VERSION 5.8 ;
BUSBITCHARS "[]" ;
DIVIDERCHAR "/" ;
UNITS
    DATABASE MICRONS 1000 ;
END UNITS

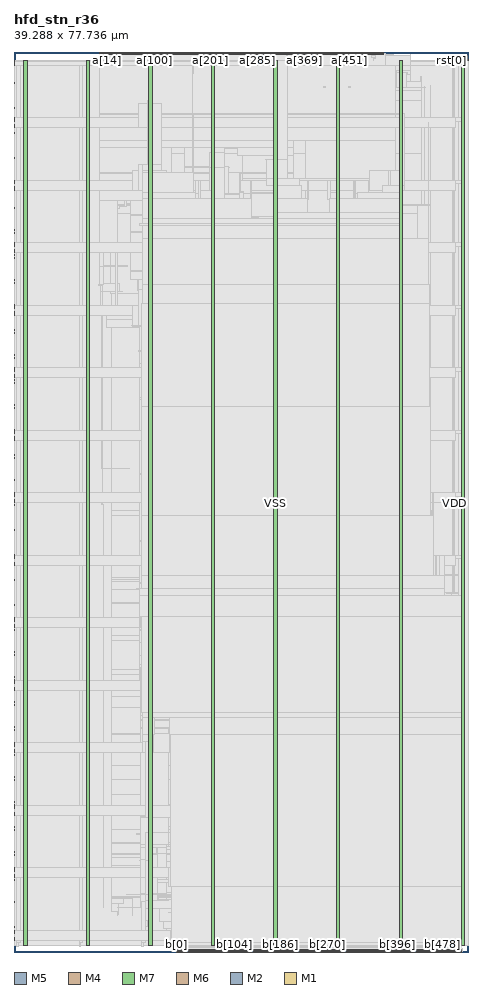
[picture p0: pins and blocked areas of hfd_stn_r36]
MACRO hfd_stn_r36
  FOREIGN hfd_stn_r36 0 0 ;
  CLASS BLOCK ;
  SIZE 39.288 BY 77.736 ;
  PIN a[0]
    DIRECTION INPUT ;
    USE SIGNAL ;
    PORT
      LAYER M5 ;
        RECT  7.344 77.544 7.368 77.736 ;
    END
  END a[0]
  PIN a[100]
    DIRECTION INPUT ;
    USE SIGNAL ;
    PORT
      LAYER M5 ;
        RECT  12.144 77.544 12.168 77.736 ;
    END
  END a[100]
  PIN a[101]
    DIRECTION INPUT ;
    USE SIGNAL ;
    PORT
      LAYER M5 ;
        RECT  12.192 77.544 12.216 77.736 ;
    END
  END a[101]
  PIN a[102]
    DIRECTION INPUT ;
    USE SIGNAL ;
    PORT
      LAYER M5 ;
        RECT  12.24 77.544 12.264 77.736 ;
    END
  END a[102]
  PIN a[103]
    DIRECTION INPUT ;
    USE SIGNAL ;
    PORT
      LAYER M5 ;
        RECT  12.288 77.544 12.312 77.736 ;
    END
  END a[103]
  PIN a[104]
    DIRECTION INPUT ;
    USE SIGNAL ;
    PORT
      LAYER M5 ;
        RECT  12.336 77.544 12.36 77.736 ;
    END
  END a[104]
  PIN a[105]
    DIRECTION INPUT ;
    USE SIGNAL ;
    PORT
      LAYER M5 ;
        RECT  12.384 77.544 12.408 77.736 ;
    END
  END a[105]
  PIN a[106]
    DIRECTION INPUT ;
    USE SIGNAL ;
    PORT
      LAYER M5 ;
        RECT  12.432 77.544 12.456 77.736 ;
    END
  END a[106]
  PIN a[107]
    DIRECTION INPUT ;
    USE SIGNAL ;
    PORT
      LAYER M5 ;
        RECT  12.48 77.544 12.504 77.736 ;
    END
  END a[107]
  PIN a[108]
    DIRECTION INPUT ;
    USE SIGNAL ;
    PORT
      LAYER M5 ;
        RECT  12.528 77.544 12.552 77.736 ;
    END
  END a[108]
  PIN a[109]
    DIRECTION INPUT ;
    USE SIGNAL ;
    PORT
      LAYER M5 ;
        RECT  12.576 77.544 12.6 77.736 ;
    END
  END a[109]
  PIN a[10]
    DIRECTION INPUT ;
    USE SIGNAL ;
    PORT
      LAYER M5 ;
        RECT  7.824 77.544 7.848 77.736 ;
    END
  END a[10]
  PIN a[110]
    DIRECTION INPUT ;
    USE SIGNAL ;
    PORT
      LAYER M5 ;
        RECT  12.624 77.544 12.648 77.736 ;
    END
  END a[110]
  PIN a[111]
    DIRECTION INPUT ;
    USE SIGNAL ;
    PORT
      LAYER M5 ;
        RECT  12.672 77.544 12.696 77.736 ;
    END
  END a[111]
  PIN a[112]
    DIRECTION INPUT ;
    USE SIGNAL ;
    PORT
      LAYER M5 ;
        RECT  12.72 77.544 12.744 77.736 ;
    END
  END a[112]
  PIN a[113]
    DIRECTION INPUT ;
    USE SIGNAL ;
    PORT
      LAYER M5 ;
        RECT  12.768 77.544 12.792 77.736 ;
    END
  END a[113]
  PIN a[114]
    DIRECTION INPUT ;
    USE SIGNAL ;
    PORT
      LAYER M5 ;
        RECT  12.816 77.544 12.84 77.736 ;
    END
  END a[114]
  PIN a[115]
    DIRECTION INPUT ;
    USE SIGNAL ;
    PORT
      LAYER M5 ;
        RECT  12.864 77.544 12.888 77.736 ;
    END
  END a[115]
  PIN a[116]
    DIRECTION INPUT ;
    USE SIGNAL ;
    PORT
      LAYER M5 ;
        RECT  12.912 77.544 12.936 77.736 ;
    END
  END a[116]
  PIN a[117]
    DIRECTION INPUT ;
    USE SIGNAL ;
    PORT
      LAYER M5 ;
        RECT  12.96 77.544 12.984 77.736 ;
    END
  END a[117]
  PIN a[118]
    DIRECTION INPUT ;
    USE SIGNAL ;
    PORT
      LAYER M5 ;
        RECT  13.008 77.544 13.032 77.736 ;
    END
  END a[118]
  PIN a[119]
    DIRECTION INPUT ;
    USE SIGNAL ;
    PORT
      LAYER M5 ;
        RECT  13.056 77.544 13.08 77.736 ;
    END
  END a[119]
  PIN a[11]
    DIRECTION INPUT ;
    USE SIGNAL ;
    PORT
      LAYER M5 ;
        RECT  7.872 77.544 7.896 77.736 ;
    END
  END a[11]
  PIN a[120]
    DIRECTION INPUT ;
    USE SIGNAL ;
    PORT
      LAYER M5 ;
        RECT  13.104 77.544 13.128 77.736 ;
    END
  END a[120]
  PIN a[121]
    DIRECTION INPUT ;
    USE SIGNAL ;
    PORT
      LAYER M5 ;
        RECT  13.152 77.544 13.176 77.736 ;
    END
  END a[121]
  PIN a[122]
    DIRECTION INPUT ;
    USE SIGNAL ;
    PORT
      LAYER M5 ;
        RECT  13.2 77.544 13.224 77.736 ;
    END
  END a[122]
  PIN a[123]
    DIRECTION INPUT ;
    USE SIGNAL ;
    PORT
      LAYER M5 ;
        RECT  13.248 77.544 13.272 77.736 ;
    END
  END a[123]
  PIN a[124]
    DIRECTION INPUT ;
    USE SIGNAL ;
    PORT
      LAYER M5 ;
        RECT  13.296 77.544 13.32 77.736 ;
    END
  END a[124]
  PIN a[125]
    DIRECTION INPUT ;
    USE SIGNAL ;
    PORT
      LAYER M5 ;
        RECT  13.344 77.544 13.368 77.736 ;
    END
  END a[125]
  PIN a[126]
    DIRECTION INPUT ;
    USE SIGNAL ;
    PORT
      LAYER M5 ;
        RECT  13.392 77.544 13.416 77.736 ;
    END
  END a[126]
  PIN a[127]
    DIRECTION INPUT ;
    USE SIGNAL ;
    PORT
      LAYER M5 ;
        RECT  13.44 77.544 13.464 77.736 ;
    END
  END a[127]
  PIN a[128]
    DIRECTION INPUT ;
    USE SIGNAL ;
    PORT
      LAYER M5 ;
        RECT  13.488 77.544 13.512 77.736 ;
    END
  END a[128]
  PIN a[129]
    DIRECTION INPUT ;
    USE SIGNAL ;
    PORT
      LAYER M5 ;
        RECT  13.536 77.544 13.56 77.736 ;
    END
  END a[129]
  PIN a[12]
    DIRECTION INPUT ;
    USE SIGNAL ;
    PORT
      LAYER M5 ;
        RECT  7.92 77.544 7.944 77.736 ;
    END
  END a[12]
  PIN a[130]
    DIRECTION INPUT ;
    USE SIGNAL ;
    PORT
      LAYER M5 ;
        RECT  13.584 77.544 13.608 77.736 ;
    END
  END a[130]
  PIN a[131]
    DIRECTION INPUT ;
    USE SIGNAL ;
    PORT
      LAYER M5 ;
        RECT  13.632 77.544 13.656 77.736 ;
    END
  END a[131]
  PIN a[132]
    DIRECTION INPUT ;
    USE SIGNAL ;
    PORT
      LAYER M5 ;
        RECT  13.68 77.544 13.704 77.736 ;
    END
  END a[132]
  PIN a[133]
    DIRECTION INPUT ;
    USE SIGNAL ;
    PORT
      LAYER M5 ;
        RECT  13.728 77.544 13.752 77.736 ;
    END
  END a[133]
  PIN a[134]
    DIRECTION INPUT ;
    USE SIGNAL ;
    PORT
      LAYER M5 ;
        RECT  13.776 77.544 13.8 77.736 ;
    END
  END a[134]
  PIN a[135]
    DIRECTION INPUT ;
    USE SIGNAL ;
    PORT
      LAYER M5 ;
        RECT  13.824 77.544 13.848 77.736 ;
    END
  END a[135]
  PIN a[136]
    DIRECTION INPUT ;
    USE SIGNAL ;
    PORT
      LAYER M5 ;
        RECT  13.872 77.544 13.896 77.736 ;
    END
  END a[136]
  PIN a[137]
    DIRECTION INPUT ;
    USE SIGNAL ;
    PORT
      LAYER M5 ;
        RECT  13.92 77.544 13.944 77.736 ;
    END
  END a[137]
  PIN a[138]
    DIRECTION INPUT ;
    USE SIGNAL ;
    PORT
      LAYER M5 ;
        RECT  13.968 77.544 13.992 77.736 ;
    END
  END a[138]
  PIN a[139]
    DIRECTION INPUT ;
    USE SIGNAL ;
    PORT
      LAYER M5 ;
        RECT  14.016 77.544 14.04 77.736 ;
    END
  END a[139]
  PIN a[13]
    DIRECTION INPUT ;
    USE SIGNAL ;
    PORT
      LAYER M5 ;
        RECT  7.968 77.544 7.992 77.736 ;
    END
  END a[13]
  PIN a[140]
    DIRECTION INPUT ;
    USE SIGNAL ;
    PORT
      LAYER M5 ;
        RECT  14.064 77.544 14.088 77.736 ;
    END
  END a[140]
  PIN a[141]
    DIRECTION INPUT ;
    USE SIGNAL ;
    PORT
      LAYER M5 ;
        RECT  14.112 77.544 14.136 77.736 ;
    END
  END a[141]
  PIN a[142]
    DIRECTION INPUT ;
    USE SIGNAL ;
    PORT
      LAYER M5 ;
        RECT  14.16 77.544 14.184 77.736 ;
    END
  END a[142]
  PIN a[143]
    DIRECTION INPUT ;
    USE SIGNAL ;
    PORT
      LAYER M5 ;
        RECT  14.208 77.544 14.232 77.736 ;
    END
  END a[143]
  PIN a[144]
    DIRECTION INPUT ;
    USE SIGNAL ;
    PORT
      LAYER M5 ;
        RECT  14.256 77.544 14.28 77.736 ;
    END
  END a[144]
  PIN a[145]
    DIRECTION INPUT ;
    USE SIGNAL ;
    PORT
      LAYER M5 ;
        RECT  14.304 77.544 14.328 77.736 ;
    END
  END a[145]
  PIN a[146]
    DIRECTION INPUT ;
    USE SIGNAL ;
    PORT
      LAYER M5 ;
        RECT  14.352 77.544 14.376 77.736 ;
    END
  END a[146]
  PIN a[147]
    DIRECTION INPUT ;
    USE SIGNAL ;
    PORT
      LAYER M5 ;
        RECT  14.4 77.544 14.424 77.736 ;
    END
  END a[147]
  PIN a[148]
    DIRECTION INPUT ;
    USE SIGNAL ;
    PORT
      LAYER M5 ;
        RECT  14.448 77.544 14.472 77.736 ;
    END
  END a[148]
  PIN a[149]
    DIRECTION INPUT ;
    USE SIGNAL ;
    PORT
      LAYER M5 ;
        RECT  14.496 77.544 14.52 77.736 ;
    END
  END a[149]
  PIN a[14]
    DIRECTION INPUT ;
    USE SIGNAL ;
    PORT
      LAYER M5 ;
        RECT  8.016 77.544 8.04 77.736 ;
    END
  END a[14]
  PIN a[150]
    DIRECTION INPUT ;
    USE SIGNAL ;
    PORT
      LAYER M5 ;
        RECT  14.544 77.544 14.568 77.736 ;
    END
  END a[150]
  PIN a[151]
    DIRECTION INPUT ;
    USE SIGNAL ;
    PORT
      LAYER M5 ;
        RECT  14.592 77.544 14.616 77.736 ;
    END
  END a[151]
  PIN a[152]
    DIRECTION INPUT ;
    USE SIGNAL ;
    PORT
      LAYER M5 ;
        RECT  14.64 77.544 14.664 77.736 ;
    END
  END a[152]
  PIN a[153]
    DIRECTION INPUT ;
    USE SIGNAL ;
    PORT
      LAYER M5 ;
        RECT  14.688 77.544 14.712 77.736 ;
    END
  END a[153]
  PIN a[154]
    DIRECTION INPUT ;
    USE SIGNAL ;
    PORT
      LAYER M5 ;
        RECT  14.736 77.544 14.76 77.736 ;
    END
  END a[154]
  PIN a[155]
    DIRECTION INPUT ;
    USE SIGNAL ;
    PORT
      LAYER M5 ;
        RECT  14.784 77.544 14.808 77.736 ;
    END
  END a[155]
  PIN a[156]
    DIRECTION INPUT ;
    USE SIGNAL ;
    PORT
      LAYER M5 ;
        RECT  14.832 77.544 14.856 77.736 ;
    END
  END a[156]
  PIN a[157]
    DIRECTION INPUT ;
    USE SIGNAL ;
    PORT
      LAYER M5 ;
        RECT  14.88 77.544 14.904 77.736 ;
    END
  END a[157]
  PIN a[158]
    DIRECTION INPUT ;
    USE SIGNAL ;
    PORT
      LAYER M5 ;
        RECT  14.928 77.544 14.952 77.736 ;
    END
  END a[158]
  PIN a[159]
    DIRECTION INPUT ;
    USE SIGNAL ;
    PORT
      LAYER M5 ;
        RECT  14.976 77.544 15 77.736 ;
    END
  END a[159]
  PIN a[15]
    DIRECTION INPUT ;
    USE SIGNAL ;
    PORT
      LAYER M5 ;
        RECT  8.064 77.544 8.088 77.736 ;
    END
  END a[15]
  PIN a[160]
    DIRECTION INPUT ;
    USE SIGNAL ;
    PORT
      LAYER M5 ;
        RECT  15.024 77.544 15.048 77.736 ;
    END
  END a[160]
  PIN a[161]
    DIRECTION INPUT ;
    USE SIGNAL ;
    PORT
      LAYER M5 ;
        RECT  15.072 77.544 15.096 77.736 ;
    END
  END a[161]
  PIN a[162]
    DIRECTION INPUT ;
    USE SIGNAL ;
    PORT
      LAYER M5 ;
        RECT  15.12 77.544 15.144 77.736 ;
    END
  END a[162]
  PIN a[163]
    DIRECTION INPUT ;
    USE SIGNAL ;
    PORT
      LAYER M5 ;
        RECT  15.168 77.544 15.192 77.736 ;
    END
  END a[163]
  PIN a[164]
    DIRECTION INPUT ;
    USE SIGNAL ;
    PORT
      LAYER M5 ;
        RECT  15.216 77.544 15.24 77.736 ;
    END
  END a[164]
  PIN a[165]
    DIRECTION INPUT ;
    USE SIGNAL ;
    PORT
      LAYER M5 ;
        RECT  15.264 77.544 15.288 77.736 ;
    END
  END a[165]
  PIN a[166]
    DIRECTION INPUT ;
    USE SIGNAL ;
    PORT
      LAYER M5 ;
        RECT  15.312 77.544 15.336 77.736 ;
    END
  END a[166]
  PIN a[167]
    DIRECTION INPUT ;
    USE SIGNAL ;
    PORT
      LAYER M5 ;
        RECT  15.36 77.544 15.384 77.736 ;
    END
  END a[167]
  PIN a[168]
    DIRECTION INPUT ;
    USE SIGNAL ;
    PORT
      LAYER M5 ;
        RECT  15.408 77.544 15.432 77.736 ;
    END
  END a[168]
  PIN a[169]
    DIRECTION INPUT ;
    USE SIGNAL ;
    PORT
      LAYER M5 ;
        RECT  15.456 77.544 15.48 77.736 ;
    END
  END a[169]
  PIN a[16]
    DIRECTION INPUT ;
    USE SIGNAL ;
    PORT
      LAYER M5 ;
        RECT  8.112 77.544 8.136 77.736 ;
    END
  END a[16]
  PIN a[170]
    DIRECTION INPUT ;
    USE SIGNAL ;
    PORT
      LAYER M5 ;
        RECT  15.504 77.544 15.528 77.736 ;
    END
  END a[170]
  PIN a[171]
    DIRECTION INPUT ;
    USE SIGNAL ;
    PORT
      LAYER M5 ;
        RECT  15.552 77.544 15.576 77.736 ;
    END
  END a[171]
  PIN a[172]
    DIRECTION INPUT ;
    USE SIGNAL ;
    PORT
      LAYER M5 ;
        RECT  15.6 77.544 15.624 77.736 ;
    END
  END a[172]
  PIN a[173]
    DIRECTION INPUT ;
    USE SIGNAL ;
    PORT
      LAYER M5 ;
        RECT  15.648 77.544 15.672 77.736 ;
    END
  END a[173]
  PIN a[174]
    DIRECTION INPUT ;
    USE SIGNAL ;
    PORT
      LAYER M5 ;
        RECT  15.696 77.544 15.72 77.736 ;
    END
  END a[174]
  PIN a[175]
    DIRECTION INPUT ;
    USE SIGNAL ;
    PORT
      LAYER M5 ;
        RECT  15.744 77.544 15.768 77.736 ;
    END
  END a[175]
  PIN a[176]
    DIRECTION INPUT ;
    USE SIGNAL ;
    PORT
      LAYER M5 ;
        RECT  15.792 77.544 15.816 77.736 ;
    END
  END a[176]
  PIN a[177]
    DIRECTION INPUT ;
    USE SIGNAL ;
    PORT
      LAYER M5 ;
        RECT  15.84 77.544 15.864 77.736 ;
    END
  END a[177]
  PIN a[178]
    DIRECTION INPUT ;
    USE SIGNAL ;
    PORT
      LAYER M5 ;
        RECT  15.888 77.544 15.912 77.736 ;
    END
  END a[178]
  PIN a[179]
    DIRECTION INPUT ;
    USE SIGNAL ;
    PORT
      LAYER M5 ;
        RECT  15.936 77.544 15.96 77.736 ;
    END
  END a[179]
  PIN a[17]
    DIRECTION INPUT ;
    USE SIGNAL ;
    PORT
      LAYER M5 ;
        RECT  8.16 77.544 8.184 77.736 ;
    END
  END a[17]
  PIN a[180]
    DIRECTION INPUT ;
    USE SIGNAL ;
    PORT
      LAYER M5 ;
        RECT  15.984 77.544 16.008 77.736 ;
    END
  END a[180]
  PIN a[181]
    DIRECTION INPUT ;
    USE SIGNAL ;
    PORT
      LAYER M5 ;
        RECT  16.032 77.544 16.056 77.736 ;
    END
  END a[181]
  PIN a[182]
    DIRECTION INPUT ;
    USE SIGNAL ;
    PORT
      LAYER M5 ;
        RECT  16.08 77.544 16.104 77.736 ;
    END
  END a[182]
  PIN a[183]
    DIRECTION INPUT ;
    USE SIGNAL ;
    PORT
      LAYER M5 ;
        RECT  16.128 77.544 16.152 77.736 ;
    END
  END a[183]
  PIN a[184]
    DIRECTION INPUT ;
    USE SIGNAL ;
    PORT
      LAYER M5 ;
        RECT  16.176 77.544 16.2 77.736 ;
    END
  END a[184]
  PIN a[185]
    DIRECTION INPUT ;
    USE SIGNAL ;
    PORT
      LAYER M5 ;
        RECT  16.224 77.544 16.248 77.736 ;
    END
  END a[185]
  PIN a[186]
    DIRECTION INPUT ;
    USE SIGNAL ;
    PORT
      LAYER M5 ;
        RECT  16.272 77.544 16.296 77.736 ;
    END
  END a[186]
  PIN a[187]
    DIRECTION INPUT ;
    USE SIGNAL ;
    PORT
      LAYER M5 ;
        RECT  16.32 77.544 16.344 77.736 ;
    END
  END a[187]
  PIN a[188]
    DIRECTION INPUT ;
    USE SIGNAL ;
    PORT
      LAYER M5 ;
        RECT  16.368 77.544 16.392 77.736 ;
    END
  END a[188]
  PIN a[189]
    DIRECTION INPUT ;
    USE SIGNAL ;
    PORT
      LAYER M5 ;
        RECT  16.416 77.544 16.44 77.736 ;
    END
  END a[189]
  PIN a[18]
    DIRECTION INPUT ;
    USE SIGNAL ;
    PORT
      LAYER M5 ;
        RECT  8.208 77.544 8.232 77.736 ;
    END
  END a[18]
  PIN a[190]
    DIRECTION INPUT ;
    USE SIGNAL ;
    PORT
      LAYER M5 ;
        RECT  16.464 77.544 16.488 77.736 ;
    END
  END a[190]
  PIN a[191]
    DIRECTION INPUT ;
    USE SIGNAL ;
    PORT
      LAYER M5 ;
        RECT  16.512 77.544 16.536 77.736 ;
    END
  END a[191]
  PIN a[192]
    DIRECTION INPUT ;
    USE SIGNAL ;
    PORT
      LAYER M5 ;
        RECT  16.56 77.544 16.584 77.736 ;
    END
  END a[192]
  PIN a[193]
    DIRECTION INPUT ;
    USE SIGNAL ;
    PORT
      LAYER M5 ;
        RECT  16.608 77.544 16.632 77.736 ;
    END
  END a[193]
  PIN a[194]
    DIRECTION INPUT ;
    USE SIGNAL ;
    PORT
      LAYER M5 ;
        RECT  16.656 77.544 16.68 77.736 ;
    END
  END a[194]
  PIN a[195]
    DIRECTION INPUT ;
    USE SIGNAL ;
    PORT
      LAYER M5 ;
        RECT  16.704 77.544 16.728 77.736 ;
    END
  END a[195]
  PIN a[196]
    DIRECTION INPUT ;
    USE SIGNAL ;
    PORT
      LAYER M5 ;
        RECT  16.752 77.544 16.776 77.736 ;
    END
  END a[196]
  PIN a[197]
    DIRECTION INPUT ;
    USE SIGNAL ;
    PORT
      LAYER M5 ;
        RECT  16.8 77.544 16.824 77.736 ;
    END
  END a[197]
  PIN a[198]
    DIRECTION INPUT ;
    USE SIGNAL ;
    PORT
      LAYER M5 ;
        RECT  16.848 77.544 16.872 77.736 ;
    END
  END a[198]
  PIN a[199]
    DIRECTION INPUT ;
    USE SIGNAL ;
    PORT
      LAYER M5 ;
        RECT  16.896 77.544 16.92 77.736 ;
    END
  END a[199]
  PIN a[19]
    DIRECTION INPUT ;
    USE SIGNAL ;
    PORT
      LAYER M5 ;
        RECT  8.256 77.544 8.28 77.736 ;
    END
  END a[19]
  PIN a[1]
    DIRECTION INPUT ;
    USE SIGNAL ;
    PORT
      LAYER M5 ;
        RECT  7.392 77.544 7.416 77.736 ;
    END
  END a[1]
  PIN a[200]
    DIRECTION INPUT ;
    USE SIGNAL ;
    PORT
      LAYER M5 ;
        RECT  16.944 77.544 16.968 77.736 ;
    END
  END a[200]
  PIN a[201]
    DIRECTION INPUT ;
    USE SIGNAL ;
    PORT
      LAYER M5 ;
        RECT  16.992 77.544 17.016 77.736 ;
    END
  END a[201]
  PIN a[202]
    DIRECTION INPUT ;
    USE SIGNAL ;
    PORT
      LAYER M5 ;
        RECT  17.04 77.544 17.064 77.736 ;
    END
  END a[202]
  PIN a[203]
    DIRECTION INPUT ;
    USE SIGNAL ;
    PORT
      LAYER M5 ;
        RECT  17.088 77.544 17.112 77.736 ;
    END
  END a[203]
  PIN a[204]
    DIRECTION INPUT ;
    USE SIGNAL ;
    PORT
      LAYER M5 ;
        RECT  17.136 77.544 17.16 77.736 ;
    END
  END a[204]
  PIN a[205]
    DIRECTION INPUT ;
    USE SIGNAL ;
    PORT
      LAYER M5 ;
        RECT  17.184 77.544 17.208 77.736 ;
    END
  END a[205]
  PIN a[206]
    DIRECTION INPUT ;
    USE SIGNAL ;
    PORT
      LAYER M5 ;
        RECT  17.232 77.544 17.256 77.736 ;
    END
  END a[206]
  PIN a[207]
    DIRECTION INPUT ;
    USE SIGNAL ;
    PORT
      LAYER M5 ;
        RECT  17.28 77.544 17.304 77.736 ;
    END
  END a[207]
  PIN a[208]
    DIRECTION INPUT ;
    USE SIGNAL ;
    PORT
      LAYER M5 ;
        RECT  17.328 77.544 17.352 77.736 ;
    END
  END a[208]
  PIN a[209]
    DIRECTION INPUT ;
    USE SIGNAL ;
    PORT
      LAYER M5 ;
        RECT  17.376 77.544 17.4 77.736 ;
    END
  END a[209]
  PIN a[20]
    DIRECTION INPUT ;
    USE SIGNAL ;
    PORT
      LAYER M5 ;
        RECT  8.304 77.544 8.328 77.736 ;
    END
  END a[20]
  PIN a[210]
    DIRECTION INPUT ;
    USE SIGNAL ;
    PORT
      LAYER M5 ;
        RECT  17.424 77.544 17.448 77.736 ;
    END
  END a[210]
  PIN a[211]
    DIRECTION INPUT ;
    USE SIGNAL ;
    PORT
      LAYER M5 ;
        RECT  17.472 77.544 17.496 77.736 ;
    END
  END a[211]
  PIN a[212]
    DIRECTION INPUT ;
    USE SIGNAL ;
    PORT
      LAYER M5 ;
        RECT  17.52 77.544 17.544 77.736 ;
    END
  END a[212]
  PIN a[213]
    DIRECTION INPUT ;
    USE SIGNAL ;
    PORT
      LAYER M5 ;
        RECT  17.568 77.544 17.592 77.736 ;
    END
  END a[213]
  PIN a[214]
    DIRECTION INPUT ;
    USE SIGNAL ;
    PORT
      LAYER M5 ;
        RECT  17.616 77.544 17.64 77.736 ;
    END
  END a[214]
  PIN a[215]
    DIRECTION INPUT ;
    USE SIGNAL ;
    PORT
      LAYER M5 ;
        RECT  17.664 77.544 17.688 77.736 ;
    END
  END a[215]
  PIN a[216]
    DIRECTION INPUT ;
    USE SIGNAL ;
    PORT
      LAYER M5 ;
        RECT  17.712 77.544 17.736 77.736 ;
    END
  END a[216]
  PIN a[217]
    DIRECTION INPUT ;
    USE SIGNAL ;
    PORT
      LAYER M5 ;
        RECT  17.76 77.544 17.784 77.736 ;
    END
  END a[217]
  PIN a[218]
    DIRECTION INPUT ;
    USE SIGNAL ;
    PORT
      LAYER M5 ;
        RECT  17.808 77.544 17.832 77.736 ;
    END
  END a[218]
  PIN a[219]
    DIRECTION INPUT ;
    USE SIGNAL ;
    PORT
      LAYER M5 ;
        RECT  17.856 77.544 17.88 77.736 ;
    END
  END a[219]
  PIN a[21]
    DIRECTION INPUT ;
    USE SIGNAL ;
    PORT
      LAYER M5 ;
        RECT  8.352 77.544 8.376 77.736 ;
    END
  END a[21]
  PIN a[220]
    DIRECTION INPUT ;
    USE SIGNAL ;
    PORT
      LAYER M5 ;
        RECT  17.904 77.544 17.928 77.736 ;
    END
  END a[220]
  PIN a[221]
    DIRECTION INPUT ;
    USE SIGNAL ;
    PORT
      LAYER M5 ;
        RECT  17.952 77.544 17.976 77.736 ;
    END
  END a[221]
  PIN a[222]
    DIRECTION INPUT ;
    USE SIGNAL ;
    PORT
      LAYER M5 ;
        RECT  18 77.544 18.024 77.736 ;
    END
  END a[222]
  PIN a[223]
    DIRECTION INPUT ;
    USE SIGNAL ;
    PORT
      LAYER M5 ;
        RECT  18.048 77.544 18.072 77.736 ;
    END
  END a[223]
  PIN a[224]
    DIRECTION INPUT ;
    USE SIGNAL ;
    PORT
      LAYER M5 ;
        RECT  18.096 77.544 18.12 77.736 ;
    END
  END a[224]
  PIN a[225]
    DIRECTION INPUT ;
    USE SIGNAL ;
    PORT
      LAYER M5 ;
        RECT  18.144 77.544 18.168 77.736 ;
    END
  END a[225]
  PIN a[226]
    DIRECTION INPUT ;
    USE SIGNAL ;
    PORT
      LAYER M5 ;
        RECT  18.192 77.544 18.216 77.736 ;
    END
  END a[226]
  PIN a[227]
    DIRECTION INPUT ;
    USE SIGNAL ;
    PORT
      LAYER M5 ;
        RECT  18.24 77.544 18.264 77.736 ;
    END
  END a[227]
  PIN a[228]
    DIRECTION INPUT ;
    USE SIGNAL ;
    PORT
      LAYER M5 ;
        RECT  18.288 77.544 18.312 77.736 ;
    END
  END a[228]
  PIN a[229]
    DIRECTION INPUT ;
    USE SIGNAL ;
    PORT
      LAYER M5 ;
        RECT  18.336 77.544 18.36 77.736 ;
    END
  END a[229]
  PIN a[22]
    DIRECTION INPUT ;
    USE SIGNAL ;
    PORT
      LAYER M5 ;
        RECT  8.4 77.544 8.424 77.736 ;
    END
  END a[22]
  PIN a[230]
    DIRECTION INPUT ;
    USE SIGNAL ;
    PORT
      LAYER M5 ;
        RECT  18.384 77.544 18.408 77.736 ;
    END
  END a[230]
  PIN a[231]
    DIRECTION INPUT ;
    USE SIGNAL ;
    PORT
      LAYER M5 ;
        RECT  18.432 77.544 18.456 77.736 ;
    END
  END a[231]
  PIN a[232]
    DIRECTION INPUT ;
    USE SIGNAL ;
    PORT
      LAYER M5 ;
        RECT  18.48 77.544 18.504 77.736 ;
    END
  END a[232]
  PIN a[233]
    DIRECTION INPUT ;
    USE SIGNAL ;
    PORT
      LAYER M5 ;
        RECT  18.528 77.544 18.552 77.736 ;
    END
  END a[233]
  PIN a[234]
    DIRECTION INPUT ;
    USE SIGNAL ;
    PORT
      LAYER M5 ;
        RECT  18.576 77.544 18.6 77.736 ;
    END
  END a[234]
  PIN a[235]
    DIRECTION INPUT ;
    USE SIGNAL ;
    PORT
      LAYER M5 ;
        RECT  18.624 77.544 18.648 77.736 ;
    END
  END a[235]
  PIN a[236]
    DIRECTION INPUT ;
    USE SIGNAL ;
    PORT
      LAYER M5 ;
        RECT  18.672 77.544 18.696 77.736 ;
    END
  END a[236]
  PIN a[237]
    DIRECTION INPUT ;
    USE SIGNAL ;
    PORT
      LAYER M5 ;
        RECT  18.72 77.544 18.744 77.736 ;
    END
  END a[237]
  PIN a[238]
    DIRECTION INPUT ;
    USE SIGNAL ;
    PORT
      LAYER M5 ;
        RECT  18.768 77.544 18.792 77.736 ;
    END
  END a[238]
  PIN a[239]
    DIRECTION INPUT ;
    USE SIGNAL ;
    PORT
      LAYER M5 ;
        RECT  18.816 77.544 18.84 77.736 ;
    END
  END a[239]
  PIN a[23]
    DIRECTION INPUT ;
    USE SIGNAL ;
    PORT
      LAYER M5 ;
        RECT  8.448 77.544 8.472 77.736 ;
    END
  END a[23]
  PIN a[240]
    DIRECTION INPUT ;
    USE SIGNAL ;
    PORT
      LAYER M5 ;
        RECT  18.864 77.544 18.888 77.736 ;
    END
  END a[240]
  PIN a[241]
    DIRECTION INPUT ;
    USE SIGNAL ;
    PORT
      LAYER M5 ;
        RECT  18.912 77.544 18.936 77.736 ;
    END
  END a[241]
  PIN a[242]
    DIRECTION INPUT ;
    USE SIGNAL ;
    PORT
      LAYER M5 ;
        RECT  18.96 77.544 18.984 77.736 ;
    END
  END a[242]
  PIN a[243]
    DIRECTION INPUT ;
    USE SIGNAL ;
    PORT
      LAYER M5 ;
        RECT  19.008 77.544 19.032 77.736 ;
    END
  END a[243]
  PIN a[244]
    DIRECTION INPUT ;
    USE SIGNAL ;
    PORT
      LAYER M5 ;
        RECT  19.056 77.544 19.08 77.736 ;
    END
  END a[244]
  PIN a[245]
    DIRECTION INPUT ;
    USE SIGNAL ;
    PORT
      LAYER M5 ;
        RECT  19.104 77.544 19.128 77.736 ;
    END
  END a[245]
  PIN a[246]
    DIRECTION INPUT ;
    USE SIGNAL ;
    PORT
      LAYER M5 ;
        RECT  19.152 77.544 19.176 77.736 ;
    END
  END a[246]
  PIN a[247]
    DIRECTION INPUT ;
    USE SIGNAL ;
    PORT
      LAYER M5 ;
        RECT  19.2 77.544 19.224 77.736 ;
    END
  END a[247]
  PIN a[248]
    DIRECTION INPUT ;
    USE SIGNAL ;
    PORT
      LAYER M5 ;
        RECT  19.248 77.544 19.272 77.736 ;
    END
  END a[248]
  PIN a[249]
    DIRECTION INPUT ;
    USE SIGNAL ;
    PORT
      LAYER M5 ;
        RECT  19.296 77.544 19.32 77.736 ;
    END
  END a[249]
  PIN a[24]
    DIRECTION INPUT ;
    USE SIGNAL ;
    PORT
      LAYER M5 ;
        RECT  8.496 77.544 8.52 77.736 ;
    END
  END a[24]
  PIN a[250]
    DIRECTION INPUT ;
    USE SIGNAL ;
    PORT
      LAYER M5 ;
        RECT  19.344 77.544 19.368 77.736 ;
    END
  END a[250]
  PIN a[251]
    DIRECTION INPUT ;
    USE SIGNAL ;
    PORT
      LAYER M5 ;
        RECT  19.392 77.544 19.416 77.736 ;
    END
  END a[251]
  PIN a[252]
    DIRECTION INPUT ;
    USE SIGNAL ;
    PORT
      LAYER M5 ;
        RECT  19.44 77.544 19.464 77.736 ;
    END
  END a[252]
  PIN a[253]
    DIRECTION INPUT ;
    USE SIGNAL ;
    PORT
      LAYER M5 ;
        RECT  19.488 77.544 19.512 77.736 ;
    END
  END a[253]
  PIN a[254]
    DIRECTION INPUT ;
    USE SIGNAL ;
    PORT
      LAYER M5 ;
        RECT  19.536 77.544 19.56 77.736 ;
    END
  END a[254]
  PIN a[255]
    DIRECTION INPUT ;
    USE SIGNAL ;
    PORT
      LAYER M5 ;
        RECT  19.584 77.544 19.608 77.736 ;
    END
  END a[255]
  PIN a[256]
    DIRECTION INPUT ;
    USE SIGNAL ;
    PORT
      LAYER M5 ;
        RECT  19.632 77.544 19.656 77.736 ;
    END
  END a[256]
  PIN a[257]
    DIRECTION INPUT ;
    USE SIGNAL ;
    PORT
      LAYER M5 ;
        RECT  19.68 77.544 19.704 77.736 ;
    END
  END a[257]
  PIN a[258]
    DIRECTION INPUT ;
    USE SIGNAL ;
    PORT
      LAYER M5 ;
        RECT  19.728 77.544 19.752 77.736 ;
    END
  END a[258]
  PIN a[259]
    DIRECTION INPUT ;
    USE SIGNAL ;
    PORT
      LAYER M5 ;
        RECT  19.776 77.544 19.8 77.736 ;
    END
  END a[259]
  PIN a[25]
    DIRECTION INPUT ;
    USE SIGNAL ;
    PORT
      LAYER M5 ;
        RECT  8.544 77.544 8.568 77.736 ;
    END
  END a[25]
  PIN a[260]
    DIRECTION INPUT ;
    USE SIGNAL ;
    PORT
      LAYER M5 ;
        RECT  19.824 77.544 19.848 77.736 ;
    END
  END a[260]
  PIN a[261]
    DIRECTION INPUT ;
    USE SIGNAL ;
    PORT
      LAYER M5 ;
        RECT  19.872 77.544 19.896 77.736 ;
    END
  END a[261]
  PIN a[262]
    DIRECTION INPUT ;
    USE SIGNAL ;
    PORT
      LAYER M5 ;
        RECT  19.92 77.544 19.944 77.736 ;
    END
  END a[262]
  PIN a[263]
    DIRECTION INPUT ;
    USE SIGNAL ;
    PORT
      LAYER M5 ;
        RECT  19.968 77.544 19.992 77.736 ;
    END
  END a[263]
  PIN a[264]
    DIRECTION INPUT ;
    USE SIGNAL ;
    PORT
      LAYER M5 ;
        RECT  20.016 77.544 20.04 77.736 ;
    END
  END a[264]
  PIN a[265]
    DIRECTION INPUT ;
    USE SIGNAL ;
    PORT
      LAYER M5 ;
        RECT  20.064 77.544 20.088 77.736 ;
    END
  END a[265]
  PIN a[266]
    DIRECTION INPUT ;
    USE SIGNAL ;
    PORT
      LAYER M5 ;
        RECT  20.112 77.544 20.136 77.736 ;
    END
  END a[266]
  PIN a[267]
    DIRECTION INPUT ;
    USE SIGNAL ;
    PORT
      LAYER M5 ;
        RECT  20.16 77.544 20.184 77.736 ;
    END
  END a[267]
  PIN a[268]
    DIRECTION INPUT ;
    USE SIGNAL ;
    PORT
      LAYER M5 ;
        RECT  20.208 77.544 20.232 77.736 ;
    END
  END a[268]
  PIN a[269]
    DIRECTION INPUT ;
    USE SIGNAL ;
    PORT
      LAYER M5 ;
        RECT  20.256 77.544 20.28 77.736 ;
    END
  END a[269]
  PIN a[26]
    DIRECTION INPUT ;
    USE SIGNAL ;
    PORT
      LAYER M5 ;
        RECT  8.592 77.544 8.616 77.736 ;
    END
  END a[26]
  PIN a[270]
    DIRECTION INPUT ;
    USE SIGNAL ;
    PORT
      LAYER M5 ;
        RECT  20.304 77.544 20.328 77.736 ;
    END
  END a[270]
  PIN a[271]
    DIRECTION INPUT ;
    USE SIGNAL ;
    PORT
      LAYER M5 ;
        RECT  20.352 77.544 20.376 77.736 ;
    END
  END a[271]
  PIN a[272]
    DIRECTION INPUT ;
    USE SIGNAL ;
    PORT
      LAYER M5 ;
        RECT  20.4 77.544 20.424 77.736 ;
    END
  END a[272]
  PIN a[273]
    DIRECTION INPUT ;
    USE SIGNAL ;
    PORT
      LAYER M5 ;
        RECT  20.448 77.544 20.472 77.736 ;
    END
  END a[273]
  PIN a[274]
    DIRECTION INPUT ;
    USE SIGNAL ;
    PORT
      LAYER M5 ;
        RECT  20.496 77.544 20.52 77.736 ;
    END
  END a[274]
  PIN a[275]
    DIRECTION INPUT ;
    USE SIGNAL ;
    PORT
      LAYER M5 ;
        RECT  20.544 77.544 20.568 77.736 ;
    END
  END a[275]
  PIN a[276]
    DIRECTION INPUT ;
    USE SIGNAL ;
    PORT
      LAYER M5 ;
        RECT  20.592 77.544 20.616 77.736 ;
    END
  END a[276]
  PIN a[277]
    DIRECTION INPUT ;
    USE SIGNAL ;
    PORT
      LAYER M5 ;
        RECT  20.64 77.544 20.664 77.736 ;
    END
  END a[277]
  PIN a[278]
    DIRECTION INPUT ;
    USE SIGNAL ;
    PORT
      LAYER M5 ;
        RECT  20.688 77.544 20.712 77.736 ;
    END
  END a[278]
  PIN a[279]
    DIRECTION INPUT ;
    USE SIGNAL ;
    PORT
      LAYER M5 ;
        RECT  20.736 77.544 20.76 77.736 ;
    END
  END a[279]
  PIN a[27]
    DIRECTION INPUT ;
    USE SIGNAL ;
    PORT
      LAYER M5 ;
        RECT  8.64 77.544 8.664 77.736 ;
    END
  END a[27]
  PIN a[280]
    DIRECTION INPUT ;
    USE SIGNAL ;
    PORT
      LAYER M5 ;
        RECT  20.784 77.544 20.808 77.736 ;
    END
  END a[280]
  PIN a[281]
    DIRECTION INPUT ;
    USE SIGNAL ;
    PORT
      LAYER M5 ;
        RECT  20.832 77.544 20.856 77.736 ;
    END
  END a[281]
  PIN a[282]
    DIRECTION INPUT ;
    USE SIGNAL ;
    PORT
      LAYER M5 ;
        RECT  20.88 77.544 20.904 77.736 ;
    END
  END a[282]
  PIN a[283]
    DIRECTION INPUT ;
    USE SIGNAL ;
    PORT
      LAYER M5 ;
        RECT  20.928 77.544 20.952 77.736 ;
    END
  END a[283]
  PIN a[284]
    DIRECTION INPUT ;
    USE SIGNAL ;
    PORT
      LAYER M5 ;
        RECT  20.976 77.544 21 77.736 ;
    END
  END a[284]
  PIN a[285]
    DIRECTION INPUT ;
    USE SIGNAL ;
    PORT
      LAYER M5 ;
        RECT  21.024 77.544 21.048 77.736 ;
    END
  END a[285]
  PIN a[286]
    DIRECTION INPUT ;
    USE SIGNAL ;
    PORT
      LAYER M5 ;
        RECT  21.072 77.544 21.096 77.736 ;
    END
  END a[286]
  PIN a[287]
    DIRECTION INPUT ;
    USE SIGNAL ;
    PORT
      LAYER M5 ;
        RECT  21.12 77.544 21.144 77.736 ;
    END
  END a[287]
  PIN a[288]
    DIRECTION INPUT ;
    USE SIGNAL ;
    PORT
      LAYER M5 ;
        RECT  21.168 77.544 21.192 77.736 ;
    END
  END a[288]
  PIN a[289]
    DIRECTION INPUT ;
    USE SIGNAL ;
    PORT
      LAYER M5 ;
        RECT  21.216 77.544 21.24 77.736 ;
    END
  END a[289]
  PIN a[28]
    DIRECTION INPUT ;
    USE SIGNAL ;
    PORT
      LAYER M5 ;
        RECT  8.688 77.544 8.712 77.736 ;
    END
  END a[28]
  PIN a[290]
    DIRECTION INPUT ;
    USE SIGNAL ;
    PORT
      LAYER M5 ;
        RECT  21.264 77.544 21.288 77.736 ;
    END
  END a[290]
  PIN a[291]
    DIRECTION INPUT ;
    USE SIGNAL ;
    PORT
      LAYER M5 ;
        RECT  21.312 77.544 21.336 77.736 ;
    END
  END a[291]
  PIN a[292]
    DIRECTION INPUT ;
    USE SIGNAL ;
    PORT
      LAYER M5 ;
        RECT  21.36 77.544 21.384 77.736 ;
    END
  END a[292]
  PIN a[293]
    DIRECTION INPUT ;
    USE SIGNAL ;
    PORT
      LAYER M5 ;
        RECT  21.408 77.544 21.432 77.736 ;
    END
  END a[293]
  PIN a[294]
    DIRECTION INPUT ;
    USE SIGNAL ;
    PORT
      LAYER M5 ;
        RECT  21.456 77.544 21.48 77.736 ;
    END
  END a[294]
  PIN a[295]
    DIRECTION INPUT ;
    USE SIGNAL ;
    PORT
      LAYER M5 ;
        RECT  21.504 77.544 21.528 77.736 ;
    END
  END a[295]
  PIN a[296]
    DIRECTION INPUT ;
    USE SIGNAL ;
    PORT
      LAYER M5 ;
        RECT  21.552 77.544 21.576 77.736 ;
    END
  END a[296]
  PIN a[297]
    DIRECTION INPUT ;
    USE SIGNAL ;
    PORT
      LAYER M5 ;
        RECT  21.6 77.544 21.624 77.736 ;
    END
  END a[297]
  PIN a[298]
    DIRECTION INPUT ;
    USE SIGNAL ;
    PORT
      LAYER M5 ;
        RECT  21.648 77.544 21.672 77.736 ;
    END
  END a[298]
  PIN a[299]
    DIRECTION INPUT ;
    USE SIGNAL ;
    PORT
      LAYER M5 ;
        RECT  21.696 77.544 21.72 77.736 ;
    END
  END a[299]
  PIN a[29]
    DIRECTION INPUT ;
    USE SIGNAL ;
    PORT
      LAYER M5 ;
        RECT  8.736 77.544 8.76 77.736 ;
    END
  END a[29]
  PIN a[2]
    DIRECTION INPUT ;
    USE SIGNAL ;
    PORT
      LAYER M5 ;
        RECT  7.44 77.544 7.464 77.736 ;
    END
  END a[2]
  PIN a[300]
    DIRECTION INPUT ;
    USE SIGNAL ;
    PORT
      LAYER M5 ;
        RECT  21.744 77.544 21.768 77.736 ;
    END
  END a[300]
  PIN a[301]
    DIRECTION INPUT ;
    USE SIGNAL ;
    PORT
      LAYER M5 ;
        RECT  21.792 77.544 21.816 77.736 ;
    END
  END a[301]
  PIN a[302]
    DIRECTION INPUT ;
    USE SIGNAL ;
    PORT
      LAYER M5 ;
        RECT  21.84 77.544 21.864 77.736 ;
    END
  END a[302]
  PIN a[303]
    DIRECTION INPUT ;
    USE SIGNAL ;
    PORT
      LAYER M5 ;
        RECT  21.888 77.544 21.912 77.736 ;
    END
  END a[303]
  PIN a[304]
    DIRECTION INPUT ;
    USE SIGNAL ;
    PORT
      LAYER M5 ;
        RECT  21.936 77.544 21.96 77.736 ;
    END
  END a[304]
  PIN a[305]
    DIRECTION INPUT ;
    USE SIGNAL ;
    PORT
      LAYER M5 ;
        RECT  21.984 77.544 22.008 77.736 ;
    END
  END a[305]
  PIN a[306]
    DIRECTION INPUT ;
    USE SIGNAL ;
    PORT
      LAYER M5 ;
        RECT  22.032 77.544 22.056 77.736 ;
    END
  END a[306]
  PIN a[307]
    DIRECTION INPUT ;
    USE SIGNAL ;
    PORT
      LAYER M5 ;
        RECT  22.08 77.544 22.104 77.736 ;
    END
  END a[307]
  PIN a[308]
    DIRECTION INPUT ;
    USE SIGNAL ;
    PORT
      LAYER M5 ;
        RECT  22.128 77.544 22.152 77.736 ;
    END
  END a[308]
  PIN a[309]
    DIRECTION INPUT ;
    USE SIGNAL ;
    PORT
      LAYER M5 ;
        RECT  22.176 77.544 22.2 77.736 ;
    END
  END a[309]
  PIN a[30]
    DIRECTION INPUT ;
    USE SIGNAL ;
    PORT
      LAYER M5 ;
        RECT  8.784 77.544 8.808 77.736 ;
    END
  END a[30]
  PIN a[310]
    DIRECTION INPUT ;
    USE SIGNAL ;
    PORT
      LAYER M5 ;
        RECT  22.224 77.544 22.248 77.736 ;
    END
  END a[310]
  PIN a[311]
    DIRECTION INPUT ;
    USE SIGNAL ;
    PORT
      LAYER M5 ;
        RECT  22.272 77.544 22.296 77.736 ;
    END
  END a[311]
  PIN a[312]
    DIRECTION INPUT ;
    USE SIGNAL ;
    PORT
      LAYER M5 ;
        RECT  22.32 77.544 22.344 77.736 ;
    END
  END a[312]
  PIN a[313]
    DIRECTION INPUT ;
    USE SIGNAL ;
    PORT
      LAYER M5 ;
        RECT  22.368 77.544 22.392 77.736 ;
    END
  END a[313]
  PIN a[314]
    DIRECTION INPUT ;
    USE SIGNAL ;
    PORT
      LAYER M5 ;
        RECT  22.416 77.544 22.44 77.736 ;
    END
  END a[314]
  PIN a[315]
    DIRECTION INPUT ;
    USE SIGNAL ;
    PORT
      LAYER M5 ;
        RECT  22.464 77.544 22.488 77.736 ;
    END
  END a[315]
  PIN a[316]
    DIRECTION INPUT ;
    USE SIGNAL ;
    PORT
      LAYER M5 ;
        RECT  22.512 77.544 22.536 77.736 ;
    END
  END a[316]
  PIN a[317]
    DIRECTION INPUT ;
    USE SIGNAL ;
    PORT
      LAYER M5 ;
        RECT  22.56 77.544 22.584 77.736 ;
    END
  END a[317]
  PIN a[318]
    DIRECTION INPUT ;
    USE SIGNAL ;
    PORT
      LAYER M5 ;
        RECT  22.608 77.544 22.632 77.736 ;
    END
  END a[318]
  PIN a[319]
    DIRECTION INPUT ;
    USE SIGNAL ;
    PORT
      LAYER M5 ;
        RECT  22.656 77.544 22.68 77.736 ;
    END
  END a[319]
  PIN a[31]
    DIRECTION INPUT ;
    USE SIGNAL ;
    PORT
      LAYER M5 ;
        RECT  8.832 77.544 8.856 77.736 ;
    END
  END a[31]
  PIN a[320]
    DIRECTION INPUT ;
    USE SIGNAL ;
    PORT
      LAYER M5 ;
        RECT  22.704 77.544 22.728 77.736 ;
    END
  END a[320]
  PIN a[321]
    DIRECTION INPUT ;
    USE SIGNAL ;
    PORT
      LAYER M5 ;
        RECT  22.752 77.544 22.776 77.736 ;
    END
  END a[321]
  PIN a[322]
    DIRECTION INPUT ;
    USE SIGNAL ;
    PORT
      LAYER M5 ;
        RECT  22.8 77.544 22.824 77.736 ;
    END
  END a[322]
  PIN a[323]
    DIRECTION INPUT ;
    USE SIGNAL ;
    PORT
      LAYER M5 ;
        RECT  22.848 77.544 22.872 77.736 ;
    END
  END a[323]
  PIN a[324]
    DIRECTION INPUT ;
    USE SIGNAL ;
    PORT
      LAYER M5 ;
        RECT  22.896 77.544 22.92 77.736 ;
    END
  END a[324]
  PIN a[325]
    DIRECTION INPUT ;
    USE SIGNAL ;
    PORT
      LAYER M5 ;
        RECT  22.944 77.544 22.968 77.736 ;
    END
  END a[325]
  PIN a[326]
    DIRECTION INPUT ;
    USE SIGNAL ;
    PORT
      LAYER M5 ;
        RECT  22.992 77.544 23.016 77.736 ;
    END
  END a[326]
  PIN a[327]
    DIRECTION INPUT ;
    USE SIGNAL ;
    PORT
      LAYER M5 ;
        RECT  23.04 77.544 23.064 77.736 ;
    END
  END a[327]
  PIN a[328]
    DIRECTION INPUT ;
    USE SIGNAL ;
    PORT
      LAYER M5 ;
        RECT  23.088 77.544 23.112 77.736 ;
    END
  END a[328]
  PIN a[329]
    DIRECTION INPUT ;
    USE SIGNAL ;
    PORT
      LAYER M5 ;
        RECT  23.136 77.544 23.16 77.736 ;
    END
  END a[329]
  PIN a[32]
    DIRECTION INPUT ;
    USE SIGNAL ;
    PORT
      LAYER M5 ;
        RECT  8.88 77.544 8.904 77.736 ;
    END
  END a[32]
  PIN a[330]
    DIRECTION INPUT ;
    USE SIGNAL ;
    PORT
      LAYER M5 ;
        RECT  23.184 77.544 23.208 77.736 ;
    END
  END a[330]
  PIN a[331]
    DIRECTION INPUT ;
    USE SIGNAL ;
    PORT
      LAYER M5 ;
        RECT  23.232 77.544 23.256 77.736 ;
    END
  END a[331]
  PIN a[332]
    DIRECTION INPUT ;
    USE SIGNAL ;
    PORT
      LAYER M5 ;
        RECT  23.28 77.544 23.304 77.736 ;
    END
  END a[332]
  PIN a[333]
    DIRECTION INPUT ;
    USE SIGNAL ;
    PORT
      LAYER M5 ;
        RECT  23.328 77.544 23.352 77.736 ;
    END
  END a[333]
  PIN a[334]
    DIRECTION INPUT ;
    USE SIGNAL ;
    PORT
      LAYER M5 ;
        RECT  23.376 77.544 23.4 77.736 ;
    END
  END a[334]
  PIN a[335]
    DIRECTION INPUT ;
    USE SIGNAL ;
    PORT
      LAYER M5 ;
        RECT  23.424 77.544 23.448 77.736 ;
    END
  END a[335]
  PIN a[336]
    DIRECTION INPUT ;
    USE SIGNAL ;
    PORT
      LAYER M5 ;
        RECT  23.472 77.544 23.496 77.736 ;
    END
  END a[336]
  PIN a[337]
    DIRECTION INPUT ;
    USE SIGNAL ;
    PORT
      LAYER M5 ;
        RECT  23.52 77.544 23.544 77.736 ;
    END
  END a[337]
  PIN a[338]
    DIRECTION INPUT ;
    USE SIGNAL ;
    PORT
      LAYER M5 ;
        RECT  23.568 77.544 23.592 77.736 ;
    END
  END a[338]
  PIN a[339]
    DIRECTION INPUT ;
    USE SIGNAL ;
    PORT
      LAYER M5 ;
        RECT  23.616 77.544 23.64 77.736 ;
    END
  END a[339]
  PIN a[33]
    DIRECTION INPUT ;
    USE SIGNAL ;
    PORT
      LAYER M5 ;
        RECT  8.928 77.544 8.952 77.736 ;
    END
  END a[33]
  PIN a[340]
    DIRECTION INPUT ;
    USE SIGNAL ;
    PORT
      LAYER M5 ;
        RECT  23.664 77.544 23.688 77.736 ;
    END
  END a[340]
  PIN a[341]
    DIRECTION INPUT ;
    USE SIGNAL ;
    PORT
      LAYER M5 ;
        RECT  23.712 77.544 23.736 77.736 ;
    END
  END a[341]
  PIN a[342]
    DIRECTION INPUT ;
    USE SIGNAL ;
    PORT
      LAYER M5 ;
        RECT  23.76 77.544 23.784 77.736 ;
    END
  END a[342]
  PIN a[343]
    DIRECTION INPUT ;
    USE SIGNAL ;
    PORT
      LAYER M5 ;
        RECT  23.808 77.544 23.832 77.736 ;
    END
  END a[343]
  PIN a[344]
    DIRECTION INPUT ;
    USE SIGNAL ;
    PORT
      LAYER M5 ;
        RECT  23.856 77.544 23.88 77.736 ;
    END
  END a[344]
  PIN a[345]
    DIRECTION INPUT ;
    USE SIGNAL ;
    PORT
      LAYER M5 ;
        RECT  23.904 77.544 23.928 77.736 ;
    END
  END a[345]
  PIN a[346]
    DIRECTION INPUT ;
    USE SIGNAL ;
    PORT
      LAYER M5 ;
        RECT  23.952 77.544 23.976 77.736 ;
    END
  END a[346]
  PIN a[347]
    DIRECTION INPUT ;
    USE SIGNAL ;
    PORT
      LAYER M5 ;
        RECT  24 77.544 24.024 77.736 ;
    END
  END a[347]
  PIN a[348]
    DIRECTION INPUT ;
    USE SIGNAL ;
    PORT
      LAYER M5 ;
        RECT  24.048 77.544 24.072 77.736 ;
    END
  END a[348]
  PIN a[349]
    DIRECTION INPUT ;
    USE SIGNAL ;
    PORT
      LAYER M5 ;
        RECT  24.096 77.544 24.12 77.736 ;
    END
  END a[349]
  PIN a[34]
    DIRECTION INPUT ;
    USE SIGNAL ;
    PORT
      LAYER M5 ;
        RECT  8.976 77.544 9 77.736 ;
    END
  END a[34]
  PIN a[350]
    DIRECTION INPUT ;
    USE SIGNAL ;
    PORT
      LAYER M5 ;
        RECT  24.144 77.544 24.168 77.736 ;
    END
  END a[350]
  PIN a[351]
    DIRECTION INPUT ;
    USE SIGNAL ;
    PORT
      LAYER M5 ;
        RECT  24.192 77.544 24.216 77.736 ;
    END
  END a[351]
  PIN a[352]
    DIRECTION INPUT ;
    USE SIGNAL ;
    PORT
      LAYER M5 ;
        RECT  24.24 77.544 24.264 77.736 ;
    END
  END a[352]
  PIN a[353]
    DIRECTION INPUT ;
    USE SIGNAL ;
    PORT
      LAYER M5 ;
        RECT  24.288 77.544 24.312 77.736 ;
    END
  END a[353]
  PIN a[354]
    DIRECTION INPUT ;
    USE SIGNAL ;
    PORT
      LAYER M5 ;
        RECT  24.336 77.544 24.36 77.736 ;
    END
  END a[354]
  PIN a[355]
    DIRECTION INPUT ;
    USE SIGNAL ;
    PORT
      LAYER M5 ;
        RECT  24.384 77.544 24.408 77.736 ;
    END
  END a[355]
  PIN a[356]
    DIRECTION INPUT ;
    USE SIGNAL ;
    PORT
      LAYER M5 ;
        RECT  24.432 77.544 24.456 77.736 ;
    END
  END a[356]
  PIN a[357]
    DIRECTION INPUT ;
    USE SIGNAL ;
    PORT
      LAYER M5 ;
        RECT  24.48 77.544 24.504 77.736 ;
    END
  END a[357]
  PIN a[358]
    DIRECTION INPUT ;
    USE SIGNAL ;
    PORT
      LAYER M5 ;
        RECT  24.528 77.544 24.552 77.736 ;
    END
  END a[358]
  PIN a[359]
    DIRECTION INPUT ;
    USE SIGNAL ;
    PORT
      LAYER M5 ;
        RECT  24.576 77.544 24.6 77.736 ;
    END
  END a[359]
  PIN a[35]
    DIRECTION INPUT ;
    USE SIGNAL ;
    PORT
      LAYER M5 ;
        RECT  9.024 77.544 9.048 77.736 ;
    END
  END a[35]
  PIN a[360]
    DIRECTION INPUT ;
    USE SIGNAL ;
    PORT
      LAYER M5 ;
        RECT  24.624 77.544 24.648 77.736 ;
    END
  END a[360]
  PIN a[361]
    DIRECTION INPUT ;
    USE SIGNAL ;
    PORT
      LAYER M5 ;
        RECT  24.672 77.544 24.696 77.736 ;
    END
  END a[361]
  PIN a[362]
    DIRECTION INPUT ;
    USE SIGNAL ;
    PORT
      LAYER M5 ;
        RECT  24.72 77.544 24.744 77.736 ;
    END
  END a[362]
  PIN a[363]
    DIRECTION INPUT ;
    USE SIGNAL ;
    PORT
      LAYER M5 ;
        RECT  24.768 77.544 24.792 77.736 ;
    END
  END a[363]
  PIN a[364]
    DIRECTION INPUT ;
    USE SIGNAL ;
    PORT
      LAYER M5 ;
        RECT  24.816 77.544 24.84 77.736 ;
    END
  END a[364]
  PIN a[365]
    DIRECTION INPUT ;
    USE SIGNAL ;
    PORT
      LAYER M5 ;
        RECT  24.864 77.544 24.888 77.736 ;
    END
  END a[365]
  PIN a[366]
    DIRECTION INPUT ;
    USE SIGNAL ;
    PORT
      LAYER M5 ;
        RECT  24.912 77.544 24.936 77.736 ;
    END
  END a[366]
  PIN a[367]
    DIRECTION INPUT ;
    USE SIGNAL ;
    PORT
      LAYER M5 ;
        RECT  24.96 77.544 24.984 77.736 ;
    END
  END a[367]
  PIN a[368]
    DIRECTION INPUT ;
    USE SIGNAL ;
    PORT
      LAYER M5 ;
        RECT  25.008 77.544 25.032 77.736 ;
    END
  END a[368]
  PIN a[369]
    DIRECTION INPUT ;
    USE SIGNAL ;
    PORT
      LAYER M5 ;
        RECT  25.056 77.544 25.08 77.736 ;
    END
  END a[369]
  PIN a[36]
    DIRECTION INPUT ;
    USE SIGNAL ;
    PORT
      LAYER M5 ;
        RECT  9.072 77.544 9.096 77.736 ;
    END
  END a[36]
  PIN a[370]
    DIRECTION INPUT ;
    USE SIGNAL ;
    PORT
      LAYER M5 ;
        RECT  25.104 77.544 25.128 77.736 ;
    END
  END a[370]
  PIN a[371]
    DIRECTION INPUT ;
    USE SIGNAL ;
    PORT
      LAYER M5 ;
        RECT  25.152 77.544 25.176 77.736 ;
    END
  END a[371]
  PIN a[372]
    DIRECTION INPUT ;
    USE SIGNAL ;
    PORT
      LAYER M5 ;
        RECT  25.2 77.544 25.224 77.736 ;
    END
  END a[372]
  PIN a[373]
    DIRECTION INPUT ;
    USE SIGNAL ;
    PORT
      LAYER M5 ;
        RECT  25.248 77.544 25.272 77.736 ;
    END
  END a[373]
  PIN a[374]
    DIRECTION INPUT ;
    USE SIGNAL ;
    PORT
      LAYER M5 ;
        RECT  25.296 77.544 25.32 77.736 ;
    END
  END a[374]
  PIN a[375]
    DIRECTION INPUT ;
    USE SIGNAL ;
    PORT
      LAYER M5 ;
        RECT  25.344 77.544 25.368 77.736 ;
    END
  END a[375]
  PIN a[376]
    DIRECTION INPUT ;
    USE SIGNAL ;
    PORT
      LAYER M5 ;
        RECT  25.392 77.544 25.416 77.736 ;
    END
  END a[376]
  PIN a[377]
    DIRECTION INPUT ;
    USE SIGNAL ;
    PORT
      LAYER M5 ;
        RECT  25.44 77.544 25.464 77.736 ;
    END
  END a[377]
  PIN a[378]
    DIRECTION INPUT ;
    USE SIGNAL ;
    PORT
      LAYER M5 ;
        RECT  25.488 77.544 25.512 77.736 ;
    END
  END a[378]
  PIN a[379]
    DIRECTION INPUT ;
    USE SIGNAL ;
    PORT
      LAYER M5 ;
        RECT  25.536 77.544 25.56 77.736 ;
    END
  END a[379]
  PIN a[37]
    DIRECTION INPUT ;
    USE SIGNAL ;
    PORT
      LAYER M5 ;
        RECT  9.12 77.544 9.144 77.736 ;
    END
  END a[37]
  PIN a[380]
    DIRECTION INPUT ;
    USE SIGNAL ;
    PORT
      LAYER M5 ;
        RECT  25.584 77.544 25.608 77.736 ;
    END
  END a[380]
  PIN a[381]
    DIRECTION INPUT ;
    USE SIGNAL ;
    PORT
      LAYER M5 ;
        RECT  25.632 77.544 25.656 77.736 ;
    END
  END a[381]
  PIN a[382]
    DIRECTION INPUT ;
    USE SIGNAL ;
    PORT
      LAYER M5 ;
        RECT  25.68 77.544 25.704 77.736 ;
    END
  END a[382]
  PIN a[383]
    DIRECTION INPUT ;
    USE SIGNAL ;
    PORT
      LAYER M5 ;
        RECT  25.728 77.544 25.752 77.736 ;
    END
  END a[383]
  PIN a[384]
    DIRECTION INPUT ;
    USE SIGNAL ;
    PORT
      LAYER M5 ;
        RECT  25.776 77.544 25.8 77.736 ;
    END
  END a[384]
  PIN a[385]
    DIRECTION INPUT ;
    USE SIGNAL ;
    PORT
      LAYER M5 ;
        RECT  25.824 77.544 25.848 77.736 ;
    END
  END a[385]
  PIN a[386]
    DIRECTION INPUT ;
    USE SIGNAL ;
    PORT
      LAYER M5 ;
        RECT  25.872 77.544 25.896 77.736 ;
    END
  END a[386]
  PIN a[387]
    DIRECTION INPUT ;
    USE SIGNAL ;
    PORT
      LAYER M5 ;
        RECT  25.92 77.544 25.944 77.736 ;
    END
  END a[387]
  PIN a[388]
    DIRECTION INPUT ;
    USE SIGNAL ;
    PORT
      LAYER M5 ;
        RECT  25.968 77.544 25.992 77.736 ;
    END
  END a[388]
  PIN a[389]
    DIRECTION INPUT ;
    USE SIGNAL ;
    PORT
      LAYER M5 ;
        RECT  26.016 77.544 26.04 77.736 ;
    END
  END a[389]
  PIN a[38]
    DIRECTION INPUT ;
    USE SIGNAL ;
    PORT
      LAYER M5 ;
        RECT  9.168 77.544 9.192 77.736 ;
    END
  END a[38]
  PIN a[390]
    DIRECTION INPUT ;
    USE SIGNAL ;
    PORT
      LAYER M5 ;
        RECT  26.064 77.544 26.088 77.736 ;
    END
  END a[390]
  PIN a[391]
    DIRECTION INPUT ;
    USE SIGNAL ;
    PORT
      LAYER M5 ;
        RECT  26.112 77.544 26.136 77.736 ;
    END
  END a[391]
  PIN a[392]
    DIRECTION INPUT ;
    USE SIGNAL ;
    PORT
      LAYER M5 ;
        RECT  26.16 77.544 26.184 77.736 ;
    END
  END a[392]
  PIN a[393]
    DIRECTION INPUT ;
    USE SIGNAL ;
    PORT
      LAYER M5 ;
        RECT  26.208 77.544 26.232 77.736 ;
    END
  END a[393]
  PIN a[394]
    DIRECTION INPUT ;
    USE SIGNAL ;
    PORT
      LAYER M5 ;
        RECT  26.256 77.544 26.28 77.736 ;
    END
  END a[394]
  PIN a[395]
    DIRECTION INPUT ;
    USE SIGNAL ;
    PORT
      LAYER M5 ;
        RECT  26.304 77.544 26.328 77.736 ;
    END
  END a[395]
  PIN a[396]
    DIRECTION INPUT ;
    USE SIGNAL ;
    PORT
      LAYER M5 ;
        RECT  26.352 77.544 26.376 77.736 ;
    END
  END a[396]
  PIN a[397]
    DIRECTION INPUT ;
    USE SIGNAL ;
    PORT
      LAYER M5 ;
        RECT  26.4 77.544 26.424 77.736 ;
    END
  END a[397]
  PIN a[398]
    DIRECTION INPUT ;
    USE SIGNAL ;
    PORT
      LAYER M5 ;
        RECT  26.448 77.544 26.472 77.736 ;
    END
  END a[398]
  PIN a[399]
    DIRECTION INPUT ;
    USE SIGNAL ;
    PORT
      LAYER M5 ;
        RECT  26.496 77.544 26.52 77.736 ;
    END
  END a[399]
  PIN a[39]
    DIRECTION INPUT ;
    USE SIGNAL ;
    PORT
      LAYER M5 ;
        RECT  9.216 77.544 9.24 77.736 ;
    END
  END a[39]
  PIN a[3]
    DIRECTION INPUT ;
    USE SIGNAL ;
    PORT
      LAYER M5 ;
        RECT  7.488 77.544 7.512 77.736 ;
    END
  END a[3]
  PIN a[400]
    DIRECTION INPUT ;
    USE SIGNAL ;
    PORT
      LAYER M5 ;
        RECT  26.544 77.544 26.568 77.736 ;
    END
  END a[400]
  PIN a[401]
    DIRECTION INPUT ;
    USE SIGNAL ;
    PORT
      LAYER M5 ;
        RECT  26.592 77.544 26.616 77.736 ;
    END
  END a[401]
  PIN a[402]
    DIRECTION INPUT ;
    USE SIGNAL ;
    PORT
      LAYER M5 ;
        RECT  26.64 77.544 26.664 77.736 ;
    END
  END a[402]
  PIN a[403]
    DIRECTION INPUT ;
    USE SIGNAL ;
    PORT
      LAYER M5 ;
        RECT  26.688 77.544 26.712 77.736 ;
    END
  END a[403]
  PIN a[404]
    DIRECTION INPUT ;
    USE SIGNAL ;
    PORT
      LAYER M5 ;
        RECT  26.736 77.544 26.76 77.736 ;
    END
  END a[404]
  PIN a[405]
    DIRECTION INPUT ;
    USE SIGNAL ;
    PORT
      LAYER M5 ;
        RECT  26.784 77.544 26.808 77.736 ;
    END
  END a[405]
  PIN a[406]
    DIRECTION INPUT ;
    USE SIGNAL ;
    PORT
      LAYER M5 ;
        RECT  26.832 77.544 26.856 77.736 ;
    END
  END a[406]
  PIN a[407]
    DIRECTION INPUT ;
    USE SIGNAL ;
    PORT
      LAYER M5 ;
        RECT  26.88 77.544 26.904 77.736 ;
    END
  END a[407]
  PIN a[408]
    DIRECTION INPUT ;
    USE SIGNAL ;
    PORT
      LAYER M5 ;
        RECT  26.928 77.544 26.952 77.736 ;
    END
  END a[408]
  PIN a[409]
    DIRECTION INPUT ;
    USE SIGNAL ;
    PORT
      LAYER M5 ;
        RECT  26.976 77.544 27 77.736 ;
    END
  END a[409]
  PIN a[40]
    DIRECTION INPUT ;
    USE SIGNAL ;
    PORT
      LAYER M5 ;
        RECT  9.264 77.544 9.288 77.736 ;
    END
  END a[40]
  PIN a[410]
    DIRECTION INPUT ;
    USE SIGNAL ;
    PORT
      LAYER M5 ;
        RECT  27.024 77.544 27.048 77.736 ;
    END
  END a[410]
  PIN a[411]
    DIRECTION INPUT ;
    USE SIGNAL ;
    PORT
      LAYER M5 ;
        RECT  27.072 77.544 27.096 77.736 ;
    END
  END a[411]
  PIN a[412]
    DIRECTION INPUT ;
    USE SIGNAL ;
    PORT
      LAYER M5 ;
        RECT  27.12 77.544 27.144 77.736 ;
    END
  END a[412]
  PIN a[413]
    DIRECTION INPUT ;
    USE SIGNAL ;
    PORT
      LAYER M5 ;
        RECT  27.168 77.544 27.192 77.736 ;
    END
  END a[413]
  PIN a[414]
    DIRECTION INPUT ;
    USE SIGNAL ;
    PORT
      LAYER M5 ;
        RECT  27.216 77.544 27.24 77.736 ;
    END
  END a[414]
  PIN a[415]
    DIRECTION INPUT ;
    USE SIGNAL ;
    PORT
      LAYER M5 ;
        RECT  27.264 77.544 27.288 77.736 ;
    END
  END a[415]
  PIN a[416]
    DIRECTION INPUT ;
    USE SIGNAL ;
    PORT
      LAYER M5 ;
        RECT  27.312 77.544 27.336 77.736 ;
    END
  END a[416]
  PIN a[417]
    DIRECTION INPUT ;
    USE SIGNAL ;
    PORT
      LAYER M5 ;
        RECT  27.36 77.544 27.384 77.736 ;
    END
  END a[417]
  PIN a[418]
    DIRECTION INPUT ;
    USE SIGNAL ;
    PORT
      LAYER M5 ;
        RECT  27.408 77.544 27.432 77.736 ;
    END
  END a[418]
  PIN a[419]
    DIRECTION INPUT ;
    USE SIGNAL ;
    PORT
      LAYER M5 ;
        RECT  27.456 77.544 27.48 77.736 ;
    END
  END a[419]
  PIN a[41]
    DIRECTION INPUT ;
    USE SIGNAL ;
    PORT
      LAYER M5 ;
        RECT  9.312 77.544 9.336 77.736 ;
    END
  END a[41]
  PIN a[420]
    DIRECTION INPUT ;
    USE SIGNAL ;
    PORT
      LAYER M5 ;
        RECT  27.504 77.544 27.528 77.736 ;
    END
  END a[420]
  PIN a[421]
    DIRECTION INPUT ;
    USE SIGNAL ;
    PORT
      LAYER M5 ;
        RECT  27.552 77.544 27.576 77.736 ;
    END
  END a[421]
  PIN a[422]
    DIRECTION INPUT ;
    USE SIGNAL ;
    PORT
      LAYER M5 ;
        RECT  27.6 77.544 27.624 77.736 ;
    END
  END a[422]
  PIN a[423]
    DIRECTION INPUT ;
    USE SIGNAL ;
    PORT
      LAYER M5 ;
        RECT  27.648 77.544 27.672 77.736 ;
    END
  END a[423]
  PIN a[424]
    DIRECTION INPUT ;
    USE SIGNAL ;
    PORT
      LAYER M5 ;
        RECT  27.696 77.544 27.72 77.736 ;
    END
  END a[424]
  PIN a[425]
    DIRECTION INPUT ;
    USE SIGNAL ;
    PORT
      LAYER M5 ;
        RECT  27.744 77.544 27.768 77.736 ;
    END
  END a[425]
  PIN a[426]
    DIRECTION INPUT ;
    USE SIGNAL ;
    PORT
      LAYER M5 ;
        RECT  27.792 77.544 27.816 77.736 ;
    END
  END a[426]
  PIN a[427]
    DIRECTION INPUT ;
    USE SIGNAL ;
    PORT
      LAYER M5 ;
        RECT  27.84 77.544 27.864 77.736 ;
    END
  END a[427]
  PIN a[428]
    DIRECTION INPUT ;
    USE SIGNAL ;
    PORT
      LAYER M5 ;
        RECT  27.888 77.544 27.912 77.736 ;
    END
  END a[428]
  PIN a[429]
    DIRECTION INPUT ;
    USE SIGNAL ;
    PORT
      LAYER M5 ;
        RECT  27.936 77.544 27.96 77.736 ;
    END
  END a[429]
  PIN a[42]
    DIRECTION INPUT ;
    USE SIGNAL ;
    PORT
      LAYER M5 ;
        RECT  9.36 77.544 9.384 77.736 ;
    END
  END a[42]
  PIN a[430]
    DIRECTION INPUT ;
    USE SIGNAL ;
    PORT
      LAYER M5 ;
        RECT  27.984 77.544 28.008 77.736 ;
    END
  END a[430]
  PIN a[431]
    DIRECTION INPUT ;
    USE SIGNAL ;
    PORT
      LAYER M5 ;
        RECT  28.032 77.544 28.056 77.736 ;
    END
  END a[431]
  PIN a[432]
    DIRECTION INPUT ;
    USE SIGNAL ;
    PORT
      LAYER M5 ;
        RECT  28.08 77.544 28.104 77.736 ;
    END
  END a[432]
  PIN a[433]
    DIRECTION INPUT ;
    USE SIGNAL ;
    PORT
      LAYER M5 ;
        RECT  28.128 77.544 28.152 77.736 ;
    END
  END a[433]
  PIN a[434]
    DIRECTION INPUT ;
    USE SIGNAL ;
    PORT
      LAYER M5 ;
        RECT  28.176 77.544 28.2 77.736 ;
    END
  END a[434]
  PIN a[435]
    DIRECTION INPUT ;
    USE SIGNAL ;
    PORT
      LAYER M5 ;
        RECT  28.224 77.544 28.248 77.736 ;
    END
  END a[435]
  PIN a[436]
    DIRECTION INPUT ;
    USE SIGNAL ;
    PORT
      LAYER M5 ;
        RECT  28.272 77.544 28.296 77.736 ;
    END
  END a[436]
  PIN a[437]
    DIRECTION INPUT ;
    USE SIGNAL ;
    PORT
      LAYER M5 ;
        RECT  28.32 77.544 28.344 77.736 ;
    END
  END a[437]
  PIN a[438]
    DIRECTION INPUT ;
    USE SIGNAL ;
    PORT
      LAYER M5 ;
        RECT  28.368 77.544 28.392 77.736 ;
    END
  END a[438]
  PIN a[439]
    DIRECTION INPUT ;
    USE SIGNAL ;
    PORT
      LAYER M5 ;
        RECT  28.416 77.544 28.44 77.736 ;
    END
  END a[439]
  PIN a[43]
    DIRECTION INPUT ;
    USE SIGNAL ;
    PORT
      LAYER M5 ;
        RECT  9.408 77.544 9.432 77.736 ;
    END
  END a[43]
  PIN a[440]
    DIRECTION INPUT ;
    USE SIGNAL ;
    PORT
      LAYER M5 ;
        RECT  28.464 77.544 28.488 77.736 ;
    END
  END a[440]
  PIN a[441]
    DIRECTION INPUT ;
    USE SIGNAL ;
    PORT
      LAYER M5 ;
        RECT  28.512 77.544 28.536 77.736 ;
    END
  END a[441]
  PIN a[442]
    DIRECTION INPUT ;
    USE SIGNAL ;
    PORT
      LAYER M5 ;
        RECT  28.56 77.544 28.584 77.736 ;
    END
  END a[442]
  PIN a[443]
    DIRECTION INPUT ;
    USE SIGNAL ;
    PORT
      LAYER M5 ;
        RECT  28.608 77.544 28.632 77.736 ;
    END
  END a[443]
  PIN a[444]
    DIRECTION INPUT ;
    USE SIGNAL ;
    PORT
      LAYER M5 ;
        RECT  28.656 77.544 28.68 77.736 ;
    END
  END a[444]
  PIN a[445]
    DIRECTION INPUT ;
    USE SIGNAL ;
    PORT
      LAYER M5 ;
        RECT  28.704 77.544 28.728 77.736 ;
    END
  END a[445]
  PIN a[446]
    DIRECTION INPUT ;
    USE SIGNAL ;
    PORT
      LAYER M5 ;
        RECT  28.752 77.544 28.776 77.736 ;
    END
  END a[446]
  PIN a[447]
    DIRECTION INPUT ;
    USE SIGNAL ;
    PORT
      LAYER M5 ;
        RECT  28.8 77.544 28.824 77.736 ;
    END
  END a[447]
  PIN a[448]
    DIRECTION INPUT ;
    USE SIGNAL ;
    PORT
      LAYER M5 ;
        RECT  28.848 77.544 28.872 77.736 ;
    END
  END a[448]
  PIN a[449]
    DIRECTION INPUT ;
    USE SIGNAL ;
    PORT
      LAYER M5 ;
        RECT  28.896 77.544 28.92 77.736 ;
    END
  END a[449]
  PIN a[44]
    DIRECTION INPUT ;
    USE SIGNAL ;
    PORT
      LAYER M5 ;
        RECT  9.456 77.544 9.48 77.736 ;
    END
  END a[44]
  PIN a[450]
    DIRECTION INPUT ;
    USE SIGNAL ;
    PORT
      LAYER M5 ;
        RECT  28.944 77.544 28.968 77.736 ;
    END
  END a[450]
  PIN a[451]
    DIRECTION INPUT ;
    USE SIGNAL ;
    PORT
      LAYER M5 ;
        RECT  28.992 77.544 29.016 77.736 ;
    END
  END a[451]
  PIN a[452]
    DIRECTION INPUT ;
    USE SIGNAL ;
    PORT
      LAYER M5 ;
        RECT  29.04 77.544 29.064 77.736 ;
    END
  END a[452]
  PIN a[453]
    DIRECTION INPUT ;
    USE SIGNAL ;
    PORT
      LAYER M5 ;
        RECT  29.088 77.544 29.112 77.736 ;
    END
  END a[453]
  PIN a[454]
    DIRECTION INPUT ;
    USE SIGNAL ;
    PORT
      LAYER M5 ;
        RECT  29.136 77.544 29.16 77.736 ;
    END
  END a[454]
  PIN a[455]
    DIRECTION INPUT ;
    USE SIGNAL ;
    PORT
      LAYER M5 ;
        RECT  29.184 77.544 29.208 77.736 ;
    END
  END a[455]
  PIN a[456]
    DIRECTION INPUT ;
    USE SIGNAL ;
    PORT
      LAYER M5 ;
        RECT  29.232 77.544 29.256 77.736 ;
    END
  END a[456]
  PIN a[457]
    DIRECTION INPUT ;
    USE SIGNAL ;
    PORT
      LAYER M5 ;
        RECT  29.28 77.544 29.304 77.736 ;
    END
  END a[457]
  PIN a[458]
    DIRECTION INPUT ;
    USE SIGNAL ;
    PORT
      LAYER M5 ;
        RECT  29.328 77.544 29.352 77.736 ;
    END
  END a[458]
  PIN a[459]
    DIRECTION INPUT ;
    USE SIGNAL ;
    PORT
      LAYER M5 ;
        RECT  29.376 77.544 29.4 77.736 ;
    END
  END a[459]
  PIN a[45]
    DIRECTION INPUT ;
    USE SIGNAL ;
    PORT
      LAYER M5 ;
        RECT  9.504 77.544 9.528 77.736 ;
    END
  END a[45]
  PIN a[460]
    DIRECTION INPUT ;
    USE SIGNAL ;
    PORT
      LAYER M5 ;
        RECT  29.424 77.544 29.448 77.736 ;
    END
  END a[460]
  PIN a[461]
    DIRECTION INPUT ;
    USE SIGNAL ;
    PORT
      LAYER M5 ;
        RECT  29.472 77.544 29.496 77.736 ;
    END
  END a[461]
  PIN a[462]
    DIRECTION INPUT ;
    USE SIGNAL ;
    PORT
      LAYER M5 ;
        RECT  29.52 77.544 29.544 77.736 ;
    END
  END a[462]
  PIN a[463]
    DIRECTION INPUT ;
    USE SIGNAL ;
    PORT
      LAYER M5 ;
        RECT  29.568 77.544 29.592 77.736 ;
    END
  END a[463]
  PIN a[464]
    DIRECTION INPUT ;
    USE SIGNAL ;
    PORT
      LAYER M5 ;
        RECT  29.616 77.544 29.64 77.736 ;
    END
  END a[464]
  PIN a[465]
    DIRECTION INPUT ;
    USE SIGNAL ;
    PORT
      LAYER M5 ;
        RECT  29.664 77.544 29.688 77.736 ;
    END
  END a[465]
  PIN a[466]
    DIRECTION INPUT ;
    USE SIGNAL ;
    PORT
      LAYER M5 ;
        RECT  29.712 77.544 29.736 77.736 ;
    END
  END a[466]
  PIN a[467]
    DIRECTION INPUT ;
    USE SIGNAL ;
    PORT
      LAYER M5 ;
        RECT  29.76 77.544 29.784 77.736 ;
    END
  END a[467]
  PIN a[468]
    DIRECTION INPUT ;
    USE SIGNAL ;
    PORT
      LAYER M5 ;
        RECT  29.808 77.544 29.832 77.736 ;
    END
  END a[468]
  PIN a[469]
    DIRECTION INPUT ;
    USE SIGNAL ;
    PORT
      LAYER M5 ;
        RECT  29.856 77.544 29.88 77.736 ;
    END
  END a[469]
  PIN a[46]
    DIRECTION INPUT ;
    USE SIGNAL ;
    PORT
      LAYER M5 ;
        RECT  9.552 77.544 9.576 77.736 ;
    END
  END a[46]
  PIN a[470]
    DIRECTION INPUT ;
    USE SIGNAL ;
    PORT
      LAYER M5 ;
        RECT  29.904 77.544 29.928 77.736 ;
    END
  END a[470]
  PIN a[471]
    DIRECTION INPUT ;
    USE SIGNAL ;
    PORT
      LAYER M5 ;
        RECT  29.952 77.544 29.976 77.736 ;
    END
  END a[471]
  PIN a[472]
    DIRECTION INPUT ;
    USE SIGNAL ;
    PORT
      LAYER M5 ;
        RECT  30 77.544 30.024 77.736 ;
    END
  END a[472]
  PIN a[473]
    DIRECTION INPUT ;
    USE SIGNAL ;
    PORT
      LAYER M5 ;
        RECT  30.048 77.544 30.072 77.736 ;
    END
  END a[473]
  PIN a[474]
    DIRECTION INPUT ;
    USE SIGNAL ;
    PORT
      LAYER M5 ;
        RECT  30.096 77.544 30.12 77.736 ;
    END
  END a[474]
  PIN a[475]
    DIRECTION INPUT ;
    USE SIGNAL ;
    PORT
      LAYER M5 ;
        RECT  30.144 77.544 30.168 77.736 ;
    END
  END a[475]
  PIN a[476]
    DIRECTION INPUT ;
    USE SIGNAL ;
    PORT
      LAYER M5 ;
        RECT  30.192 77.544 30.216 77.736 ;
    END
  END a[476]
  PIN a[477]
    DIRECTION INPUT ;
    USE SIGNAL ;
    PORT
      LAYER M5 ;
        RECT  30.24 77.544 30.264 77.736 ;
    END
  END a[477]
  PIN a[478]
    DIRECTION INPUT ;
    USE SIGNAL ;
    PORT
      LAYER M5 ;
        RECT  30.288 77.544 30.312 77.736 ;
    END
  END a[478]
  PIN a[479]
    DIRECTION INPUT ;
    USE SIGNAL ;
    PORT
      LAYER M5 ;
        RECT  30.336 77.544 30.36 77.736 ;
    END
  END a[479]
  PIN a[47]
    DIRECTION INPUT ;
    USE SIGNAL ;
    PORT
      LAYER M5 ;
        RECT  9.6 77.544 9.624 77.736 ;
    END
  END a[47]
  PIN a[480]
    DIRECTION INPUT ;
    USE SIGNAL ;
    PORT
      LAYER M5 ;
        RECT  30.384 77.544 30.408 77.736 ;
    END
  END a[480]
  PIN a[481]
    DIRECTION INPUT ;
    USE SIGNAL ;
    PORT
      LAYER M5 ;
        RECT  30.432 77.544 30.456 77.736 ;
    END
  END a[481]
  PIN a[482]
    DIRECTION INPUT ;
    USE SIGNAL ;
    PORT
      LAYER M5 ;
        RECT  30.48 77.544 30.504 77.736 ;
    END
  END a[482]
  PIN a[483]
    DIRECTION INPUT ;
    USE SIGNAL ;
    PORT
      LAYER M5 ;
        RECT  30.528 77.544 30.552 77.736 ;
    END
  END a[483]
  PIN a[484]
    DIRECTION INPUT ;
    USE SIGNAL ;
    PORT
      LAYER M5 ;
        RECT  30.576 77.544 30.6 77.736 ;
    END
  END a[484]
  PIN a[485]
    DIRECTION INPUT ;
    USE SIGNAL ;
    PORT
      LAYER M5 ;
        RECT  30.624 77.544 30.648 77.736 ;
    END
  END a[485]
  PIN a[486]
    DIRECTION INPUT ;
    USE SIGNAL ;
    PORT
      LAYER M5 ;
        RECT  30.672 77.544 30.696 77.736 ;
    END
  END a[486]
  PIN a[487]
    DIRECTION INPUT ;
    USE SIGNAL ;
    PORT
      LAYER M5 ;
        RECT  30.72 77.544 30.744 77.736 ;
    END
  END a[487]
  PIN a[488]
    DIRECTION INPUT ;
    USE SIGNAL ;
    PORT
      LAYER M5 ;
        RECT  30.768 77.544 30.792 77.736 ;
    END
  END a[488]
  PIN a[489]
    DIRECTION INPUT ;
    USE SIGNAL ;
    PORT
      LAYER M5 ;
        RECT  30.816 77.544 30.84 77.736 ;
    END
  END a[489]
  PIN a[48]
    DIRECTION INPUT ;
    USE SIGNAL ;
    PORT
      LAYER M5 ;
        RECT  9.648 77.544 9.672 77.736 ;
    END
  END a[48]
  PIN a[490]
    DIRECTION INPUT ;
    USE SIGNAL ;
    PORT
      LAYER M5 ;
        RECT  30.864 77.544 30.888 77.736 ;
    END
  END a[490]
  PIN a[491]
    DIRECTION INPUT ;
    USE SIGNAL ;
    PORT
      LAYER M5 ;
        RECT  30.912 77.544 30.936 77.736 ;
    END
  END a[491]
  PIN a[492]
    DIRECTION INPUT ;
    USE SIGNAL ;
    PORT
      LAYER M5 ;
        RECT  30.96 77.544 30.984 77.736 ;
    END
  END a[492]
  PIN a[493]
    DIRECTION INPUT ;
    USE SIGNAL ;
    PORT
      LAYER M5 ;
        RECT  31.008 77.544 31.032 77.736 ;
    END
  END a[493]
  PIN a[494]
    DIRECTION INPUT ;
    USE SIGNAL ;
    PORT
      LAYER M5 ;
        RECT  31.056 77.544 31.08 77.736 ;
    END
  END a[494]
  PIN a[495]
    DIRECTION INPUT ;
    USE SIGNAL ;
    PORT
      LAYER M5 ;
        RECT  31.104 77.544 31.128 77.736 ;
    END
  END a[495]
  PIN a[496]
    DIRECTION INPUT ;
    USE SIGNAL ;
    PORT
      LAYER M5 ;
        RECT  31.152 77.544 31.176 77.736 ;
    END
  END a[496]
  PIN a[497]
    DIRECTION INPUT ;
    USE SIGNAL ;
    PORT
      LAYER M5 ;
        RECT  31.2 77.544 31.224 77.736 ;
    END
  END a[497]
  PIN a[498]
    DIRECTION INPUT ;
    USE SIGNAL ;
    PORT
      LAYER M5 ;
        RECT  31.248 77.544 31.272 77.736 ;
    END
  END a[498]
  PIN a[499]
    DIRECTION INPUT ;
    USE SIGNAL ;
    PORT
      LAYER M5 ;
        RECT  31.296 77.544 31.32 77.736 ;
    END
  END a[499]
  PIN a[49]
    DIRECTION INPUT ;
    USE SIGNAL ;
    PORT
      LAYER M5 ;
        RECT  9.696 77.544 9.72 77.736 ;
    END
  END a[49]
  PIN a[4]
    DIRECTION INPUT ;
    USE SIGNAL ;
    PORT
      LAYER M5 ;
        RECT  7.536 77.544 7.56 77.736 ;
    END
  END a[4]
  PIN a[500]
    DIRECTION INPUT ;
    USE SIGNAL ;
    PORT
      LAYER M5 ;
        RECT  31.344 77.544 31.368 77.736 ;
    END
  END a[500]
  PIN a[501]
    DIRECTION INPUT ;
    USE SIGNAL ;
    PORT
      LAYER M5 ;
        RECT  31.392 77.544 31.416 77.736 ;
    END
  END a[501]
  PIN a[502]
    DIRECTION INPUT ;
    USE SIGNAL ;
    PORT
      LAYER M5 ;
        RECT  31.44 77.544 31.464 77.736 ;
    END
  END a[502]
  PIN a[503]
    DIRECTION INPUT ;
    USE SIGNAL ;
    PORT
      LAYER M5 ;
        RECT  31.488 77.544 31.512 77.736 ;
    END
  END a[503]
  PIN a[504]
    DIRECTION INPUT ;
    USE SIGNAL ;
    PORT
      LAYER M5 ;
        RECT  31.536 77.544 31.56 77.736 ;
    END
  END a[504]
  PIN a[505]
    DIRECTION INPUT ;
    USE SIGNAL ;
    PORT
      LAYER M5 ;
        RECT  31.584 77.544 31.608 77.736 ;
    END
  END a[505]
  PIN a[506]
    DIRECTION INPUT ;
    USE SIGNAL ;
    PORT
      LAYER M5 ;
        RECT  31.632 77.544 31.656 77.736 ;
    END
  END a[506]
  PIN a[507]
    DIRECTION INPUT ;
    USE SIGNAL ;
    PORT
      LAYER M5 ;
        RECT  31.68 77.544 31.704 77.736 ;
    END
  END a[507]
  PIN a[508]
    DIRECTION INPUT ;
    USE SIGNAL ;
    PORT
      LAYER M5 ;
        RECT  31.728 77.544 31.752 77.736 ;
    END
  END a[508]
  PIN a[509]
    DIRECTION INPUT ;
    USE SIGNAL ;
    PORT
      LAYER M5 ;
        RECT  31.776 77.544 31.8 77.736 ;
    END
  END a[509]
  PIN a[50]
    DIRECTION INPUT ;
    USE SIGNAL ;
    PORT
      LAYER M5 ;
        RECT  9.744 77.544 9.768 77.736 ;
    END
  END a[50]
  PIN a[510]
    DIRECTION INPUT ;
    USE SIGNAL ;
    PORT
      LAYER M5 ;
        RECT  31.824 77.544 31.848 77.736 ;
    END
  END a[510]
  PIN a[511]
    DIRECTION INPUT ;
    USE SIGNAL ;
    PORT
      LAYER M5 ;
        RECT  31.872 77.544 31.896 77.736 ;
    END
  END a[511]
  PIN a[512]
    DIRECTION INPUT ;
    USE SIGNAL ;
    PORT
      LAYER M5 ;
        RECT  31.92 77.544 31.944 77.736 ;
    END
  END a[512]
  PIN a[51]
    DIRECTION INPUT ;
    USE SIGNAL ;
    PORT
      LAYER M5 ;
        RECT  9.792 77.544 9.816 77.736 ;
    END
  END a[51]
  PIN a[52]
    DIRECTION INPUT ;
    USE SIGNAL ;
    PORT
      LAYER M5 ;
        RECT  9.84 77.544 9.864 77.736 ;
    END
  END a[52]
  PIN a[53]
    DIRECTION INPUT ;
    USE SIGNAL ;
    PORT
      LAYER M5 ;
        RECT  9.888 77.544 9.912 77.736 ;
    END
  END a[53]
  PIN a[54]
    DIRECTION INPUT ;
    USE SIGNAL ;
    PORT
      LAYER M5 ;
        RECT  9.936 77.544 9.96 77.736 ;
    END
  END a[54]
  PIN a[55]
    DIRECTION INPUT ;
    USE SIGNAL ;
    PORT
      LAYER M5 ;
        RECT  9.984 77.544 10.008 77.736 ;
    END
  END a[55]
  PIN a[56]
    DIRECTION INPUT ;
    USE SIGNAL ;
    PORT
      LAYER M5 ;
        RECT  10.032 77.544 10.056 77.736 ;
    END
  END a[56]
  PIN a[57]
    DIRECTION INPUT ;
    USE SIGNAL ;
    PORT
      LAYER M5 ;
        RECT  10.08 77.544 10.104 77.736 ;
    END
  END a[57]
  PIN a[58]
    DIRECTION INPUT ;
    USE SIGNAL ;
    PORT
      LAYER M5 ;
        RECT  10.128 77.544 10.152 77.736 ;
    END
  END a[58]
  PIN a[59]
    DIRECTION INPUT ;
    USE SIGNAL ;
    PORT
      LAYER M5 ;
        RECT  10.176 77.544 10.2 77.736 ;
    END
  END a[59]
  PIN a[5]
    DIRECTION INPUT ;
    USE SIGNAL ;
    PORT
      LAYER M5 ;
        RECT  7.584 77.544 7.608 77.736 ;
    END
  END a[5]
  PIN a[60]
    DIRECTION INPUT ;
    USE SIGNAL ;
    PORT
      LAYER M5 ;
        RECT  10.224 77.544 10.248 77.736 ;
    END
  END a[60]
  PIN a[61]
    DIRECTION INPUT ;
    USE SIGNAL ;
    PORT
      LAYER M5 ;
        RECT  10.272 77.544 10.296 77.736 ;
    END
  END a[61]
  PIN a[62]
    DIRECTION INPUT ;
    USE SIGNAL ;
    PORT
      LAYER M5 ;
        RECT  10.32 77.544 10.344 77.736 ;
    END
  END a[62]
  PIN a[63]
    DIRECTION INPUT ;
    USE SIGNAL ;
    PORT
      LAYER M5 ;
        RECT  10.368 77.544 10.392 77.736 ;
    END
  END a[63]
  PIN a[64]
    DIRECTION INPUT ;
    USE SIGNAL ;
    PORT
      LAYER M5 ;
        RECT  10.416 77.544 10.44 77.736 ;
    END
  END a[64]
  PIN a[65]
    DIRECTION INPUT ;
    USE SIGNAL ;
    PORT
      LAYER M5 ;
        RECT  10.464 77.544 10.488 77.736 ;
    END
  END a[65]
  PIN a[66]
    DIRECTION INPUT ;
    USE SIGNAL ;
    PORT
      LAYER M5 ;
        RECT  10.512 77.544 10.536 77.736 ;
    END
  END a[66]
  PIN a[67]
    DIRECTION INPUT ;
    USE SIGNAL ;
    PORT
      LAYER M5 ;
        RECT  10.56 77.544 10.584 77.736 ;
    END
  END a[67]
  PIN a[68]
    DIRECTION INPUT ;
    USE SIGNAL ;
    PORT
      LAYER M5 ;
        RECT  10.608 77.544 10.632 77.736 ;
    END
  END a[68]
  PIN a[69]
    DIRECTION INPUT ;
    USE SIGNAL ;
    PORT
      LAYER M5 ;
        RECT  10.656 77.544 10.68 77.736 ;
    END
  END a[69]
  PIN a[6]
    DIRECTION INPUT ;
    USE SIGNAL ;
    PORT
      LAYER M5 ;
        RECT  7.632 77.544 7.656 77.736 ;
    END
  END a[6]
  PIN a[70]
    DIRECTION INPUT ;
    USE SIGNAL ;
    PORT
      LAYER M5 ;
        RECT  10.704 77.544 10.728 77.736 ;
    END
  END a[70]
  PIN a[71]
    DIRECTION INPUT ;
    USE SIGNAL ;
    PORT
      LAYER M5 ;
        RECT  10.752 77.544 10.776 77.736 ;
    END
  END a[71]
  PIN a[72]
    DIRECTION INPUT ;
    USE SIGNAL ;
    PORT
      LAYER M5 ;
        RECT  10.8 77.544 10.824 77.736 ;
    END
  END a[72]
  PIN a[73]
    DIRECTION INPUT ;
    USE SIGNAL ;
    PORT
      LAYER M5 ;
        RECT  10.848 77.544 10.872 77.736 ;
    END
  END a[73]
  PIN a[74]
    DIRECTION INPUT ;
    USE SIGNAL ;
    PORT
      LAYER M5 ;
        RECT  10.896 77.544 10.92 77.736 ;
    END
  END a[74]
  PIN a[75]
    DIRECTION INPUT ;
    USE SIGNAL ;
    PORT
      LAYER M5 ;
        RECT  10.944 77.544 10.968 77.736 ;
    END
  END a[75]
  PIN a[76]
    DIRECTION INPUT ;
    USE SIGNAL ;
    PORT
      LAYER M5 ;
        RECT  10.992 77.544 11.016 77.736 ;
    END
  END a[76]
  PIN a[77]
    DIRECTION INPUT ;
    USE SIGNAL ;
    PORT
      LAYER M5 ;
        RECT  11.04 77.544 11.064 77.736 ;
    END
  END a[77]
  PIN a[78]
    DIRECTION INPUT ;
    USE SIGNAL ;
    PORT
      LAYER M5 ;
        RECT  11.088 77.544 11.112 77.736 ;
    END
  END a[78]
  PIN a[79]
    DIRECTION INPUT ;
    USE SIGNAL ;
    PORT
      LAYER M5 ;
        RECT  11.136 77.544 11.16 77.736 ;
    END
  END a[79]
  PIN a[7]
    DIRECTION INPUT ;
    USE SIGNAL ;
    PORT
      LAYER M5 ;
        RECT  7.68 77.544 7.704 77.736 ;
    END
  END a[7]
  PIN a[80]
    DIRECTION INPUT ;
    USE SIGNAL ;
    PORT
      LAYER M5 ;
        RECT  11.184 77.544 11.208 77.736 ;
    END
  END a[80]
  PIN a[81]
    DIRECTION INPUT ;
    USE SIGNAL ;
    PORT
      LAYER M5 ;
        RECT  11.232 77.544 11.256 77.736 ;
    END
  END a[81]
  PIN a[82]
    DIRECTION INPUT ;
    USE SIGNAL ;
    PORT
      LAYER M5 ;
        RECT  11.28 77.544 11.304 77.736 ;
    END
  END a[82]
  PIN a[83]
    DIRECTION INPUT ;
    USE SIGNAL ;
    PORT
      LAYER M5 ;
        RECT  11.328 77.544 11.352 77.736 ;
    END
  END a[83]
  PIN a[84]
    DIRECTION INPUT ;
    USE SIGNAL ;
    PORT
      LAYER M5 ;
        RECT  11.376 77.544 11.4 77.736 ;
    END
  END a[84]
  PIN a[85]
    DIRECTION INPUT ;
    USE SIGNAL ;
    PORT
      LAYER M5 ;
        RECT  11.424 77.544 11.448 77.736 ;
    END
  END a[85]
  PIN a[86]
    DIRECTION INPUT ;
    USE SIGNAL ;
    PORT
      LAYER M5 ;
        RECT  11.472 77.544 11.496 77.736 ;
    END
  END a[86]
  PIN a[87]
    DIRECTION INPUT ;
    USE SIGNAL ;
    PORT
      LAYER M5 ;
        RECT  11.52 77.544 11.544 77.736 ;
    END
  END a[87]
  PIN a[88]
    DIRECTION INPUT ;
    USE SIGNAL ;
    PORT
      LAYER M5 ;
        RECT  11.568 77.544 11.592 77.736 ;
    END
  END a[88]
  PIN a[89]
    DIRECTION INPUT ;
    USE SIGNAL ;
    PORT
      LAYER M5 ;
        RECT  11.616 77.544 11.64 77.736 ;
    END
  END a[89]
  PIN a[8]
    DIRECTION INPUT ;
    USE SIGNAL ;
    PORT
      LAYER M5 ;
        RECT  7.728 77.544 7.752 77.736 ;
    END
  END a[8]
  PIN a[90]
    DIRECTION INPUT ;
    USE SIGNAL ;
    PORT
      LAYER M5 ;
        RECT  11.664 77.544 11.688 77.736 ;
    END
  END a[90]
  PIN a[91]
    DIRECTION INPUT ;
    USE SIGNAL ;
    PORT
      LAYER M5 ;
        RECT  11.712 77.544 11.736 77.736 ;
    END
  END a[91]
  PIN a[92]
    DIRECTION INPUT ;
    USE SIGNAL ;
    PORT
      LAYER M5 ;
        RECT  11.76 77.544 11.784 77.736 ;
    END
  END a[92]
  PIN a[93]
    DIRECTION INPUT ;
    USE SIGNAL ;
    PORT
      LAYER M5 ;
        RECT  11.808 77.544 11.832 77.736 ;
    END
  END a[93]
  PIN a[94]
    DIRECTION INPUT ;
    USE SIGNAL ;
    PORT
      LAYER M5 ;
        RECT  11.856 77.544 11.88 77.736 ;
    END
  END a[94]
  PIN a[95]
    DIRECTION INPUT ;
    USE SIGNAL ;
    PORT
      LAYER M5 ;
        RECT  11.904 77.544 11.928 77.736 ;
    END
  END a[95]
  PIN a[96]
    DIRECTION INPUT ;
    USE SIGNAL ;
    PORT
      LAYER M5 ;
        RECT  11.952 77.544 11.976 77.736 ;
    END
  END a[96]
  PIN a[97]
    DIRECTION INPUT ;
    USE SIGNAL ;
    PORT
      LAYER M5 ;
        RECT  12 77.544 12.024 77.736 ;
    END
  END a[97]
  PIN a[98]
    DIRECTION INPUT ;
    USE SIGNAL ;
    PORT
      LAYER M5 ;
        RECT  12.048 77.544 12.072 77.736 ;
    END
  END a[98]
  PIN a[99]
    DIRECTION INPUT ;
    USE SIGNAL ;
    PORT
      LAYER M5 ;
        RECT  12.096 77.544 12.12 77.736 ;
    END
  END a[99]
  PIN a[9]
    DIRECTION INPUT ;
    USE SIGNAL ;
    PORT
      LAYER M5 ;
        RECT  7.776 77.544 7.8 77.736 ;
    END
  END a[9]
  PIN b[0]
    DIRECTION OUTPUT ;
    USE SIGNAL ;
    PORT
      LAYER M5 ;
        RECT  14.064 0 14.088 0.192 ;
    END
  END b[0]
  PIN b[100]
    DIRECTION OUTPUT ;
    USE SIGNAL ;
    PORT
      LAYER M5 ;
        RECT  18.864 0 18.888 0.192 ;
    END
  END b[100]
  PIN b[101]
    DIRECTION OUTPUT ;
    USE SIGNAL ;
    PORT
      LAYER M5 ;
        RECT  18.912 0 18.936 0.192 ;
    END
  END b[101]
  PIN b[102]
    DIRECTION OUTPUT ;
    USE SIGNAL ;
    PORT
      LAYER M5 ;
        RECT  18.96 0 18.984 0.192 ;
    END
  END b[102]
  PIN b[103]
    DIRECTION OUTPUT ;
    USE SIGNAL ;
    PORT
      LAYER M5 ;
        RECT  19.008 0 19.032 0.192 ;
    END
  END b[103]
  PIN b[104]
    DIRECTION OUTPUT ;
    USE SIGNAL ;
    PORT
      LAYER M5 ;
        RECT  19.056 0 19.08 0.192 ;
    END
  END b[104]
  PIN b[105]
    DIRECTION OUTPUT ;
    USE SIGNAL ;
    PORT
      LAYER M5 ;
        RECT  19.104 0 19.128 0.192 ;
    END
  END b[105]
  PIN b[106]
    DIRECTION OUTPUT ;
    USE SIGNAL ;
    PORT
      LAYER M5 ;
        RECT  19.152 0 19.176 0.192 ;
    END
  END b[106]
  PIN b[107]
    DIRECTION OUTPUT ;
    USE SIGNAL ;
    PORT
      LAYER M5 ;
        RECT  19.2 0 19.224 0.192 ;
    END
  END b[107]
  PIN b[108]
    DIRECTION OUTPUT ;
    USE SIGNAL ;
    PORT
      LAYER M5 ;
        RECT  19.248 0 19.272 0.192 ;
    END
  END b[108]
  PIN b[109]
    DIRECTION OUTPUT ;
    USE SIGNAL ;
    PORT
      LAYER M5 ;
        RECT  19.296 0 19.32 0.192 ;
    END
  END b[109]
  PIN b[10]
    DIRECTION OUTPUT ;
    USE SIGNAL ;
    PORT
      LAYER M5 ;
        RECT  14.544 0 14.568 0.192 ;
    END
  END b[10]
  PIN b[110]
    DIRECTION OUTPUT ;
    USE SIGNAL ;
    PORT
      LAYER M5 ;
        RECT  19.344 0 19.368 0.192 ;
    END
  END b[110]
  PIN b[111]
    DIRECTION OUTPUT ;
    USE SIGNAL ;
    PORT
      LAYER M5 ;
        RECT  19.392 0 19.416 0.192 ;
    END
  END b[111]
  PIN b[112]
    DIRECTION OUTPUT ;
    USE SIGNAL ;
    PORT
      LAYER M5 ;
        RECT  19.44 0 19.464 0.192 ;
    END
  END b[112]
  PIN b[113]
    DIRECTION OUTPUT ;
    USE SIGNAL ;
    PORT
      LAYER M5 ;
        RECT  19.488 0 19.512 0.192 ;
    END
  END b[113]
  PIN b[114]
    DIRECTION OUTPUT ;
    USE SIGNAL ;
    PORT
      LAYER M5 ;
        RECT  19.536 0 19.56 0.192 ;
    END
  END b[114]
  PIN b[115]
    DIRECTION OUTPUT ;
    USE SIGNAL ;
    PORT
      LAYER M5 ;
        RECT  19.584 0 19.608 0.192 ;
    END
  END b[115]
  PIN b[116]
    DIRECTION OUTPUT ;
    USE SIGNAL ;
    PORT
      LAYER M5 ;
        RECT  19.632 0 19.656 0.192 ;
    END
  END b[116]
  PIN b[117]
    DIRECTION OUTPUT ;
    USE SIGNAL ;
    PORT
      LAYER M5 ;
        RECT  19.68 0 19.704 0.192 ;
    END
  END b[117]
  PIN b[118]
    DIRECTION OUTPUT ;
    USE SIGNAL ;
    PORT
      LAYER M5 ;
        RECT  19.728 0 19.752 0.192 ;
    END
  END b[118]
  PIN b[119]
    DIRECTION OUTPUT ;
    USE SIGNAL ;
    PORT
      LAYER M5 ;
        RECT  19.776 0 19.8 0.192 ;
    END
  END b[119]
  PIN b[11]
    DIRECTION OUTPUT ;
    USE SIGNAL ;
    PORT
      LAYER M5 ;
        RECT  14.592 0 14.616 0.192 ;
    END
  END b[11]
  PIN b[120]
    DIRECTION OUTPUT ;
    USE SIGNAL ;
    PORT
      LAYER M5 ;
        RECT  19.824 0 19.848 0.192 ;
    END
  END b[120]
  PIN b[121]
    DIRECTION OUTPUT ;
    USE SIGNAL ;
    PORT
      LAYER M5 ;
        RECT  19.872 0 19.896 0.192 ;
    END
  END b[121]
  PIN b[122]
    DIRECTION OUTPUT ;
    USE SIGNAL ;
    PORT
      LAYER M5 ;
        RECT  19.92 0 19.944 0.192 ;
    END
  END b[122]
  PIN b[123]
    DIRECTION OUTPUT ;
    USE SIGNAL ;
    PORT
      LAYER M5 ;
        RECT  19.968 0 19.992 0.192 ;
    END
  END b[123]
  PIN b[124]
    DIRECTION OUTPUT ;
    USE SIGNAL ;
    PORT
      LAYER M5 ;
        RECT  20.016 0 20.04 0.192 ;
    END
  END b[124]
  PIN b[125]
    DIRECTION OUTPUT ;
    USE SIGNAL ;
    PORT
      LAYER M5 ;
        RECT  20.064 0 20.088 0.192 ;
    END
  END b[125]
  PIN b[126]
    DIRECTION OUTPUT ;
    USE SIGNAL ;
    PORT
      LAYER M5 ;
        RECT  20.112 0 20.136 0.192 ;
    END
  END b[126]
  PIN b[127]
    DIRECTION OUTPUT ;
    USE SIGNAL ;
    PORT
      LAYER M5 ;
        RECT  20.16 0 20.184 0.192 ;
    END
  END b[127]
  PIN b[128]
    DIRECTION OUTPUT ;
    USE SIGNAL ;
    PORT
      LAYER M5 ;
        RECT  20.208 0 20.232 0.192 ;
    END
  END b[128]
  PIN b[129]
    DIRECTION OUTPUT ;
    USE SIGNAL ;
    PORT
      LAYER M5 ;
        RECT  20.256 0 20.28 0.192 ;
    END
  END b[129]
  PIN b[12]
    DIRECTION OUTPUT ;
    USE SIGNAL ;
    PORT
      LAYER M5 ;
        RECT  14.64 0 14.664 0.192 ;
    END
  END b[12]
  PIN b[130]
    DIRECTION OUTPUT ;
    USE SIGNAL ;
    PORT
      LAYER M5 ;
        RECT  20.304 0 20.328 0.192 ;
    END
  END b[130]
  PIN b[131]
    DIRECTION OUTPUT ;
    USE SIGNAL ;
    PORT
      LAYER M5 ;
        RECT  20.352 0 20.376 0.192 ;
    END
  END b[131]
  PIN b[132]
    DIRECTION OUTPUT ;
    USE SIGNAL ;
    PORT
      LAYER M5 ;
        RECT  20.4 0 20.424 0.192 ;
    END
  END b[132]
  PIN b[133]
    DIRECTION OUTPUT ;
    USE SIGNAL ;
    PORT
      LAYER M5 ;
        RECT  20.448 0 20.472 0.192 ;
    END
  END b[133]
  PIN b[134]
    DIRECTION OUTPUT ;
    USE SIGNAL ;
    PORT
      LAYER M5 ;
        RECT  20.496 0 20.52 0.192 ;
    END
  END b[134]
  PIN b[135]
    DIRECTION OUTPUT ;
    USE SIGNAL ;
    PORT
      LAYER M5 ;
        RECT  20.544 0 20.568 0.192 ;
    END
  END b[135]
  PIN b[136]
    DIRECTION OUTPUT ;
    USE SIGNAL ;
    PORT
      LAYER M5 ;
        RECT  20.592 0 20.616 0.192 ;
    END
  END b[136]
  PIN b[137]
    DIRECTION OUTPUT ;
    USE SIGNAL ;
    PORT
      LAYER M5 ;
        RECT  20.64 0 20.664 0.192 ;
    END
  END b[137]
  PIN b[138]
    DIRECTION OUTPUT ;
    USE SIGNAL ;
    PORT
      LAYER M5 ;
        RECT  20.688 0 20.712 0.192 ;
    END
  END b[138]
  PIN b[139]
    DIRECTION OUTPUT ;
    USE SIGNAL ;
    PORT
      LAYER M5 ;
        RECT  20.736 0 20.76 0.192 ;
    END
  END b[139]
  PIN b[13]
    DIRECTION OUTPUT ;
    USE SIGNAL ;
    PORT
      LAYER M5 ;
        RECT  14.688 0 14.712 0.192 ;
    END
  END b[13]
  PIN b[140]
    DIRECTION OUTPUT ;
    USE SIGNAL ;
    PORT
      LAYER M5 ;
        RECT  20.784 0 20.808 0.192 ;
    END
  END b[140]
  PIN b[141]
    DIRECTION OUTPUT ;
    USE SIGNAL ;
    PORT
      LAYER M5 ;
        RECT  20.832 0 20.856 0.192 ;
    END
  END b[141]
  PIN b[142]
    DIRECTION OUTPUT ;
    USE SIGNAL ;
    PORT
      LAYER M5 ;
        RECT  20.88 0 20.904 0.192 ;
    END
  END b[142]
  PIN b[143]
    DIRECTION OUTPUT ;
    USE SIGNAL ;
    PORT
      LAYER M5 ;
        RECT  20.928 0 20.952 0.192 ;
    END
  END b[143]
  PIN b[144]
    DIRECTION OUTPUT ;
    USE SIGNAL ;
    PORT
      LAYER M5 ;
        RECT  20.976 0 21 0.192 ;
    END
  END b[144]
  PIN b[145]
    DIRECTION OUTPUT ;
    USE SIGNAL ;
    PORT
      LAYER M5 ;
        RECT  21.024 0 21.048 0.192 ;
    END
  END b[145]
  PIN b[146]
    DIRECTION OUTPUT ;
    USE SIGNAL ;
    PORT
      LAYER M5 ;
        RECT  21.072 0 21.096 0.192 ;
    END
  END b[146]
  PIN b[147]
    DIRECTION OUTPUT ;
    USE SIGNAL ;
    PORT
      LAYER M5 ;
        RECT  21.12 0 21.144 0.192 ;
    END
  END b[147]
  PIN b[148]
    DIRECTION OUTPUT ;
    USE SIGNAL ;
    PORT
      LAYER M5 ;
        RECT  21.168 0 21.192 0.192 ;
    END
  END b[148]
  PIN b[149]
    DIRECTION OUTPUT ;
    USE SIGNAL ;
    PORT
      LAYER M5 ;
        RECT  21.216 0 21.24 0.192 ;
    END
  END b[149]
  PIN b[14]
    DIRECTION OUTPUT ;
    USE SIGNAL ;
    PORT
      LAYER M5 ;
        RECT  14.736 0 14.76 0.192 ;
    END
  END b[14]
  PIN b[150]
    DIRECTION OUTPUT ;
    USE SIGNAL ;
    PORT
      LAYER M5 ;
        RECT  21.264 0 21.288 0.192 ;
    END
  END b[150]
  PIN b[151]
    DIRECTION OUTPUT ;
    USE SIGNAL ;
    PORT
      LAYER M5 ;
        RECT  21.312 0 21.336 0.192 ;
    END
  END b[151]
  PIN b[152]
    DIRECTION OUTPUT ;
    USE SIGNAL ;
    PORT
      LAYER M5 ;
        RECT  21.36 0 21.384 0.192 ;
    END
  END b[152]
  PIN b[153]
    DIRECTION OUTPUT ;
    USE SIGNAL ;
    PORT
      LAYER M5 ;
        RECT  21.408 0 21.432 0.192 ;
    END
  END b[153]
  PIN b[154]
    DIRECTION OUTPUT ;
    USE SIGNAL ;
    PORT
      LAYER M5 ;
        RECT  21.456 0 21.48 0.192 ;
    END
  END b[154]
  PIN b[155]
    DIRECTION OUTPUT ;
    USE SIGNAL ;
    PORT
      LAYER M5 ;
        RECT  21.504 0 21.528 0.192 ;
    END
  END b[155]
  PIN b[156]
    DIRECTION OUTPUT ;
    USE SIGNAL ;
    PORT
      LAYER M5 ;
        RECT  21.552 0 21.576 0.192 ;
    END
  END b[156]
  PIN b[157]
    DIRECTION OUTPUT ;
    USE SIGNAL ;
    PORT
      LAYER M5 ;
        RECT  21.6 0 21.624 0.192 ;
    END
  END b[157]
  PIN b[158]
    DIRECTION OUTPUT ;
    USE SIGNAL ;
    PORT
      LAYER M5 ;
        RECT  21.648 0 21.672 0.192 ;
    END
  END b[158]
  PIN b[159]
    DIRECTION OUTPUT ;
    USE SIGNAL ;
    PORT
      LAYER M5 ;
        RECT  21.696 0 21.72 0.192 ;
    END
  END b[159]
  PIN b[15]
    DIRECTION OUTPUT ;
    USE SIGNAL ;
    PORT
      LAYER M5 ;
        RECT  14.784 0 14.808 0.192 ;
    END
  END b[15]
  PIN b[160]
    DIRECTION OUTPUT ;
    USE SIGNAL ;
    PORT
      LAYER M5 ;
        RECT  21.744 0 21.768 0.192 ;
    END
  END b[160]
  PIN b[161]
    DIRECTION OUTPUT ;
    USE SIGNAL ;
    PORT
      LAYER M5 ;
        RECT  21.792 0 21.816 0.192 ;
    END
  END b[161]
  PIN b[162]
    DIRECTION OUTPUT ;
    USE SIGNAL ;
    PORT
      LAYER M5 ;
        RECT  21.84 0 21.864 0.192 ;
    END
  END b[162]
  PIN b[163]
    DIRECTION OUTPUT ;
    USE SIGNAL ;
    PORT
      LAYER M5 ;
        RECT  21.888 0 21.912 0.192 ;
    END
  END b[163]
  PIN b[164]
    DIRECTION OUTPUT ;
    USE SIGNAL ;
    PORT
      LAYER M5 ;
        RECT  21.936 0 21.96 0.192 ;
    END
  END b[164]
  PIN b[165]
    DIRECTION OUTPUT ;
    USE SIGNAL ;
    PORT
      LAYER M5 ;
        RECT  21.984 0 22.008 0.192 ;
    END
  END b[165]
  PIN b[166]
    DIRECTION OUTPUT ;
    USE SIGNAL ;
    PORT
      LAYER M5 ;
        RECT  22.032 0 22.056 0.192 ;
    END
  END b[166]
  PIN b[167]
    DIRECTION OUTPUT ;
    USE SIGNAL ;
    PORT
      LAYER M5 ;
        RECT  22.08 0 22.104 0.192 ;
    END
  END b[167]
  PIN b[168]
    DIRECTION OUTPUT ;
    USE SIGNAL ;
    PORT
      LAYER M5 ;
        RECT  22.128 0 22.152 0.192 ;
    END
  END b[168]
  PIN b[169]
    DIRECTION OUTPUT ;
    USE SIGNAL ;
    PORT
      LAYER M5 ;
        RECT  22.176 0 22.2 0.192 ;
    END
  END b[169]
  PIN b[16]
    DIRECTION OUTPUT ;
    USE SIGNAL ;
    PORT
      LAYER M5 ;
        RECT  14.832 0 14.856 0.192 ;
    END
  END b[16]
  PIN b[170]
    DIRECTION OUTPUT ;
    USE SIGNAL ;
    PORT
      LAYER M5 ;
        RECT  22.224 0 22.248 0.192 ;
    END
  END b[170]
  PIN b[171]
    DIRECTION OUTPUT ;
    USE SIGNAL ;
    PORT
      LAYER M5 ;
        RECT  22.272 0 22.296 0.192 ;
    END
  END b[171]
  PIN b[172]
    DIRECTION OUTPUT ;
    USE SIGNAL ;
    PORT
      LAYER M5 ;
        RECT  22.32 0 22.344 0.192 ;
    END
  END b[172]
  PIN b[173]
    DIRECTION OUTPUT ;
    USE SIGNAL ;
    PORT
      LAYER M5 ;
        RECT  22.368 0 22.392 0.192 ;
    END
  END b[173]
  PIN b[174]
    DIRECTION OUTPUT ;
    USE SIGNAL ;
    PORT
      LAYER M5 ;
        RECT  22.416 0 22.44 0.192 ;
    END
  END b[174]
  PIN b[175]
    DIRECTION OUTPUT ;
    USE SIGNAL ;
    PORT
      LAYER M5 ;
        RECT  22.464 0 22.488 0.192 ;
    END
  END b[175]
  PIN b[176]
    DIRECTION OUTPUT ;
    USE SIGNAL ;
    PORT
      LAYER M5 ;
        RECT  22.512 0 22.536 0.192 ;
    END
  END b[176]
  PIN b[177]
    DIRECTION OUTPUT ;
    USE SIGNAL ;
    PORT
      LAYER M5 ;
        RECT  22.56 0 22.584 0.192 ;
    END
  END b[177]
  PIN b[178]
    DIRECTION OUTPUT ;
    USE SIGNAL ;
    PORT
      LAYER M5 ;
        RECT  22.608 0 22.632 0.192 ;
    END
  END b[178]
  PIN b[179]
    DIRECTION OUTPUT ;
    USE SIGNAL ;
    PORT
      LAYER M5 ;
        RECT  22.656 0 22.68 0.192 ;
    END
  END b[179]
  PIN b[17]
    DIRECTION OUTPUT ;
    USE SIGNAL ;
    PORT
      LAYER M5 ;
        RECT  14.88 0 14.904 0.192 ;
    END
  END b[17]
  PIN b[180]
    DIRECTION OUTPUT ;
    USE SIGNAL ;
    PORT
      LAYER M5 ;
        RECT  22.704 0 22.728 0.192 ;
    END
  END b[180]
  PIN b[181]
    DIRECTION OUTPUT ;
    USE SIGNAL ;
    PORT
      LAYER M5 ;
        RECT  22.752 0 22.776 0.192 ;
    END
  END b[181]
  PIN b[182]
    DIRECTION OUTPUT ;
    USE SIGNAL ;
    PORT
      LAYER M5 ;
        RECT  22.8 0 22.824 0.192 ;
    END
  END b[182]
  PIN b[183]
    DIRECTION OUTPUT ;
    USE SIGNAL ;
    PORT
      LAYER M5 ;
        RECT  22.848 0 22.872 0.192 ;
    END
  END b[183]
  PIN b[184]
    DIRECTION OUTPUT ;
    USE SIGNAL ;
    PORT
      LAYER M5 ;
        RECT  22.896 0 22.92 0.192 ;
    END
  END b[184]
  PIN b[185]
    DIRECTION OUTPUT ;
    USE SIGNAL ;
    PORT
      LAYER M5 ;
        RECT  22.944 0 22.968 0.192 ;
    END
  END b[185]
  PIN b[186]
    DIRECTION OUTPUT ;
    USE SIGNAL ;
    PORT
      LAYER M5 ;
        RECT  22.992 0 23.016 0.192 ;
    END
  END b[186]
  PIN b[187]
    DIRECTION OUTPUT ;
    USE SIGNAL ;
    PORT
      LAYER M5 ;
        RECT  23.04 0 23.064 0.192 ;
    END
  END b[187]
  PIN b[188]
    DIRECTION OUTPUT ;
    USE SIGNAL ;
    PORT
      LAYER M5 ;
        RECT  23.088 0 23.112 0.192 ;
    END
  END b[188]
  PIN b[189]
    DIRECTION OUTPUT ;
    USE SIGNAL ;
    PORT
      LAYER M5 ;
        RECT  23.136 0 23.16 0.192 ;
    END
  END b[189]
  PIN b[18]
    DIRECTION OUTPUT ;
    USE SIGNAL ;
    PORT
      LAYER M5 ;
        RECT  14.928 0 14.952 0.192 ;
    END
  END b[18]
  PIN b[190]
    DIRECTION OUTPUT ;
    USE SIGNAL ;
    PORT
      LAYER M5 ;
        RECT  23.184 0 23.208 0.192 ;
    END
  END b[190]
  PIN b[191]
    DIRECTION OUTPUT ;
    USE SIGNAL ;
    PORT
      LAYER M5 ;
        RECT  23.232 0 23.256 0.192 ;
    END
  END b[191]
  PIN b[192]
    DIRECTION OUTPUT ;
    USE SIGNAL ;
    PORT
      LAYER M5 ;
        RECT  23.28 0 23.304 0.192 ;
    END
  END b[192]
  PIN b[193]
    DIRECTION OUTPUT ;
    USE SIGNAL ;
    PORT
      LAYER M5 ;
        RECT  23.328 0 23.352 0.192 ;
    END
  END b[193]
  PIN b[194]
    DIRECTION OUTPUT ;
    USE SIGNAL ;
    PORT
      LAYER M5 ;
        RECT  23.376 0 23.4 0.192 ;
    END
  END b[194]
  PIN b[195]
    DIRECTION OUTPUT ;
    USE SIGNAL ;
    PORT
      LAYER M5 ;
        RECT  23.424 0 23.448 0.192 ;
    END
  END b[195]
  PIN b[196]
    DIRECTION OUTPUT ;
    USE SIGNAL ;
    PORT
      LAYER M5 ;
        RECT  23.472 0 23.496 0.192 ;
    END
  END b[196]
  PIN b[197]
    DIRECTION OUTPUT ;
    USE SIGNAL ;
    PORT
      LAYER M5 ;
        RECT  23.52 0 23.544 0.192 ;
    END
  END b[197]
  PIN b[198]
    DIRECTION OUTPUT ;
    USE SIGNAL ;
    PORT
      LAYER M5 ;
        RECT  23.568 0 23.592 0.192 ;
    END
  END b[198]
  PIN b[199]
    DIRECTION OUTPUT ;
    USE SIGNAL ;
    PORT
      LAYER M5 ;
        RECT  23.616 0 23.64 0.192 ;
    END
  END b[199]
  PIN b[19]
    DIRECTION OUTPUT ;
    USE SIGNAL ;
    PORT
      LAYER M5 ;
        RECT  14.976 0 15 0.192 ;
    END
  END b[19]
  PIN b[1]
    DIRECTION OUTPUT ;
    USE SIGNAL ;
    PORT
      LAYER M5 ;
        RECT  14.112 0 14.136 0.192 ;
    END
  END b[1]
  PIN b[200]
    DIRECTION OUTPUT ;
    USE SIGNAL ;
    PORT
      LAYER M5 ;
        RECT  23.664 0 23.688 0.192 ;
    END
  END b[200]
  PIN b[201]
    DIRECTION OUTPUT ;
    USE SIGNAL ;
    PORT
      LAYER M5 ;
        RECT  23.712 0 23.736 0.192 ;
    END
  END b[201]
  PIN b[202]
    DIRECTION OUTPUT ;
    USE SIGNAL ;
    PORT
      LAYER M5 ;
        RECT  23.76 0 23.784 0.192 ;
    END
  END b[202]
  PIN b[203]
    DIRECTION OUTPUT ;
    USE SIGNAL ;
    PORT
      LAYER M5 ;
        RECT  23.808 0 23.832 0.192 ;
    END
  END b[203]
  PIN b[204]
    DIRECTION OUTPUT ;
    USE SIGNAL ;
    PORT
      LAYER M5 ;
        RECT  23.856 0 23.88 0.192 ;
    END
  END b[204]
  PIN b[205]
    DIRECTION OUTPUT ;
    USE SIGNAL ;
    PORT
      LAYER M5 ;
        RECT  23.904 0 23.928 0.192 ;
    END
  END b[205]
  PIN b[206]
    DIRECTION OUTPUT ;
    USE SIGNAL ;
    PORT
      LAYER M5 ;
        RECT  23.952 0 23.976 0.192 ;
    END
  END b[206]
  PIN b[207]
    DIRECTION OUTPUT ;
    USE SIGNAL ;
    PORT
      LAYER M5 ;
        RECT  24 0 24.024 0.192 ;
    END
  END b[207]
  PIN b[208]
    DIRECTION OUTPUT ;
    USE SIGNAL ;
    PORT
      LAYER M5 ;
        RECT  24.048 0 24.072 0.192 ;
    END
  END b[208]
  PIN b[209]
    DIRECTION OUTPUT ;
    USE SIGNAL ;
    PORT
      LAYER M5 ;
        RECT  24.096 0 24.12 0.192 ;
    END
  END b[209]
  PIN b[20]
    DIRECTION OUTPUT ;
    USE SIGNAL ;
    PORT
      LAYER M5 ;
        RECT  15.024 0 15.048 0.192 ;
    END
  END b[20]
  PIN b[210]
    DIRECTION OUTPUT ;
    USE SIGNAL ;
    PORT
      LAYER M5 ;
        RECT  24.144 0 24.168 0.192 ;
    END
  END b[210]
  PIN b[211]
    DIRECTION OUTPUT ;
    USE SIGNAL ;
    PORT
      LAYER M5 ;
        RECT  24.192 0 24.216 0.192 ;
    END
  END b[211]
  PIN b[212]
    DIRECTION OUTPUT ;
    USE SIGNAL ;
    PORT
      LAYER M5 ;
        RECT  24.24 0 24.264 0.192 ;
    END
  END b[212]
  PIN b[213]
    DIRECTION OUTPUT ;
    USE SIGNAL ;
    PORT
      LAYER M5 ;
        RECT  24.288 0 24.312 0.192 ;
    END
  END b[213]
  PIN b[214]
    DIRECTION OUTPUT ;
    USE SIGNAL ;
    PORT
      LAYER M5 ;
        RECT  24.336 0 24.36 0.192 ;
    END
  END b[214]
  PIN b[215]
    DIRECTION OUTPUT ;
    USE SIGNAL ;
    PORT
      LAYER M5 ;
        RECT  24.384 0 24.408 0.192 ;
    END
  END b[215]
  PIN b[216]
    DIRECTION OUTPUT ;
    USE SIGNAL ;
    PORT
      LAYER M5 ;
        RECT  24.432 0 24.456 0.192 ;
    END
  END b[216]
  PIN b[217]
    DIRECTION OUTPUT ;
    USE SIGNAL ;
    PORT
      LAYER M5 ;
        RECT  24.48 0 24.504 0.192 ;
    END
  END b[217]
  PIN b[218]
    DIRECTION OUTPUT ;
    USE SIGNAL ;
    PORT
      LAYER M5 ;
        RECT  24.528 0 24.552 0.192 ;
    END
  END b[218]
  PIN b[219]
    DIRECTION OUTPUT ;
    USE SIGNAL ;
    PORT
      LAYER M5 ;
        RECT  24.576 0 24.6 0.192 ;
    END
  END b[219]
  PIN b[21]
    DIRECTION OUTPUT ;
    USE SIGNAL ;
    PORT
      LAYER M5 ;
        RECT  15.072 0 15.096 0.192 ;
    END
  END b[21]
  PIN b[220]
    DIRECTION OUTPUT ;
    USE SIGNAL ;
    PORT
      LAYER M5 ;
        RECT  24.624 0 24.648 0.192 ;
    END
  END b[220]
  PIN b[221]
    DIRECTION OUTPUT ;
    USE SIGNAL ;
    PORT
      LAYER M5 ;
        RECT  24.672 0 24.696 0.192 ;
    END
  END b[221]
  PIN b[222]
    DIRECTION OUTPUT ;
    USE SIGNAL ;
    PORT
      LAYER M5 ;
        RECT  24.72 0 24.744 0.192 ;
    END
  END b[222]
  PIN b[223]
    DIRECTION OUTPUT ;
    USE SIGNAL ;
    PORT
      LAYER M5 ;
        RECT  24.768 0 24.792 0.192 ;
    END
  END b[223]
  PIN b[224]
    DIRECTION OUTPUT ;
    USE SIGNAL ;
    PORT
      LAYER M5 ;
        RECT  24.816 0 24.84 0.192 ;
    END
  END b[224]
  PIN b[225]
    DIRECTION OUTPUT ;
    USE SIGNAL ;
    PORT
      LAYER M5 ;
        RECT  24.864 0 24.888 0.192 ;
    END
  END b[225]
  PIN b[226]
    DIRECTION OUTPUT ;
    USE SIGNAL ;
    PORT
      LAYER M5 ;
        RECT  24.912 0 24.936 0.192 ;
    END
  END b[226]
  PIN b[227]
    DIRECTION OUTPUT ;
    USE SIGNAL ;
    PORT
      LAYER M5 ;
        RECT  24.96 0 24.984 0.192 ;
    END
  END b[227]
  PIN b[228]
    DIRECTION OUTPUT ;
    USE SIGNAL ;
    PORT
      LAYER M5 ;
        RECT  25.008 0 25.032 0.192 ;
    END
  END b[228]
  PIN b[229]
    DIRECTION OUTPUT ;
    USE SIGNAL ;
    PORT
      LAYER M5 ;
        RECT  25.056 0 25.08 0.192 ;
    END
  END b[229]
  PIN b[22]
    DIRECTION OUTPUT ;
    USE SIGNAL ;
    PORT
      LAYER M5 ;
        RECT  15.12 0 15.144 0.192 ;
    END
  END b[22]
  PIN b[230]
    DIRECTION OUTPUT ;
    USE SIGNAL ;
    PORT
      LAYER M5 ;
        RECT  25.104 0 25.128 0.192 ;
    END
  END b[230]
  PIN b[231]
    DIRECTION OUTPUT ;
    USE SIGNAL ;
    PORT
      LAYER M5 ;
        RECT  25.152 0 25.176 0.192 ;
    END
  END b[231]
  PIN b[232]
    DIRECTION OUTPUT ;
    USE SIGNAL ;
    PORT
      LAYER M5 ;
        RECT  25.2 0 25.224 0.192 ;
    END
  END b[232]
  PIN b[233]
    DIRECTION OUTPUT ;
    USE SIGNAL ;
    PORT
      LAYER M5 ;
        RECT  25.248 0 25.272 0.192 ;
    END
  END b[233]
  PIN b[234]
    DIRECTION OUTPUT ;
    USE SIGNAL ;
    PORT
      LAYER M5 ;
        RECT  25.296 0 25.32 0.192 ;
    END
  END b[234]
  PIN b[235]
    DIRECTION OUTPUT ;
    USE SIGNAL ;
    PORT
      LAYER M5 ;
        RECT  25.344 0 25.368 0.192 ;
    END
  END b[235]
  PIN b[236]
    DIRECTION OUTPUT ;
    USE SIGNAL ;
    PORT
      LAYER M5 ;
        RECT  25.392 0 25.416 0.192 ;
    END
  END b[236]
  PIN b[237]
    DIRECTION OUTPUT ;
    USE SIGNAL ;
    PORT
      LAYER M5 ;
        RECT  25.44 0 25.464 0.192 ;
    END
  END b[237]
  PIN b[238]
    DIRECTION OUTPUT ;
    USE SIGNAL ;
    PORT
      LAYER M5 ;
        RECT  25.488 0 25.512 0.192 ;
    END
  END b[238]
  PIN b[239]
    DIRECTION OUTPUT ;
    USE SIGNAL ;
    PORT
      LAYER M5 ;
        RECT  25.536 0 25.56 0.192 ;
    END
  END b[239]
  PIN b[23]
    DIRECTION OUTPUT ;
    USE SIGNAL ;
    PORT
      LAYER M5 ;
        RECT  15.168 0 15.192 0.192 ;
    END
  END b[23]
  PIN b[240]
    DIRECTION OUTPUT ;
    USE SIGNAL ;
    PORT
      LAYER M5 ;
        RECT  25.584 0 25.608 0.192 ;
    END
  END b[240]
  PIN b[241]
    DIRECTION OUTPUT ;
    USE SIGNAL ;
    PORT
      LAYER M5 ;
        RECT  25.632 0 25.656 0.192 ;
    END
  END b[241]
  PIN b[242]
    DIRECTION OUTPUT ;
    USE SIGNAL ;
    PORT
      LAYER M5 ;
        RECT  25.68 0 25.704 0.192 ;
    END
  END b[242]
  PIN b[243]
    DIRECTION OUTPUT ;
    USE SIGNAL ;
    PORT
      LAYER M5 ;
        RECT  25.728 0 25.752 0.192 ;
    END
  END b[243]
  PIN b[244]
    DIRECTION OUTPUT ;
    USE SIGNAL ;
    PORT
      LAYER M5 ;
        RECT  25.776 0 25.8 0.192 ;
    END
  END b[244]
  PIN b[245]
    DIRECTION OUTPUT ;
    USE SIGNAL ;
    PORT
      LAYER M5 ;
        RECT  25.824 0 25.848 0.192 ;
    END
  END b[245]
  PIN b[246]
    DIRECTION OUTPUT ;
    USE SIGNAL ;
    PORT
      LAYER M5 ;
        RECT  25.872 0 25.896 0.192 ;
    END
  END b[246]
  PIN b[247]
    DIRECTION OUTPUT ;
    USE SIGNAL ;
    PORT
      LAYER M5 ;
        RECT  25.92 0 25.944 0.192 ;
    END
  END b[247]
  PIN b[248]
    DIRECTION OUTPUT ;
    USE SIGNAL ;
    PORT
      LAYER M5 ;
        RECT  25.968 0 25.992 0.192 ;
    END
  END b[248]
  PIN b[249]
    DIRECTION OUTPUT ;
    USE SIGNAL ;
    PORT
      LAYER M5 ;
        RECT  26.016 0 26.04 0.192 ;
    END
  END b[249]
  PIN b[24]
    DIRECTION OUTPUT ;
    USE SIGNAL ;
    PORT
      LAYER M5 ;
        RECT  15.216 0 15.24 0.192 ;
    END
  END b[24]
  PIN b[250]
    DIRECTION OUTPUT ;
    USE SIGNAL ;
    PORT
      LAYER M5 ;
        RECT  26.064 0 26.088 0.192 ;
    END
  END b[250]
  PIN b[251]
    DIRECTION OUTPUT ;
    USE SIGNAL ;
    PORT
      LAYER M5 ;
        RECT  26.112 0 26.136 0.192 ;
    END
  END b[251]
  PIN b[252]
    DIRECTION OUTPUT ;
    USE SIGNAL ;
    PORT
      LAYER M5 ;
        RECT  26.16 0 26.184 0.192 ;
    END
  END b[252]
  PIN b[253]
    DIRECTION OUTPUT ;
    USE SIGNAL ;
    PORT
      LAYER M5 ;
        RECT  26.208 0 26.232 0.192 ;
    END
  END b[253]
  PIN b[254]
    DIRECTION OUTPUT ;
    USE SIGNAL ;
    PORT
      LAYER M5 ;
        RECT  26.256 0 26.28 0.192 ;
    END
  END b[254]
  PIN b[255]
    DIRECTION OUTPUT ;
    USE SIGNAL ;
    PORT
      LAYER M5 ;
        RECT  26.304 0 26.328 0.192 ;
    END
  END b[255]
  PIN b[256]
    DIRECTION OUTPUT ;
    USE SIGNAL ;
    PORT
      LAYER M5 ;
        RECT  26.352 0 26.376 0.192 ;
    END
  END b[256]
  PIN b[257]
    DIRECTION OUTPUT ;
    USE SIGNAL ;
    PORT
      LAYER M5 ;
        RECT  26.4 0 26.424 0.192 ;
    END
  END b[257]
  PIN b[258]
    DIRECTION OUTPUT ;
    USE SIGNAL ;
    PORT
      LAYER M5 ;
        RECT  26.448 0 26.472 0.192 ;
    END
  END b[258]
  PIN b[259]
    DIRECTION OUTPUT ;
    USE SIGNAL ;
    PORT
      LAYER M5 ;
        RECT  26.496 0 26.52 0.192 ;
    END
  END b[259]
  PIN b[25]
    DIRECTION OUTPUT ;
    USE SIGNAL ;
    PORT
      LAYER M5 ;
        RECT  15.264 0 15.288 0.192 ;
    END
  END b[25]
  PIN b[260]
    DIRECTION OUTPUT ;
    USE SIGNAL ;
    PORT
      LAYER M5 ;
        RECT  26.544 0 26.568 0.192 ;
    END
  END b[260]
  PIN b[261]
    DIRECTION OUTPUT ;
    USE SIGNAL ;
    PORT
      LAYER M5 ;
        RECT  26.592 0 26.616 0.192 ;
    END
  END b[261]
  PIN b[262]
    DIRECTION OUTPUT ;
    USE SIGNAL ;
    PORT
      LAYER M5 ;
        RECT  26.64 0 26.664 0.192 ;
    END
  END b[262]
  PIN b[263]
    DIRECTION OUTPUT ;
    USE SIGNAL ;
    PORT
      LAYER M5 ;
        RECT  26.688 0 26.712 0.192 ;
    END
  END b[263]
  PIN b[264]
    DIRECTION OUTPUT ;
    USE SIGNAL ;
    PORT
      LAYER M5 ;
        RECT  26.736 0 26.76 0.192 ;
    END
  END b[264]
  PIN b[265]
    DIRECTION OUTPUT ;
    USE SIGNAL ;
    PORT
      LAYER M5 ;
        RECT  26.784 0 26.808 0.192 ;
    END
  END b[265]
  PIN b[266]
    DIRECTION OUTPUT ;
    USE SIGNAL ;
    PORT
      LAYER M5 ;
        RECT  26.832 0 26.856 0.192 ;
    END
  END b[266]
  PIN b[267]
    DIRECTION OUTPUT ;
    USE SIGNAL ;
    PORT
      LAYER M5 ;
        RECT  26.88 0 26.904 0.192 ;
    END
  END b[267]
  PIN b[268]
    DIRECTION OUTPUT ;
    USE SIGNAL ;
    PORT
      LAYER M5 ;
        RECT  26.928 0 26.952 0.192 ;
    END
  END b[268]
  PIN b[269]
    DIRECTION OUTPUT ;
    USE SIGNAL ;
    PORT
      LAYER M5 ;
        RECT  26.976 0 27 0.192 ;
    END
  END b[269]
  PIN b[26]
    DIRECTION OUTPUT ;
    USE SIGNAL ;
    PORT
      LAYER M5 ;
        RECT  15.312 0 15.336 0.192 ;
    END
  END b[26]
  PIN b[270]
    DIRECTION OUTPUT ;
    USE SIGNAL ;
    PORT
      LAYER M5 ;
        RECT  27.024 0 27.048 0.192 ;
    END
  END b[270]
  PIN b[271]
    DIRECTION OUTPUT ;
    USE SIGNAL ;
    PORT
      LAYER M5 ;
        RECT  27.072 0 27.096 0.192 ;
    END
  END b[271]
  PIN b[272]
    DIRECTION OUTPUT ;
    USE SIGNAL ;
    PORT
      LAYER M5 ;
        RECT  27.12 0 27.144 0.192 ;
    END
  END b[272]
  PIN b[273]
    DIRECTION OUTPUT ;
    USE SIGNAL ;
    PORT
      LAYER M5 ;
        RECT  27.168 0 27.192 0.192 ;
    END
  END b[273]
  PIN b[274]
    DIRECTION OUTPUT ;
    USE SIGNAL ;
    PORT
      LAYER M5 ;
        RECT  27.216 0 27.24 0.192 ;
    END
  END b[274]
  PIN b[275]
    DIRECTION OUTPUT ;
    USE SIGNAL ;
    PORT
      LAYER M5 ;
        RECT  27.264 0 27.288 0.192 ;
    END
  END b[275]
  PIN b[276]
    DIRECTION OUTPUT ;
    USE SIGNAL ;
    PORT
      LAYER M5 ;
        RECT  27.312 0 27.336 0.192 ;
    END
  END b[276]
  PIN b[277]
    DIRECTION OUTPUT ;
    USE SIGNAL ;
    PORT
      LAYER M5 ;
        RECT  27.36 0 27.384 0.192 ;
    END
  END b[277]
  PIN b[278]
    DIRECTION OUTPUT ;
    USE SIGNAL ;
    PORT
      LAYER M5 ;
        RECT  27.408 0 27.432 0.192 ;
    END
  END b[278]
  PIN b[279]
    DIRECTION OUTPUT ;
    USE SIGNAL ;
    PORT
      LAYER M5 ;
        RECT  27.456 0 27.48 0.192 ;
    END
  END b[279]
  PIN b[27]
    DIRECTION OUTPUT ;
    USE SIGNAL ;
    PORT
      LAYER M5 ;
        RECT  15.36 0 15.384 0.192 ;
    END
  END b[27]
  PIN b[280]
    DIRECTION OUTPUT ;
    USE SIGNAL ;
    PORT
      LAYER M5 ;
        RECT  27.504 0 27.528 0.192 ;
    END
  END b[280]
  PIN b[281]
    DIRECTION OUTPUT ;
    USE SIGNAL ;
    PORT
      LAYER M5 ;
        RECT  27.552 0 27.576 0.192 ;
    END
  END b[281]
  PIN b[282]
    DIRECTION OUTPUT ;
    USE SIGNAL ;
    PORT
      LAYER M5 ;
        RECT  27.6 0 27.624 0.192 ;
    END
  END b[282]
  PIN b[283]
    DIRECTION OUTPUT ;
    USE SIGNAL ;
    PORT
      LAYER M5 ;
        RECT  27.648 0 27.672 0.192 ;
    END
  END b[283]
  PIN b[284]
    DIRECTION OUTPUT ;
    USE SIGNAL ;
    PORT
      LAYER M5 ;
        RECT  27.696 0 27.72 0.192 ;
    END
  END b[284]
  PIN b[285]
    DIRECTION OUTPUT ;
    USE SIGNAL ;
    PORT
      LAYER M5 ;
        RECT  27.744 0 27.768 0.192 ;
    END
  END b[285]
  PIN b[286]
    DIRECTION OUTPUT ;
    USE SIGNAL ;
    PORT
      LAYER M5 ;
        RECT  27.792 0 27.816 0.192 ;
    END
  END b[286]
  PIN b[287]
    DIRECTION OUTPUT ;
    USE SIGNAL ;
    PORT
      LAYER M5 ;
        RECT  27.84 0 27.864 0.192 ;
    END
  END b[287]
  PIN b[288]
    DIRECTION OUTPUT ;
    USE SIGNAL ;
    PORT
      LAYER M5 ;
        RECT  27.888 0 27.912 0.192 ;
    END
  END b[288]
  PIN b[289]
    DIRECTION OUTPUT ;
    USE SIGNAL ;
    PORT
      LAYER M5 ;
        RECT  27.936 0 27.96 0.192 ;
    END
  END b[289]
  PIN b[28]
    DIRECTION OUTPUT ;
    USE SIGNAL ;
    PORT
      LAYER M5 ;
        RECT  15.408 0 15.432 0.192 ;
    END
  END b[28]
  PIN b[290]
    DIRECTION OUTPUT ;
    USE SIGNAL ;
    PORT
      LAYER M5 ;
        RECT  27.984 0 28.008 0.192 ;
    END
  END b[290]
  PIN b[291]
    DIRECTION OUTPUT ;
    USE SIGNAL ;
    PORT
      LAYER M5 ;
        RECT  28.032 0 28.056 0.192 ;
    END
  END b[291]
  PIN b[292]
    DIRECTION OUTPUT ;
    USE SIGNAL ;
    PORT
      LAYER M5 ;
        RECT  28.08 0 28.104 0.192 ;
    END
  END b[292]
  PIN b[293]
    DIRECTION OUTPUT ;
    USE SIGNAL ;
    PORT
      LAYER M5 ;
        RECT  28.128 0 28.152 0.192 ;
    END
  END b[293]
  PIN b[294]
    DIRECTION OUTPUT ;
    USE SIGNAL ;
    PORT
      LAYER M5 ;
        RECT  28.176 0 28.2 0.192 ;
    END
  END b[294]
  PIN b[295]
    DIRECTION OUTPUT ;
    USE SIGNAL ;
    PORT
      LAYER M5 ;
        RECT  28.224 0 28.248 0.192 ;
    END
  END b[295]
  PIN b[296]
    DIRECTION OUTPUT ;
    USE SIGNAL ;
    PORT
      LAYER M5 ;
        RECT  28.272 0 28.296 0.192 ;
    END
  END b[296]
  PIN b[297]
    DIRECTION OUTPUT ;
    USE SIGNAL ;
    PORT
      LAYER M5 ;
        RECT  28.32 0 28.344 0.192 ;
    END
  END b[297]
  PIN b[298]
    DIRECTION OUTPUT ;
    USE SIGNAL ;
    PORT
      LAYER M5 ;
        RECT  28.368 0 28.392 0.192 ;
    END
  END b[298]
  PIN b[299]
    DIRECTION OUTPUT ;
    USE SIGNAL ;
    PORT
      LAYER M5 ;
        RECT  28.416 0 28.44 0.192 ;
    END
  END b[299]
  PIN b[29]
    DIRECTION OUTPUT ;
    USE SIGNAL ;
    PORT
      LAYER M5 ;
        RECT  15.456 0 15.48 0.192 ;
    END
  END b[29]
  PIN b[2]
    DIRECTION OUTPUT ;
    USE SIGNAL ;
    PORT
      LAYER M5 ;
        RECT  14.16 0 14.184 0.192 ;
    END
  END b[2]
  PIN b[300]
    DIRECTION OUTPUT ;
    USE SIGNAL ;
    PORT
      LAYER M5 ;
        RECT  28.464 0 28.488 0.192 ;
    END
  END b[300]
  PIN b[301]
    DIRECTION OUTPUT ;
    USE SIGNAL ;
    PORT
      LAYER M5 ;
        RECT  28.512 0 28.536 0.192 ;
    END
  END b[301]
  PIN b[302]
    DIRECTION OUTPUT ;
    USE SIGNAL ;
    PORT
      LAYER M5 ;
        RECT  28.56 0 28.584 0.192 ;
    END
  END b[302]
  PIN b[303]
    DIRECTION OUTPUT ;
    USE SIGNAL ;
    PORT
      LAYER M5 ;
        RECT  28.608 0 28.632 0.192 ;
    END
  END b[303]
  PIN b[304]
    DIRECTION OUTPUT ;
    USE SIGNAL ;
    PORT
      LAYER M5 ;
        RECT  28.656 0 28.68 0.192 ;
    END
  END b[304]
  PIN b[305]
    DIRECTION OUTPUT ;
    USE SIGNAL ;
    PORT
      LAYER M5 ;
        RECT  28.704 0 28.728 0.192 ;
    END
  END b[305]
  PIN b[306]
    DIRECTION OUTPUT ;
    USE SIGNAL ;
    PORT
      LAYER M5 ;
        RECT  28.752 0 28.776 0.192 ;
    END
  END b[306]
  PIN b[307]
    DIRECTION OUTPUT ;
    USE SIGNAL ;
    PORT
      LAYER M5 ;
        RECT  28.8 0 28.824 0.192 ;
    END
  END b[307]
  PIN b[308]
    DIRECTION OUTPUT ;
    USE SIGNAL ;
    PORT
      LAYER M5 ;
        RECT  28.848 0 28.872 0.192 ;
    END
  END b[308]
  PIN b[309]
    DIRECTION OUTPUT ;
    USE SIGNAL ;
    PORT
      LAYER M5 ;
        RECT  28.896 0 28.92 0.192 ;
    END
  END b[309]
  PIN b[30]
    DIRECTION OUTPUT ;
    USE SIGNAL ;
    PORT
      LAYER M5 ;
        RECT  15.504 0 15.528 0.192 ;
    END
  END b[30]
  PIN b[310]
    DIRECTION OUTPUT ;
    USE SIGNAL ;
    PORT
      LAYER M5 ;
        RECT  28.944 0 28.968 0.192 ;
    END
  END b[310]
  PIN b[311]
    DIRECTION OUTPUT ;
    USE SIGNAL ;
    PORT
      LAYER M5 ;
        RECT  28.992 0 29.016 0.192 ;
    END
  END b[311]
  PIN b[312]
    DIRECTION OUTPUT ;
    USE SIGNAL ;
    PORT
      LAYER M5 ;
        RECT  29.04 0 29.064 0.192 ;
    END
  END b[312]
  PIN b[313]
    DIRECTION OUTPUT ;
    USE SIGNAL ;
    PORT
      LAYER M5 ;
        RECT  29.088 0 29.112 0.192 ;
    END
  END b[313]
  PIN b[314]
    DIRECTION OUTPUT ;
    USE SIGNAL ;
    PORT
      LAYER M5 ;
        RECT  29.136 0 29.16 0.192 ;
    END
  END b[314]
  PIN b[315]
    DIRECTION OUTPUT ;
    USE SIGNAL ;
    PORT
      LAYER M5 ;
        RECT  29.184 0 29.208 0.192 ;
    END
  END b[315]
  PIN b[316]
    DIRECTION OUTPUT ;
    USE SIGNAL ;
    PORT
      LAYER M5 ;
        RECT  29.232 0 29.256 0.192 ;
    END
  END b[316]
  PIN b[317]
    DIRECTION OUTPUT ;
    USE SIGNAL ;
    PORT
      LAYER M5 ;
        RECT  29.28 0 29.304 0.192 ;
    END
  END b[317]
  PIN b[318]
    DIRECTION OUTPUT ;
    USE SIGNAL ;
    PORT
      LAYER M5 ;
        RECT  29.328 0 29.352 0.192 ;
    END
  END b[318]
  PIN b[319]
    DIRECTION OUTPUT ;
    USE SIGNAL ;
    PORT
      LAYER M5 ;
        RECT  29.376 0 29.4 0.192 ;
    END
  END b[319]
  PIN b[31]
    DIRECTION OUTPUT ;
    USE SIGNAL ;
    PORT
      LAYER M5 ;
        RECT  15.552 0 15.576 0.192 ;
    END
  END b[31]
  PIN b[320]
    DIRECTION OUTPUT ;
    USE SIGNAL ;
    PORT
      LAYER M5 ;
        RECT  29.424 0 29.448 0.192 ;
    END
  END b[320]
  PIN b[321]
    DIRECTION OUTPUT ;
    USE SIGNAL ;
    PORT
      LAYER M5 ;
        RECT  29.472 0 29.496 0.192 ;
    END
  END b[321]
  PIN b[322]
    DIRECTION OUTPUT ;
    USE SIGNAL ;
    PORT
      LAYER M5 ;
        RECT  29.52 0 29.544 0.192 ;
    END
  END b[322]
  PIN b[323]
    DIRECTION OUTPUT ;
    USE SIGNAL ;
    PORT
      LAYER M5 ;
        RECT  29.568 0 29.592 0.192 ;
    END
  END b[323]
  PIN b[324]
    DIRECTION OUTPUT ;
    USE SIGNAL ;
    PORT
      LAYER M5 ;
        RECT  29.616 0 29.64 0.192 ;
    END
  END b[324]
  PIN b[325]
    DIRECTION OUTPUT ;
    USE SIGNAL ;
    PORT
      LAYER M5 ;
        RECT  29.664 0 29.688 0.192 ;
    END
  END b[325]
  PIN b[326]
    DIRECTION OUTPUT ;
    USE SIGNAL ;
    PORT
      LAYER M5 ;
        RECT  29.712 0 29.736 0.192 ;
    END
  END b[326]
  PIN b[327]
    DIRECTION OUTPUT ;
    USE SIGNAL ;
    PORT
      LAYER M5 ;
        RECT  29.76 0 29.784 0.192 ;
    END
  END b[327]
  PIN b[328]
    DIRECTION OUTPUT ;
    USE SIGNAL ;
    PORT
      LAYER M5 ;
        RECT  29.808 0 29.832 0.192 ;
    END
  END b[328]
  PIN b[329]
    DIRECTION OUTPUT ;
    USE SIGNAL ;
    PORT
      LAYER M5 ;
        RECT  29.856 0 29.88 0.192 ;
    END
  END b[329]
  PIN b[32]
    DIRECTION OUTPUT ;
    USE SIGNAL ;
    PORT
      LAYER M5 ;
        RECT  15.6 0 15.624 0.192 ;
    END
  END b[32]
  PIN b[330]
    DIRECTION OUTPUT ;
    USE SIGNAL ;
    PORT
      LAYER M5 ;
        RECT  29.904 0 29.928 0.192 ;
    END
  END b[330]
  PIN b[331]
    DIRECTION OUTPUT ;
    USE SIGNAL ;
    PORT
      LAYER M5 ;
        RECT  29.952 0 29.976 0.192 ;
    END
  END b[331]
  PIN b[332]
    DIRECTION OUTPUT ;
    USE SIGNAL ;
    PORT
      LAYER M5 ;
        RECT  30 0 30.024 0.192 ;
    END
  END b[332]
  PIN b[333]
    DIRECTION OUTPUT ;
    USE SIGNAL ;
    PORT
      LAYER M5 ;
        RECT  30.048 0 30.072 0.192 ;
    END
  END b[333]
  PIN b[334]
    DIRECTION OUTPUT ;
    USE SIGNAL ;
    PORT
      LAYER M5 ;
        RECT  30.096 0 30.12 0.192 ;
    END
  END b[334]
  PIN b[335]
    DIRECTION OUTPUT ;
    USE SIGNAL ;
    PORT
      LAYER M5 ;
        RECT  30.144 0 30.168 0.192 ;
    END
  END b[335]
  PIN b[336]
    DIRECTION OUTPUT ;
    USE SIGNAL ;
    PORT
      LAYER M5 ;
        RECT  30.192 0 30.216 0.192 ;
    END
  END b[336]
  PIN b[337]
    DIRECTION OUTPUT ;
    USE SIGNAL ;
    PORT
      LAYER M5 ;
        RECT  30.24 0 30.264 0.192 ;
    END
  END b[337]
  PIN b[338]
    DIRECTION OUTPUT ;
    USE SIGNAL ;
    PORT
      LAYER M5 ;
        RECT  30.288 0 30.312 0.192 ;
    END
  END b[338]
  PIN b[339]
    DIRECTION OUTPUT ;
    USE SIGNAL ;
    PORT
      LAYER M5 ;
        RECT  30.336 0 30.36 0.192 ;
    END
  END b[339]
  PIN b[33]
    DIRECTION OUTPUT ;
    USE SIGNAL ;
    PORT
      LAYER M5 ;
        RECT  15.648 0 15.672 0.192 ;
    END
  END b[33]
  PIN b[340]
    DIRECTION OUTPUT ;
    USE SIGNAL ;
    PORT
      LAYER M5 ;
        RECT  30.384 0 30.408 0.192 ;
    END
  END b[340]
  PIN b[341]
    DIRECTION OUTPUT ;
    USE SIGNAL ;
    PORT
      LAYER M5 ;
        RECT  30.432 0 30.456 0.192 ;
    END
  END b[341]
  PIN b[342]
    DIRECTION OUTPUT ;
    USE SIGNAL ;
    PORT
      LAYER M5 ;
        RECT  30.48 0 30.504 0.192 ;
    END
  END b[342]
  PIN b[343]
    DIRECTION OUTPUT ;
    USE SIGNAL ;
    PORT
      LAYER M5 ;
        RECT  30.528 0 30.552 0.192 ;
    END
  END b[343]
  PIN b[344]
    DIRECTION OUTPUT ;
    USE SIGNAL ;
    PORT
      LAYER M5 ;
        RECT  30.576 0 30.6 0.192 ;
    END
  END b[344]
  PIN b[345]
    DIRECTION OUTPUT ;
    USE SIGNAL ;
    PORT
      LAYER M5 ;
        RECT  30.624 0 30.648 0.192 ;
    END
  END b[345]
  PIN b[346]
    DIRECTION OUTPUT ;
    USE SIGNAL ;
    PORT
      LAYER M5 ;
        RECT  30.672 0 30.696 0.192 ;
    END
  END b[346]
  PIN b[347]
    DIRECTION OUTPUT ;
    USE SIGNAL ;
    PORT
      LAYER M5 ;
        RECT  30.72 0 30.744 0.192 ;
    END
  END b[347]
  PIN b[348]
    DIRECTION OUTPUT ;
    USE SIGNAL ;
    PORT
      LAYER M5 ;
        RECT  30.768 0 30.792 0.192 ;
    END
  END b[348]
  PIN b[349]
    DIRECTION OUTPUT ;
    USE SIGNAL ;
    PORT
      LAYER M5 ;
        RECT  30.816 0 30.84 0.192 ;
    END
  END b[349]
  PIN b[34]
    DIRECTION OUTPUT ;
    USE SIGNAL ;
    PORT
      LAYER M5 ;
        RECT  15.696 0 15.72 0.192 ;
    END
  END b[34]
  PIN b[350]
    DIRECTION OUTPUT ;
    USE SIGNAL ;
    PORT
      LAYER M5 ;
        RECT  30.864 0 30.888 0.192 ;
    END
  END b[350]
  PIN b[351]
    DIRECTION OUTPUT ;
    USE SIGNAL ;
    PORT
      LAYER M5 ;
        RECT  30.912 0 30.936 0.192 ;
    END
  END b[351]
  PIN b[352]
    DIRECTION OUTPUT ;
    USE SIGNAL ;
    PORT
      LAYER M5 ;
        RECT  30.96 0 30.984 0.192 ;
    END
  END b[352]
  PIN b[353]
    DIRECTION OUTPUT ;
    USE SIGNAL ;
    PORT
      LAYER M5 ;
        RECT  31.008 0 31.032 0.192 ;
    END
  END b[353]
  PIN b[354]
    DIRECTION OUTPUT ;
    USE SIGNAL ;
    PORT
      LAYER M5 ;
        RECT  31.056 0 31.08 0.192 ;
    END
  END b[354]
  PIN b[355]
    DIRECTION OUTPUT ;
    USE SIGNAL ;
    PORT
      LAYER M5 ;
        RECT  31.104 0 31.128 0.192 ;
    END
  END b[355]
  PIN b[356]
    DIRECTION OUTPUT ;
    USE SIGNAL ;
    PORT
      LAYER M5 ;
        RECT  31.152 0 31.176 0.192 ;
    END
  END b[356]
  PIN b[357]
    DIRECTION OUTPUT ;
    USE SIGNAL ;
    PORT
      LAYER M5 ;
        RECT  31.2 0 31.224 0.192 ;
    END
  END b[357]
  PIN b[358]
    DIRECTION OUTPUT ;
    USE SIGNAL ;
    PORT
      LAYER M5 ;
        RECT  31.248 0 31.272 0.192 ;
    END
  END b[358]
  PIN b[359]
    DIRECTION OUTPUT ;
    USE SIGNAL ;
    PORT
      LAYER M5 ;
        RECT  31.296 0 31.32 0.192 ;
    END
  END b[359]
  PIN b[35]
    DIRECTION OUTPUT ;
    USE SIGNAL ;
    PORT
      LAYER M5 ;
        RECT  15.744 0 15.768 0.192 ;
    END
  END b[35]
  PIN b[360]
    DIRECTION OUTPUT ;
    USE SIGNAL ;
    PORT
      LAYER M5 ;
        RECT  31.344 0 31.368 0.192 ;
    END
  END b[360]
  PIN b[361]
    DIRECTION OUTPUT ;
    USE SIGNAL ;
    PORT
      LAYER M5 ;
        RECT  31.392 0 31.416 0.192 ;
    END
  END b[361]
  PIN b[362]
    DIRECTION OUTPUT ;
    USE SIGNAL ;
    PORT
      LAYER M5 ;
        RECT  31.44 0 31.464 0.192 ;
    END
  END b[362]
  PIN b[363]
    DIRECTION OUTPUT ;
    USE SIGNAL ;
    PORT
      LAYER M5 ;
        RECT  31.488 0 31.512 0.192 ;
    END
  END b[363]
  PIN b[364]
    DIRECTION OUTPUT ;
    USE SIGNAL ;
    PORT
      LAYER M5 ;
        RECT  31.536 0 31.56 0.192 ;
    END
  END b[364]
  PIN b[365]
    DIRECTION OUTPUT ;
    USE SIGNAL ;
    PORT
      LAYER M5 ;
        RECT  31.584 0 31.608 0.192 ;
    END
  END b[365]
  PIN b[366]
    DIRECTION OUTPUT ;
    USE SIGNAL ;
    PORT
      LAYER M5 ;
        RECT  31.632 0 31.656 0.192 ;
    END
  END b[366]
  PIN b[367]
    DIRECTION OUTPUT ;
    USE SIGNAL ;
    PORT
      LAYER M5 ;
        RECT  31.68 0 31.704 0.192 ;
    END
  END b[367]
  PIN b[368]
    DIRECTION OUTPUT ;
    USE SIGNAL ;
    PORT
      LAYER M5 ;
        RECT  31.728 0 31.752 0.192 ;
    END
  END b[368]
  PIN b[369]
    DIRECTION OUTPUT ;
    USE SIGNAL ;
    PORT
      LAYER M5 ;
        RECT  31.776 0 31.8 0.192 ;
    END
  END b[369]
  PIN b[36]
    DIRECTION OUTPUT ;
    USE SIGNAL ;
    PORT
      LAYER M5 ;
        RECT  15.792 0 15.816 0.192 ;
    END
  END b[36]
  PIN b[370]
    DIRECTION OUTPUT ;
    USE SIGNAL ;
    PORT
      LAYER M5 ;
        RECT  31.824 0 31.848 0.192 ;
    END
  END b[370]
  PIN b[371]
    DIRECTION OUTPUT ;
    USE SIGNAL ;
    PORT
      LAYER M5 ;
        RECT  31.872 0 31.896 0.192 ;
    END
  END b[371]
  PIN b[372]
    DIRECTION OUTPUT ;
    USE SIGNAL ;
    PORT
      LAYER M5 ;
        RECT  31.92 0 31.944 0.192 ;
    END
  END b[372]
  PIN b[373]
    DIRECTION OUTPUT ;
    USE SIGNAL ;
    PORT
      LAYER M5 ;
        RECT  31.968 0 31.992 0.192 ;
    END
  END b[373]
  PIN b[374]
    DIRECTION OUTPUT ;
    USE SIGNAL ;
    PORT
      LAYER M5 ;
        RECT  32.016 0 32.04 0.192 ;
    END
  END b[374]
  PIN b[375]
    DIRECTION OUTPUT ;
    USE SIGNAL ;
    PORT
      LAYER M5 ;
        RECT  32.064 0 32.088 0.192 ;
    END
  END b[375]
  PIN b[376]
    DIRECTION OUTPUT ;
    USE SIGNAL ;
    PORT
      LAYER M5 ;
        RECT  32.112 0 32.136 0.192 ;
    END
  END b[376]
  PIN b[377]
    DIRECTION OUTPUT ;
    USE SIGNAL ;
    PORT
      LAYER M5 ;
        RECT  32.16 0 32.184 0.192 ;
    END
  END b[377]
  PIN b[378]
    DIRECTION OUTPUT ;
    USE SIGNAL ;
    PORT
      LAYER M5 ;
        RECT  32.208 0 32.232 0.192 ;
    END
  END b[378]
  PIN b[379]
    DIRECTION OUTPUT ;
    USE SIGNAL ;
    PORT
      LAYER M5 ;
        RECT  32.256 0 32.28 0.192 ;
    END
  END b[379]
  PIN b[37]
    DIRECTION OUTPUT ;
    USE SIGNAL ;
    PORT
      LAYER M5 ;
        RECT  15.84 0 15.864 0.192 ;
    END
  END b[37]
  PIN b[380]
    DIRECTION OUTPUT ;
    USE SIGNAL ;
    PORT
      LAYER M5 ;
        RECT  32.304 0 32.328 0.192 ;
    END
  END b[380]
  PIN b[381]
    DIRECTION OUTPUT ;
    USE SIGNAL ;
    PORT
      LAYER M5 ;
        RECT  32.352 0 32.376 0.192 ;
    END
  END b[381]
  PIN b[382]
    DIRECTION OUTPUT ;
    USE SIGNAL ;
    PORT
      LAYER M5 ;
        RECT  32.4 0 32.424 0.192 ;
    END
  END b[382]
  PIN b[383]
    DIRECTION OUTPUT ;
    USE SIGNAL ;
    PORT
      LAYER M5 ;
        RECT  32.448 0 32.472 0.192 ;
    END
  END b[383]
  PIN b[384]
    DIRECTION OUTPUT ;
    USE SIGNAL ;
    PORT
      LAYER M5 ;
        RECT  32.496 0 32.52 0.192 ;
    END
  END b[384]
  PIN b[385]
    DIRECTION OUTPUT ;
    USE SIGNAL ;
    PORT
      LAYER M5 ;
        RECT  32.544 0 32.568 0.192 ;
    END
  END b[385]
  PIN b[386]
    DIRECTION OUTPUT ;
    USE SIGNAL ;
    PORT
      LAYER M5 ;
        RECT  32.592 0 32.616 0.192 ;
    END
  END b[386]
  PIN b[387]
    DIRECTION OUTPUT ;
    USE SIGNAL ;
    PORT
      LAYER M5 ;
        RECT  32.64 0 32.664 0.192 ;
    END
  END b[387]
  PIN b[388]
    DIRECTION OUTPUT ;
    USE SIGNAL ;
    PORT
      LAYER M5 ;
        RECT  32.688 0 32.712 0.192 ;
    END
  END b[388]
  PIN b[389]
    DIRECTION OUTPUT ;
    USE SIGNAL ;
    PORT
      LAYER M5 ;
        RECT  32.736 0 32.76 0.192 ;
    END
  END b[389]
  PIN b[38]
    DIRECTION OUTPUT ;
    USE SIGNAL ;
    PORT
      LAYER M5 ;
        RECT  15.888 0 15.912 0.192 ;
    END
  END b[38]
  PIN b[390]
    DIRECTION OUTPUT ;
    USE SIGNAL ;
    PORT
      LAYER M5 ;
        RECT  32.784 0 32.808 0.192 ;
    END
  END b[390]
  PIN b[391]
    DIRECTION OUTPUT ;
    USE SIGNAL ;
    PORT
      LAYER M5 ;
        RECT  32.832 0 32.856 0.192 ;
    END
  END b[391]
  PIN b[392]
    DIRECTION OUTPUT ;
    USE SIGNAL ;
    PORT
      LAYER M5 ;
        RECT  32.88 0 32.904 0.192 ;
    END
  END b[392]
  PIN b[393]
    DIRECTION OUTPUT ;
    USE SIGNAL ;
    PORT
      LAYER M5 ;
        RECT  32.928 0 32.952 0.192 ;
    END
  END b[393]
  PIN b[394]
    DIRECTION OUTPUT ;
    USE SIGNAL ;
    PORT
      LAYER M5 ;
        RECT  32.976 0 33 0.192 ;
    END
  END b[394]
  PIN b[395]
    DIRECTION OUTPUT ;
    USE SIGNAL ;
    PORT
      LAYER M5 ;
        RECT  33.024 0 33.048 0.192 ;
    END
  END b[395]
  PIN b[396]
    DIRECTION OUTPUT ;
    USE SIGNAL ;
    PORT
      LAYER M5 ;
        RECT  33.072 0 33.096 0.192 ;
    END
  END b[396]
  PIN b[397]
    DIRECTION OUTPUT ;
    USE SIGNAL ;
    PORT
      LAYER M5 ;
        RECT  33.12 0 33.144 0.192 ;
    END
  END b[397]
  PIN b[398]
    DIRECTION OUTPUT ;
    USE SIGNAL ;
    PORT
      LAYER M5 ;
        RECT  33.168 0 33.192 0.192 ;
    END
  END b[398]
  PIN b[399]
    DIRECTION OUTPUT ;
    USE SIGNAL ;
    PORT
      LAYER M5 ;
        RECT  33.216 0 33.24 0.192 ;
    END
  END b[399]
  PIN b[39]
    DIRECTION OUTPUT ;
    USE SIGNAL ;
    PORT
      LAYER M5 ;
        RECT  15.936 0 15.96 0.192 ;
    END
  END b[39]
  PIN b[3]
    DIRECTION OUTPUT ;
    USE SIGNAL ;
    PORT
      LAYER M5 ;
        RECT  14.208 0 14.232 0.192 ;
    END
  END b[3]
  PIN b[400]
    DIRECTION OUTPUT ;
    USE SIGNAL ;
    PORT
      LAYER M5 ;
        RECT  33.264 0 33.288 0.192 ;
    END
  END b[400]
  PIN b[401]
    DIRECTION OUTPUT ;
    USE SIGNAL ;
    PORT
      LAYER M5 ;
        RECT  33.312 0 33.336 0.192 ;
    END
  END b[401]
  PIN b[402]
    DIRECTION OUTPUT ;
    USE SIGNAL ;
    PORT
      LAYER M5 ;
        RECT  33.36 0 33.384 0.192 ;
    END
  END b[402]
  PIN b[403]
    DIRECTION OUTPUT ;
    USE SIGNAL ;
    PORT
      LAYER M5 ;
        RECT  33.408 0 33.432 0.192 ;
    END
  END b[403]
  PIN b[404]
    DIRECTION OUTPUT ;
    USE SIGNAL ;
    PORT
      LAYER M5 ;
        RECT  33.456 0 33.48 0.192 ;
    END
  END b[404]
  PIN b[405]
    DIRECTION OUTPUT ;
    USE SIGNAL ;
    PORT
      LAYER M5 ;
        RECT  33.504 0 33.528 0.192 ;
    END
  END b[405]
  PIN b[406]
    DIRECTION OUTPUT ;
    USE SIGNAL ;
    PORT
      LAYER M5 ;
        RECT  33.552 0 33.576 0.192 ;
    END
  END b[406]
  PIN b[407]
    DIRECTION OUTPUT ;
    USE SIGNAL ;
    PORT
      LAYER M5 ;
        RECT  33.6 0 33.624 0.192 ;
    END
  END b[407]
  PIN b[408]
    DIRECTION OUTPUT ;
    USE SIGNAL ;
    PORT
      LAYER M5 ;
        RECT  33.648 0 33.672 0.192 ;
    END
  END b[408]
  PIN b[409]
    DIRECTION OUTPUT ;
    USE SIGNAL ;
    PORT
      LAYER M5 ;
        RECT  33.696 0 33.72 0.192 ;
    END
  END b[409]
  PIN b[40]
    DIRECTION OUTPUT ;
    USE SIGNAL ;
    PORT
      LAYER M5 ;
        RECT  15.984 0 16.008 0.192 ;
    END
  END b[40]
  PIN b[410]
    DIRECTION OUTPUT ;
    USE SIGNAL ;
    PORT
      LAYER M5 ;
        RECT  33.744 0 33.768 0.192 ;
    END
  END b[410]
  PIN b[411]
    DIRECTION OUTPUT ;
    USE SIGNAL ;
    PORT
      LAYER M5 ;
        RECT  33.792 0 33.816 0.192 ;
    END
  END b[411]
  PIN b[412]
    DIRECTION OUTPUT ;
    USE SIGNAL ;
    PORT
      LAYER M5 ;
        RECT  33.84 0 33.864 0.192 ;
    END
  END b[412]
  PIN b[413]
    DIRECTION OUTPUT ;
    USE SIGNAL ;
    PORT
      LAYER M5 ;
        RECT  33.888 0 33.912 0.192 ;
    END
  END b[413]
  PIN b[414]
    DIRECTION OUTPUT ;
    USE SIGNAL ;
    PORT
      LAYER M5 ;
        RECT  33.936 0 33.96 0.192 ;
    END
  END b[414]
  PIN b[415]
    DIRECTION OUTPUT ;
    USE SIGNAL ;
    PORT
      LAYER M5 ;
        RECT  33.984 0 34.008 0.192 ;
    END
  END b[415]
  PIN b[416]
    DIRECTION OUTPUT ;
    USE SIGNAL ;
    PORT
      LAYER M5 ;
        RECT  34.032 0 34.056 0.192 ;
    END
  END b[416]
  PIN b[417]
    DIRECTION OUTPUT ;
    USE SIGNAL ;
    PORT
      LAYER M5 ;
        RECT  34.08 0 34.104 0.192 ;
    END
  END b[417]
  PIN b[418]
    DIRECTION OUTPUT ;
    USE SIGNAL ;
    PORT
      LAYER M5 ;
        RECT  34.128 0 34.152 0.192 ;
    END
  END b[418]
  PIN b[419]
    DIRECTION OUTPUT ;
    USE SIGNAL ;
    PORT
      LAYER M5 ;
        RECT  34.176 0 34.2 0.192 ;
    END
  END b[419]
  PIN b[41]
    DIRECTION OUTPUT ;
    USE SIGNAL ;
    PORT
      LAYER M5 ;
        RECT  16.032 0 16.056 0.192 ;
    END
  END b[41]
  PIN b[420]
    DIRECTION OUTPUT ;
    USE SIGNAL ;
    PORT
      LAYER M5 ;
        RECT  34.224 0 34.248 0.192 ;
    END
  END b[420]
  PIN b[421]
    DIRECTION OUTPUT ;
    USE SIGNAL ;
    PORT
      LAYER M5 ;
        RECT  34.272 0 34.296 0.192 ;
    END
  END b[421]
  PIN b[422]
    DIRECTION OUTPUT ;
    USE SIGNAL ;
    PORT
      LAYER M5 ;
        RECT  34.32 0 34.344 0.192 ;
    END
  END b[422]
  PIN b[423]
    DIRECTION OUTPUT ;
    USE SIGNAL ;
    PORT
      LAYER M5 ;
        RECT  34.368 0 34.392 0.192 ;
    END
  END b[423]
  PIN b[424]
    DIRECTION OUTPUT ;
    USE SIGNAL ;
    PORT
      LAYER M5 ;
        RECT  34.416 0 34.44 0.192 ;
    END
  END b[424]
  PIN b[425]
    DIRECTION OUTPUT ;
    USE SIGNAL ;
    PORT
      LAYER M5 ;
        RECT  34.464 0 34.488 0.192 ;
    END
  END b[425]
  PIN b[426]
    DIRECTION OUTPUT ;
    USE SIGNAL ;
    PORT
      LAYER M5 ;
        RECT  34.512 0 34.536 0.192 ;
    END
  END b[426]
  PIN b[427]
    DIRECTION OUTPUT ;
    USE SIGNAL ;
    PORT
      LAYER M5 ;
        RECT  34.56 0 34.584 0.192 ;
    END
  END b[427]
  PIN b[428]
    DIRECTION OUTPUT ;
    USE SIGNAL ;
    PORT
      LAYER M5 ;
        RECT  34.608 0 34.632 0.192 ;
    END
  END b[428]
  PIN b[429]
    DIRECTION OUTPUT ;
    USE SIGNAL ;
    PORT
      LAYER M5 ;
        RECT  34.656 0 34.68 0.192 ;
    END
  END b[429]
  PIN b[42]
    DIRECTION OUTPUT ;
    USE SIGNAL ;
    PORT
      LAYER M5 ;
        RECT  16.08 0 16.104 0.192 ;
    END
  END b[42]
  PIN b[430]
    DIRECTION OUTPUT ;
    USE SIGNAL ;
    PORT
      LAYER M5 ;
        RECT  34.704 0 34.728 0.192 ;
    END
  END b[430]
  PIN b[431]
    DIRECTION OUTPUT ;
    USE SIGNAL ;
    PORT
      LAYER M5 ;
        RECT  34.752 0 34.776 0.192 ;
    END
  END b[431]
  PIN b[432]
    DIRECTION OUTPUT ;
    USE SIGNAL ;
    PORT
      LAYER M5 ;
        RECT  34.8 0 34.824 0.192 ;
    END
  END b[432]
  PIN b[433]
    DIRECTION OUTPUT ;
    USE SIGNAL ;
    PORT
      LAYER M5 ;
        RECT  34.848 0 34.872 0.192 ;
    END
  END b[433]
  PIN b[434]
    DIRECTION OUTPUT ;
    USE SIGNAL ;
    PORT
      LAYER M5 ;
        RECT  34.896 0 34.92 0.192 ;
    END
  END b[434]
  PIN b[435]
    DIRECTION OUTPUT ;
    USE SIGNAL ;
    PORT
      LAYER M5 ;
        RECT  34.944 0 34.968 0.192 ;
    END
  END b[435]
  PIN b[436]
    DIRECTION OUTPUT ;
    USE SIGNAL ;
    PORT
      LAYER M5 ;
        RECT  34.992 0 35.016 0.192 ;
    END
  END b[436]
  PIN b[437]
    DIRECTION OUTPUT ;
    USE SIGNAL ;
    PORT
      LAYER M5 ;
        RECT  35.04 0 35.064 0.192 ;
    END
  END b[437]
  PIN b[438]
    DIRECTION OUTPUT ;
    USE SIGNAL ;
    PORT
      LAYER M5 ;
        RECT  35.088 0 35.112 0.192 ;
    END
  END b[438]
  PIN b[439]
    DIRECTION OUTPUT ;
    USE SIGNAL ;
    PORT
      LAYER M5 ;
        RECT  35.136 0 35.16 0.192 ;
    END
  END b[439]
  PIN b[43]
    DIRECTION OUTPUT ;
    USE SIGNAL ;
    PORT
      LAYER M5 ;
        RECT  16.128 0 16.152 0.192 ;
    END
  END b[43]
  PIN b[440]
    DIRECTION OUTPUT ;
    USE SIGNAL ;
    PORT
      LAYER M5 ;
        RECT  35.184 0 35.208 0.192 ;
    END
  END b[440]
  PIN b[441]
    DIRECTION OUTPUT ;
    USE SIGNAL ;
    PORT
      LAYER M5 ;
        RECT  35.232 0 35.256 0.192 ;
    END
  END b[441]
  PIN b[442]
    DIRECTION OUTPUT ;
    USE SIGNAL ;
    PORT
      LAYER M5 ;
        RECT  35.28 0 35.304 0.192 ;
    END
  END b[442]
  PIN b[443]
    DIRECTION OUTPUT ;
    USE SIGNAL ;
    PORT
      LAYER M5 ;
        RECT  35.328 0 35.352 0.192 ;
    END
  END b[443]
  PIN b[444]
    DIRECTION OUTPUT ;
    USE SIGNAL ;
    PORT
      LAYER M5 ;
        RECT  35.376 0 35.4 0.192 ;
    END
  END b[444]
  PIN b[445]
    DIRECTION OUTPUT ;
    USE SIGNAL ;
    PORT
      LAYER M5 ;
        RECT  35.424 0 35.448 0.192 ;
    END
  END b[445]
  PIN b[446]
    DIRECTION OUTPUT ;
    USE SIGNAL ;
    PORT
      LAYER M5 ;
        RECT  35.472 0 35.496 0.192 ;
    END
  END b[446]
  PIN b[447]
    DIRECTION OUTPUT ;
    USE SIGNAL ;
    PORT
      LAYER M5 ;
        RECT  35.52 0 35.544 0.192 ;
    END
  END b[447]
  PIN b[448]
    DIRECTION OUTPUT ;
    USE SIGNAL ;
    PORT
      LAYER M5 ;
        RECT  35.568 0 35.592 0.192 ;
    END
  END b[448]
  PIN b[449]
    DIRECTION OUTPUT ;
    USE SIGNAL ;
    PORT
      LAYER M5 ;
        RECT  35.616 0 35.64 0.192 ;
    END
  END b[449]
  PIN b[44]
    DIRECTION OUTPUT ;
    USE SIGNAL ;
    PORT
      LAYER M5 ;
        RECT  16.176 0 16.2 0.192 ;
    END
  END b[44]
  PIN b[450]
    DIRECTION OUTPUT ;
    USE SIGNAL ;
    PORT
      LAYER M5 ;
        RECT  35.664 0 35.688 0.192 ;
    END
  END b[450]
  PIN b[451]
    DIRECTION OUTPUT ;
    USE SIGNAL ;
    PORT
      LAYER M5 ;
        RECT  35.712 0 35.736 0.192 ;
    END
  END b[451]
  PIN b[452]
    DIRECTION OUTPUT ;
    USE SIGNAL ;
    PORT
      LAYER M5 ;
        RECT  35.76 0 35.784 0.192 ;
    END
  END b[452]
  PIN b[453]
    DIRECTION OUTPUT ;
    USE SIGNAL ;
    PORT
      LAYER M5 ;
        RECT  35.808 0 35.832 0.192 ;
    END
  END b[453]
  PIN b[454]
    DIRECTION OUTPUT ;
    USE SIGNAL ;
    PORT
      LAYER M5 ;
        RECT  35.856 0 35.88 0.192 ;
    END
  END b[454]
  PIN b[455]
    DIRECTION OUTPUT ;
    USE SIGNAL ;
    PORT
      LAYER M5 ;
        RECT  35.904 0 35.928 0.192 ;
    END
  END b[455]
  PIN b[456]
    DIRECTION OUTPUT ;
    USE SIGNAL ;
    PORT
      LAYER M5 ;
        RECT  35.952 0 35.976 0.192 ;
    END
  END b[456]
  PIN b[457]
    DIRECTION OUTPUT ;
    USE SIGNAL ;
    PORT
      LAYER M5 ;
        RECT  36 0 36.024 0.192 ;
    END
  END b[457]
  PIN b[458]
    DIRECTION OUTPUT ;
    USE SIGNAL ;
    PORT
      LAYER M5 ;
        RECT  36.048 0 36.072 0.192 ;
    END
  END b[458]
  PIN b[459]
    DIRECTION OUTPUT ;
    USE SIGNAL ;
    PORT
      LAYER M5 ;
        RECT  36.096 0 36.12 0.192 ;
    END
  END b[459]
  PIN b[45]
    DIRECTION OUTPUT ;
    USE SIGNAL ;
    PORT
      LAYER M5 ;
        RECT  16.224 0 16.248 0.192 ;
    END
  END b[45]
  PIN b[460]
    DIRECTION OUTPUT ;
    USE SIGNAL ;
    PORT
      LAYER M5 ;
        RECT  36.144 0 36.168 0.192 ;
    END
  END b[460]
  PIN b[461]
    DIRECTION OUTPUT ;
    USE SIGNAL ;
    PORT
      LAYER M5 ;
        RECT  36.192 0 36.216 0.192 ;
    END
  END b[461]
  PIN b[462]
    DIRECTION OUTPUT ;
    USE SIGNAL ;
    PORT
      LAYER M5 ;
        RECT  36.24 0 36.264 0.192 ;
    END
  END b[462]
  PIN b[463]
    DIRECTION OUTPUT ;
    USE SIGNAL ;
    PORT
      LAYER M5 ;
        RECT  36.288 0 36.312 0.192 ;
    END
  END b[463]
  PIN b[464]
    DIRECTION OUTPUT ;
    USE SIGNAL ;
    PORT
      LAYER M5 ;
        RECT  36.336 0 36.36 0.192 ;
    END
  END b[464]
  PIN b[465]
    DIRECTION OUTPUT ;
    USE SIGNAL ;
    PORT
      LAYER M5 ;
        RECT  36.384 0 36.408 0.192 ;
    END
  END b[465]
  PIN b[466]
    DIRECTION OUTPUT ;
    USE SIGNAL ;
    PORT
      LAYER M5 ;
        RECT  36.432 0 36.456 0.192 ;
    END
  END b[466]
  PIN b[467]
    DIRECTION OUTPUT ;
    USE SIGNAL ;
    PORT
      LAYER M5 ;
        RECT  36.48 0 36.504 0.192 ;
    END
  END b[467]
  PIN b[468]
    DIRECTION OUTPUT ;
    USE SIGNAL ;
    PORT
      LAYER M5 ;
        RECT  36.528 0 36.552 0.192 ;
    END
  END b[468]
  PIN b[469]
    DIRECTION OUTPUT ;
    USE SIGNAL ;
    PORT
      LAYER M5 ;
        RECT  36.576 0 36.6 0.192 ;
    END
  END b[469]
  PIN b[46]
    DIRECTION OUTPUT ;
    USE SIGNAL ;
    PORT
      LAYER M5 ;
        RECT  16.272 0 16.296 0.192 ;
    END
  END b[46]
  PIN b[470]
    DIRECTION OUTPUT ;
    USE SIGNAL ;
    PORT
      LAYER M5 ;
        RECT  36.624 0 36.648 0.192 ;
    END
  END b[470]
  PIN b[471]
    DIRECTION OUTPUT ;
    USE SIGNAL ;
    PORT
      LAYER M5 ;
        RECT  36.672 0 36.696 0.192 ;
    END
  END b[471]
  PIN b[472]
    DIRECTION OUTPUT ;
    USE SIGNAL ;
    PORT
      LAYER M5 ;
        RECT  36.72 0 36.744 0.192 ;
    END
  END b[472]
  PIN b[473]
    DIRECTION OUTPUT ;
    USE SIGNAL ;
    PORT
      LAYER M5 ;
        RECT  36.768 0 36.792 0.192 ;
    END
  END b[473]
  PIN b[474]
    DIRECTION OUTPUT ;
    USE SIGNAL ;
    PORT
      LAYER M5 ;
        RECT  36.816 0 36.84 0.192 ;
    END
  END b[474]
  PIN b[475]
    DIRECTION OUTPUT ;
    USE SIGNAL ;
    PORT
      LAYER M5 ;
        RECT  36.864 0 36.888 0.192 ;
    END
  END b[475]
  PIN b[476]
    DIRECTION OUTPUT ;
    USE SIGNAL ;
    PORT
      LAYER M5 ;
        RECT  36.912 0 36.936 0.192 ;
    END
  END b[476]
  PIN b[477]
    DIRECTION OUTPUT ;
    USE SIGNAL ;
    PORT
      LAYER M5 ;
        RECT  36.96 0 36.984 0.192 ;
    END
  END b[477]
  PIN b[478]
    DIRECTION OUTPUT ;
    USE SIGNAL ;
    PORT
      LAYER M5 ;
        RECT  37.008 0 37.032 0.192 ;
    END
  END b[478]
  PIN b[479]
    DIRECTION OUTPUT ;
    USE SIGNAL ;
    PORT
      LAYER M5 ;
        RECT  37.056 0 37.08 0.192 ;
    END
  END b[479]
  PIN b[47]
    DIRECTION OUTPUT ;
    USE SIGNAL ;
    PORT
      LAYER M5 ;
        RECT  16.32 0 16.344 0.192 ;
    END
  END b[47]
  PIN b[480]
    DIRECTION OUTPUT ;
    USE SIGNAL ;
    PORT
      LAYER M5 ;
        RECT  37.104 0 37.128 0.192 ;
    END
  END b[480]
  PIN b[481]
    DIRECTION OUTPUT ;
    USE SIGNAL ;
    PORT
      LAYER M5 ;
        RECT  37.152 0 37.176 0.192 ;
    END
  END b[481]
  PIN b[482]
    DIRECTION OUTPUT ;
    USE SIGNAL ;
    PORT
      LAYER M5 ;
        RECT  37.2 0 37.224 0.192 ;
    END
  END b[482]
  PIN b[483]
    DIRECTION OUTPUT ;
    USE SIGNAL ;
    PORT
      LAYER M5 ;
        RECT  37.248 0 37.272 0.192 ;
    END
  END b[483]
  PIN b[484]
    DIRECTION OUTPUT ;
    USE SIGNAL ;
    PORT
      LAYER M5 ;
        RECT  37.296 0 37.32 0.192 ;
    END
  END b[484]
  PIN b[485]
    DIRECTION OUTPUT ;
    USE SIGNAL ;
    PORT
      LAYER M5 ;
        RECT  37.344 0 37.368 0.192 ;
    END
  END b[485]
  PIN b[486]
    DIRECTION OUTPUT ;
    USE SIGNAL ;
    PORT
      LAYER M5 ;
        RECT  37.392 0 37.416 0.192 ;
    END
  END b[486]
  PIN b[487]
    DIRECTION OUTPUT ;
    USE SIGNAL ;
    PORT
      LAYER M5 ;
        RECT  37.44 0 37.464 0.192 ;
    END
  END b[487]
  PIN b[488]
    DIRECTION OUTPUT ;
    USE SIGNAL ;
    PORT
      LAYER M5 ;
        RECT  37.488 0 37.512 0.192 ;
    END
  END b[488]
  PIN b[489]
    DIRECTION OUTPUT ;
    USE SIGNAL ;
    PORT
      LAYER M5 ;
        RECT  37.536 0 37.56 0.192 ;
    END
  END b[489]
  PIN b[48]
    DIRECTION OUTPUT ;
    USE SIGNAL ;
    PORT
      LAYER M5 ;
        RECT  16.368 0 16.392 0.192 ;
    END
  END b[48]
  PIN b[490]
    DIRECTION OUTPUT ;
    USE SIGNAL ;
    PORT
      LAYER M5 ;
        RECT  37.584 0 37.608 0.192 ;
    END
  END b[490]
  PIN b[491]
    DIRECTION OUTPUT ;
    USE SIGNAL ;
    PORT
      LAYER M5 ;
        RECT  37.632 0 37.656 0.192 ;
    END
  END b[491]
  PIN b[492]
    DIRECTION OUTPUT ;
    USE SIGNAL ;
    PORT
      LAYER M5 ;
        RECT  37.68 0 37.704 0.192 ;
    END
  END b[492]
  PIN b[493]
    DIRECTION OUTPUT ;
    USE SIGNAL ;
    PORT
      LAYER M5 ;
        RECT  37.728 0 37.752 0.192 ;
    END
  END b[493]
  PIN b[494]
    DIRECTION OUTPUT ;
    USE SIGNAL ;
    PORT
      LAYER M5 ;
        RECT  37.776 0 37.8 0.192 ;
    END
  END b[494]
  PIN b[495]
    DIRECTION OUTPUT ;
    USE SIGNAL ;
    PORT
      LAYER M5 ;
        RECT  37.824 0 37.848 0.192 ;
    END
  END b[495]
  PIN b[496]
    DIRECTION OUTPUT ;
    USE SIGNAL ;
    PORT
      LAYER M5 ;
        RECT  37.872 0 37.896 0.192 ;
    END
  END b[496]
  PIN b[497]
    DIRECTION OUTPUT ;
    USE SIGNAL ;
    PORT
      LAYER M5 ;
        RECT  37.92 0 37.944 0.192 ;
    END
  END b[497]
  PIN b[498]
    DIRECTION OUTPUT ;
    USE SIGNAL ;
    PORT
      LAYER M5 ;
        RECT  37.968 0 37.992 0.192 ;
    END
  END b[498]
  PIN b[499]
    DIRECTION OUTPUT ;
    USE SIGNAL ;
    PORT
      LAYER M5 ;
        RECT  38.016 0 38.04 0.192 ;
    END
  END b[499]
  PIN b[49]
    DIRECTION OUTPUT ;
    USE SIGNAL ;
    PORT
      LAYER M5 ;
        RECT  16.416 0 16.44 0.192 ;
    END
  END b[49]
  PIN b[4]
    DIRECTION OUTPUT ;
    USE SIGNAL ;
    PORT
      LAYER M5 ;
        RECT  14.256 0 14.28 0.192 ;
    END
  END b[4]
  PIN b[500]
    DIRECTION OUTPUT ;
    USE SIGNAL ;
    PORT
      LAYER M5 ;
        RECT  38.064 0 38.088 0.192 ;
    END
  END b[500]
  PIN b[501]
    DIRECTION OUTPUT ;
    USE SIGNAL ;
    PORT
      LAYER M5 ;
        RECT  38.112 0 38.136 0.192 ;
    END
  END b[501]
  PIN b[502]
    DIRECTION OUTPUT ;
    USE SIGNAL ;
    PORT
      LAYER M5 ;
        RECT  38.16 0 38.184 0.192 ;
    END
  END b[502]
  PIN b[503]
    DIRECTION OUTPUT ;
    USE SIGNAL ;
    PORT
      LAYER M5 ;
        RECT  38.208 0 38.232 0.192 ;
    END
  END b[503]
  PIN b[504]
    DIRECTION OUTPUT ;
    USE SIGNAL ;
    PORT
      LAYER M5 ;
        RECT  38.256 0 38.28 0.192 ;
    END
  END b[504]
  PIN b[505]
    DIRECTION OUTPUT ;
    USE SIGNAL ;
    PORT
      LAYER M5 ;
        RECT  38.304 0 38.328 0.192 ;
    END
  END b[505]
  PIN b[506]
    DIRECTION OUTPUT ;
    USE SIGNAL ;
    PORT
      LAYER M5 ;
        RECT  38.352 0 38.376 0.192 ;
    END
  END b[506]
  PIN b[507]
    DIRECTION OUTPUT ;
    USE SIGNAL ;
    PORT
      LAYER M5 ;
        RECT  38.4 0 38.424 0.192 ;
    END
  END b[507]
  PIN b[508]
    DIRECTION OUTPUT ;
    USE SIGNAL ;
    PORT
      LAYER M5 ;
        RECT  38.448 0 38.472 0.192 ;
    END
  END b[508]
  PIN b[509]
    DIRECTION OUTPUT ;
    USE SIGNAL ;
    PORT
      LAYER M5 ;
        RECT  38.496 0 38.52 0.192 ;
    END
  END b[509]
  PIN b[50]
    DIRECTION OUTPUT ;
    USE SIGNAL ;
    PORT
      LAYER M5 ;
        RECT  16.464 0 16.488 0.192 ;
    END
  END b[50]
  PIN b[510]
    DIRECTION OUTPUT ;
    USE SIGNAL ;
    PORT
      LAYER M5 ;
        RECT  38.544 0 38.568 0.192 ;
    END
  END b[510]
  PIN b[511]
    DIRECTION OUTPUT ;
    USE SIGNAL ;
    PORT
      LAYER M5 ;
        RECT  38.592 0 38.616 0.192 ;
    END
  END b[511]
  PIN b[512]
    DIRECTION OUTPUT ;
    USE SIGNAL ;
    PORT
      LAYER M5 ;
        RECT  38.64 0 38.664 0.192 ;
    END
  END b[512]
  PIN b[51]
    DIRECTION OUTPUT ;
    USE SIGNAL ;
    PORT
      LAYER M5 ;
        RECT  16.512 0 16.536 0.192 ;
    END
  END b[51]
  PIN b[52]
    DIRECTION OUTPUT ;
    USE SIGNAL ;
    PORT
      LAYER M5 ;
        RECT  16.56 0 16.584 0.192 ;
    END
  END b[52]
  PIN b[53]
    DIRECTION OUTPUT ;
    USE SIGNAL ;
    PORT
      LAYER M5 ;
        RECT  16.608 0 16.632 0.192 ;
    END
  END b[53]
  PIN b[54]
    DIRECTION OUTPUT ;
    USE SIGNAL ;
    PORT
      LAYER M5 ;
        RECT  16.656 0 16.68 0.192 ;
    END
  END b[54]
  PIN b[55]
    DIRECTION OUTPUT ;
    USE SIGNAL ;
    PORT
      LAYER M5 ;
        RECT  16.704 0 16.728 0.192 ;
    END
  END b[55]
  PIN b[56]
    DIRECTION OUTPUT ;
    USE SIGNAL ;
    PORT
      LAYER M5 ;
        RECT  16.752 0 16.776 0.192 ;
    END
  END b[56]
  PIN b[57]
    DIRECTION OUTPUT ;
    USE SIGNAL ;
    PORT
      LAYER M5 ;
        RECT  16.8 0 16.824 0.192 ;
    END
  END b[57]
  PIN b[58]
    DIRECTION OUTPUT ;
    USE SIGNAL ;
    PORT
      LAYER M5 ;
        RECT  16.848 0 16.872 0.192 ;
    END
  END b[58]
  PIN b[59]
    DIRECTION OUTPUT ;
    USE SIGNAL ;
    PORT
      LAYER M5 ;
        RECT  16.896 0 16.92 0.192 ;
    END
  END b[59]
  PIN b[5]
    DIRECTION OUTPUT ;
    USE SIGNAL ;
    PORT
      LAYER M5 ;
        RECT  14.304 0 14.328 0.192 ;
    END
  END b[5]
  PIN b[60]
    DIRECTION OUTPUT ;
    USE SIGNAL ;
    PORT
      LAYER M5 ;
        RECT  16.944 0 16.968 0.192 ;
    END
  END b[60]
  PIN b[61]
    DIRECTION OUTPUT ;
    USE SIGNAL ;
    PORT
      LAYER M5 ;
        RECT  16.992 0 17.016 0.192 ;
    END
  END b[61]
  PIN b[62]
    DIRECTION OUTPUT ;
    USE SIGNAL ;
    PORT
      LAYER M5 ;
        RECT  17.04 0 17.064 0.192 ;
    END
  END b[62]
  PIN b[63]
    DIRECTION OUTPUT ;
    USE SIGNAL ;
    PORT
      LAYER M5 ;
        RECT  17.088 0 17.112 0.192 ;
    END
  END b[63]
  PIN b[64]
    DIRECTION OUTPUT ;
    USE SIGNAL ;
    PORT
      LAYER M5 ;
        RECT  17.136 0 17.16 0.192 ;
    END
  END b[64]
  PIN b[65]
    DIRECTION OUTPUT ;
    USE SIGNAL ;
    PORT
      LAYER M5 ;
        RECT  17.184 0 17.208 0.192 ;
    END
  END b[65]
  PIN b[66]
    DIRECTION OUTPUT ;
    USE SIGNAL ;
    PORT
      LAYER M5 ;
        RECT  17.232 0 17.256 0.192 ;
    END
  END b[66]
  PIN b[67]
    DIRECTION OUTPUT ;
    USE SIGNAL ;
    PORT
      LAYER M5 ;
        RECT  17.28 0 17.304 0.192 ;
    END
  END b[67]
  PIN b[68]
    DIRECTION OUTPUT ;
    USE SIGNAL ;
    PORT
      LAYER M5 ;
        RECT  17.328 0 17.352 0.192 ;
    END
  END b[68]
  PIN b[69]
    DIRECTION OUTPUT ;
    USE SIGNAL ;
    PORT
      LAYER M5 ;
        RECT  17.376 0 17.4 0.192 ;
    END
  END b[69]
  PIN b[6]
    DIRECTION OUTPUT ;
    USE SIGNAL ;
    PORT
      LAYER M5 ;
        RECT  14.352 0 14.376 0.192 ;
    END
  END b[6]
  PIN b[70]
    DIRECTION OUTPUT ;
    USE SIGNAL ;
    PORT
      LAYER M5 ;
        RECT  17.424 0 17.448 0.192 ;
    END
  END b[70]
  PIN b[71]
    DIRECTION OUTPUT ;
    USE SIGNAL ;
    PORT
      LAYER M5 ;
        RECT  17.472 0 17.496 0.192 ;
    END
  END b[71]
  PIN b[72]
    DIRECTION OUTPUT ;
    USE SIGNAL ;
    PORT
      LAYER M5 ;
        RECT  17.52 0 17.544 0.192 ;
    END
  END b[72]
  PIN b[73]
    DIRECTION OUTPUT ;
    USE SIGNAL ;
    PORT
      LAYER M5 ;
        RECT  17.568 0 17.592 0.192 ;
    END
  END b[73]
  PIN b[74]
    DIRECTION OUTPUT ;
    USE SIGNAL ;
    PORT
      LAYER M5 ;
        RECT  17.616 0 17.64 0.192 ;
    END
  END b[74]
  PIN b[75]
    DIRECTION OUTPUT ;
    USE SIGNAL ;
    PORT
      LAYER M5 ;
        RECT  17.664 0 17.688 0.192 ;
    END
  END b[75]
  PIN b[76]
    DIRECTION OUTPUT ;
    USE SIGNAL ;
    PORT
      LAYER M5 ;
        RECT  17.712 0 17.736 0.192 ;
    END
  END b[76]
  PIN b[77]
    DIRECTION OUTPUT ;
    USE SIGNAL ;
    PORT
      LAYER M5 ;
        RECT  17.76 0 17.784 0.192 ;
    END
  END b[77]
  PIN b[78]
    DIRECTION OUTPUT ;
    USE SIGNAL ;
    PORT
      LAYER M5 ;
        RECT  17.808 0 17.832 0.192 ;
    END
  END b[78]
  PIN b[79]
    DIRECTION OUTPUT ;
    USE SIGNAL ;
    PORT
      LAYER M5 ;
        RECT  17.856 0 17.88 0.192 ;
    END
  END b[79]
  PIN b[7]
    DIRECTION OUTPUT ;
    USE SIGNAL ;
    PORT
      LAYER M5 ;
        RECT  14.4 0 14.424 0.192 ;
    END
  END b[7]
  PIN b[80]
    DIRECTION OUTPUT ;
    USE SIGNAL ;
    PORT
      LAYER M5 ;
        RECT  17.904 0 17.928 0.192 ;
    END
  END b[80]
  PIN b[81]
    DIRECTION OUTPUT ;
    USE SIGNAL ;
    PORT
      LAYER M5 ;
        RECT  17.952 0 17.976 0.192 ;
    END
  END b[81]
  PIN b[82]
    DIRECTION OUTPUT ;
    USE SIGNAL ;
    PORT
      LAYER M5 ;
        RECT  18 0 18.024 0.192 ;
    END
  END b[82]
  PIN b[83]
    DIRECTION OUTPUT ;
    USE SIGNAL ;
    PORT
      LAYER M5 ;
        RECT  18.048 0 18.072 0.192 ;
    END
  END b[83]
  PIN b[84]
    DIRECTION OUTPUT ;
    USE SIGNAL ;
    PORT
      LAYER M5 ;
        RECT  18.096 0 18.12 0.192 ;
    END
  END b[84]
  PIN b[85]
    DIRECTION OUTPUT ;
    USE SIGNAL ;
    PORT
      LAYER M5 ;
        RECT  18.144 0 18.168 0.192 ;
    END
  END b[85]
  PIN b[86]
    DIRECTION OUTPUT ;
    USE SIGNAL ;
    PORT
      LAYER M5 ;
        RECT  18.192 0 18.216 0.192 ;
    END
  END b[86]
  PIN b[87]
    DIRECTION OUTPUT ;
    USE SIGNAL ;
    PORT
      LAYER M5 ;
        RECT  18.24 0 18.264 0.192 ;
    END
  END b[87]
  PIN b[88]
    DIRECTION OUTPUT ;
    USE SIGNAL ;
    PORT
      LAYER M5 ;
        RECT  18.288 0 18.312 0.192 ;
    END
  END b[88]
  PIN b[89]
    DIRECTION OUTPUT ;
    USE SIGNAL ;
    PORT
      LAYER M5 ;
        RECT  18.336 0 18.36 0.192 ;
    END
  END b[89]
  PIN b[8]
    DIRECTION OUTPUT ;
    USE SIGNAL ;
    PORT
      LAYER M5 ;
        RECT  14.448 0 14.472 0.192 ;
    END
  END b[8]
  PIN b[90]
    DIRECTION OUTPUT ;
    USE SIGNAL ;
    PORT
      LAYER M5 ;
        RECT  18.384 0 18.408 0.192 ;
    END
  END b[90]
  PIN b[91]
    DIRECTION OUTPUT ;
    USE SIGNAL ;
    PORT
      LAYER M5 ;
        RECT  18.432 0 18.456 0.192 ;
    END
  END b[91]
  PIN b[92]
    DIRECTION OUTPUT ;
    USE SIGNAL ;
    PORT
      LAYER M5 ;
        RECT  18.48 0 18.504 0.192 ;
    END
  END b[92]
  PIN b[93]
    DIRECTION OUTPUT ;
    USE SIGNAL ;
    PORT
      LAYER M5 ;
        RECT  18.528 0 18.552 0.192 ;
    END
  END b[93]
  PIN b[94]
    DIRECTION OUTPUT ;
    USE SIGNAL ;
    PORT
      LAYER M5 ;
        RECT  18.576 0 18.6 0.192 ;
    END
  END b[94]
  PIN b[95]
    DIRECTION OUTPUT ;
    USE SIGNAL ;
    PORT
      LAYER M5 ;
        RECT  18.624 0 18.648 0.192 ;
    END
  END b[95]
  PIN b[96]
    DIRECTION OUTPUT ;
    USE SIGNAL ;
    PORT
      LAYER M5 ;
        RECT  18.672 0 18.696 0.192 ;
    END
  END b[96]
  PIN b[97]
    DIRECTION OUTPUT ;
    USE SIGNAL ;
    PORT
      LAYER M5 ;
        RECT  18.72 0 18.744 0.192 ;
    END
  END b[97]
  PIN b[98]
    DIRECTION OUTPUT ;
    USE SIGNAL ;
    PORT
      LAYER M5 ;
        RECT  18.768 0 18.792 0.192 ;
    END
  END b[98]
  PIN b[99]
    DIRECTION OUTPUT ;
    USE SIGNAL ;
    PORT
      LAYER M5 ;
        RECT  18.816 0 18.84 0.192 ;
    END
  END b[99]
  PIN b[9]
    DIRECTION OUTPUT ;
    USE SIGNAL ;
    PORT
      LAYER M5 ;
        RECT  14.496 0 14.52 0.192 ;
    END
  END b[9]
  PIN rst[0]
    DIRECTION INPUT ;
    USE SIGNAL ;
    PORT
      LAYER M4 ;
        RECT  39.096 77.04 39.288 77.064 ;
    END
  END rst[0]
  PIN VDD
    DIRECTION INOUT ;
    USE POWER ;
    PORT
      LAYER M7 ;
        RECT  38.656 0.531 38.944 76.959 ;
        RECT  27.856 0.531 28.144 76.959 ;
        RECT  17.056 0.531 17.344 76.959 ;
        RECT  6.256 0.531 6.544 76.959 ;
      LAYER M6 ;
        RECT  0 71.772 0.032 72.06 ;
        RECT  0 66.372 0.032 66.66 ;
        RECT  0 60.972 0.032 61.26 ;
        RECT  0 55.572 0.032 55.86 ;
        RECT  0 50.172 0.032 50.46 ;
        RECT  0 44.772 0.032 45.06 ;
        RECT  0 39.372 0.032 39.66 ;
        RECT  0 33.972 0.032 34.26 ;
        RECT  0 28.572 0.032 28.86 ;
        RECT  0 23.172 0.032 23.46 ;
        RECT  0 17.772 0.032 18.06 ;
        RECT  0 12.372 0.032 12.66 ;
        RECT  0 6.972 0.032 7.26 ;
        RECT  0 1.572 0.032 1.86 ;
      LAYER M2 ;
        RECT  0 76.941 0.018 76.959 ;
        RECT  0 76.401 0.018 76.419 ;
        RECT  0 75.861 0.018 75.879 ;
        RECT  0 75.321 0.018 75.339 ;
        RECT  0 74.781 0.018 74.799 ;
        RECT  0 74.241 0.018 74.259 ;
        RECT  0 73.701 0.018 73.719 ;
        RECT  0 73.161 0.018 73.179 ;
        RECT  0 72.621 0.018 72.639 ;
        RECT  0 72.081 0.018 72.099 ;
        RECT  0 71.541 0.018 71.559 ;
        RECT  0 71.001 0.018 71.019 ;
        RECT  0 70.461 0.018 70.479 ;
        RECT  0 69.921 0.018 69.939 ;
        RECT  0 69.381 0.018 69.399 ;
        RECT  0 68.841 0.018 68.859 ;
        RECT  0 68.301 0.018 68.319 ;
        RECT  0 67.761 0.018 67.779 ;
        RECT  0 67.221 0.018 67.239 ;
        RECT  0 66.681 0.018 66.699 ;
        RECT  0 66.141 0.018 66.159 ;
        RECT  0 65.601 0.018 65.619 ;
        RECT  0 65.061 0.018 65.079 ;
        RECT  0 64.521 0.018 64.539 ;
        RECT  0 63.981 0.018 63.999 ;
        RECT  0 63.441 0.018 63.459 ;
        RECT  0 62.901 0.018 62.919 ;
        RECT  0 62.361 0.018 62.379 ;
        RECT  0 61.821 0.018 61.839 ;
        RECT  0 61.281 0.018 61.299 ;
        RECT  0 60.741 0.018 60.759 ;
        RECT  0 60.201 0.018 60.219 ;
        RECT  0 59.661 0.018 59.679 ;
        RECT  0 59.121 0.018 59.139 ;
        RECT  0 58.581 0.018 58.599 ;
        RECT  0 58.041 0.018 58.059 ;
        RECT  0 57.501 0.018 57.519 ;
        RECT  0 56.961 0.018 56.979 ;
        RECT  0 56.421 0.018 56.439 ;
        RECT  0 55.881 0.018 55.899 ;
        RECT  0 55.341 0.018 55.359 ;
        RECT  0 54.801 0.018 54.819 ;
        RECT  0 54.261 0.018 54.279 ;
        RECT  0 53.721 0.018 53.739 ;
        RECT  0 53.181 0.018 53.199 ;
        RECT  0 52.641 0.018 52.659 ;
        RECT  0 52.101 0.018 52.119 ;
        RECT  0 51.561 0.018 51.579 ;
        RECT  0 51.021 0.018 51.039 ;
        RECT  0 50.481 0.018 50.499 ;
        RECT  0 49.941 0.018 49.959 ;
        RECT  0 49.401 0.018 49.419 ;
        RECT  0 48.861 0.018 48.879 ;
        RECT  0 48.321 0.018 48.339 ;
        RECT  0 47.781 0.018 47.799 ;
        RECT  0 47.241 0.018 47.259 ;
        RECT  0 46.701 0.018 46.719 ;
        RECT  0 46.161 0.018 46.179 ;
        RECT  0 45.621 0.018 45.639 ;
        RECT  0 45.081 0.018 45.099 ;
        RECT  0 44.541 0.018 44.559 ;
        RECT  0 44.001 0.018 44.019 ;
        RECT  0 43.461 0.018 43.479 ;
        RECT  0 42.921 0.018 42.939 ;
        RECT  0 42.381 0.018 42.399 ;
        RECT  0 41.841 0.018 41.859 ;
        RECT  0 41.301 0.018 41.319 ;
        RECT  0 40.761 0.018 40.779 ;
        RECT  0 40.221 0.018 40.239 ;
        RECT  0 39.681 0.018 39.699 ;
        RECT  0 39.141 0.018 39.159 ;
        RECT  0 38.601 0.018 38.619 ;
        RECT  0 38.061 0.018 38.079 ;
        RECT  0 37.521 0.018 37.539 ;
        RECT  0 36.981 0.018 36.999 ;
        RECT  0 36.441 0.018 36.459 ;
        RECT  0 35.901 0.018 35.919 ;
        RECT  0 35.361 0.018 35.379 ;
        RECT  0 34.821 0.018 34.839 ;
        RECT  0 34.281 0.018 34.299 ;
        RECT  0 33.741 0.018 33.759 ;
        RECT  0 33.201 0.018 33.219 ;
        RECT  0 32.661 0.018 32.679 ;
        RECT  0 32.121 0.018 32.139 ;
        RECT  0 31.581 0.018 31.599 ;
        RECT  0 31.041 0.018 31.059 ;
        RECT  0 30.501 0.018 30.519 ;
        RECT  0 29.961 0.018 29.979 ;
        RECT  0 29.421 0.018 29.439 ;
        RECT  0 28.881 0.018 28.899 ;
        RECT  0 28.341 0.018 28.359 ;
        RECT  0 27.801 0.018 27.819 ;
        RECT  0 27.261 0.018 27.279 ;
        RECT  0 26.721 0.018 26.739 ;
        RECT  0 26.181 0.018 26.199 ;
        RECT  0 25.641 0.018 25.659 ;
        RECT  0 25.101 0.018 25.119 ;
        RECT  0 24.561 0.018 24.579 ;
        RECT  0 24.021 0.018 24.039 ;
        RECT  0 23.481 0.018 23.499 ;
        RECT  0 22.941 0.018 22.959 ;
        RECT  0 22.401 0.018 22.419 ;
        RECT  0 21.861 0.018 21.879 ;
        RECT  0 21.321 0.018 21.339 ;
        RECT  0 20.781 0.018 20.799 ;
        RECT  0 20.241 0.018 20.259 ;
        RECT  0 19.701 0.018 19.719 ;
        RECT  0 19.161 0.018 19.179 ;
        RECT  0 18.621 0.018 18.639 ;
        RECT  0 18.081 0.018 18.099 ;
        RECT  0 17.541 0.018 17.559 ;
        RECT  0 17.001 0.018 17.019 ;
        RECT  0 16.461 0.018 16.479 ;
        RECT  0 15.921 0.018 15.939 ;
        RECT  0 15.381 0.018 15.399 ;
        RECT  0 14.841 0.018 14.859 ;
        RECT  0 14.301 0.018 14.319 ;
        RECT  0 13.761 0.018 13.779 ;
        RECT  0 13.221 0.018 13.239 ;
        RECT  0 12.681 0.018 12.699 ;
        RECT  0 12.141 0.018 12.159 ;
        RECT  0 11.601 0.018 11.619 ;
        RECT  0 11.061 0.018 11.079 ;
        RECT  0 10.521 0.018 10.539 ;
        RECT  0 9.981 0.018 9.999 ;
        RECT  0 9.441 0.018 9.459 ;
        RECT  0 8.901 0.018 8.919 ;
        RECT  0 8.361 0.018 8.379 ;
        RECT  0 7.821 0.018 7.839 ;
        RECT  0 7.281 0.018 7.299 ;
        RECT  0 6.741 0.018 6.759 ;
        RECT  0 6.201 0.018 6.219 ;
        RECT  0 5.661 0.018 5.679 ;
        RECT  0 5.121 0.018 5.139 ;
        RECT  0 4.581 0.018 4.599 ;
        RECT  0 4.041 0.018 4.059 ;
        RECT  0 3.501 0.018 3.519 ;
        RECT  0 2.961 0.018 2.979 ;
        RECT  0 2.421 0.018 2.439 ;
        RECT  0 1.881 0.018 1.899 ;
        RECT  0 1.341 0.018 1.359 ;
        RECT  0 0.801 0.018 0.819 ;
      LAYER M1 ;
        RECT  0 76.941 0.018 76.959 ;
        RECT  0 76.401 0.018 76.419 ;
        RECT  0 75.861 0.018 75.879 ;
        RECT  0 75.321 0.018 75.339 ;
        RECT  0 74.781 0.018 74.799 ;
        RECT  0 74.241 0.018 74.259 ;
        RECT  0 73.701 0.018 73.719 ;
        RECT  0 73.161 0.018 73.179 ;
        RECT  0 72.621 0.018 72.639 ;
        RECT  0 72.081 0.018 72.099 ;
        RECT  0 71.541 0.018 71.559 ;
        RECT  0 71.001 0.018 71.019 ;
        RECT  0 70.461 0.018 70.479 ;
        RECT  0 69.921 0.018 69.939 ;
        RECT  0 69.381 0.018 69.399 ;
        RECT  0 68.841 0.018 68.859 ;
        RECT  0 68.301 0.018 68.319 ;
        RECT  0 67.761 0.018 67.779 ;
        RECT  0 67.221 0.018 67.239 ;
        RECT  0 66.681 0.018 66.699 ;
        RECT  0 66.141 0.018 66.159 ;
        RECT  0 65.601 0.018 65.619 ;
        RECT  0 65.061 0.018 65.079 ;
        RECT  0 64.521 0.018 64.539 ;
        RECT  0 63.981 0.018 63.999 ;
        RECT  0 63.441 0.018 63.459 ;
        RECT  0 62.901 0.018 62.919 ;
        RECT  0 62.361 0.018 62.379 ;
        RECT  0 61.821 0.018 61.839 ;
        RECT  0 61.281 0.018 61.299 ;
        RECT  0 60.741 0.018 60.759 ;
        RECT  0 60.201 0.018 60.219 ;
        RECT  0 59.661 0.018 59.679 ;
        RECT  0 59.121 0.018 59.139 ;
        RECT  0 58.581 0.018 58.599 ;
        RECT  0 58.041 0.018 58.059 ;
        RECT  0 57.501 0.018 57.519 ;
        RECT  0 56.961 0.018 56.979 ;
        RECT  0 56.421 0.018 56.439 ;
        RECT  0 55.881 0.018 55.899 ;
        RECT  0 55.341 0.018 55.359 ;
        RECT  0 54.801 0.018 54.819 ;
        RECT  0 54.261 0.018 54.279 ;
        RECT  0 53.721 0.018 53.739 ;
        RECT  0 53.181 0.018 53.199 ;
        RECT  0 52.641 0.018 52.659 ;
        RECT  0 52.101 0.018 52.119 ;
        RECT  0 51.561 0.018 51.579 ;
        RECT  0 51.021 0.018 51.039 ;
        RECT  0 50.481 0.018 50.499 ;
        RECT  0 49.941 0.018 49.959 ;
        RECT  0 49.401 0.018 49.419 ;
        RECT  0 48.861 0.018 48.879 ;
        RECT  0 48.321 0.018 48.339 ;
        RECT  0 47.781 0.018 47.799 ;
        RECT  0 47.241 0.018 47.259 ;
        RECT  0 46.701 0.018 46.719 ;
        RECT  0 46.161 0.018 46.179 ;
        RECT  0 45.621 0.018 45.639 ;
        RECT  0 45.081 0.018 45.099 ;
        RECT  0 44.541 0.018 44.559 ;
        RECT  0 44.001 0.018 44.019 ;
        RECT  0 43.461 0.018 43.479 ;
        RECT  0 42.921 0.018 42.939 ;
        RECT  0 42.381 0.018 42.399 ;
        RECT  0 41.841 0.018 41.859 ;
        RECT  0 41.301 0.018 41.319 ;
        RECT  0 40.761 0.018 40.779 ;
        RECT  0 40.221 0.018 40.239 ;
        RECT  0 39.681 0.018 39.699 ;
        RECT  0 39.141 0.018 39.159 ;
        RECT  0 38.601 0.018 38.619 ;
        RECT  0 38.061 0.018 38.079 ;
        RECT  0 37.521 0.018 37.539 ;
        RECT  0 36.981 0.018 36.999 ;
        RECT  0 36.441 0.018 36.459 ;
        RECT  0 35.901 0.018 35.919 ;
        RECT  0 35.361 0.018 35.379 ;
        RECT  0 34.821 0.018 34.839 ;
        RECT  0 34.281 0.018 34.299 ;
        RECT  0 33.741 0.018 33.759 ;
        RECT  0 33.201 0.018 33.219 ;
        RECT  0 32.661 0.018 32.679 ;
        RECT  0 32.121 0.018 32.139 ;
        RECT  0 31.581 0.018 31.599 ;
        RECT  0 31.041 0.018 31.059 ;
        RECT  0 30.501 0.018 30.519 ;
        RECT  0 29.961 0.018 29.979 ;
        RECT  0 29.421 0.018 29.439 ;
        RECT  0 28.881 0.018 28.899 ;
        RECT  0 28.341 0.018 28.359 ;
        RECT  0 27.801 0.018 27.819 ;
        RECT  0 27.261 0.018 27.279 ;
        RECT  0 26.721 0.018 26.739 ;
        RECT  0 26.181 0.018 26.199 ;
        RECT  0 25.641 0.018 25.659 ;
        RECT  0 25.101 0.018 25.119 ;
        RECT  0 24.561 0.018 24.579 ;
        RECT  0 24.021 0.018 24.039 ;
        RECT  0 23.481 0.018 23.499 ;
        RECT  0 22.941 0.018 22.959 ;
        RECT  0 22.401 0.018 22.419 ;
        RECT  0 21.861 0.018 21.879 ;
        RECT  0 21.321 0.018 21.339 ;
        RECT  0 20.781 0.018 20.799 ;
        RECT  0 20.241 0.018 20.259 ;
        RECT  0 19.701 0.018 19.719 ;
        RECT  0 19.161 0.018 19.179 ;
        RECT  0 18.621 0.018 18.639 ;
        RECT  0 18.081 0.018 18.099 ;
        RECT  0 17.541 0.018 17.559 ;
        RECT  0 17.001 0.018 17.019 ;
        RECT  0 16.461 0.018 16.479 ;
        RECT  0 15.921 0.018 15.939 ;
        RECT  0 15.381 0.018 15.399 ;
        RECT  0 14.841 0.018 14.859 ;
        RECT  0 14.301 0.018 14.319 ;
        RECT  0 13.761 0.018 13.779 ;
        RECT  0 13.221 0.018 13.239 ;
        RECT  0 12.681 0.018 12.699 ;
        RECT  0 12.141 0.018 12.159 ;
        RECT  0 11.601 0.018 11.619 ;
        RECT  0 11.061 0.018 11.079 ;
        RECT  0 10.521 0.018 10.539 ;
        RECT  0 9.981 0.018 9.999 ;
        RECT  0 9.441 0.018 9.459 ;
        RECT  0 8.901 0.018 8.919 ;
        RECT  0 8.361 0.018 8.379 ;
        RECT  0 7.821 0.018 7.839 ;
        RECT  0 7.281 0.018 7.299 ;
        RECT  0 6.741 0.018 6.759 ;
        RECT  0 6.201 0.018 6.219 ;
        RECT  0 5.661 0.018 5.679 ;
        RECT  0 5.121 0.018 5.139 ;
        RECT  0 4.581 0.018 4.599 ;
        RECT  0 4.041 0.018 4.059 ;
        RECT  0 3.501 0.018 3.519 ;
        RECT  0 2.961 0.018 2.979 ;
        RECT  0 2.421 0.018 2.439 ;
        RECT  0 1.881 0.018 1.899 ;
        RECT  0 1.341 0.018 1.359 ;
        RECT  0 0.801 0.018 0.819 ;
    END
  END VDD
  PIN VSS
    DIRECTION INOUT ;
    USE GROUND ;
    PORT
      LAYER M7 ;
        RECT  33.256 0.531 33.544 76.959 ;
        RECT  22.456 0.531 22.744 76.959 ;
        RECT  11.656 0.531 11.944 76.959 ;
        RECT  0.856 0.531 1.144 76.959 ;
      LAYER M6 ;
        RECT  0 76.596 0.032 76.884 ;
        RECT  0 71.196 0.032 71.484 ;
        RECT  0 65.796 0.032 66.084 ;
        RECT  0 60.396 0.032 60.684 ;
        RECT  0 54.996 0.032 55.284 ;
        RECT  0 49.596 0.032 49.884 ;
        RECT  0 44.196 0.032 44.484 ;
        RECT  0 38.796 0.032 39.084 ;
        RECT  0 33.396 0.032 33.684 ;
        RECT  0 27.996 0.032 28.284 ;
        RECT  0 22.596 0.032 22.884 ;
        RECT  0 17.196 0.032 17.484 ;
        RECT  0 11.796 0.032 12.084 ;
        RECT  0 6.396 0.032 6.684 ;
        RECT  0 0.996 0.032 1.284 ;
      LAYER M2 ;
        RECT  0 76.671 0.018 76.689 ;
        RECT  0 76.131 0.018 76.149 ;
        RECT  0 75.591 0.018 75.609 ;
        RECT  0 75.051 0.018 75.069 ;
        RECT  0 74.511 0.018 74.529 ;
        RECT  0 73.971 0.018 73.989 ;
        RECT  0 73.431 0.018 73.449 ;
        RECT  0 72.891 0.018 72.909 ;
        RECT  0 72.351 0.018 72.369 ;
        RECT  0 71.811 0.018 71.829 ;
        RECT  0 71.271 0.018 71.289 ;
        RECT  0 70.731 0.018 70.749 ;
        RECT  0 70.191 0.018 70.209 ;
        RECT  0 69.651 0.018 69.669 ;
        RECT  0 69.111 0.018 69.129 ;
        RECT  0 68.571 0.018 68.589 ;
        RECT  0 68.031 0.018 68.049 ;
        RECT  0 67.491 0.018 67.509 ;
        RECT  0 66.951 0.018 66.969 ;
        RECT  0 66.411 0.018 66.429 ;
        RECT  0 65.871 0.018 65.889 ;
        RECT  0 65.331 0.018 65.349 ;
        RECT  0 64.791 0.018 64.809 ;
        RECT  0 64.251 0.018 64.269 ;
        RECT  0 63.711 0.018 63.729 ;
        RECT  0 63.171 0.018 63.189 ;
        RECT  0 62.631 0.018 62.649 ;
        RECT  0 62.091 0.018 62.109 ;
        RECT  0 61.551 0.018 61.569 ;
        RECT  0 61.011 0.018 61.029 ;
        RECT  0 60.471 0.018 60.489 ;
        RECT  0 59.931 0.018 59.949 ;
        RECT  0 59.391 0.018 59.409 ;
        RECT  0 58.851 0.018 58.869 ;
        RECT  0 58.311 0.018 58.329 ;
        RECT  0 57.771 0.018 57.789 ;
        RECT  0 57.231 0.018 57.249 ;
        RECT  0 56.691 0.018 56.709 ;
        RECT  0 56.151 0.018 56.169 ;
        RECT  0 55.611 0.018 55.629 ;
        RECT  0 55.071 0.018 55.089 ;
        RECT  0 54.531 0.018 54.549 ;
        RECT  0 53.991 0.018 54.009 ;
        RECT  0 53.451 0.018 53.469 ;
        RECT  0 52.911 0.018 52.929 ;
        RECT  0 52.371 0.018 52.389 ;
        RECT  0 51.831 0.018 51.849 ;
        RECT  0 51.291 0.018 51.309 ;
        RECT  0 50.751 0.018 50.769 ;
        RECT  0 50.211 0.018 50.229 ;
        RECT  0 49.671 0.018 49.689 ;
        RECT  0 49.131 0.018 49.149 ;
        RECT  0 48.591 0.018 48.609 ;
        RECT  0 48.051 0.018 48.069 ;
        RECT  0 47.511 0.018 47.529 ;
        RECT  0 46.971 0.018 46.989 ;
        RECT  0 46.431 0.018 46.449 ;
        RECT  0 45.891 0.018 45.909 ;
        RECT  0 45.351 0.018 45.369 ;
        RECT  0 44.811 0.018 44.829 ;
        RECT  0 44.271 0.018 44.289 ;
        RECT  0 43.731 0.018 43.749 ;
        RECT  0 43.191 0.018 43.209 ;
        RECT  0 42.651 0.018 42.669 ;
        RECT  0 42.111 0.018 42.129 ;
        RECT  0 41.571 0.018 41.589 ;
        RECT  0 41.031 0.018 41.049 ;
        RECT  0 40.491 0.018 40.509 ;
        RECT  0 39.951 0.018 39.969 ;
        RECT  0 39.411 0.018 39.429 ;
        RECT  0 38.871 0.018 38.889 ;
        RECT  0 38.331 0.018 38.349 ;
        RECT  0 37.791 0.018 37.809 ;
        RECT  0 37.251 0.018 37.269 ;
        RECT  0 36.711 0.018 36.729 ;
        RECT  0 36.171 0.018 36.189 ;
        RECT  0 35.631 0.018 35.649 ;
        RECT  0 35.091 0.018 35.109 ;
        RECT  0 34.551 0.018 34.569 ;
        RECT  0 34.011 0.018 34.029 ;
        RECT  0 33.471 0.018 33.489 ;
        RECT  0 32.931 0.018 32.949 ;
        RECT  0 32.391 0.018 32.409 ;
        RECT  0 31.851 0.018 31.869 ;
        RECT  0 31.311 0.018 31.329 ;
        RECT  0 30.771 0.018 30.789 ;
        RECT  0 30.231 0.018 30.249 ;
        RECT  0 29.691 0.018 29.709 ;
        RECT  0 29.151 0.018 29.169 ;
        RECT  0 28.611 0.018 28.629 ;
        RECT  0 28.071 0.018 28.089 ;
        RECT  0 27.531 0.018 27.549 ;
        RECT  0 26.991 0.018 27.009 ;
        RECT  0 26.451 0.018 26.469 ;
        RECT  0 25.911 0.018 25.929 ;
        RECT  0 25.371 0.018 25.389 ;
        RECT  0 24.831 0.018 24.849 ;
        RECT  0 24.291 0.018 24.309 ;
        RECT  0 23.751 0.018 23.769 ;
        RECT  0 23.211 0.018 23.229 ;
        RECT  0 22.671 0.018 22.689 ;
        RECT  0 22.131 0.018 22.149 ;
        RECT  0 21.591 0.018 21.609 ;
        RECT  0 21.051 0.018 21.069 ;
        RECT  0 20.511 0.018 20.529 ;
        RECT  0 19.971 0.018 19.989 ;
        RECT  0 19.431 0.018 19.449 ;
        RECT  0 18.891 0.018 18.909 ;
        RECT  0 18.351 0.018 18.369 ;
        RECT  0 17.811 0.018 17.829 ;
        RECT  0 17.271 0.018 17.289 ;
        RECT  0 16.731 0.018 16.749 ;
        RECT  0 16.191 0.018 16.209 ;
        RECT  0 15.651 0.018 15.669 ;
        RECT  0 15.111 0.018 15.129 ;
        RECT  0 14.571 0.018 14.589 ;
        RECT  0 14.031 0.018 14.049 ;
        RECT  0 13.491 0.018 13.509 ;
        RECT  0 12.951 0.018 12.969 ;
        RECT  0 12.411 0.018 12.429 ;
        RECT  0 11.871 0.018 11.889 ;
        RECT  0 11.331 0.018 11.349 ;
        RECT  0 10.791 0.018 10.809 ;
        RECT  0 10.251 0.018 10.269 ;
        RECT  0 9.711 0.018 9.729 ;
        RECT  0 9.171 0.018 9.189 ;
        RECT  0 8.631 0.018 8.649 ;
        RECT  0 8.091 0.018 8.109 ;
        RECT  0 7.551 0.018 7.569 ;
        RECT  0 7.011 0.018 7.029 ;
        RECT  0 6.471 0.018 6.489 ;
        RECT  0 5.931 0.018 5.949 ;
        RECT  0 5.391 0.018 5.409 ;
        RECT  0 4.851 0.018 4.869 ;
        RECT  0 4.311 0.018 4.329 ;
        RECT  0 3.771 0.018 3.789 ;
        RECT  0 3.231 0.018 3.249 ;
        RECT  0 2.691 0.018 2.709 ;
        RECT  0 2.151 0.018 2.169 ;
        RECT  0 1.611 0.018 1.629 ;
        RECT  0 1.071 0.018 1.089 ;
        RECT  0 0.531 0.018 0.549 ;
      LAYER M1 ;
        RECT  0 76.671 0.018 76.689 ;
        RECT  0 76.131 0.018 76.149 ;
        RECT  0 75.591 0.018 75.609 ;
        RECT  0 75.051 0.018 75.069 ;
        RECT  0 74.511 0.018 74.529 ;
        RECT  0 73.971 0.018 73.989 ;
        RECT  0 73.431 0.018 73.449 ;
        RECT  0 72.891 0.018 72.909 ;
        RECT  0 72.351 0.018 72.369 ;
        RECT  0 71.811 0.018 71.829 ;
        RECT  0 71.271 0.018 71.289 ;
        RECT  0 70.731 0.018 70.749 ;
        RECT  0 70.191 0.018 70.209 ;
        RECT  0 69.651 0.018 69.669 ;
        RECT  0 69.111 0.018 69.129 ;
        RECT  0 68.571 0.018 68.589 ;
        RECT  0 68.031 0.018 68.049 ;
        RECT  0 67.491 0.018 67.509 ;
        RECT  0 66.951 0.018 66.969 ;
        RECT  0 66.411 0.018 66.429 ;
        RECT  0 65.871 0.018 65.889 ;
        RECT  0 65.331 0.018 65.349 ;
        RECT  0 64.791 0.018 64.809 ;
        RECT  0 64.251 0.018 64.269 ;
        RECT  0 63.711 0.018 63.729 ;
        RECT  0 63.171 0.018 63.189 ;
        RECT  0 62.631 0.018 62.649 ;
        RECT  0 62.091 0.018 62.109 ;
        RECT  0 61.551 0.018 61.569 ;
        RECT  0 61.011 0.018 61.029 ;
        RECT  0 60.471 0.018 60.489 ;
        RECT  0 59.931 0.018 59.949 ;
        RECT  0 59.391 0.018 59.409 ;
        RECT  0 58.851 0.018 58.869 ;
        RECT  0 58.311 0.018 58.329 ;
        RECT  0 57.771 0.018 57.789 ;
        RECT  0 57.231 0.018 57.249 ;
        RECT  0 56.691 0.018 56.709 ;
        RECT  0 56.151 0.018 56.169 ;
        RECT  0 55.611 0.018 55.629 ;
        RECT  0 55.071 0.018 55.089 ;
        RECT  0 54.531 0.018 54.549 ;
        RECT  0 53.991 0.018 54.009 ;
        RECT  0 53.451 0.018 53.469 ;
        RECT  0 52.911 0.018 52.929 ;
        RECT  0 52.371 0.018 52.389 ;
        RECT  0 51.831 0.018 51.849 ;
        RECT  0 51.291 0.018 51.309 ;
        RECT  0 50.751 0.018 50.769 ;
        RECT  0 50.211 0.018 50.229 ;
        RECT  0 49.671 0.018 49.689 ;
        RECT  0 49.131 0.018 49.149 ;
        RECT  0 48.591 0.018 48.609 ;
        RECT  0 48.051 0.018 48.069 ;
        RECT  0 47.511 0.018 47.529 ;
        RECT  0 46.971 0.018 46.989 ;
        RECT  0 46.431 0.018 46.449 ;
        RECT  0 45.891 0.018 45.909 ;
        RECT  0 45.351 0.018 45.369 ;
        RECT  0 44.811 0.018 44.829 ;
        RECT  0 44.271 0.018 44.289 ;
        RECT  0 43.731 0.018 43.749 ;
        RECT  0 43.191 0.018 43.209 ;
        RECT  0 42.651 0.018 42.669 ;
        RECT  0 42.111 0.018 42.129 ;
        RECT  0 41.571 0.018 41.589 ;
        RECT  0 41.031 0.018 41.049 ;
        RECT  0 40.491 0.018 40.509 ;
        RECT  0 39.951 0.018 39.969 ;
        RECT  0 39.411 0.018 39.429 ;
        RECT  0 38.871 0.018 38.889 ;
        RECT  0 38.331 0.018 38.349 ;
        RECT  0 37.791 0.018 37.809 ;
        RECT  0 37.251 0.018 37.269 ;
        RECT  0 36.711 0.018 36.729 ;
        RECT  0 36.171 0.018 36.189 ;
        RECT  0 35.631 0.018 35.649 ;
        RECT  0 35.091 0.018 35.109 ;
        RECT  0 34.551 0.018 34.569 ;
        RECT  0 34.011 0.018 34.029 ;
        RECT  0 33.471 0.018 33.489 ;
        RECT  0 32.931 0.018 32.949 ;
        RECT  0 32.391 0.018 32.409 ;
        RECT  0 31.851 0.018 31.869 ;
        RECT  0 31.311 0.018 31.329 ;
        RECT  0 30.771 0.018 30.789 ;
        RECT  0 30.231 0.018 30.249 ;
        RECT  0 29.691 0.018 29.709 ;
        RECT  0 29.151 0.018 29.169 ;
        RECT  0 28.611 0.018 28.629 ;
        RECT  0 28.071 0.018 28.089 ;
        RECT  0 27.531 0.018 27.549 ;
        RECT  0 26.991 0.018 27.009 ;
        RECT  0 26.451 0.018 26.469 ;
        RECT  0 25.911 0.018 25.929 ;
        RECT  0 25.371 0.018 25.389 ;
        RECT  0 24.831 0.018 24.849 ;
        RECT  0 24.291 0.018 24.309 ;
        RECT  0 23.751 0.018 23.769 ;
        RECT  0 23.211 0.018 23.229 ;
        RECT  0 22.671 0.018 22.689 ;
        RECT  0 22.131 0.018 22.149 ;
        RECT  0 21.591 0.018 21.609 ;
        RECT  0 21.051 0.018 21.069 ;
        RECT  0 20.511 0.018 20.529 ;
        RECT  0 19.971 0.018 19.989 ;
        RECT  0 19.431 0.018 19.449 ;
        RECT  0 18.891 0.018 18.909 ;
        RECT  0 18.351 0.018 18.369 ;
        RECT  0 17.811 0.018 17.829 ;
        RECT  0 17.271 0.018 17.289 ;
        RECT  0 16.731 0.018 16.749 ;
        RECT  0 16.191 0.018 16.209 ;
        RECT  0 15.651 0.018 15.669 ;
        RECT  0 15.111 0.018 15.129 ;
        RECT  0 14.571 0.018 14.589 ;
        RECT  0 14.031 0.018 14.049 ;
        RECT  0 13.491 0.018 13.509 ;
        RECT  0 12.951 0.018 12.969 ;
        RECT  0 12.411 0.018 12.429 ;
        RECT  0 11.871 0.018 11.889 ;
        RECT  0 11.331 0.018 11.349 ;
        RECT  0 10.791 0.018 10.809 ;
        RECT  0 10.251 0.018 10.269 ;
        RECT  0 9.711 0.018 9.729 ;
        RECT  0 9.171 0.018 9.189 ;
        RECT  0 8.631 0.018 8.649 ;
        RECT  0 8.091 0.018 8.109 ;
        RECT  0 7.551 0.018 7.569 ;
        RECT  0 7.011 0.018 7.029 ;
        RECT  0 6.471 0.018 6.489 ;
        RECT  0 5.931 0.018 5.949 ;
        RECT  0 5.391 0.018 5.409 ;
        RECT  0 4.851 0.018 4.869 ;
        RECT  0 4.311 0.018 4.329 ;
        RECT  0 3.771 0.018 3.789 ;
        RECT  0 3.231 0.018 3.249 ;
        RECT  0 2.691 0.018 2.709 ;
        RECT  0 2.151 0.018 2.169 ;
        RECT  0 1.611 0.018 1.629 ;
        RECT  0 1.071 0.018 1.089 ;
        RECT  0 0.531 0.018 0.549 ;
    END
  END VSS
  OBS
    LAYER RVTN ;
     RECT  0 0.54 39.258 0.675 ;
     RECT  0 0.945 39.258 1.215 ;
     RECT  0 1.485 39.258 1.755 ;
     RECT  0 2.025 39.258 2.295 ;
     RECT  0 2.565 39.258 2.835 ;
     RECT  0 3.105 39.258 3.375 ;
     RECT  0 3.645 39.258 3.915 ;
     RECT  0 4.185 39.258 4.455 ;
     RECT  0 4.725 39.258 4.995 ;
     RECT  0 5.265 39.258 5.535 ;
     RECT  0 5.805 39.258 6.075 ;
     RECT  0 6.345 39.258 6.615 ;
     RECT  0 6.885 39.258 7.155 ;
     RECT  0 7.425 39.258 7.695 ;
     RECT  0 7.965 39.258 8.235 ;
     RECT  0 8.505 39.258 8.775 ;
     RECT  0 9.045 39.258 9.315 ;
     RECT  0 9.585 39.258 9.855 ;
     RECT  0 10.125 39.258 10.395 ;
     RECT  0 10.665 39.258 10.935 ;
     RECT  0 11.205 39.258 11.475 ;
     RECT  0 11.745 39.258 12.015 ;
     RECT  0 12.285 39.258 12.555 ;
     RECT  0 12.825 39.258 13.095 ;
     RECT  0 13.365 39.258 13.635 ;
     RECT  0 13.905 39.258 14.175 ;
     RECT  0 14.445 39.258 14.715 ;
     RECT  0 14.985 39.258 15.255 ;
     RECT  0 15.525 39.258 15.795 ;
     RECT  0 16.065 39.258 16.335 ;
     RECT  0 16.605 39.258 16.875 ;
     RECT  0 17.145 39.258 17.415 ;
     RECT  0 17.685 39.258 17.955 ;
     RECT  0 18.225 39.258 18.495 ;
     RECT  0 18.765 39.258 19.035 ;
     RECT  0 19.305 39.258 19.575 ;
     RECT  0 19.845 39.258 20.115 ;
     RECT  0 20.385 39.258 20.655 ;
     RECT  0 20.925 39.258 21.195 ;
     RECT  0 21.465 39.258 21.735 ;
     RECT  0 22.005 39.258 22.275 ;
     RECT  0 22.545 39.258 22.815 ;
     RECT  0 23.085 39.258 23.355 ;
     RECT  0 23.625 39.258 23.895 ;
     RECT  0 24.165 39.258 24.435 ;
     RECT  0 24.705 39.258 24.975 ;
     RECT  0 25.245 39.258 25.515 ;
     RECT  0 25.785 39.258 26.055 ;
     RECT  0 26.325 39.258 26.595 ;
     RECT  0 26.865 39.258 27.135 ;
     RECT  0 27.405 39.258 27.675 ;
     RECT  0 27.945 39.258 28.215 ;
     RECT  0 28.485 39.258 28.755 ;
     RECT  0 29.025 39.258 29.295 ;
     RECT  0 29.565 39.258 29.835 ;
     RECT  0 30.105 39.258 30.375 ;
     RECT  0 30.645 39.258 30.915 ;
     RECT  0 31.185 39.258 31.455 ;
     RECT  0 31.725 39.258 31.995 ;
     RECT  0 32.265 39.258 32.535 ;
     RECT  0 32.805 39.258 33.075 ;
     RECT  0 33.345 39.258 33.615 ;
     RECT  0 33.885 39.258 34.155 ;
     RECT  0 34.425 39.258 34.695 ;
     RECT  0 34.965 39.258 35.235 ;
     RECT  0 35.505 39.258 35.775 ;
     RECT  0 36.045 39.258 36.315 ;
     RECT  0 36.585 39.258 36.855 ;
     RECT  0 37.125 39.258 37.395 ;
     RECT  0 37.665 39.258 37.935 ;
     RECT  0 38.205 39.258 38.475 ;
     RECT  0 38.745 39.258 39.015 ;
     RECT  0 39.285 39.258 39.555 ;
     RECT  0 39.825 39.258 40.095 ;
     RECT  0 40.365 39.258 40.635 ;
     RECT  0 40.905 39.258 41.175 ;
     RECT  0 41.445 39.258 41.715 ;
     RECT  0 41.985 39.258 42.255 ;
     RECT  0 42.525 39.258 42.795 ;
     RECT  0 43.065 39.258 43.335 ;
     RECT  0 43.605 39.258 43.875 ;
     RECT  0 44.145 39.258 44.415 ;
     RECT  0 44.685 39.258 44.955 ;
     RECT  0 45.225 39.258 45.495 ;
     RECT  0 45.765 39.258 46.035 ;
     RECT  0 46.305 39.258 46.575 ;
     RECT  0 46.845 39.258 47.115 ;
     RECT  0 47.385 39.258 47.655 ;
     RECT  0 47.925 39.258 48.195 ;
     RECT  0 48.465 39.258 48.735 ;
     RECT  0 49.005 39.258 49.275 ;
     RECT  0 49.545 39.258 49.815 ;
     RECT  0 50.085 39.258 50.355 ;
     RECT  0 50.625 39.258 50.895 ;
     RECT  0 51.165 39.258 51.435 ;
     RECT  0 51.705 39.258 51.975 ;
     RECT  0 52.245 39.258 52.515 ;
     RECT  0 52.785 39.258 53.055 ;
     RECT  0 53.325 39.258 53.595 ;
     RECT  0 53.865 39.258 54.135 ;
     RECT  0 54.405 39.258 54.675 ;
     RECT  0 54.945 39.258 55.215 ;
     RECT  0 55.485 39.258 55.755 ;
     RECT  0 56.025 39.258 56.295 ;
     RECT  0 56.565 39.258 56.835 ;
     RECT  0 57.105 39.258 57.375 ;
     RECT  0 57.645 39.258 57.915 ;
     RECT  0 58.185 39.258 58.455 ;
     RECT  0 58.725 39.258 58.995 ;
     RECT  0 59.265 39.258 59.535 ;
     RECT  0 59.805 39.258 60.075 ;
     RECT  0 60.345 39.258 60.615 ;
     RECT  0 60.885 39.258 61.155 ;
     RECT  0 61.425 39.258 61.695 ;
     RECT  0 61.965 39.258 62.235 ;
     RECT  0 62.505 39.258 62.775 ;
     RECT  0 63.045 39.258 63.315 ;
     RECT  0 63.585 39.258 63.855 ;
     RECT  0 64.125 39.258 64.395 ;
     RECT  0 64.665 39.258 64.935 ;
     RECT  0 65.205 39.258 65.475 ;
     RECT  0 65.745 39.258 66.015 ;
     RECT  0 66.285 39.258 66.555 ;
     RECT  0 66.825 39.258 67.095 ;
     RECT  0 67.365 39.258 67.635 ;
     RECT  0 67.905 39.258 68.175 ;
     RECT  0 68.445 39.258 68.715 ;
     RECT  0 68.985 39.258 69.255 ;
     RECT  0 69.525 39.258 69.795 ;
     RECT  0 70.065 39.258 70.335 ;
     RECT  0 70.605 39.258 70.875 ;
     RECT  0 71.145 39.258 71.415 ;
     RECT  0 71.685 39.258 71.955 ;
     RECT  0 72.225 39.258 72.495 ;
     RECT  0 72.765 39.258 73.035 ;
     RECT  0 73.305 39.258 73.575 ;
     RECT  0 73.845 39.258 74.115 ;
     RECT  0 74.385 39.258 74.655 ;
     RECT  0 74.925 39.258 75.195 ;
     RECT  0 75.465 39.258 75.735 ;
     RECT  0 76.005 39.258 76.275 ;
     RECT  0 76.545 39.258 76.815 ;
    LAYER RVTP ;
     RECT  0 0.675 39.258 0.945 ;
     RECT  0 1.215 39.258 1.485 ;
     RECT  0 1.755 39.258 2.025 ;
     RECT  0 2.295 39.258 2.565 ;
     RECT  0 2.835 39.258 3.105 ;
     RECT  0 3.375 39.258 3.645 ;
     RECT  0 3.915 39.258 4.185 ;
     RECT  0 4.455 39.258 4.725 ;
     RECT  0 4.995 39.258 5.265 ;
     RECT  0 5.535 39.258 5.805 ;
     RECT  0 6.075 39.258 6.345 ;
     RECT  0 6.615 39.258 6.885 ;
     RECT  0 7.155 39.258 7.425 ;
     RECT  0 7.695 39.258 7.965 ;
     RECT  0 8.235 39.258 8.505 ;
     RECT  0 8.775 39.258 9.045 ;
     RECT  0 9.315 39.258 9.585 ;
     RECT  0 9.855 39.258 10.125 ;
     RECT  0 10.395 39.258 10.665 ;
     RECT  0 10.935 39.258 11.205 ;
     RECT  0 11.475 39.258 11.745 ;
     RECT  0 12.015 39.258 12.285 ;
     RECT  0 12.555 39.258 12.825 ;
     RECT  0 13.095 39.258 13.365 ;
     RECT  0 13.635 39.258 13.905 ;
     RECT  0 14.175 39.258 14.445 ;
     RECT  0 14.715 39.258 14.985 ;
     RECT  0 15.255 39.258 15.525 ;
     RECT  0 15.795 39.258 16.065 ;
     RECT  0 16.335 39.258 16.605 ;
     RECT  0 16.875 39.258 17.145 ;
     RECT  0 17.415 39.258 17.685 ;
     RECT  0 17.955 39.258 18.225 ;
     RECT  0 18.495 39.258 18.765 ;
     RECT  0 19.035 39.258 19.305 ;
     RECT  0 19.575 39.258 19.845 ;
     RECT  0 20.115 39.258 20.385 ;
     RECT  0 20.655 39.258 20.925 ;
     RECT  0 21.195 39.258 21.465 ;
     RECT  0 21.735 39.258 22.005 ;
     RECT  0 22.275 39.258 22.545 ;
     RECT  0 22.815 39.258 23.085 ;
     RECT  0 23.355 39.258 23.625 ;
     RECT  0 23.895 39.258 24.165 ;
     RECT  0 24.435 39.258 24.705 ;
     RECT  0 24.975 39.258 25.245 ;
     RECT  0 25.515 39.258 25.785 ;
     RECT  0 26.055 39.258 26.325 ;
     RECT  0 26.595 39.258 26.865 ;
     RECT  0 27.135 39.258 27.405 ;
     RECT  0 27.675 39.258 27.945 ;
     RECT  0 28.215 39.258 28.485 ;
     RECT  0 28.755 39.258 29.025 ;
     RECT  0 29.295 39.258 29.565 ;
     RECT  0 29.835 39.258 30.105 ;
     RECT  0 30.375 39.258 30.645 ;
     RECT  0 30.915 39.258 31.185 ;
     RECT  0 31.455 39.258 31.725 ;
     RECT  0 31.995 39.258 32.265 ;
     RECT  0 32.535 39.258 32.805 ;
     RECT  0 33.075 39.258 33.345 ;
     RECT  0 33.615 39.258 33.885 ;
     RECT  0 34.155 39.258 34.425 ;
     RECT  0 34.695 39.258 34.965 ;
     RECT  0 35.235 39.258 35.505 ;
     RECT  0 35.775 39.258 36.045 ;
     RECT  0 36.315 39.258 36.585 ;
     RECT  0 36.855 39.258 37.125 ;
     RECT  0 37.395 39.258 37.665 ;
     RECT  0 37.935 39.258 38.205 ;
     RECT  0 38.475 39.258 38.745 ;
     RECT  0 39.015 39.258 39.285 ;
     RECT  0 39.555 39.258 39.825 ;
     RECT  0 40.095 39.258 40.365 ;
     RECT  0 40.635 39.258 40.905 ;
     RECT  0 41.175 39.258 41.445 ;
     RECT  0 41.715 39.258 41.985 ;
     RECT  0 42.255 39.258 42.525 ;
     RECT  0 42.795 39.258 43.065 ;
     RECT  0 43.335 39.258 43.605 ;
     RECT  0 43.875 39.258 44.145 ;
     RECT  0 44.415 39.258 44.685 ;
     RECT  0 44.955 39.258 45.225 ;
     RECT  0 45.495 39.258 45.765 ;
     RECT  0 46.035 39.258 46.305 ;
     RECT  0 46.575 39.258 46.845 ;
     RECT  0 47.115 39.258 47.385 ;
     RECT  0 47.655 39.258 47.925 ;
     RECT  0 48.195 39.258 48.465 ;
     RECT  0 48.735 39.258 49.005 ;
     RECT  0 49.275 39.258 49.545 ;
     RECT  0 49.815 39.258 50.085 ;
     RECT  0 50.355 39.258 50.625 ;
     RECT  0 50.895 39.258 51.165 ;
     RECT  0 51.435 39.258 51.705 ;
     RECT  0 51.975 39.258 52.245 ;
     RECT  0 52.515 39.258 52.785 ;
     RECT  0 53.055 39.258 53.325 ;
     RECT  0 53.595 39.258 53.865 ;
     RECT  0 54.135 39.258 54.405 ;
     RECT  0 54.675 39.258 54.945 ;
     RECT  0 55.215 39.258 55.485 ;
     RECT  0 55.755 39.258 56.025 ;
     RECT  0 56.295 39.258 56.565 ;
     RECT  0 56.835 39.258 57.105 ;
     RECT  0 57.375 39.258 57.645 ;
     RECT  0 57.915 39.258 58.185 ;
     RECT  0 58.455 39.258 58.725 ;
     RECT  0 58.995 39.258 59.265 ;
     RECT  0 59.535 39.258 59.805 ;
     RECT  0 60.075 39.258 60.345 ;
     RECT  0 60.615 39.258 60.885 ;
     RECT  0 61.155 39.258 61.425 ;
     RECT  0 61.695 39.258 61.965 ;
     RECT  0 62.235 39.258 62.505 ;
     RECT  0 62.775 39.258 63.045 ;
     RECT  0 63.315 39.258 63.585 ;
     RECT  0 63.855 39.258 64.125 ;
     RECT  0 64.395 39.258 64.665 ;
     RECT  0 64.935 39.258 65.205 ;
     RECT  0 65.475 39.258 65.745 ;
     RECT  0 66.015 39.258 66.285 ;
     RECT  0 66.555 39.258 66.825 ;
     RECT  0 67.095 39.258 67.365 ;
     RECT  0 67.635 39.258 67.905 ;
     RECT  0 68.175 39.258 68.445 ;
     RECT  0 68.715 39.258 68.985 ;
     RECT  0 69.255 39.258 69.525 ;
     RECT  0 69.795 39.258 70.065 ;
     RECT  0 70.335 39.258 70.605 ;
     RECT  0 70.875 39.258 71.145 ;
     RECT  0 71.415 39.258 71.685 ;
     RECT  0 71.955 39.258 72.225 ;
     RECT  0 72.495 39.258 72.765 ;
     RECT  0 73.035 39.258 73.305 ;
     RECT  0 73.575 39.258 73.845 ;
     RECT  0 74.115 39.258 74.385 ;
     RECT  0 74.655 39.258 74.925 ;
     RECT  0 75.195 39.258 75.465 ;
     RECT  0 75.735 39.258 76.005 ;
     RECT  0 76.275 39.258 76.545 ;
     RECT  0 76.815 39.258 76.95 ;
    LAYER M1 ;
     RECT  0 0.531 39.258 76.959 ;
    LAYER M2 ;
     RECT  0 0.531 31.423 76.959 ;
     RECT  31.423 0.531 31.955 77.418 ;
     RECT  31.955 0.531 33.539 77.076 ;
     RECT  33.539 0.531 37.903 76.959 ;
     RECT  37.903 0.486 37.975 76.959 ;
     RECT  37.975 0.414 38.111 76.959 ;
     RECT  38.111 0.486 38.255 76.959 ;
     RECT  38.255 0.531 39.258 76.959 ;
    LAYER M3 ;
     RECT  37.692 0.091 37.71 0.139 ;
     RECT  34.704 0.043 34.722 0.187 ;
     RECT  37.692 0.139 38.466 0.187 ;
     RECT  16.992 0.187 17.01 0.235 ;
     RECT  32.832 0.187 33.21 0.235 ;
     RECT  16.2 0.235 17.01 0.283 ;
     RECT  21.636 0.187 21.654 0.283 ;
     RECT  26.568 0.187 26.586 0.283 ;
     RECT  31.176 0.187 31.194 0.283 ;
     RECT  32.256 0.235 33.282 0.283 ;
     RECT  34.704 0.187 34.758 0.283 ;
     RECT  36.036 0.043 36.054 0.283 ;
     RECT  37.404 0.187 38.466 0.283 ;
     RECT  34.308 0.283 38.466 0.317 ;
     RECT  15.084 0.283 17.01 0.331 ;
     RECT  19.368 0.283 19.386 0.331 ;
     RECT  20.556 0.283 21.726 0.331 ;
     RECT  25.128 0.283 25.146 0.331 ;
     RECT  34.308 0.317 38.358 0.365 ;
     RECT  24.084 0.283 24.318 0.379 ;
     RECT  29.484 0.283 29.502 0.379 ;
     RECT  30.528 0.283 33.282 0.379 ;
     RECT  34.308 0.365 38.337 0.379 ;
     RECT  30.528 0.379 38.337 0.413 ;
     RECT  15.084 0.331 17.478 0.427 ;
     RECT  18.216 0.331 18.234 0.427 ;
     RECT  14.796 0.427 17.478 0.475 ;
     RECT  18.216 0.427 18.27 0.475 ;
     RECT  19.368 0.331 19.494 0.475 ;
     RECT  22.968 0.283 22.986 0.475 ;
     RECT  23.832 0.379 24.318 0.475 ;
     RECT  25.128 0.331 25.254 0.475 ;
     RECT  20.556 0.331 21.798 0.523 ;
     RECT  26.064 0.283 28.53 0.523 ;
     RECT  29.484 0.379 29.718 0.523 ;
     RECT  19.008 0.475 19.494 0.571 ;
     RECT  20.556 0.523 21.945 0.571 ;
     RECT  25.992 0.523 29.718 0.571 ;
     RECT  14.112 0.475 18.27 0.619 ;
     RECT  19.008 0.571 22.194 0.619 ;
     RECT  22.968 0.475 25.254 0.619 ;
     RECT  0.255 0.523 0.345 0.793 ;
     RECT  5.655 0.523 5.745 0.793 ;
     RECT  11.055 0.523 11.145 0.793 ;
     RECT  13.14 0.523 13.158 1.051 ;
     RECT  14.112 0.619 22.194 1.051 ;
     RECT  13.14 1.051 22.194 1.099 ;
     RECT  22.932 0.619 25.254 1.099 ;
     RECT  25.992 0.571 29.754 1.099 ;
     RECT  30.744 0.413 38.337 1.387 ;
     RECT  13.14 1.099 29.754 1.687 ;
     RECT  30.564 1.387 38.337 1.687 ;
     RECT  13.14 1.687 38.337 2.065 ;
     RECT  11.055 0.793 11.337 2.191 ;
     RECT  12.888 2.065 38.337 2.605 ;
     RECT  11.055 2.191 11.538 2.731 ;
     RECT  8.928 3.181 8.946 3.271 ;
     RECT  8.928 3.271 9.054 3.541 ;
     RECT  11.055 2.731 11.718 3.721 ;
     RECT  12.528 2.605 38.337 3.721 ;
     RECT  8.46 3.541 9.054 4.189 ;
     RECT  8.46 4.189 9.45 4.621 ;
     RECT  10.26 3.145 10.278 4.621 ;
     RECT  8.46 4.621 10.278 4.729 ;
     RECT  11.055 3.721 38.337 4.729 ;
     RECT  8.46 4.729 38.337 4.829 ;
     RECT  12.096 4.829 38.337 4.919 ;
     RECT  12.24 4.919 38.337 4.973 ;
     RECT  12.456 4.973 38.337 5.117 ;
     RECT  8.46 4.829 11.337 7.483 ;
     RECT  12.888 5.117 38.337 7.799 ;
     RECT  8.46 7.483 11.394 8.167 ;
     RECT  8.46 8.167 11.862 8.401 ;
     RECT  12.888 7.799 36.522 8.401 ;
     RECT  8.46 8.401 36.522 8.525 ;
     RECT  37.404 7.799 38.337 8.581 ;
     RECT  12.888 8.525 36.522 8.851 ;
     RECT  37.296 8.581 38.337 8.851 ;
     RECT  8.46 8.525 11.862 9.391 ;
     RECT  8.46 9.391 12.114 9.481 ;
     RECT  12.888 8.851 38.337 9.481 ;
     RECT  8.46 9.481 38.337 10.589 ;
     RECT  12.096 10.589 38.337 11.947 ;
     RECT  12.06 11.947 38.337 12.209 ;
     RECT  12.888 12.209 38.337 12.479 ;
     RECT  12.888 12.479 36.522 12.749 ;
     RECT  8.46 10.589 11.337 13.639 ;
     RECT  12.06 12.209 12.114 13.639 ;
     RECT  8.46 13.639 12.114 14.881 ;
     RECT  12.888 12.749 35.91 14.881 ;
     RECT  37.404 12.479 38.337 15.251 ;
     RECT  36.756 15.331 36.99 15.989 ;
     RECT  36.756 15.989 36.774 16.133 ;
     RECT  8.46 14.881 35.91 16.141 ;
     RECT  8.46 16.141 35.982 17.951 ;
     RECT  8.46 17.951 15.03 18.769 ;
     RECT  8.46 18.769 15.066 18.859 ;
     RECT  15.804 17.951 35.982 18.859 ;
     RECT  8.46 18.859 35.982 21.119 ;
     RECT  18.252 21.119 35.982 21.163 ;
     RECT  18.252 21.163 36.45 21.659 ;
     RECT  18.252 21.659 36.018 21.677 ;
     RECT  8.46 21.119 17.478 22.081 ;
     RECT  18.252 21.677 35.982 22.081 ;
     RECT  36.756 21.739 37.026 22.199 ;
     RECT  8.46 22.081 35.982 23.035 ;
     RECT  36.756 22.199 36.774 23.035 ;
     RECT  8.46 23.035 36.774 23.081 ;
     RECT  36.756 23.081 36.774 23.279 ;
     RECT  8.46 23.081 35.982 23.947 ;
     RECT  8.46 23.947 36.27 24.359 ;
     RECT  37.224 25.099 37.242 25.169 ;
     RECT  36.72 25.321 37.026 25.709 ;
     RECT  36.72 25.709 36.738 25.979 ;
     RECT  8.46 24.359 35.982 26.923 ;
     RECT  8.46 26.923 36.378 27.329 ;
     RECT  36.9 29.659 36.918 30.029 ;
     RECT  8.46 27.329 35.982 30.139 ;
     RECT  8.46 30.139 36.522 30.179 ;
     RECT  38.055 15.251 38.337 30.811 ;
     RECT  37.836 30.811 38.337 30.991 ;
     RECT  37.44 30.991 38.337 31.037 ;
     RECT  8.46 30.179 35.982 31.339 ;
     RECT  8.46 31.339 36.27 31.963 ;
     RECT  8.46 31.963 36.702 32.189 ;
     RECT  8.46 32.189 36.198 32.381 ;
     RECT  37.116 32.539 37.134 32.999 ;
     RECT  8.46 32.381 35.982 37.675 ;
     RECT  8.46 37.675 36.054 38.129 ;
     RECT  7.704 3.811 7.722 38.669 ;
     RECT  7.596 38.677 7.614 38.765 ;
     RECT  8.46 38.129 35.982 53.905 ;
     RECT  7.956 53.905 35.982 54.599 ;
     RECT  7.956 54.599 35.154 55.277 ;
     RECT  8.46 55.277 35.154 56.875 ;
     RECT  8.352 56.875 35.154 60.989 ;
     RECT  8.496 60.989 35.154 63.821 ;
     RECT  8.532 63.821 35.154 64.459 ;
     RECT  35.964 54.599 35.982 64.459 ;
     RECT  8.532 64.459 35.982 64.589 ;
     RECT  8.532 64.589 35.19 65.785 ;
     RECT  8.496 65.785 35.19 66.209 ;
     RECT  8.496 66.209 35.154 68.957 ;
     RECT  8.82 68.957 35.154 71.608 ;
     RECT  8.82 71.608 35.19 71.645 ;
     RECT  8.82 71.645 35.154 73.565 ;
     RECT  8.82 73.565 26.442 74.425 ;
     RECT  27.255 73.565 35.154 74.425 ;
     RECT  35.964 64.589 35.982 74.849 ;
     RECT  8.244 74.425 35.154 75.227 ;
     RECT  35.136 75.227 35.154 75.659 ;
     RECT  8.244 75.227 34.254 76.157 ;
     RECT  8.244 76.157 30.114 76.397 ;
     RECT  0.255 0.793 0.537 76.697 ;
     RECT  5.655 0.793 5.937 76.697 ;
     RECT  38.055 31.037 38.337 76.697 ;
     RECT  0.447 76.697 0.537 76.967 ;
     RECT  5.847 76.697 5.937 76.967 ;
     RECT  38.247 76.697 38.337 76.967 ;
     RECT  8.244 76.397 30.078 76.973 ;
     RECT  31.104 76.157 34.254 76.973 ;
     RECT  8.244 76.973 24.75 77.021 ;
     RECT  25.56 76.973 30.078 77.021 ;
     RECT  8.244 77.021 12.51 77.069 ;
     RECT  13.644 77.021 23.742 77.069 ;
     RECT  24.732 77.021 24.75 77.069 ;
     RECT  25.56 77.021 26.334 77.069 ;
     RECT  27.072 77.021 30.078 77.069 ;
     RECT  33.012 76.973 33.534 77.081 ;
     RECT  13.644 77.069 19.638 77.117 ;
     RECT  20.844 77.069 20.862 77.117 ;
     RECT  21.6 77.069 23.706 77.117 ;
     RECT  26.316 77.069 26.334 77.117 ;
     RECT  8.244 77.069 11.502 77.165 ;
     RECT  13.644 77.117 13.77 77.165 ;
     RECT  14.796 77.117 14.994 77.165 ;
     RECT  16.056 77.117 19.638 77.165 ;
     RECT  25.56 77.069 25.578 77.165 ;
     RECT  27.072 77.069 28.314 77.165 ;
     RECT  29.16 77.069 30.078 77.165 ;
     RECT  10.044 77.165 10.062 77.213 ;
     RECT  10.836 77.165 11.214 77.213 ;
     RECT  14.796 77.165 14.814 77.213 ;
     RECT  16.056 77.165 19.134 77.213 ;
     RECT  21.6 77.117 22.446 77.213 ;
     RECT  23.22 77.117 23.706 77.213 ;
     RECT  27.18 77.165 28.314 77.213 ;
     RECT  30.06 77.165 30.078 77.213 ;
     RECT  31.104 76.973 32.238 77.227 ;
     RECT  12.456 77.069 12.474 77.261 ;
     RECT  16.056 77.213 18.378 77.261 ;
     RECT  13.644 77.165 13.662 77.309 ;
     RECT  31.032 77.227 32.238 77.309 ;
     RECT  33.012 77.081 33.03 77.357 ;
     RECT  10.836 77.213 11.034 77.405 ;
     RECT  16.272 77.261 17.946 77.405 ;
     RECT  21.672 77.213 22.446 77.405 ;
     RECT  27.792 77.213 28.314 77.405 ;
     RECT  31.032 77.309 31.95 77.405 ;
     RECT  31.428 77.405 31.95 77.423 ;
     RECT  10.908 77.405 10.926 77.453 ;
     RECT  16.272 77.405 16.29 77.453 ;
     RECT  17.028 77.405 17.766 77.453 ;
     RECT  19.116 77.213 19.134 77.453 ;
     RECT  21.852 77.405 21.87 77.453 ;
     RECT  23.22 77.213 23.238 77.453 ;
     RECT  27.792 77.405 27.99 77.453 ;
     RECT  31.428 77.423 31.77 77.453 ;
     RECT  17.028 77.453 17.046 77.501 ;
     RECT  31.428 77.453 31.446 77.501 ;
     RECT  27.792 77.453 27.81 77.549 ;
    LAYER M4 ;
     RECT  0.248 0.528 0.352 76.692 ;
     RECT  0.352 0.798 0.44 76.692 ;
     RECT  0.44 0.798 0.544 76.962 ;
     RECT  5.648 0.528 5.752 76.692 ;
     RECT  5.752 0.798 5.84 76.692 ;
     RECT  5.84 0.798 5.944 76.962 ;
     RECT  7.333 57.6 7.429 57.624 ;
     RECT  7.525 74.688 7.621 74.712 ;
     RECT  7.585 38.736 7.669 38.76 ;
     RECT  7.429 57.024 7.669 57.624 ;
     RECT  7.621 74.688 7.717 74.808 ;
     RECT  7.717 74.688 7.765 74.904 ;
     RECT  7.813 76.944 7.861 76.968 ;
     RECT  7.765 74.688 7.907 75 ;
     RECT  7.861 76.944 7.909 77.064 ;
     RECT  7.907 74.784 7.955 75 ;
     RECT  7.477 55.248 7.985 55.272 ;
     RECT  7.381 61.536 8.053 61.56 ;
     RECT  8.101 63.792 8.197 63.816 ;
     RECT  7.813 68.784 8.293 68.808 ;
     RECT  8.149 66.672 8.341 66.696 ;
     RECT  8.053 60.96 8.381 61.56 ;
     RECT  8.197 63.792 8.525 64.2 ;
     RECT  8.293 68.784 8.525 68.952 ;
     RECT  7.765 65.52 8.533 65.544 ;
     RECT  8.341 66.672 8.533 67.272 ;
     RECT  8.245 71.232 8.581 71.256 ;
     RECT  8.525 64.176 8.629 64.2 ;
     RECT  8.381 61.536 8.705 61.56 ;
     RECT  8.725 55.296 8.915 55.896 ;
     RECT  8.915 55.872 8.921 55.896 ;
     RECT  8.581 70.656 9.013 71.256 ;
     RECT  7.669 57.024 9.137 57.72 ;
     RECT  8.629 64.176 9.137 64.44 ;
     RECT  8.525 68.784 9.281 68.808 ;
     RECT  7.909 76.944 9.301 77.16 ;
     RECT  9.013 70.128 9.353 71.256 ;
     RECT  9.137 57.024 9.389 57.048 ;
     RECT  9.061 74.976 9.397 75 ;
     RECT  9.397 74.976 9.493 75.96 ;
     RECT  8.533 65.52 9.497 67.272 ;
     RECT  9.137 64.416 9.541 64.44 ;
     RECT  9.541 64.416 9.677 65.016 ;
     RECT  9.493 74.592 9.781 75.96 ;
     RECT  9.301 76.944 9.781 77.208 ;
     RECT  7.717 59.232 9.785 59.256 ;
     RECT  9.497 66.048 9.853 67.272 ;
     RECT  7.573 41.76 10.001 41.784 ;
     RECT  9.677 64.656 10.549 65.016 ;
     RECT  9.853 66.048 10.549 68.664 ;
     RECT  10.021 58.128 10.7 58.152 ;
     RECT  10.141 54.096 10.717 54.12 ;
     RECT  10.405 60.288 10.741 60.312 ;
     RECT  10.549 64.656 10.741 68.664 ;
     RECT  9.157 72.384 10.741 72.408 ;
     RECT  10.069 73.488 10.741 73.512 ;
     RECT  10.357 62.16 10.748 62.184 ;
     RECT  10.741 63.792 10.748 68.664 ;
     RECT  10.717 55.824 10.789 55.848 ;
     RECT  10.741 72.384 10.825 73.512 ;
     RECT  9.781 74.592 10.825 77.208 ;
     RECT  10.825 25.824 10.837 25.848 ;
     RECT  8.953 3.84 10.885 3.864 ;
     RECT  9.745 4.944 10.885 4.968 ;
     RECT  10.853 28.464 10.885 28.488 ;
     RECT  10.609 31.392 10.897 31.416 ;
     RECT  10.825 72.384 10.897 77.4 ;
     RECT  10.885 3.84 11.048 4.968 ;
     RECT  10.825 7.92 11.048 7.944 ;
     RECT  10.573 10.176 11.048 10.2 ;
     RECT  10.933 12.144 11.048 12.168 ;
     RECT  10.933 13.248 11.048 13.272 ;
     RECT  10.933 19.344 11.048 19.368 ;
     RECT  10.837 22.8 11.048 22.824 ;
     RECT  10.933 24.384 11.048 24.408 ;
     RECT  10.837 25.824 11.048 26.04 ;
     RECT  10.885 28.464 11.048 29.16 ;
     RECT  10.897 31.392 11.048 31.8 ;
     RECT  10.789 51.888 11.048 51.912 ;
     RECT  10.717 54.096 11.048 54.744 ;
     RECT  10.789 55.824 11.048 55.944 ;
     RECT  10.7 57.168 11.048 58.152 ;
     RECT  10.741 59.856 11.048 60.312 ;
     RECT  10.748 62.16 11.048 68.664 ;
     RECT  9.353 70.128 11.048 71.208 ;
     RECT  10.897 72.384 11.048 77.448 ;
     RECT  11.048 0.528 11.152 77.448 ;
     RECT  11.152 0.798 11.344 77.448 ;
     RECT  11.344 73.584 11.363 77.448 ;
     RECT  11.344 62.736 11.369 64.968 ;
     RECT  11.344 66.048 11.405 66.072 ;
     RECT  11.363 73.584 11.411 77.304 ;
     RECT  11.344 10.176 11.441 10.2 ;
     RECT  11.344 7.488 11.459 7.512 ;
     RECT  11.369 62.736 11.477 64.92 ;
     RECT  11.344 26.016 11.513 26.04 ;
     RECT  11.477 62.736 11.521 64.68 ;
     RECT  11.344 67.248 11.651 67.416 ;
     RECT  11.344 51.792 11.699 51.816 ;
     RECT  11.344 48.816 11.765 50.76 ;
     RECT  11.344 58.704 11.765 58.728 ;
     RECT  11.411 73.584 11.801 77.256 ;
     RECT  11.344 39.888 11.843 39.912 ;
     RECT  11.651 67.248 11.909 67.32 ;
     RECT  11.344 31.008 11.939 31.944 ;
     RECT  11.344 44.448 11.939 45.432 ;
     RECT  11.344 56.4 11.939 57.048 ;
     RECT  11.344 70.272 11.945 70.296 ;
     RECT  11.344 54.768 11.953 55.416 ;
     RECT  11.344 18.432 11.981 19.368 ;
     RECT  11.801 74.4 11.981 77.256 ;
     RECT  11.344 28.416 11.987 28.44 ;
     RECT  11.765 48.816 11.987 50.712 ;
     RECT  11.939 31.776 12.053 31.8 ;
     RECT  11.953 54.768 12.097 54.792 ;
     RECT  11.344 42.768 12.131 42.792 ;
     RECT  11.909 67.248 12.169 67.272 ;
     RECT  11.344 20.736 12.172 22.008 ;
     RECT  11.981 18.432 12.179 18.84 ;
     RECT  11.344 46.8 12.197 46.92 ;
     RECT  11.344 9.072 12.337 9.096 ;
     RECT  11.344 35.664 12.371 35.688 ;
     RECT  11.987 48.816 12.371 49.08 ;
     RECT  11.344 61.584 12.377 61.608 ;
     RECT  11.344 68.64 12.377 68.664 ;
     RECT  11.344 71.808 12.419 71.832 ;
     RECT  11.344 4.416 12.421 4.968 ;
     RECT  12.337 8.496 12.421 9.096 ;
     RECT  11.939 44.448 12.476 44.472 ;
     RECT  11.981 74.592 12.485 77.256 ;
     RECT  12.421 4.416 12.508 5.112 ;
     RECT  11.521 63.12 12.557 64.68 ;
     RECT  12.476 44.016 12.563 44.472 ;
     RECT  12.197 46.8 12.563 46.824 ;
     RECT  11.344 59.712 12.661 60.312 ;
     RECT  12.62 68.496 12.707 68.52 ;
     RECT  12.661 18.048 12.748 18.072 ;
     RECT  12.563 44.448 12.773 44.472 ;
     RECT  11.987 50.544 12.781 50.712 ;
     RECT  12.709 51.936 12.796 51.96 ;
     RECT  12.661 59.088 12.809 60.312 ;
     RECT  12.733 39.744 12.817 39.768 ;
     RECT  12.869 50.784 12.953 50.856 ;
     RECT  11.344 52.992 13.025 53.592 ;
     RECT  12.809 59.088 13.025 59.736 ;
     RECT  12.557 63.12 13.052 63.816 ;
     RECT  12.371 48.816 13.097 48.84 ;
     RECT  13.052 62.592 13.097 63.816 ;
     RECT  13.025 59.088 13.139 59.256 ;
     RECT  13.097 62.592 13.139 63.144 ;
     RECT  13.141 26.784 13.189 26.808 ;
     RECT  13.237 72.96 13.273 73.56 ;
     RECT  12.485 74.592 13.273 77.16 ;
     RECT  13.141 34.752 13.283 34.776 ;
     RECT  12.172 21.648 13.285 22.008 ;
     RECT  13.237 65.04 13.321 65.064 ;
     RECT  13.244 39.648 13.331 39.672 ;
     RECT  12.421 9.072 13.333 9.096 ;
     RECT  12.508 4.416 13.349 4.536 ;
     RECT  13.292 6.048 13.379 6.072 ;
     RECT  13.129 0.528 13.381 0.552 ;
     RECT  13.189 26.784 13.381 27.288 ;
     RECT  13.021 67.296 13.381 67.32 ;
     RECT  13.025 53.568 13.385 53.592 ;
     RECT  13.139 62.736 13.385 63.144 ;
     RECT  13.285 21.648 13.429 22.152 ;
     RECT  11.939 56.4 13.445 56.424 ;
     RECT  12.589 43.344 13.475 43.368 ;
     RECT  13.381 67.248 13.493 67.32 ;
     RECT  13.381 26.16 13.564 27.288 ;
     RECT  13.429 21.504 13.573 22.152 ;
     RECT  13.273 72.96 13.573 77.16 ;
     RECT  13.573 20.784 13.589 22.152 ;
     RECT  13.453 68.976 13.601 69 ;
     RECT  13.573 72.96 13.621 77.208 ;
     RECT  13.589 20.784 13.673 22.488 ;
     RECT  13.621 24.864 13.708 24.888 ;
     RECT  13.628 19.344 13.715 19.368 ;
     RECT  13.621 72.96 13.717 77.304 ;
     RECT  12.953 50.784 13.753 50.808 ;
     RECT  13.717 19.488 13.853 19.512 ;
     RECT  13.273 10.848 13.861 10.872 ;
     RECT  13.777 51.888 13.861 51.912 ;
     RECT  13.717 72.576 13.861 77.304 ;
     RECT  13.861 72.48 13.909 77.304 ;
     RECT  13.381 0.528 13.921 1.08 ;
     RECT  13.861 10.848 13.948 11.688 ;
     RECT  13.345 3.408 13.957 3.432 ;
     RECT  13.669 66.24 13.957 66.264 ;
     RECT  13.673 20.784 13.993 21.768 ;
     RECT  13.921 0.528 14.005 1.128 ;
     RECT  13.564 26.16 14.021 26.76 ;
     RECT  13.909 72.384 14.033 77.304 ;
     RECT  13.957 66.192 14.051 66.264 ;
     RECT  13.705 36.432 14.053 36.456 ;
     RECT  14.033 72.384 14.053 74.712 ;
     RECT  14.051 66.24 14.069 66.264 ;
     RECT  13.993 58.8 14.077 58.824 ;
     RECT  14.005 41.28 14.092 41.304 ;
     RECT  13.957 3.36 14.099 3.432 ;
     RECT  13.093 31.248 14.101 31.272 ;
     RECT  14.053 72.24 14.101 74.712 ;
     RECT  13.333 9.072 14.108 9.288 ;
     RECT  14.101 31.248 14.137 31.896 ;
     RECT  14.053 35.52 14.14 36.456 ;
     RECT  13.993 20.016 14.243 21.768 ;
     RECT  14.101 49.968 14.243 49.992 ;
     RECT  14.101 62.16 14.243 62.184 ;
     RECT  14.137 30.912 14.293 31.896 ;
     RECT  14.101 71.472 14.293 74.712 ;
     RECT  14.021 25.68 14.321 26.76 ;
     RECT  14.033 75.84 14.341 77.304 ;
     RECT  14.293 30.24 14.38 31.896 ;
     RECT  14.3 63.6 14.387 63.624 ;
     RECT  14.38 30.816 14.401 31.896 ;
     RECT  13.445 56.352 14.417 56.424 ;
     RECT  14.14 36.432 14.429 36.456 ;
     RECT  14.417 55.92 14.429 56.424 ;
     RECT  14.293 70.944 14.437 74.712 ;
     RECT  13.493 67.296 14.473 67.32 ;
     RECT  14.429 55.92 14.501 55.944 ;
     RECT  14.437 47.808 14.524 47.832 ;
     RECT  14.444 27.84 14.531 27.864 ;
     RECT  13.597 38.976 14.533 39 ;
     RECT  14.437 70.128 14.533 74.712 ;
     RECT  14.353 2.208 14.569 2.232 ;
     RECT  13.948 10.848 14.581 10.872 ;
     RECT  14.569 2.208 14.641 2.28 ;
     RECT  14.099 3.36 14.641 3.384 ;
     RECT  14.581 10.32 14.645 10.872 ;
     RECT  14.645 10.32 14.668 10.584 ;
     RECT  14.533 38.976 14.675 39.192 ;
     RECT  14.108 8.928 14.677 9.288 ;
     RECT  14.401 31.872 14.681 31.896 ;
     RECT  14.675 38.976 14.753 39 ;
     RECT  14.485 6.576 14.789 6.6 ;
     RECT  14.533 69.504 14.789 74.712 ;
     RECT  14.713 23.664 14.819 23.688 ;
     RECT  14.677 26.784 14.819 26.808 ;
     RECT  14.677 34.752 14.819 34.776 ;
     RECT  14.821 18.288 14.908 18.312 ;
     RECT  13.349 4.512 14.915 4.536 ;
     RECT  14.893 5.664 14.929 5.688 ;
     RECT  14.876 25.056 14.963 25.08 ;
     RECT  14.929 5.568 15.013 5.688 ;
     RECT  14.005 0.384 15.029 1.128 ;
     RECT  14.668 10.464 15.049 10.488 ;
     RECT  14.821 42.72 15.061 42.744 ;
     RECT  14.389 37.584 15.068 37.608 ;
     RECT  15.068 36.96 15.109 37.608 ;
     RECT  14.789 69.504 15.109 73.704 ;
     RECT  15.029 0.288 15.145 1.128 ;
     RECT  14.641 2.208 15.145 3.384 ;
     RECT  15.061 24.288 15.148 24.312 ;
     RECT  15.061 42.096 15.148 42.744 ;
     RECT  15.109 36.96 15.155 37.656 ;
     RECT  15.068 48.384 15.155 48.408 ;
     RECT  14.789 74.688 15.205 74.712 ;
     RECT  14.341 75.84 15.205 77.448 ;
     RECT  15.148 42.72 15.221 42.744 ;
     RECT  15.013 5.376 15.251 5.688 ;
     RECT  15.109 69.024 15.253 73.704 ;
     RECT  15.145 0.288 15.299 3.384 ;
     RECT  15.251 5.376 15.329 5.592 ;
     RECT  15.329 5.568 15.347 5.592 ;
     RECT  14.401 30.816 15.349 30.84 ;
     RECT  15.253 68.976 15.365 73.704 ;
     RECT  14.243 20.016 15.389 21.048 ;
     RECT  14.732 63.312 15.395 63.336 ;
     RECT  15.389 18.864 15.397 21.048 ;
     RECT  15.349 29.952 15.397 30.84 ;
     RECT  14.929 44.88 15.397 44.904 ;
     RECT  15.397 29.952 15.436 30.984 ;
     RECT  15.397 18.864 15.443 21.528 ;
     RECT  15.443 20.64 15.469 21.528 ;
     RECT  15.397 63.168 15.469 63.192 ;
     RECT  15.443 18.864 15.473 19.656 ;
     RECT  15.473 19.44 15.481 19.464 ;
     RECT  15.205 74.688 15.481 77.448 ;
     RECT  15.299 2.784 15.541 3.384 ;
     RECT  15.155 37.584 15.721 37.656 ;
     RECT  15.577 41.52 15.721 41.544 ;
     RECT  14.677 8.448 15.884 9.288 ;
     RECT  15.365 68.976 15.925 72.984 ;
     RECT  15.829 22.8 15.973 22.824 ;
     RECT  15.397 26.832 15.973 26.856 ;
     RECT  15.397 28.416 15.973 28.44 ;
     RECT  15.397 44.592 15.973 44.904 ;
     RECT  15.613 65.568 15.973 65.592 ;
     RECT  15.02 12.48 16.021 12.504 ;
     RECT  15.433 53.616 16.045 53.64 ;
     RECT  16.021 12.48 16.069 12.552 ;
     RECT  15.469 62.736 16.076 63.192 ;
     RECT  15.721 37.584 16.117 38.232 ;
     RECT  16.081 47.904 16.117 47.928 ;
     RECT  15.721 41.04 16.153 41.544 ;
     RECT  15.299 0.288 16.189 1.704 ;
     RECT  15.505 57.648 16.189 57.672 ;
     RECT  15.884 8.448 16.213 9.816 ;
     RECT  15.973 55.392 16.213 55.416 ;
     RECT  16.076 62.544 16.213 63.192 ;
     RECT  16.213 8.256 16.261 9.816 ;
     RECT  16.117 37.104 16.297 38.232 ;
     RECT  15.973 22.8 16.309 24.072 ;
     RECT  15.397 33.792 16.309 33.816 ;
     RECT  16.297 35.904 16.309 35.928 ;
     RECT  16.297 37.104 16.309 39.192 ;
     RECT  16.189 0.24 16.448 1.704 ;
     RECT  15.541 2.784 16.448 3.432 ;
     RECT  16.261 8.16 16.448 9.816 ;
     RECT  16.069 11.952 16.448 12.552 ;
     RECT  15.781 13.584 16.448 13.608 ;
     RECT  15.445 16.416 16.448 16.44 ;
     RECT  15.469 20.64 16.448 21.672 ;
     RECT  16.309 22.752 16.448 24.408 ;
     RECT  15.973 26.832 16.448 28.44 ;
     RECT  15.436 30 16.448 30.984 ;
     RECT  16.309 31.968 16.448 31.992 ;
     RECT  16.309 33.552 16.448 33.816 ;
     RECT  16.309 35.904 16.448 39.192 ;
     RECT  16.153 41.04 16.448 41.64 ;
     RECT  15.973 43.776 16.448 45.672 ;
     RECT  16.117 47.52 16.448 47.928 ;
     RECT  15.649 50.976 16.448 51 ;
     RECT  16.045 53.088 16.448 53.64 ;
     RECT  16.213 54.72 16.448 55.416 ;
     RECT  16.189 57.024 16.448 57.672 ;
     RECT  16.181 58.656 16.448 58.68 ;
     RECT  15.932 59.952 16.448 59.976 ;
     RECT  16.213 62.016 16.448 63.192 ;
     RECT  15.973 65.04 16.448 65.592 ;
     RECT  15.925 68.4 16.448 72.984 ;
     RECT  15.481 74.688 16.448 75.24 ;
     RECT  15.481 76.368 16.448 77.448 ;
     RECT  16.448 0.24 16.744 77.448 ;
     RECT  16.744 10.992 16.805 12.552 ;
     RECT  16.744 18.816 16.883 21.144 ;
     RECT  16.744 46.8 16.883 50.856 ;
     RECT  16.744 55.968 16.883 55.992 ;
     RECT  16.744 63.216 16.883 65.064 ;
     RECT  16.744 22.224 16.921 23.016 ;
     RECT  16.744 29.664 16.921 30.264 ;
     RECT  16.744 32.352 16.921 32.568 ;
     RECT  16.744 26.208 16.924 28.536 ;
     RECT  16.744 2.784 16.931 4.872 ;
     RECT  16.744 8.16 16.931 9.432 ;
     RECT  16.805 10.992 16.931 11.976 ;
     RECT  16.744 76.896 16.933 77.448 ;
     RECT  16.744 0.24 16.94 1.752 ;
     RECT  16.744 44.976 16.949 45.576 ;
     RECT  16.744 59.28 16.949 59.88 ;
     RECT  16.931 2.784 16.979 4.776 ;
     RECT  16.744 13.584 16.985 13.608 ;
     RECT  16.744 42.768 16.985 43.896 ;
     RECT  16.931 11.952 17.021 11.976 ;
     RECT  16.883 63.216 17.021 63.912 ;
     RECT  16.94 0.192 17.027 1.752 ;
     RECT  16.931 8.16 17.057 9.288 ;
     RECT  16.933 76.896 17.057 77.496 ;
     RECT  16.979 2.88 17.065 4.776 ;
     RECT  16.921 22.32 17.093 23.016 ;
     RECT  16.985 43.776 17.123 43.896 ;
     RECT  16.883 46.8 17.123 50.088 ;
     RECT  16.744 68.976 17.123 74.664 ;
     RECT  16.744 53.904 17.137 54.888 ;
     RECT  16.924 28.512 17.165 28.536 ;
     RECT  17.123 43.776 17.165 43.8 ;
     RECT  16.949 44.976 17.165 45 ;
     RECT  17.123 73.008 17.267 74.664 ;
     RECT  16.744 24.912 17.356 25.08 ;
     RECT  16.883 19.44 17.381 21.144 ;
     RECT  17.123 46.896 17.381 46.92 ;
     RECT  17.123 48.672 17.381 50.088 ;
     RECT  17.381 19.872 17.411 21.144 ;
     RECT  17.065 3.36 17.417 4.776 ;
     RECT  17.411 19.92 17.507 21.144 ;
     RECT  16.744 37.104 17.507 37.128 ;
     RECT  16.744 58.224 17.507 58.248 ;
     RECT  16.744 62.16 17.507 62.184 ;
     RECT  17.417 3.36 17.597 4.536 ;
     RECT  16.744 31.344 17.597 31.368 ;
     RECT  16.985 42.768 17.641 42.792 ;
     RECT  17.021 63.792 17.669 63.912 ;
     RECT  17.669 63.888 17.677 63.912 ;
     RECT  17.093 22.608 17.692 23.016 ;
     RECT  17.597 4.464 17.713 4.536 ;
     RECT  16.921 29.952 17.747 30.264 ;
     RECT  17.057 76.896 17.749 77.448 ;
     RECT  16.924 26.208 17.765 27.432 ;
     RECT  17.749 76.8 17.777 77.448 ;
     RECT  16.921 32.352 17.788 32.376 ;
     RECT  17.747 30.144 17.845 30.264 ;
     RECT  16.744 6.768 17.917 6.792 ;
     RECT  17.123 69.024 17.921 72.024 ;
     RECT  17.873 51.936 17.957 51.96 ;
     RECT  17.777 76.8 17.957 77.4 ;
     RECT  17.765 25.68 17.987 27.432 ;
     RECT  16.883 65.04 17.989 65.064 ;
     RECT  17.137 53.904 18.053 54.792 ;
     RECT  17.057 8.16 18.069 8.52 ;
     RECT  18.053 53.616 18.073 54.792 ;
     RECT  17.507 19.92 18.083 20.04 ;
     RECT  17.957 76.8 18.085 77.256 ;
     RECT  17.267 73.344 18.101 74.664 ;
     RECT  17.989 62.736 18.131 62.76 ;
     RECT  17.989 65.04 18.131 65.688 ;
     RECT  17.921 69.024 18.131 69.576 ;
     RECT  17.917 6.768 18.137 6.84 ;
     RECT  18.073 53.616 18.137 53.928 ;
     RECT  18.131 65.04 18.137 65.448 ;
     RECT  17.507 21.024 18.145 21.144 ;
     RECT  18.083 19.92 18.172 19.944 ;
     RECT  18.069 7.968 18.173 8.52 ;
     RECT  16.949 59.28 18.173 59.304 ;
     RECT  17.845 12.528 18.181 12.552 ;
     RECT  18.101 73.344 18.209 73.512 ;
     RECT  17.845 30.144 18.22 30.84 ;
     RECT  18.085 76.704 18.227 77.256 ;
     RECT  18.209 73.44 18.245 73.512 ;
     RECT  17.027 0.336 18.275 1.752 ;
     RECT  18.085 24.096 18.275 24.12 ;
     RECT  17.987 25.68 18.281 26.232 ;
     RECT  17.597 3.36 18.313 3.384 ;
     RECT  18.275 0.336 18.323 1.656 ;
     RECT  18.181 12.48 18.325 12.552 ;
     RECT  17.381 48.672 18.325 49.368 ;
     RECT  18.137 53.904 18.389 53.928 ;
     RECT  18.053 57.024 18.413 57.048 ;
     RECT  18.173 7.968 18.419 8.328 ;
     RECT  18.419 7.968 18.421 8.184 ;
     RECT  17.692 22.608 18.421 22.824 ;
     RECT  17.987 27.408 18.425 27.432 ;
     RECT  18.22 30.72 18.425 30.84 ;
     RECT  18.323 0.384 18.467 1.656 ;
     RECT  18.38 28.992 18.467 29.016 ;
     RECT  17.845 33.648 18.469 33.768 ;
     RECT  18.413 57.024 18.497 57.096 ;
     RECT  18.349 46.752 18.517 46.776 ;
     RECT  18.469 33.552 18.524 33.768 ;
     RECT  18.421 22.176 18.529 22.824 ;
     RECT  18.421 7.344 18.533 8.184 ;
     RECT  18.133 35.232 18.565 35.256 ;
     RECT  17.749 36.384 18.604 36.408 ;
     RECT  18.517 46.032 18.604 46.776 ;
     RECT  18.517 67.728 18.605 67.752 ;
     RECT  18.524 33.552 18.611 33.816 ;
     RECT  18.565 25.584 18.652 25.608 ;
     RECT  18.572 38.976 18.659 39 ;
     RECT  18.421 40.56 18.707 40.584 ;
     RECT  18.197 32.544 18.709 32.568 ;
     RECT  18.425 30.816 18.716 30.84 ;
     RECT  18.604 46.752 18.716 46.776 ;
     RECT  18.661 37.536 18.748 37.56 ;
     RECT  18.709 32.544 18.796 32.904 ;
     RECT  18.533 7.968 18.803 8.184 ;
     RECT  18.565 34.848 18.803 35.256 ;
     RECT  18.716 46.752 18.803 47.352 ;
     RECT  18.241 58.56 18.803 58.584 ;
     RECT  18.529 62.16 18.803 62.712 ;
     RECT  18.529 21.648 18.805 22.824 ;
     RECT  17.921 70.56 18.821 72.024 ;
     RECT  18.716 30.816 18.853 31.32 ;
     RECT  18.805 17.52 18.86 17.544 ;
     RECT  17.845 18.816 18.86 18.84 ;
     RECT  18.86 17.52 18.893 18.84 ;
     RECT  18.853 24.528 18.937 24.552 ;
     RECT  18.313 2.832 18.947 3.384 ;
     RECT  18.893 18.048 18.947 18.84 ;
     RECT  17.713 4.464 18.961 4.488 ;
     RECT  18.245 73.44 18.965 73.464 ;
     RECT  18.908 42.048 18.995 42.072 ;
     RECT  18.803 62.592 19.037 62.712 ;
     RECT  18.956 60.24 19.043 60.264 ;
     RECT  18.817 56.928 19.091 56.952 ;
     RECT  18.227 76.944 19.105 77.256 ;
     RECT  18.853 30.816 19.141 31.416 ;
     RECT  19.093 20.496 19.18 20.52 ;
     RECT  19.141 30.816 19.187 32.28 ;
     RECT  18.325 12.432 19.213 12.552 ;
     RECT  18.805 39.744 19.217 39.768 ;
     RECT  19.177 58.8 19.261 58.824 ;
     RECT  18.131 69.408 19.285 69.576 ;
     RECT  19.187 31.344 19.325 32.28 ;
     RECT  18.325 48.48 19.325 49.368 ;
     RECT  18.467 0.384 19.357 1.224 ;
     RECT  19.325 31.344 19.369 32.04 ;
     RECT  19.105 76.944 19.379 77.448 ;
     RECT  18.805 21.648 19.397 23.064 ;
     RECT  19.285 68.784 19.397 69.576 ;
     RECT  18.101 74.544 19.397 74.664 ;
     RECT  19.325 48.48 19.405 48.504 ;
     RECT  18.947 3.312 19.429 3.384 ;
     RECT  18.961 4.464 19.429 4.536 ;
     RECT  18.137 65.424 19.429 65.448 ;
     RECT  18.947 18.816 19.433 18.84 ;
     RECT  19.357 0.288 19.441 1.224 ;
     RECT  19.369 31.344 19.469 31.56 ;
     RECT  19.213 12.432 19.475 13.128 ;
     RECT  19.397 21.648 19.513 22.488 ;
     RECT  19.429 3.312 19.523 4.536 ;
     RECT  19.441 0.336 19.549 1.224 ;
     RECT  19.429 65.424 19.577 65.592 ;
     RECT  19.493 67.296 19.577 67.32 ;
     RECT  19.397 69.408 19.609 69.576 ;
     RECT  18.821 70.56 19.609 71.784 ;
     RECT  19.525 27.264 19.612 27.288 ;
     RECT  19.381 37.872 19.613 37.896 ;
     RECT  19.501 62.736 19.619 62.76 ;
     RECT  19.475 12.432 19.649 12.456 ;
     RECT  19.379 76.944 19.66 77.16 ;
     RECT  18.385 10.8 19.667 10.824 ;
     RECT  19.609 57.024 19.693 57.672 ;
     RECT  19.609 69.408 19.721 71.784 ;
     RECT  19.669 27.84 19.757 27.864 ;
     RECT  19.676 39.216 19.763 39.24 ;
     RECT  18.803 8.16 19.765 8.184 ;
     RECT  17.797 15.984 19.772 16.008 ;
     RECT  18.803 35.232 19.781 35.256 ;
     RECT  18.805 29.088 19.801 29.688 ;
     RECT  19.717 50.736 19.829 50.76 ;
     RECT  19.772 15.984 19.859 16.152 ;
     RECT  19.721 69.504 19.865 71.784 ;
     RECT  19.573 72.96 19.907 72.984 ;
     RECT  19.523 3.312 19.909 3.432 ;
     RECT  19.861 38.832 19.945 38.856 ;
     RECT  19.813 46.656 19.955 46.776 ;
     RECT  18.673 36.48 19.957 36.504 ;
     RECT  19.213 14.112 19.964 14.136 ;
     RECT  19.801 29.088 20.017 29.112 ;
     RECT  19.859 15.984 20.045 16.008 ;
     RECT  19.957 36.48 20.045 36.984 ;
     RECT  19.957 63.984 20.045 64.008 ;
     RECT  20.005 74.112 20.053 74.28 ;
     RECT  19.333 26.16 20.101 26.184 ;
     RECT  20.041 49.968 20.125 49.992 ;
     RECT  19.141 54.048 20.149 54.072 ;
     RECT  18.805 55.152 20.149 55.176 ;
     RECT  19.549 0.432 20.185 1.224 ;
     RECT  20.101 25.344 20.189 26.184 ;
     RECT  20.108 28.032 20.195 28.056 ;
     RECT  20.149 53.616 20.233 55.176 ;
     RECT  20.185 44.592 20.245 44.616 ;
     RECT  20.197 15.216 20.284 15.24 ;
     RECT  19.765 7.776 20.297 8.184 ;
     RECT  20.045 36.48 20.332 36.696 ;
     RECT  20.297 7.776 20.333 7.896 ;
     RECT  20.233 55.152 20.369 55.176 ;
     RECT  19.513 21.648 20.377 22.248 ;
     RECT  19.469 31.344 20.377 31.416 ;
     RECT  20.245 43.92 20.387 44.616 ;
     RECT  20.377 31.344 20.405 31.368 ;
     RECT  20.257 28.416 20.435 29.016 ;
     RECT  20.053 74.016 20.437 74.28 ;
     RECT  20.185 0.432 20.473 1.704 ;
     RECT  20.437 74.016 20.477 74.376 ;
     RECT  19.909 2.784 20.483 3.432 ;
     RECT  20.401 32.544 20.485 32.568 ;
     RECT  19.781 34.848 20.485 35.256 ;
     RECT  20.477 74.112 20.485 74.376 ;
     RECT  20.387 43.92 20.513 43.944 ;
     RECT  19.865 69.552 20.513 71.784 ;
     RECT  20.485 34.848 20.531 36.12 ;
     RECT  19.523 4.464 20.533 4.536 ;
     RECT  20.377 22.224 20.533 22.248 ;
     RECT  20.473 23.376 20.533 23.4 ;
     RECT  20.365 24.528 20.533 25.128 ;
     RECT  20.513 69.696 20.533 71.784 ;
     RECT  20.473 0.432 20.545 1.752 ;
     RECT  20.473 65.04 20.557 65.064 ;
     RECT  20.545 0.288 20.579 1.752 ;
     RECT  19.573 61.392 20.581 61.416 ;
     RECT  20.581 61.392 20.617 61.608 ;
     RECT  20.473 19.968 20.629 19.992 ;
     RECT  20.545 43.056 20.629 43.08 ;
     RECT  20.531 36.096 20.657 36.12 ;
     RECT  20.617 61.344 20.665 61.608 ;
     RECT  20.333 7.776 20.684 7.8 ;
     RECT  20.233 53.616 20.693 54.168 ;
     RECT  19.964 14.064 20.732 14.136 ;
     RECT  20.684 7.584 20.771 7.8 ;
     RECT  20.689 38.256 20.773 38.28 ;
     RECT  20.732 13.392 20.801 14.136 ;
     RECT  20.435 28.416 20.819 28.92 ;
     RECT  20.581 34.416 20.819 34.44 ;
     RECT  19.66 76.944 20.833 77.064 ;
     RECT  20.579 0.288 20.867 1.704 ;
     RECT  20.533 3.84 20.869 4.536 ;
     RECT  20.665 61.344 20.869 61.368 ;
     RECT  20.789 30.24 20.873 30.264 ;
     RECT  19.693 57.024 20.881 57.048 ;
     RECT  20.365 58.32 20.933 58.488 ;
     RECT  20.933 63.888 20.965 63.912 ;
     RECT  21.013 48.528 21.185 48.552 ;
     RECT  20.329 49.776 21.185 49.8 ;
     RECT  20.933 16.512 21.221 16.536 ;
     RECT  20.533 22.224 21.253 25.128 ;
     RECT  20.365 26.208 21.253 26.232 ;
     RECT  21.221 16.512 21.301 16.584 ;
     RECT  20.483 2.784 21.373 2.808 ;
     RECT  21.205 11.184 21.397 11.208 ;
     RECT  20.905 30.48 21.409 30.84 ;
     RECT  21.349 36.192 21.445 36.888 ;
     RECT  20.869 38.016 21.445 38.04 ;
     RECT  20.933 58.32 21.445 58.824 ;
     RECT  20.833 76.944 21.445 77.112 ;
     RECT  21.373 2.736 21.481 2.808 ;
     RECT  21.409 30.48 21.493 31.8 ;
     RECT  21.121 33.168 21.493 33.192 ;
     RECT  20.485 74.112 21.493 74.472 ;
     RECT  21.445 76.944 21.541 77.16 ;
     RECT  20.693 53.616 21.548 53.64 ;
     RECT  21.397 10.8 21.581 11.208 ;
     RECT  20.629 19.152 21.589 19.992 ;
     RECT  21.253 22.224 21.589 26.232 ;
     RECT  20.972 62.4 21.589 62.424 ;
     RECT  20.965 63.6 21.589 63.912 ;
     RECT  21.541 76.944 21.617 77.208 ;
     RECT  20.867 0.288 21.625 0.744 ;
     RECT  21.445 58.224 21.625 58.824 ;
     RECT  21.301 16.512 21.637 17.064 ;
     RECT  21.589 18.768 21.637 19.992 ;
     RECT  21.589 68.544 21.637 68.568 ;
     RECT  20.533 69.696 21.637 72.6 ;
     RECT  21.637 34.8 21.653 34.824 ;
     RECT  21.445 36.192 21.653 38.04 ;
     RECT  20.869 60.432 21.661 61.368 ;
     RECT  21.589 62.4 21.661 63.912 ;
     RECT  21.637 68.544 21.661 72.6 ;
     RECT  21.493 74.064 21.661 74.472 ;
     RECT  21.617 76.896 21.661 77.208 ;
     RECT  21.157 9.504 21.685 9.528 ;
     RECT  21.637 18.768 21.692 20.808 ;
     RECT  21.625 58.032 21.692 58.824 ;
     RECT  21.637 15.888 21.733 17.064 ;
     RECT  21.692 18.768 21.733 21.096 ;
     RECT  21.589 22.224 21.733 26.808 ;
     RECT  21.692 57.744 21.733 58.824 ;
     RECT  20.041 66.096 21.733 66.12 ;
     RECT  21.661 68.544 21.733 74.472 ;
     RECT  21.661 76.896 21.733 77.4 ;
     RECT  21.733 76.848 21.841 77.4 ;
     RECT  21.625 0.192 21.848 0.744 ;
     RECT  21.481 2.736 21.848 2.856 ;
     RECT  20.869 3.84 21.848 4.872 ;
     RECT  21.116 6.768 21.848 6.792 ;
     RECT  20.771 7.776 21.848 7.8 ;
     RECT  21.685 9.504 21.848 9.768 ;
     RECT  21.581 10.752 21.848 11.208 ;
     RECT  20.801 13.392 21.848 13.656 ;
     RECT  21.733 14.784 21.848 17.064 ;
     RECT  21.733 18.768 21.848 26.808 ;
     RECT  20.819 28.416 21.848 28.536 ;
     RECT  21.493 30.48 21.848 33.192 ;
     RECT  21.653 34.8 21.848 38.04 ;
     RECT  21.692 41.616 21.848 41.64 ;
     RECT  21.733 46.224 21.848 46.92 ;
     RECT  21.185 48.528 21.848 49.8 ;
     RECT  21.733 51.984 21.848 52.008 ;
     RECT  21.548 53.52 21.848 53.64 ;
     RECT  21.733 57.744 21.848 58.968 ;
     RECT  21.661 60.432 21.848 63.912 ;
     RECT  21.733 66.096 21.848 66.696 ;
     RECT  21.733 68.304 21.848 74.472 ;
     RECT  21.841 76.848 21.848 77.448 ;
     RECT  21.848 0.192 21.875 77.448 ;
     RECT  21.875 0.288 21.971 77.448 ;
     RECT  21.971 0.432 22.144 77.4 ;
     RECT  22.144 42.672 22.259 42.696 ;
     RECT  22.144 44.64 22.259 44.664 ;
     RECT  22.144 61.344 22.259 61.608 ;
     RECT  22.144 63.312 22.259 63.336 ;
     RECT  22.144 27.888 22.313 28.488 ;
     RECT  22.144 29.472 22.313 33.912 ;
     RECT  22.144 46.896 22.349 47.256 ;
     RECT  22.313 29.472 22.355 33.864 ;
     RECT  22.144 34.896 22.355 34.92 ;
     RECT  22.349 47.232 22.355 47.256 ;
     RECT  22.144 16.416 22.403 17.544 ;
     RECT  22.355 29.472 22.444 32.328 ;
     RECT  22.144 0.432 22.493 4.296 ;
     RECT  22.144 24.432 22.493 25.464 ;
     RECT  22.144 54.768 22.529 54.792 ;
     RECT  22.144 57.648 22.529 58.536 ;
     RECT  22.403 16.992 22.54 17.544 ;
     RECT  22.313 27.888 22.547 28.44 ;
     RECT  22.144 39.168 22.547 40.44 ;
     RECT  22.144 76.848 22.595 77.4 ;
     RECT  22.144 26.784 22.601 26.808 ;
     RECT  22.493 25.44 22.673 25.464 ;
     RECT  22.144 22.8 22.739 23.352 ;
     RECT  22.444 29.664 22.745 32.328 ;
     RECT  22.739 23.232 22.781 23.256 ;
     RECT  22.745 30.672 22.781 32.328 ;
     RECT  22.547 39.168 22.787 39.912 ;
     RECT  22.144 49.008 22.787 49.8 ;
     RECT  22.529 57.648 22.787 57.672 ;
     RECT  22.259 61.344 22.787 61.464 ;
     RECT  22.144 64.464 22.787 64.488 ;
     RECT  22.144 68.448 22.787 68.472 ;
     RECT  22.787 39.744 22.853 39.912 ;
     RECT  22.144 13.392 22.897 13.656 ;
     RECT  22.144 36.24 22.924 37.176 ;
     RECT  22.493 0.432 22.957 1.752 ;
     RECT  22.144 50.784 22.961 51.288 ;
     RECT  22.547 27.888 22.969 27.96 ;
     RECT  22.144 65.568 23.005 65.64 ;
     RECT  22.144 11.952 23.02 11.976 ;
     RECT  22.897 13.392 23.075 13.512 ;
     RECT  22.493 24.432 23.105 24.456 ;
     RECT  22.595 76.896 23.125 77.4 ;
     RECT  22.54 16.992 23.177 17.016 ;
     RECT  22.144 70.704 23.177 71.88 ;
     RECT  23.125 76.896 23.249 77.448 ;
     RECT  23.177 71.28 23.267 71.88 ;
     RECT  23.125 21.552 23.269 21.576 ;
     RECT  23.075 13.392 23.276 13.416 ;
     RECT  22.355 33.84 23.315 33.864 ;
     RECT  23.221 5.616 23.353 5.64 ;
     RECT  23.269 41.856 23.357 41.88 ;
     RECT  23.276 12.912 23.363 13.416 ;
     RECT  22.781 31.392 23.363 32.328 ;
     RECT  23.276 45.936 23.363 45.96 ;
     RECT  22.493 2.832 23.401 4.296 ;
     RECT  22.853 39.744 23.401 39.768 ;
     RECT  23.269 20.544 23.413 20.568 ;
     RECT  23.269 21.552 23.413 22.2 ;
     RECT  22.144 9.504 23.42 9.528 ;
     RECT  23.353 5.616 23.459 6.264 ;
     RECT  22.787 61.44 23.472 61.464 ;
     RECT  23.363 31.92 23.473 32.328 ;
     RECT  23.473 32.304 23.497 32.328 ;
     RECT  22.961 50.784 23.497 50.808 ;
     RECT  23.353 58.704 23.501 58.728 ;
     RECT  23.42 9.264 23.507 9.528 ;
     RECT  23.461 62.592 23.509 62.616 ;
     RECT  23.365 15.84 23.537 15.864 ;
     RECT  23.516 11.616 23.603 11.64 ;
     RECT  22.924 36.624 23.681 37.176 ;
     RECT  23.509 62.592 23.681 63.48 ;
     RECT  23.605 17.04 23.689 17.688 ;
     RECT  23.605 35.376 23.689 35.4 ;
     RECT  23.497 54.768 23.699 54.792 ;
     RECT  23.612 65.376 23.699 65.4 ;
     RECT  23.413 20.544 23.713 22.2 ;
     RECT  23.507 9.504 23.717 9.528 ;
     RECT  23.249 76.896 23.717 77.208 ;
     RECT  23.756 25.248 23.843 25.272 ;
     RECT  22.745 29.664 23.893 29.688 ;
     RECT  23.681 36.624 23.893 36.792 ;
     RECT  23.557 52.464 23.893 52.488 ;
     RECT  23.401 3.408 23.929 4.296 ;
     RECT  23.459 5.616 23.929 5.688 ;
     RECT  23.893 29.664 23.929 29.976 ;
     RECT  23.713 20.544 23.933 23.016 ;
     RECT  23.681 62.592 23.933 62.616 ;
     RECT  23.689 17.04 23.939 17.064 ;
     RECT  23.389 26.928 23.939 27.432 ;
     RECT  23.425 41.616 23.939 41.64 ;
     RECT  23.497 49.968 23.939 50.808 ;
     RECT  23.929 28.992 23.977 29.976 ;
     RECT  23.893 35.904 23.977 36.792 ;
     RECT  23.893 51.888 23.977 52.488 ;
     RECT  23.933 22.128 23.987 23.016 ;
     RECT  22.144 73.104 23.989 74.664 ;
     RECT  23.941 42.72 24.028 42.744 ;
     RECT  22.957 0.288 24.035 1.752 ;
     RECT  23.948 37.824 24.035 37.848 ;
     RECT  23.948 40.512 24.035 40.536 ;
     RECT  23.965 61.344 24.083 61.368 ;
     RECT  23.717 76.896 24.085 77.112 ;
     RECT  23.933 20.544 24.121 21.144 ;
     RECT  24.037 57.072 24.121 57.096 ;
     RECT  23.267 71.568 24.133 71.88 ;
     RECT  23.989 73.104 24.133 75.24 ;
     RECT  23.929 3.408 24.185 5.688 ;
     RECT  24.133 13.776 24.221 13.8 ;
     RECT  23.509 70.08 24.221 70.152 ;
     RECT  24.085 76.752 24.227 77.112 ;
     RECT  24.133 71.568 24.229 75.24 ;
     RECT  24.229 71.28 24.257 75.24 ;
     RECT  24.133 14.784 24.275 14.808 ;
     RECT  24.253 43.92 24.337 43.944 ;
     RECT  23.353 66.768 24.397 66.792 ;
     RECT  24.257 72.96 24.419 75.24 ;
     RECT  23.977 28.992 24.445 29.688 ;
     RECT  24.373 31.008 24.46 31.032 ;
     RECT  24.217 25.056 24.467 25.08 ;
     RECT  24.253 53.616 24.467 53.64 ;
     RECT  24.227 76.848 24.467 77.112 ;
     RECT  23.977 52.464 24.509 52.488 ;
     RECT  24.185 3.408 24.515 5.064 ;
     RECT  24.445 28.992 24.515 29.016 ;
     RECT  23.497 32.304 24.515 32.568 ;
     RECT  24.397 60.816 24.515 61.032 ;
     RECT  24.397 66.192 24.515 66.792 ;
     RECT  24.419 73.248 24.515 75.24 ;
     RECT  23.525 19.392 24.517 19.416 ;
     RECT  24.037 23.04 24.517 23.064 ;
     RECT  23.977 35.952 24.545 36.792 ;
     RECT  24.221 70.128 24.565 70.152 ;
     RECT  24.257 71.28 24.565 71.832 ;
     RECT  24.517 23.04 24.604 23.736 ;
     RECT  24.229 11.04 24.661 11.256 ;
     RECT  24.613 26.496 24.661 26.52 ;
     RECT  24.661 26.208 24.7 26.52 ;
     RECT  23.569 6.816 24.707 6.84 ;
     RECT  24.517 19.392 24.761 20.232 ;
     RECT  24.7 26.208 24.761 26.232 ;
     RECT  24.761 19.968 24.796 20.232 ;
     RECT  24.515 3.408 24.905 4.584 ;
     RECT  24.901 31.968 24.985 31.992 ;
     RECT  24.721 6.24 24.995 6.264 ;
     RECT  24.604 23.04 25.043 23.352 ;
     RECT  24.905 3.408 25.049 4.296 ;
     RECT  24.515 73.248 25.049 74.76 ;
     RECT  24.035 0.288 25.081 1.128 ;
     RECT  24.037 2.256 25.081 2.28 ;
     RECT  25.049 73.344 25.085 74.76 ;
     RECT  25.081 0.288 25.091 2.28 ;
     RECT  24.545 35.952 25.091 35.976 ;
     RECT  24.476 7.872 25.141 7.896 ;
     RECT  25.093 26.16 25.18 26.184 ;
     RECT  25.093 63.456 25.189 63.48 ;
     RECT  24.565 70.128 25.189 71.832 ;
     RECT  25.093 22.368 25.229 23.016 ;
     RECT  25.093 39.744 25.229 39.768 ;
     RECT  23.605 59.232 25.229 59.256 ;
     RECT  24.661 10.704 25.237 11.256 ;
     RECT  25.189 69.84 25.237 71.832 ;
     RECT  25.189 63.456 25.283 63.768 ;
     RECT  25.225 57.024 25.309 57.048 ;
     RECT  25.237 27.792 25.324 27.816 ;
     RECT  25.285 45.84 25.373 45.864 ;
     RECT  25.333 65.04 25.417 65.064 ;
     RECT  25.369 25.68 25.513 25.704 ;
     RECT  25.525 28.992 25.549 29.016 ;
     RECT  24.467 76.944 25.549 77.112 ;
     RECT  25.237 10.704 25.573 11.304 ;
     RECT  24.515 61.008 25.58 61.032 ;
     RECT  25.237 69.744 25.589 71.832 ;
     RECT  25.477 43.344 25.619 43.368 ;
     RECT  25.513 25.056 25.657 25.704 ;
     RECT  25.589 69.744 25.661 71.784 ;
     RECT  25.091 0.288 25.667 1.704 ;
     RECT  25.58 9.072 25.667 9.096 ;
     RECT  25.549 28.992 25.667 29.688 ;
     RECT  25.58 60.576 25.667 61.032 ;
     RECT  25.573 10.272 25.697 11.304 ;
     RECT  25.667 0.288 25.715 1.128 ;
     RECT  25.549 76.944 25.717 77.16 ;
     RECT  25.661 69.744 25.733 71.736 ;
     RECT  25.657 24.528 25.741 25.704 ;
     RECT  25.657 62.16 25.741 62.184 ;
     RECT  25.717 15.36 25.765 15.384 ;
     RECT  25.733 69.744 25.765 71.688 ;
     RECT  25.765 69.648 25.801 71.688 ;
     RECT  25.667 28.992 25.813 29.16 ;
     RECT  25.82 18.384 25.907 18.408 ;
     RECT  25.141 7.872 25.913 7.944 ;
     RECT  25.868 58.848 25.955 58.872 ;
     RECT  25.229 22.992 26.029 23.016 ;
     RECT  25.837 51.312 26.053 51.336 ;
     RECT  26.053 33.12 26.089 33.144 ;
     RECT  25.957 61.44 26.093 61.464 ;
     RECT  26.101 5.472 26.117 5.496 ;
     RECT  26.089 33.12 26.137 33.624 ;
     RECT  26.053 55.92 26.137 55.944 ;
     RECT  26.053 23.376 26.14 23.736 ;
     RECT  25.765 15.36 26.149 15.768 ;
     RECT  25.697 10.704 26.197 11.304 ;
     RECT  24.796 19.968 26.197 19.992 ;
     RECT  26.137 33.6 26.197 33.624 ;
     RECT  25.34 54.096 26.197 54.12 ;
     RECT  26.053 63.888 26.197 63.912 ;
     RECT  26.149 47.424 26.236 47.448 ;
     RECT  25.741 24.816 26.237 25.704 ;
     RECT  26.197 33.6 26.243 34.44 ;
     RECT  26.197 19.968 26.245 20.568 ;
     RECT  26.197 26.736 26.245 26.856 ;
     RECT  26.197 21.744 26.261 21.768 ;
     RECT  25.813 28.944 26.261 29.16 ;
     RECT  26.243 34.32 26.269 34.44 ;
     RECT  26.14 23.376 26.281 23.4 ;
     RECT  26.269 34.32 26.293 35.4 ;
     RECT  26.197 30.816 26.305 30.84 ;
     RECT  25.801 69.552 26.305 71.688 ;
     RECT  26.197 54.096 26.341 54.6 ;
     RECT  25.085 74.112 26.341 74.76 ;
     RECT  26.269 45.648 26.348 45.672 ;
     RECT  26.197 18.816 26.405 18.84 ;
     RECT  26.245 19.92 26.405 20.568 ;
     RECT  26.261 28.512 26.485 29.16 ;
     RECT  25.909 37.536 26.485 37.56 ;
     RECT  26.117 5.472 26.533 6.312 ;
     RECT  26.197 7.344 26.533 7.416 ;
     RECT  25.715 0.288 26.557 0.648 ;
     RECT  26.533 5.472 26.581 7.416 ;
     RECT  26.341 74.112 26.581 75 ;
     RECT  25.049 3.408 26.629 3.432 ;
     RECT  26.245 25.968 26.665 26.856 ;
     RECT  26.485 27.936 26.665 29.16 ;
     RECT  26.197 10.704 26.773 11.688 ;
     RECT  26.005 13.056 26.773 13.08 ;
     RECT  26.149 14.832 26.773 15.768 ;
     RECT  26.053 51.312 26.773 51.912 ;
     RECT  26.557 0.192 26.809 0.648 ;
     RECT  26.773 1.68 26.809 1.704 ;
     RECT  26.405 18.816 26.821 20.568 ;
     RECT  26.261 21.648 26.821 21.768 ;
     RECT  26.773 10.224 26.869 11.688 ;
     RECT  26.773 14.784 26.869 15.768 ;
     RECT  26.197 62.736 26.869 62.76 ;
     RECT  26.197 63.888 26.869 64.248 ;
     RECT  26.581 73.536 26.869 75 ;
     RECT  26.821 18.816 26.876 21.768 ;
     RECT  26.869 14.784 26.881 15.864 ;
     RECT  26.485 37.008 26.909 37.56 ;
     RECT  26.341 53.616 26.917 54.6 ;
     RECT  26.809 0.192 26.989 1.704 ;
     RECT  26.629 3.024 26.989 3.432 ;
     RECT  26.237 24.816 27.013 24.84 ;
     RECT  26.305 30.816 27.013 31.416 ;
     RECT  26.845 32.4 27.013 32.568 ;
     RECT  26.909 37.008 27.013 37.704 ;
     RECT  26.869 73.536 27.013 75.24 ;
     RECT  26.665 25.968 27.061 29.16 ;
     RECT  27.013 30.816 27.061 32.568 ;
     RECT  27.013 73.536 27.061 75.864 ;
     RECT  25.717 76.944 27.061 77.448 ;
     RECT  26.377 41.52 27.097 41.544 ;
     RECT  26.581 5.088 27.109 7.416 ;
     RECT  27.097 57.072 27.109 57.096 ;
     RECT  26.869 62.736 27.109 64.248 ;
     RECT  27.097 65.568 27.109 65.592 ;
     RECT  26.293 34.32 27.205 35.64 ;
     RECT  26.989 0.192 27.248 3.432 ;
     RECT  27.109 4.992 27.248 7.416 ;
     RECT  26.869 10.176 27.248 11.688 ;
     RECT  26.773 12.864 27.248 13.08 ;
     RECT  26.881 14.784 27.248 15.96 ;
     RECT  26.876 18.384 27.248 21.768 ;
     RECT  27.013 24.528 27.248 24.84 ;
     RECT  27.061 25.968 27.248 32.568 ;
     RECT  27.205 33.648 27.248 35.64 ;
     RECT  27.013 36.912 27.248 37.704 ;
     RECT  27.097 41.04 27.248 41.544 ;
     RECT  26.348 44.88 27.248 45.672 ;
     RECT  26.917 46.8 27.248 46.824 ;
     RECT  26.197 49.056 27.248 49.08 ;
     RECT  26.773 51.312 27.248 52.488 ;
     RECT  26.917 53.568 27.248 54.6 ;
     RECT  26.396 55.632 27.248 55.656 ;
     RECT  27.109 57.072 27.248 57.864 ;
     RECT  27.097 59.28 27.248 59.304 ;
     RECT  27.061 61.392 27.248 61.416 ;
     RECT  27.109 62.736 27.248 65.592 ;
     RECT  26.305 68.976 27.248 71.688 ;
     RECT  27.061 73.536 27.248 77.448 ;
     RECT  27.248 0.192 27.299 77.448 ;
     RECT  27.299 0.288 27.544 77.448 ;
     RECT  27.544 63.264 27.605 63.912 ;
     RECT  27.544 21.504 27.683 25.128 ;
     RECT  27.544 45.024 27.683 47.88 ;
     RECT  27.544 17.52 27.685 17.544 ;
     RECT  27.544 56.976 27.685 58.056 ;
     RECT  27.544 39.744 27.721 39.768 ;
     RECT  27.605 63.888 27.721 63.912 ;
     RECT  27.544 15.408 27.757 16.2 ;
     RECT  27.544 66.336 27.779 66.84 ;
     RECT  27.544 74.112 27.781 77.448 ;
     RECT  27.544 70.128 27.785 72.408 ;
     RECT  27.544 28.944 27.821 29.112 ;
     RECT  27.683 45.024 27.821 46.92 ;
     RECT  27.785 70.224 27.821 72.408 ;
     RECT  27.544 26.544 27.857 27.864 ;
     RECT  27.857 26.544 27.868 27.336 ;
     RECT  27.821 72.384 27.893 72.408 ;
     RECT  27.683 21.504 27.923 22.248 ;
     RECT  27.821 29.088 27.923 29.112 ;
     RECT  27.544 31.248 27.923 31.512 ;
     RECT  27.544 35.088 27.923 35.544 ;
     RECT  27.544 52.992 27.923 55.416 ;
     RECT  27.779 66.432 27.923 66.84 ;
     RECT  27.821 70.224 27.923 71.112 ;
     RECT  27.781 74.112 27.923 77.544 ;
     RECT  27.923 31.248 27.965 31.464 ;
     RECT  27.923 74.112 28.001 77.448 ;
     RECT  27.821 46.896 28.037 46.92 ;
     RECT  27.544 60.432 28.037 61.656 ;
     RECT  27.923 71.088 28.073 71.112 ;
     RECT  27.544 11.664 28.145 11.688 ;
     RECT  27.544 36.528 28.163 36.936 ;
     RECT  27.683 23.712 28.189 25.128 ;
     RECT  27.544 67.824 28.253 67.848 ;
     RECT  27.544 2.256 28.259 3.864 ;
     RECT  28.189 23.712 28.289 24.552 ;
     RECT  28.001 74.112 28.325 77.4 ;
     RECT  27.923 66.528 28.433 66.552 ;
     RECT  28.325 74.112 28.433 77.16 ;
     RECT  28.289 23.952 28.505 24.552 ;
     RECT  27.923 52.992 28.505 53.592 ;
     RECT  27.923 54.624 28.505 55.416 ;
     RECT  27.685 56.976 28.505 57.672 ;
     RECT  28.037 61.008 28.505 61.656 ;
     RECT  28.163 36.912 28.549 36.936 ;
     RECT  27.544 50.112 28.565 50.28 ;
     RECT  27.544 33.12 28.597 33.672 ;
     RECT  27.757 15.744 28.613 16.2 ;
     RECT  28.556 40.992 28.643 41.016 ;
     RECT  28.565 29.664 28.649 29.688 ;
     RECT  28.597 32.928 28.684 33.672 ;
     RECT  27.868 26.544 28.685 26.568 ;
     RECT  27.821 45.024 28.691 45.48 ;
     RECT  28.505 52.992 28.691 53.016 ;
     RECT  28.505 61.632 28.721 61.656 ;
     RECT  27.965 31.248 28.729 31.416 ;
     RECT  28.549 34.8 28.739 34.824 ;
     RECT  28.549 36.912 28.739 37.32 ;
     RECT  27.923 21.504 28.741 22.2 ;
     RECT  28.684 33.648 28.741 33.672 ;
     RECT  27.544 0.288 28.789 0.792 ;
     RECT  28.259 2.832 28.789 3.864 ;
     RECT  28.741 33.648 28.793 34.056 ;
     RECT  28.691 45.456 28.793 45.48 ;
     RECT  28.793 33.792 28.828 34.056 ;
     RECT  28.741 21.312 28.829 22.2 ;
     RECT  28.789 62.784 28.837 62.808 ;
     RECT  28.781 38.256 28.853 38.28 ;
     RECT  28.853 38.256 28.865 39.192 ;
     RECT  28.825 27.936 28.885 27.96 ;
     RECT  28.433 74.592 28.901 77.16 ;
     RECT  28.885 26.928 28.933 27.96 ;
     RECT  28.693 59.232 28.933 59.256 ;
     RECT  28.837 62.784 28.933 63.144 ;
     RECT  28.865 39.168 28.937 39.192 ;
     RECT  28.861 46.752 28.945 46.776 ;
     RECT  28.933 62.16 28.981 63.144 ;
     RECT  28.565 49.968 29.027 50.28 ;
     RECT  28.789 0.288 29.041 1.128 ;
     RECT  27.544 18.96 29.041 20.136 ;
     RECT  28.901 74.736 29.053 77.16 ;
     RECT  28.753 8.688 29.075 8.712 ;
     RECT  28.645 51.264 29.075 51.288 ;
     RECT  27.544 5.616 29.077 5.64 ;
     RECT  27.544 42.048 29.077 42.072 ;
     RECT  28.933 26.928 29.081 28.344 ;
     RECT  28.933 59.088 29.081 59.256 ;
     RECT  29.027 50.256 29.117 50.28 ;
     RECT  28.789 2.832 29.123 4.008 ;
     RECT  29.041 18.816 29.125 20.136 ;
     RECT  28.739 36.912 29.141 37.128 ;
     RECT  29.077 4.992 29.164 6.264 ;
     RECT  28.613 16.128 29.164 16.2 ;
     RECT  28.505 24.336 29.171 24.552 ;
     RECT  29.141 35.952 29.173 37.128 ;
     RECT  29.113 40.512 29.197 40.536 ;
     RECT  29.123 2.832 29.261 3.864 ;
     RECT  29.173 35.184 29.261 37.128 ;
     RECT  29.077 41.616 29.261 42.072 ;
     RECT  29.081 27.264 29.267 28.344 ;
     RECT  29.261 3.84 29.333 3.864 ;
     RECT  29.261 2.832 29.365 2.856 ;
     RECT  29.329 64.464 29.365 64.488 ;
     RECT  28.741 65.52 29.365 65.544 ;
     RECT  29.164 16.176 29.369 16.2 ;
     RECT  28.505 56.976 29.369 57 ;
     RECT  29.317 30.48 29.404 30.504 ;
     RECT  28.505 54.624 29.429 54.648 ;
     RECT  29.041 0.288 29.437 1.752 ;
     RECT  29.365 2.784 29.437 2.856 ;
     RECT  28.828 33.792 29.441 33.816 ;
     RECT  29.365 64.464 29.449 65.544 ;
     RECT  29.125 19.344 29.459 20.136 ;
     RECT  29.449 64.464 29.459 64.488 ;
     RECT  29.429 54.192 29.513 54.648 ;
     RECT  29.081 59.088 29.555 59.112 ;
     RECT  28.829 22.176 29.573 22.2 ;
     RECT  29.509 39.984 29.593 40.008 ;
     RECT  28.981 62.16 29.605 63.24 ;
     RECT  29.509 23.904 29.612 23.928 ;
     RECT  29.612 23.856 29.613 23.928 ;
     RECT  29.545 55.92 29.629 55.944 ;
     RECT  29.581 57.024 29.665 57.048 ;
     RECT  29.449 65.52 29.689 65.544 ;
     RECT  29.605 62.16 29.692 63.624 ;
     RECT  29.613 23.856 29.699 23.88 ;
     RECT  29.689 65.52 29.765 65.64 ;
     RECT  29.765 65.568 29.773 65.64 ;
     RECT  29.053 74.88 29.797 77.16 ;
     RECT  29.164 5.52 29.801 6.264 ;
     RECT  29.749 31.872 29.836 31.896 ;
     RECT  29.573 22.176 29.837 22.344 ;
     RECT  29.261 42.048 29.869 42.072 ;
     RECT  29.797 43.344 29.881 43.368 ;
     RECT  29.267 27.936 29.893 28.344 ;
     RECT  29.869 42.048 29.909 42.216 ;
     RECT  29.513 54.624 29.941 54.648 ;
     RECT  29.861 32.544 29.945 32.568 ;
     RECT  29.459 19.968 29.977 20.136 ;
     RECT  29.801 6.24 29.987 6.264 ;
     RECT  29.909 42.192 29.987 42.216 ;
     RECT  29.893 57.12 29.989 57.144 ;
     RECT  29.317 11.328 30.049 11.352 ;
     RECT  29.996 32.928 30.083 32.952 ;
     RECT  29.261 35.904 30.083 37.128 ;
     RECT  30.083 35.904 30.089 35.928 ;
     RECT  30.037 51.792 30.124 51.816 ;
     RECT  30.049 11.328 30.14 11.448 ;
     RECT  29.893 27.936 30.157 28.536 ;
     RECT  30.083 36.912 30.179 37.128 ;
     RECT  30.133 30.72 30.193 30.744 ;
     RECT  29.989 57.12 30.197 57.864 ;
     RECT  30.193 30.72 30.22 31.56 ;
     RECT  30.14 10.704 30.227 11.448 ;
     RECT  29.977 19.968 30.227 20.568 ;
     RECT  29.905 58.848 30.227 58.872 ;
     RECT  29.692 62.16 30.233 63.432 ;
     RECT  29.797 74.88 30.277 77.208 ;
     RECT  30.277 74.88 30.325 77.448 ;
     RECT  30.265 46.704 30.349 46.728 ;
     RECT  29.989 26.208 30.409 26.232 ;
     RECT  30.197 57.6 30.445 57.864 ;
     RECT  30.409 26.208 30.469 26.952 ;
     RECT  30.227 19.968 30.515 19.992 ;
     RECT  30.445 57.6 30.529 58.728 ;
     RECT  29.837 22.224 30.553 22.344 ;
     RECT  30.157 23.376 30.553 23.4 ;
     RECT  30.277 35.28 30.556 35.592 ;
     RECT  30.157 27.936 30.601 29.112 ;
     RECT  30.517 33.888 30.604 33.912 ;
     RECT  30.553 19.536 30.707 19.56 ;
     RECT  30.481 39.168 30.755 39.192 ;
     RECT  30.668 48.672 30.755 48.696 ;
     RECT  30.265 67.44 30.755 67.464 ;
     RECT  29.437 0.288 30.757 2.856 ;
     RECT  30.553 22.224 30.803 23.4 ;
     RECT  30.757 0.288 30.805 2.904 ;
     RECT  30.469 25.68 30.805 26.952 ;
     RECT  30.601 27.936 30.805 27.96 ;
     RECT  30.725 56.4 30.844 56.424 ;
     RECT  30.764 7.104 30.851 7.128 ;
     RECT  30.805 25.68 30.851 27.96 ;
     RECT  30.851 25.68 30.853 27.384 ;
     RECT  30.227 10.704 30.899 11.4 ;
     RECT  30.757 18.672 30.899 18.984 ;
     RECT  30.757 66.672 30.899 66.792 ;
     RECT  30.757 70.608 30.899 70.728 ;
     RECT  30.325 74.592 30.949 77.448 ;
     RECT  30.899 10.8 30.995 11.4 ;
     RECT  31.004 42.192 31.021 42.216 ;
     RECT  30.995 10.992 31.033 11.4 ;
     RECT  29.941 54.624 31.052 54.696 ;
     RECT  30.997 7.248 31.084 7.272 ;
     RECT  30.899 18.768 31.091 18.888 ;
     RECT  31.021 41.616 31.091 42.216 ;
     RECT  30.949 74.112 31.093 77.448 ;
     RECT  30.805 0.288 31.097 3.432 ;
     RECT  30.853 25.056 31.1 27.384 ;
     RECT  31.091 41.616 31.105 41.64 ;
     RECT  31.045 40.224 31.133 40.248 ;
     RECT  31.052 53.952 31.139 54.696 ;
     RECT  30.233 62.16 31.148 63.336 ;
     RECT  31.097 0.288 31.165 2.856 ;
     RECT  31.093 74.112 31.169 77.496 ;
     RECT  30.22 30.816 31.177 31.56 ;
     RECT  31.1 24.864 31.187 27.384 ;
     RECT  31.141 23.856 31.228 23.88 ;
     RECT  31.148 61.824 31.235 63.336 ;
     RECT  31.033 11.376 31.237 11.4 ;
     RECT  31.165 0.192 31.249 2.856 ;
     RECT  30.869 34.896 31.301 34.92 ;
     RECT  30.179 36.912 31.301 36.936 ;
     RECT  31.301 36.576 31.333 36.936 ;
     RECT  31.301 46.752 31.333 46.776 ;
     RECT  29.773 65.568 31.333 65.592 ;
     RECT  30.529 57.6 31.349 57.864 ;
     RECT  30.853 60.432 31.349 60.456 ;
     RECT  31.273 42.768 31.357 43.08 ;
     RECT  31.333 36.576 31.381 37.032 ;
     RECT  31.237 11.376 31.385 11.88 ;
     RECT  31.301 34.368 31.385 34.92 ;
     RECT  31.333 45.984 31.385 46.776 ;
     RECT  31.139 54.672 31.385 54.696 ;
     RECT  30.601 28.992 31.421 29.112 ;
     RECT  30.805 44.976 31.429 45 ;
     RECT  31.385 45.984 31.429 46.344 ;
     RECT  31.381 35.904 31.523 37.032 ;
     RECT  31.357 42.768 31.523 42.888 ;
     RECT  31.333 50.688 31.523 50.712 ;
     RECT  31.523 42.768 31.571 42.792 ;
     RECT  31.429 44.976 31.571 46.344 ;
     RECT  31.523 35.904 31.601 36.936 ;
     RECT  31.571 44.976 31.601 46.056 ;
     RECT  31.235 62.16 31.621 63.336 ;
     RECT  31.385 34.416 31.633 34.92 ;
     RECT  31.601 35.904 31.633 35.976 ;
     RECT  31.177 30.816 31.637 30.984 ;
     RECT  31.333 31.968 31.637 31.992 ;
     RECT  31.633 34.416 31.637 35.976 ;
     RECT  31.187 25.104 31.667 27.384 ;
     RECT  31.637 30.816 31.717 30.936 ;
     RECT  31.573 60 31.765 60.408 ;
     RECT  31.621 62.16 31.861 63.768 ;
     RECT  31.861 38.832 31.909 38.856 ;
     RECT  31.861 62.16 31.909 63.816 ;
     RECT  31.169 74.592 31.909 77.496 ;
     RECT  31.909 33.264 31.957 33.288 ;
     RECT  31.909 38.688 32.029 38.856 ;
     RECT  31.909 74.592 32.051 77.592 ;
     RECT  31.385 11.376 32.065 11.4 ;
     RECT  30.803 22.224 32.101 22.248 ;
     RECT  32.029 38.688 32.165 39.192 ;
     RECT  31.813 23.952 32.173 23.976 ;
     RECT  31.667 25.104 32.173 26.808 ;
     RECT  31.249 0.288 32.245 2.856 ;
     RECT  31.091 18.816 32.245 18.84 ;
     RECT  31.909 19.968 32.245 20.088 ;
     RECT  31.717 30.72 32.281 30.936 ;
     RECT  32.051 74.592 32.281 77.4 ;
     RECT  31.429 13.056 32.293 13.08 ;
     RECT  31.333 7.344 32.341 7.368 ;
     RECT  31.621 5.328 32.396 5.352 ;
     RECT  32.101 21.648 32.437 22.248 ;
     RECT  31.421 29.088 32.437 29.112 ;
     RECT  31.957 32.544 32.437 33.288 ;
     RECT  31.633 48.48 32.437 48.504 ;
     RECT  31.765 59.808 32.437 60.408 ;
     RECT  32.005 9.168 32.492 9.192 ;
     RECT  32.437 28.416 32.492 29.112 ;
     RECT  32.281 30.24 32.492 30.936 ;
     RECT  32.065 10.56 32.533 11.4 ;
     RECT  32.293 12.816 32.533 13.08 ;
     RECT  32.245 0.24 32.648 2.856 ;
     RECT  32.396 4.368 32.648 5.352 ;
     RECT  32.341 6.816 32.648 7.368 ;
     RECT  32.492 8.736 32.648 9.192 ;
     RECT  32.533 10.56 32.648 11.496 ;
     RECT  32.533 12.816 32.648 14.184 ;
     RECT  31.921 15.408 32.648 15.432 ;
     RECT  32.245 18.816 32.648 20.088 ;
     RECT  32.437 21.12 32.648 22.248 ;
     RECT  32.173 23.952 32.648 26.808 ;
     RECT  32.492 28.416 32.648 30.936 ;
     RECT  32.437 32.544 32.648 33.72 ;
     RECT  31.637 35.28 32.648 35.976 ;
     RECT  32.165 38.688 32.648 40.008 ;
     RECT  31.601 45.168 32.648 46.056 ;
     RECT  32.437 48.48 32.648 48.744 ;
     RECT  31.841 50.784 32.648 50.808 ;
     RECT  32.029 53.616 32.648 53.64 ;
     RECT  31.705 55.968 32.648 55.992 ;
     RECT  31.349 57.84 32.648 57.864 ;
     RECT  32.437 59.52 32.648 60.408 ;
     RECT  31.909 62.16 32.648 63.912 ;
     RECT  31.333 65.568 32.648 66.216 ;
     RECT  31.813 68.352 32.648 68.376 ;
     RECT  32.281 74.112 32.648 77.4 ;
     RECT  32.648 0.24 32.771 77.4 ;
     RECT  32.771 0.24 32.821 77.352 ;
     RECT  32.821 0.192 32.944 77.352 ;
     RECT  32.944 7.344 33.005 10.824 ;
     RECT  32.944 0.192 33.041 2.856 ;
     RECT  32.944 59.52 33.041 60.456 ;
     RECT  32.944 77.04 33.041 77.352 ;
     RECT  33.041 2.784 33.059 2.856 ;
     RECT  32.944 29.472 33.059 29.784 ;
     RECT  32.944 30.816 33.059 33.336 ;
     RECT  33.041 59.808 33.077 60.456 ;
     RECT  32.944 63.792 33.077 63.816 ;
     RECT  32.944 74.688 33.077 76.056 ;
     RECT  32.944 28.224 33.085 28.344 ;
     RECT  33.077 60.432 33.085 60.456 ;
     RECT  32.944 14.112 33.107 15.384 ;
     RECT  33.059 32.544 33.107 33.336 ;
     RECT  32.944 34.368 33.107 36.888 ;
     RECT  32.944 58.176 33.107 58.2 ;
     RECT  33.085 28.224 33.149 28.248 ;
     RECT  33.059 29.76 33.149 29.784 ;
     RECT  33.059 2.832 33.155 2.856 ;
     RECT  33.107 35.088 33.155 36.888 ;
     RECT  32.944 46.752 33.193 47.352 ;
     RECT  32.944 5.568 33.203 6.216 ;
     RECT  32.944 38.256 33.221 38.28 ;
     RECT  33.203 6.192 33.257 6.216 ;
     RECT  33.041 0.192 33.265 1.8 ;
     RECT  33.265 0.24 33.293 1.8 ;
     RECT  33.041 77.04 33.329 77.064 ;
     RECT  33.005 7.968 33.395 10.824 ;
     RECT  33.395 8.16 33.401 10.824 ;
     RECT  33.155 35.088 33.437 36.696 ;
     RECT  32.944 49.056 33.473 49.08 ;
     RECT  32.944 62.736 33.58 62.76 ;
     RECT  32.944 23.52 33.635 24.84 ;
     RECT  33.059 30.816 33.635 31.08 ;
     RECT  33.437 35.376 33.635 35.928 ;
     RECT  32.944 41.616 33.635 41.64 ;
     RECT  33.107 14.112 33.653 14.136 ;
     RECT  32.944 66.048 33.653 66.264 ;
     RECT  32.944 20.016 33.661 20.04 ;
     RECT  33.635 23.52 33.661 23.544 ;
     RECT  33.107 32.544 33.689 32.568 ;
     RECT  33.653 66.24 33.731 66.264 ;
     RECT  32.944 72.432 33.769 72.456 ;
     RECT  32.944 12.816 33.779 12.888 ;
     RECT  33.077 74.688 33.905 76.008 ;
     RECT  33.193 47.328 33.913 47.352 ;
     RECT  33.107 15.36 33.964 15.384 ;
     RECT  33.401 8.16 33.971 9.96 ;
     RECT  33.779 12.816 33.977 12.84 ;
     RECT  33.905 75.792 33.977 76.008 ;
     RECT  32.944 26.688 34.009 26.856 ;
     RECT  33.925 17.232 34.012 17.256 ;
     RECT  33.635 24.816 34.085 24.84 ;
     RECT  34.009 26.208 34.115 26.856 ;
     RECT  34.076 28.848 34.163 28.872 ;
     RECT  33.635 30.912 34.189 31.08 ;
     RECT  33.977 75.792 34.193 75.816 ;
     RECT  34.117 33.648 34.201 34.392 ;
     RECT  34.009 27.84 34.211 27.864 ;
     RECT  34.201 33.648 34.211 33.864 ;
     RECT  34.117 3.888 34.261 3.912 ;
     RECT  33.293 0.336 34.297 1.8 ;
     RECT  34.213 76.944 34.3 76.968 ;
     RECT  34.364 27.024 34.451 27.048 ;
     RECT  34.297 0.288 34.453 1.8 ;
     RECT  34.405 40.56 34.489 40.584 ;
     RECT  34.261 3.888 34.547 3.96 ;
     RECT  34.453 0.288 34.577 2.712 ;
     RECT  33.635 35.376 34.632 35.4 ;
     RECT  34.632 35.376 34.633 35.448 ;
     RECT  33.971 8.16 34.643 9.096 ;
     RECT  34.577 0.288 34.661 2.856 ;
     RECT  34.661 0.288 34.693 2.808 ;
     RECT  34.621 61.584 34.705 61.608 ;
     RECT  34.645 15.984 34.732 16.008 ;
     RECT  34.189 30.912 34.733 31.368 ;
     RECT  34.547 3.888 34.739 3.912 ;
     RECT  34.733 31.344 34.787 31.368 ;
     RECT  34.211 33.84 34.787 33.864 ;
     RECT  34.633 35.424 34.787 35.448 ;
     RECT  34.297 47.04 34.787 47.064 ;
     RECT  34.693 0.048 34.876 2.808 ;
     RECT  34.789 24.24 34.877 24.264 ;
     RECT  34.643 8.16 34.949 8.184 ;
     RECT  34.837 53.616 34.979 53.64 ;
     RECT  34.981 59.28 35.065 59.304 ;
     RECT  34.876 2.112 35.116 2.808 ;
     RECT  34.045 6.912 35.273 6.936 ;
     RECT  34.876 0.048 35.315 1.128 ;
     RECT  34.873 57.648 35.363 57.672 ;
     RECT  34.837 64.464 35.363 64.488 ;
     RECT  35.161 71.616 35.363 71.64 ;
     RECT  35.305 51.936 35.389 51.96 ;
     RECT  33.905 74.688 35.507 74.712 ;
     RECT  35.449 5.088 35.533 5.112 ;
     RECT  35.197 22.992 35.555 23.016 ;
     RECT  35.116 2.688 35.66 2.808 ;
     RECT  35.621 46.224 35.705 46.248 ;
     RECT  35.653 16.032 35.74 16.056 ;
     RECT  35.66 2.688 35.747 3.24 ;
     RECT  35.468 28.848 35.845 28.872 ;
     RECT  35.708 31.536 35.845 31.56 ;
     RECT  35.809 24.528 35.893 24.552 ;
     RECT  35.845 28.416 35.929 29.016 ;
     RECT  35.315 0.048 36.065 1.08 ;
     RECT  35.929 28.416 36.083 28.44 ;
     RECT  35.747 2.688 36.085 3 ;
     RECT  35.845 31.536 36.133 31.992 ;
     RECT  35.893 12.24 36.173 12.264 ;
     RECT  36.025 37.68 36.227 37.704 ;
     RECT  35.66 23.04 36.241 23.064 ;
     RECT  36.133 31.536 36.241 32.376 ;
     RECT  36.241 31.344 36.371 32.376 ;
     RECT  36.065 0.288 36.421 1.08 ;
     RECT  35.948 21.648 36.421 21.672 ;
     RECT  36.421 0.288 36.457 1.128 ;
     RECT  36.085 2.256 36.457 3 ;
     RECT  36.241 23.04 36.467 23.976 ;
     RECT  36.349 26.928 36.467 26.952 ;
     RECT  36.421 21.168 36.505 21.672 ;
     RECT  36.449 5.712 36.533 5.736 ;
     RECT  36.469 30.144 36.556 30.168 ;
     RECT  36.371 31.968 36.757 32.376 ;
     RECT  36.349 12 36.805 12.024 ;
     RECT  36.805 11.04 36.893 12.024 ;
     RECT  36.889 29.664 36.973 29.688 ;
     RECT  36.956 21.744 37.043 21.768 ;
     RECT  36.997 25.68 37.081 25.704 ;
     RECT  36.457 0.288 37.349 3 ;
     RECT  37.349 0.192 37.681 3 ;
     RECT  37.681 0.096 37.717 3 ;
     RECT  37.381 31.008 37.781 31.032 ;
     RECT  37.717 0.096 38.048 3.96 ;
     RECT  36.893 11.328 38.048 12.024 ;
     RECT  37.213 25.104 38.048 25.128 ;
     RECT  37.781 30.816 38.048 31.032 ;
     RECT  37.061 32.544 38.048 32.568 ;
     RECT  38.048 0.096 38.24 76.692 ;
     RECT  38.24 0.096 38.344 76.962 ;
     RECT  38.344 0.096 38.579 0.648 ;
     RECT  38.579 0.096 38.771 0.312 ;
    LAYER M5 ;
     RECT  38.736 0.085 38.76 0.144 ;
     RECT  14.064 0.144 38.76 0.323 ;
     RECT  14.064 0.323 38.664 0.339 ;
     RECT  14.016 0.339 38.664 0.427 ;
     RECT  14.064 0.427 38.664 0.555 ;
     RECT  14.064 0.555 38.568 0.659 ;
     RECT  0.24 0.517 0.36 0.787 ;
     RECT  5.64 0.517 5.76 0.787 ;
     RECT  11.04 0.517 11.16 0.787 ;
     RECT  14.064 0.659 38.352 1.139 ;
     RECT  14.064 1.139 35.064 2.677 ;
     RECT  36.048 1.139 38.352 2.677 ;
     RECT  14.064 2.677 38.352 2.731 ;
     RECT  14.064 2.731 33.384 2.867 ;
     RECT  34.464 2.731 38.352 2.915 ;
     RECT  37.488 2.915 38.352 2.963 ;
     RECT  37.728 2.963 38.352 3.011 ;
     RECT  14.064 2.867 18.072 3.443 ;
     RECT  37.92 3.011 38.352 3.971 ;
     RECT  11.04 0.787 11.352 4.405 ;
     RECT  19.152 2.867 33.384 4.533 ;
     RECT  34.464 2.915 36.504 4.533 ;
     RECT  14.88 3.443 15.336 4.547 ;
     RECT  10.896 4.405 11.352 4.933 ;
     RECT  13.152 4.501 13.176 4.933 ;
     RECT  10.896 4.933 13.176 5.035 ;
     RECT  19.152 4.533 36.504 5.163 ;
     RECT  15.024 4.547 15.336 5.603 ;
     RECT  15.024 5.603 15.24 5.699 ;
     RECT  36.48 5.163 36.504 5.747 ;
     RECT  12.432 5.035 13.176 6.037 ;
     RECT  15.024 5.699 15.048 6.197 ;
     RECT  12.432 6.037 13.368 6.251 ;
     RECT  16.44 3.443 18.072 6.805 ;
     RECT  14.496 6.197 15.048 6.827 ;
     RECT  19.152 5.163 35.496 6.851 ;
     RECT  16.44 6.805 18.12 7.333 ;
     RECT  19.152 6.851 24.12 7.333 ;
     RECT  10.896 5.035 11.352 7.443 ;
     RECT  10.896 7.443 11.448 7.531 ;
     RECT  16.44 7.333 24.12 7.861 ;
     RECT  16.44 7.861 24.552 7.909 ;
     RECT  25.584 6.851 35.496 7.909 ;
     RECT  16.44 7.909 35.496 8.149 ;
     RECT  16.272 8.149 35.496 8.245 ;
     RECT  15.024 6.827 15.048 8.437 ;
     RECT  12.432 6.251 13.176 8.485 ;
     RECT  16.224 8.245 35.496 8.569 ;
     RECT  14.688 8.437 15.048 8.885 ;
     RECT  14.16 8.885 15.048 8.973 ;
     RECT  10.896 7.531 11.352 9.061 ;
     RECT  12.384 8.485 13.176 9.061 ;
     RECT  34.176 8.569 35.496 9.107 ;
     RECT  10.896 9.061 13.176 9.253 ;
     RECT  16.224 8.569 33.192 9.323 ;
     RECT  14.688 8.973 15.048 9.747 ;
     RECT  16.224 9.323 24.12 9.747 ;
     RECT  14.688 9.747 24.12 9.835 ;
     RECT  25.152 9.323 33.192 9.925 ;
     RECT  34.176 9.107 34.2 9.925 ;
     RECT  25.152 9.925 34.2 10.027 ;
     RECT  14.688 9.835 15.048 10.293 ;
     RECT  16.224 9.835 24.12 10.293 ;
     RECT  25.152 10.027 33.192 10.293 ;
     RECT  16.224 10.293 33.192 10.347 ;
     RECT  14.592 10.293 15.048 10.595 ;
     RECT  36.816 11.029 36.84 11.317 ;
     RECT  38.04 3.971 38.352 11.317 ;
     RECT  10.896 9.253 13.368 11.637 ;
     RECT  14.688 10.595 15.048 11.637 ;
     RECT  10.896 11.637 15.048 11.725 ;
     RECT  16.224 10.347 18.072 11.941 ;
     RECT  36.816 11.317 38.352 12.035 ;
     RECT  35.472 9.107 35.496 12.191 ;
     RECT  14.688 11.725 15.048 12.213 ;
     RECT  16.08 11.941 18.072 12.213 ;
     RECT  19.152 10.347 33.192 12.213 ;
     RECT  35.472 12.191 35.928 12.275 ;
     RECT  14.688 12.213 15.096 12.515 ;
     RECT  16.08 12.213 33.192 12.517 ;
     RECT  34.176 10.027 34.2 12.725 ;
     RECT  16.032 12.517 33.192 12.819 ;
     RECT  34.176 12.725 34.488 12.819 ;
     RECT  16.032 12.819 34.488 12.907 ;
     RECT  14.688 12.515 15.048 13.573 ;
     RECT  16.032 12.907 33.192 13.573 ;
     RECT  14.688 13.573 33.192 15.315 ;
     RECT  34.176 12.907 34.488 15.315 ;
     RECT  14.688 15.315 34.488 15.403 ;
     RECT  34.176 15.403 34.488 15.955 ;
     RECT  35.472 12.275 35.496 15.955 ;
     RECT  34.176 15.955 35.496 15.989 ;
     RECT  34.176 15.989 35.688 16.043 ;
     RECT  35.472 16.043 35.688 16.077 ;
     RECT  14.688 15.403 33.192 17.221 ;
     RECT  34.176 16.043 34.2 17.221 ;
     RECT  14.688 17.221 34.2 17.643 ;
     RECT  10.896 11.725 13.368 19.317 ;
     RECT  10.896 19.317 13.704 19.404 ;
     RECT  14.688 17.643 33.192 19.404 ;
     RECT  10.896 19.404 33.192 19.957 ;
     RECT  34.176 17.643 34.2 19.957 ;
     RECT  10.896 19.957 34.2 20.051 ;
     RECT  10.896 20.051 33.192 20.459 ;
     RECT  34.176 20.051 34.2 20.523 ;
     RECT  35.472 16.077 35.496 21.109 ;
     RECT  35.472 21.109 36.456 21.203 ;
     RECT  10.896 20.459 24.168 21.779 ;
     RECT  37.008 21.685 37.032 21.779 ;
     RECT  14.688 21.779 24.168 22.319 ;
     RECT  25.152 20.459 33.192 22.319 ;
     RECT  10.896 21.779 13.656 22.537 ;
     RECT  10.896 22.537 13.608 22.789 ;
     RECT  14.688 22.319 33.192 22.965 ;
     RECT  35.472 21.203 36.024 23.029 ;
     RECT  14.688 22.965 34.104 23.787 ;
     RECT  35.472 23.029 36.456 23.987 ;
     RECT  35.472 23.987 36.024 24.107 ;
     RECT  25.152 23.787 34.104 24.211 ;
     RECT  35.472 24.107 35.88 24.211 ;
     RECT  25.152 24.211 35.88 24.299 ;
     RECT  35.472 24.299 35.88 24.563 ;
     RECT  10.848 22.789 13.608 24.821 ;
     RECT  14.688 23.787 24.168 25.007 ;
     RECT  25.152 24.299 34.104 25.007 ;
     RECT  38.04 12.035 38.352 25.055 ;
     RECT  37.584 25.055 38.352 25.139 ;
     RECT  10.848 24.821 13.656 25.631 ;
     RECT  14.688 25.007 34.104 25.631 ;
     RECT  37.008 25.631 37.032 25.715 ;
     RECT  10.848 25.631 34.104 26.771 ;
     RECT  35.472 24.563 35.496 26.869 ;
     RECT  14.688 26.771 34.104 26.893 ;
     RECT  35.472 26.869 36.456 26.963 ;
     RECT  34.176 26.997 34.44 27.085 ;
     RECT  10.848 26.771 13.608 27.765 ;
     RECT  14.688 26.893 33.192 27.765 ;
     RECT  10.848 27.765 33.192 27.819 ;
     RECT  10.848 27.819 24.168 27.875 ;
     RECT  34.176 27.085 34.2 27.913 ;
     RECT  35.472 26.963 35.496 28.405 ;
     RECT  35.472 28.405 36.072 28.489 ;
     RECT  25.152 27.819 33.192 28.837 ;
     RECT  14.784 27.875 24.168 28.981 ;
     RECT  25.152 28.837 34.152 28.981 ;
     RECT  14.784 28.981 34.152 29.035 ;
     RECT  35.472 28.489 35.88 29.065 ;
     RECT  14.784 29.035 33.192 29.123 ;
     RECT  14.784 29.123 29.448 29.611 ;
     RECT  14.784 29.611 29.352 29.699 ;
     RECT  36.912 29.615 36.936 29.699 ;
     RECT  14.784 29.699 24.168 29.941 ;
     RECT  36.48 30.099 36.504 30.187 ;
     RECT  10.848 27.875 13.608 30.197 ;
     RECT  14.688 29.941 24.168 30.197 ;
     RECT  10.848 30.197 24.168 30.285 ;
     RECT  25.152 29.699 29.352 30.571 ;
     RECT  30.96 29.123 33.192 30.675 ;
     RECT  30.144 30.675 33.192 30.763 ;
     RECT  30.24 30.763 33.192 30.767 ;
     RECT  38.04 25.139 38.352 30.773 ;
     RECT  30.24 30.767 33.624 30.851 ;
     RECT  14.688 30.285 24.168 30.997 ;
     RECT  25.152 30.571 29.064 30.997 ;
     RECT  37.824 30.773 38.352 30.997 ;
     RECT  37.392 30.997 38.352 31.083 ;
     RECT  34.176 30.901 34.248 31.091 ;
     RECT  35.472 29.065 35.496 31.333 ;
     RECT  10.848 30.285 13.608 31.343 ;
     RECT  14.688 30.997 29.064 31.343 ;
     RECT  34.752 31.333 36.36 31.417 ;
     RECT  10.8 31.343 29.064 31.427 ;
     RECT  30.24 30.851 33.192 31.595 ;
     RECT  10.848 31.427 29.064 31.861 ;
     RECT  10.848 31.861 29.928 31.915 ;
     RECT  35.472 31.417 36.36 31.919 ;
     RECT  35.472 31.919 36.744 32.427 ;
     RECT  30.96 31.595 33.192 32.495 ;
     RECT  38.04 31.083 38.352 32.495 ;
     RECT  14.784 31.915 29.928 32.579 ;
     RECT  30.96 32.495 33.672 32.579 ;
     RECT  37.104 32.495 38.352 32.579 ;
     RECT  30.96 32.579 33.192 32.885 ;
     RECT  30.048 32.885 33.192 32.973 ;
     RECT  34.176 33.269 34.2 33.781 ;
     RECT  35.472 32.427 35.496 33.781 ;
     RECT  34.176 33.781 35.496 33.875 ;
     RECT  30.528 32.973 33.192 33.933 ;
     RECT  30.912 33.933 33.192 34.357 ;
     RECT  14.784 32.579 24.168 34.411 ;
     RECT  14.784 34.411 18.792 34.741 ;
     RECT  14.688 34.741 18.792 34.883 ;
     RECT  25.152 32.579 28.968 35.155 ;
     RECT  30.912 34.357 34.152 35.253 ;
     RECT  30.288 35.253 34.152 35.317 ;
     RECT  35.472 33.875 35.496 35.317 ;
     RECT  30.288 35.317 35.496 35.411 ;
     RECT  10.848 31.915 13.608 35.445 ;
     RECT  14.688 34.883 18.504 35.445 ;
     RECT  34.752 35.411 35.496 35.459 ;
     RECT  10.848 35.445 18.504 35.555 ;
     RECT  19.776 34.411 24.168 35.893 ;
     RECT  25.152 35.155 29.208 35.893 ;
     RECT  30.288 35.411 33.624 35.893 ;
     RECT  19.776 35.893 33.624 35.977 ;
     RECT  19.776 35.977 33.384 35.987 ;
     RECT  14.688 35.555 18.504 36.213 ;
     RECT  14.688 36.213 18.792 36.469 ;
     RECT  19.776 35.987 24.168 36.469 ;
     RECT  14.688 36.469 24.168 36.515 ;
     RECT  19.728 36.515 24.168 36.553 ;
     RECT  25.152 35.987 33.384 36.715 ;
     RECT  30.048 36.715 33.384 36.843 ;
     RECT  30.048 36.843 33.144 36.851 ;
     RECT  30.144 36.851 33.144 36.937 ;
     RECT  25.152 36.715 29.016 37.139 ;
     RECT  30.144 36.937 33.096 37.139 ;
     RECT  35.472 35.459 35.496 37.621 ;
     RECT  35.472 37.621 36.216 37.715 ;
     RECT  14.688 36.515 18.696 37.813 ;
     RECT  19.776 36.553 24.168 37.813 ;
     RECT  14.688 37.813 24.168 37.907 ;
     RECT  30.96 37.139 33.096 38.197 ;
     RECT  30.96 38.197 33.192 38.291 ;
     RECT  30.96 38.291 33.096 38.379 ;
     RECT  25.152 37.139 28.968 38.635 ;
     RECT  14.688 37.907 18.504 38.965 ;
     RECT  14.688 38.965 18.648 39.157 ;
     RECT  30.96 38.379 33.048 39.157 ;
     RECT  19.776 37.907 24.168 39.187 ;
     RECT  14.64 39.157 18.648 39.241 ;
     RECT  30.72 39.157 33.048 39.241 ;
     RECT  19.728 39.187 24.168 39.699 ;
     RECT  25.152 38.635 28.92 39.699 ;
     RECT  14.688 39.241 18.648 39.733 ;
     RECT  19.728 39.699 28.92 39.733 ;
     RECT  14.688 39.733 28.92 39.787 ;
     RECT  14.688 39.787 24.168 39.817 ;
     RECT  25.152 39.787 28.92 39.925 ;
     RECT  25.152 39.925 29.544 40.019 ;
     RECT  25.152 40.019 29.16 40.585 ;
     RECT  14.688 39.817 18.696 40.595 ;
     RECT  34.416 40.501 34.44 40.595 ;
     RECT  10.848 35.555 13.608 41.235 ;
     RECT  14.688 40.595 18.504 41.235 ;
     RECT  10.848 41.235 18.504 41.323 ;
     RECT  25.152 40.585 28.632 41.567 ;
     RECT  30.96 39.241 33.048 41.567 ;
     RECT  25.152 41.567 29.112 41.651 ;
     RECT  30.96 41.567 33.624 41.651 ;
     RECT  7.632 38.725 7.656 41.749 ;
     RECT  14.688 41.323 18.504 42.003 ;
     RECT  19.776 39.817 24.168 42.003 ;
     RECT  14.688 42.003 24.168 42.091 ;
     RECT  29.952 42.143 29.976 42.227 ;
     RECT  29.808 43.295 29.832 43.379 ;
     RECT  19.776 42.091 24.168 43.871 ;
     RECT  25.152 41.651 28.584 43.871 ;
     RECT  19.776 43.871 28.584 43.955 ;
     RECT  25.152 43.955 28.584 45.013 ;
     RECT  14.688 42.091 18.216 46.005 ;
     RECT  35.472 37.715 35.496 46.175 ;
     RECT  35.472 46.175 35.688 46.259 ;
     RECT  30.96 41.651 33.048 46.517 ;
     RECT  14.688 46.005 18.552 46.741 ;
     RECT  25.152 45.013 28.68 46.741 ;
     RECT  30.288 46.517 33.048 46.741 ;
     RECT  30.288 46.741 33.144 46.763 ;
     RECT  14.688 46.741 18.792 46.773 ;
     RECT  19.776 43.955 24.168 46.773 ;
     RECT  25.152 46.741 28.92 46.827 ;
     RECT  35.472 46.259 35.496 47.029 ;
     RECT  14.688 46.773 24.168 47.083 ;
     RECT  34.752 47.029 35.496 47.113 ;
     RECT  30.96 46.763 33.144 47.279 ;
     RECT  14.688 47.083 18.792 47.363 ;
     RECT  30.96 47.279 33.864 47.363 ;
     RECT  10.848 41.323 13.608 47.763 ;
     RECT  14.688 47.363 18.216 47.763 ;
     RECT  10.848 47.763 18.216 47.851 ;
     RECT  14.688 47.851 18.216 48.431 ;
     RECT  19.776 47.083 24.168 48.431 ;
     RECT  30.96 47.363 33.048 48.661 ;
     RECT  30.72 48.661 33.048 48.747 ;
     RECT  14.688 48.431 18.36 49.007 ;
     RECT  19.344 48.431 24.168 49.007 ;
     RECT  30.96 48.747 33.048 49.007 ;
     RECT  14.688 49.007 24.168 49.091 ;
     RECT  30.96 49.007 33.192 49.091 ;
     RECT  10.848 47.851 13.608 49.957 ;
     RECT  14.688 49.091 18.216 49.957 ;
     RECT  25.152 46.827 28.68 49.957 ;
     RECT  10.848 49.957 18.216 50.041 ;
     RECT  25.152 49.957 29.016 50.041 ;
     RECT  10.848 50.041 13.704 50.819 ;
     RECT  25.152 50.041 28.68 51.253 ;
     RECT  25.152 51.253 29.064 51.337 ;
     RECT  30.96 49.091 33.048 51.781 ;
     RECT  10.848 50.819 13.608 51.877 ;
     RECT  14.688 50.041 18.216 51.877 ;
     RECT  30.048 51.781 33.048 51.883 ;
     RECT  35.472 47.113 35.496 51.887 ;
     RECT  10.8 51.877 18.216 51.961 ;
     RECT  35.328 51.887 35.496 51.971 ;
     RECT  25.152 51.337 28.68 53.027 ;
     RECT  19.776 49.091 24.168 53.557 ;
     RECT  25.152 53.027 28.584 53.557 ;
     RECT  35.472 51.971 35.496 53.557 ;
     RECT  19.776 53.557 28.584 53.651 ;
     RECT  34.944 53.557 35.496 53.651 ;
     RECT  10.8 51.961 13.608 54.047 ;
     RECT  10.224 54.047 13.608 54.131 ;
     RECT  25.152 53.651 28.584 54.133 ;
     RECT  25.152 54.133 29.496 54.227 ;
     RECT  10.8 54.131 13.608 54.755 ;
     RECT  14.688 51.961 18.216 54.837 ;
     RECT  19.776 53.651 24.168 54.837 ;
     RECT  14.688 54.837 24.168 55.187 ;
     RECT  7.584 41.749 7.656 55.237 ;
     RECT  8.88 55.285 8.904 55.861 ;
     RECT  10.848 54.755 13.608 55.891 ;
     RECT  10.8 55.891 13.608 55.909 ;
     RECT  14.688 55.187 18.216 55.909 ;
     RECT  29.952 54.661 29.976 55.909 ;
     RECT  10.8 55.909 18.216 55.979 ;
     RECT  10.848 55.979 18.216 55.993 ;
     RECT  29.568 55.909 29.976 55.993 ;
     RECT  29.952 55.993 29.976 56.351 ;
     RECT  30.96 51.883 33.048 56.351 ;
     RECT  29.952 56.351 33.048 56.435 ;
     RECT  14.688 55.993 18.216 56.917 ;
     RECT  19.776 55.187 24.168 56.917 ;
     RECT  14.688 56.917 24.168 57.003 ;
     RECT  7.488 55.237 7.656 57.013 ;
     RECT  29.952 56.435 29.976 57.013 ;
     RECT  29.616 57.013 29.976 57.097 ;
     RECT  14.688 57.003 18.456 57.107 ;
     RECT  10.848 55.993 13.608 57.141 ;
     RECT  7.44 57.013 7.656 57.589 ;
     RECT  29.904 57.097 29.976 57.589 ;
     RECT  30.96 56.435 33.048 57.589 ;
     RECT  35.472 53.651 35.496 57.589 ;
     RECT  19.632 57.003 24.168 57.683 ;
     RECT  35.328 57.589 35.496 57.683 ;
     RECT  7.344 57.589 7.656 57.685 ;
     RECT  10.752 57.141 13.608 58.117 ;
     RECT  29.904 57.589 33.048 58.131 ;
     RECT  29.904 58.131 33.096 58.219 ;
     RECT  14.688 57.107 18.216 58.549 ;
     RECT  14.688 58.549 18.792 58.633 ;
     RECT  10.032 58.117 13.608 58.741 ;
     RECT  14.688 58.633 18.216 58.741 ;
     RECT  19.776 57.683 24.168 58.741 ;
     RECT  10.032 58.741 18.216 58.835 ;
     RECT  19.2 58.741 24.168 58.835 ;
     RECT  25.152 54.227 28.584 59.077 ;
     RECT  29.904 58.219 33.048 59.077 ;
     RECT  25.152 59.077 33.048 59.179 ;
     RECT  7.344 57.685 7.704 59.221 ;
     RECT  35.472 57.683 35.496 59.231 ;
     RECT  34.992 59.231 35.496 59.315 ;
     RECT  14.688 58.835 18.216 60.213 ;
     RECT  19.776 58.835 24.168 60.213 ;
     RECT  14.688 60.213 24.168 60.301 ;
     RECT  29.904 59.179 33.048 60.467 ;
     RECT  19.776 60.301 24.168 60.767 ;
     RECT  25.152 59.179 28.728 60.767 ;
     RECT  7.344 59.221 7.752 60.949 ;
     RECT  8.736 55.861 8.904 60.949 ;
     RECT  19.776 60.767 28.728 61.043 ;
     RECT  19.776 61.043 24.168 61.365 ;
     RECT  19.584 61.365 24.168 61.453 ;
     RECT  35.472 59.315 35.496 61.535 ;
     RECT  34.656 61.535 35.496 61.619 ;
     RECT  10.032 58.835 13.608 62.111 ;
     RECT  14.688 60.301 18.216 62.111 ;
     RECT  25.152 61.043 28.728 62.149 ;
     RECT  29.904 60.467 32.952 62.149 ;
     RECT  10.032 62.111 18.792 62.195 ;
     RECT  14.688 62.195 18.792 62.581 ;
     RECT  19.776 61.453 24.168 62.581 ;
     RECT  25.152 62.149 32.952 62.709 ;
     RECT  14.688 62.581 24.168 62.723 ;
     RECT  19.584 62.723 24.168 62.797 ;
     RECT  25.152 62.709 33.528 62.797 ;
     RECT  19.776 62.797 24.168 63.445 ;
     RECT  25.152 62.797 32.952 63.445 ;
     RECT  19.776 63.445 32.952 63.531 ;
     RECT  10.032 62.195 13.608 63.571 ;
     RECT  14.688 62.723 18.216 63.571 ;
     RECT  10.032 63.571 18.216 63.659 ;
     RECT  35.472 61.619 35.496 64.415 ;
     RECT  34.848 64.415 35.496 64.499 ;
     RECT  7.344 60.949 8.904 64.885 ;
     RECT  10.032 63.659 13.608 64.885 ;
     RECT  19.776 63.531 24.168 65.519 ;
     RECT  19.44 65.519 24.168 65.603 ;
     RECT  7.344 64.885 13.608 66.143 ;
     RECT  14.688 63.659 18.216 66.143 ;
     RECT  19.776 65.603 24.168 66.143 ;
     RECT  25.152 63.531 32.952 66.143 ;
     RECT  7.344 66.143 18.216 66.227 ;
     RECT  19.776 66.143 32.952 66.229 ;
     RECT  19.776 66.229 33.72 66.313 ;
     RECT  19.776 66.313 32.952 66.803 ;
     RECT  7.344 66.227 13.704 67.247 ;
     RECT  14.688 66.227 18.216 67.247 ;
     RECT  19.776 66.803 24.168 67.247 ;
     RECT  7.344 67.247 18.216 67.331 ;
     RECT  19.536 67.247 24.168 67.331 ;
     RECT  14.688 67.331 18.216 67.717 ;
     RECT  14.688 67.717 18.552 67.819 ;
     RECT  19.776 67.331 24.168 68.773 ;
     RECT  14.688 67.819 18.216 69.445 ;
     RECT  19.296 68.773 24.168 69.445 ;
     RECT  7.344 67.331 13.608 69.493 ;
     RECT  14.688 69.445 24.168 69.493 ;
     RECT  7.344 69.493 24.168 70.117 ;
     RECT  25.152 66.803 32.952 70.117 ;
     RECT  35.472 64.499 35.496 71.605 ;
     RECT  35.328 71.605 35.496 71.689 ;
     RECT  7.344 70.117 32.952 72.373 ;
     RECT  7.344 72.373 33.72 72.467 ;
     RECT  35.472 71.689 35.496 74.723 ;
     RECT  0.24 0.787 0.552 76.884 ;
     RECT  5.64 0.787 5.952 76.884 ;
     RECT  38.04 32.579 38.352 76.884 ;
     RECT  0.432 76.884 0.552 76.973 ;
     RECT  5.832 76.884 5.952 76.973 ;
     RECT  7.344 72.467 32.952 76.973 ;
     RECT  38.232 76.884 38.352 76.973 ;
     RECT  7.344 76.973 32.76 77.483 ;
     RECT  34.224 76.933 34.248 77.483 ;
     RECT  7.344 77.483 32.04 77.584 ;
     RECT  31.92 77.584 32.04 77.603 ;
     RECT  32.016 77.603 32.04 77.641 ;
    LAYER M6 ;
     RECT  0 54.996 10.213 55.86 ;
     RECT  0 65.796 10.213 66.66 ;
     RECT  10.213 65.796 10.741 67.488 ;
     RECT  0 71.196 10.741 72.06 ;
     RECT  10.213 54.08 10.789 55.86 ;
     RECT  10.741 57.152 10.789 57.184 ;
     RECT  0 27.996 10.869 28.86 ;
     RECT  10.837 62.848 10.869 62.88 ;
     RECT  10.869 62.72 10.923 62.88 ;
     RECT  0 6.396 10.933 7.26 ;
     RECT  0 22.596 10.933 23.46 ;
     RECT  10.869 27.996 10.942 29.024 ;
     RECT  10.741 65.796 11.115 68 ;
     RECT  0 17.196 11.125 18.06 ;
     RECT  10.789 54.08 11.125 57.184 ;
     RECT  10.933 6.396 11.371 7.968 ;
     RECT  0 11.796 11.381 12.66 ;
     RECT  0 49.596 11.381 50.46 ;
     RECT  10.997 20.736 11.445 20.768 ;
     RECT  10.933 22.596 11.445 24.544 ;
     RECT  11.371 6.396 11.459 7.52 ;
     RECT  10.789 31.36 11.459 31.392 ;
     RECT  11.125 53.568 11.459 57.184 ;
     RECT  10.923 62.72 11.507 62.752 ;
     RECT  11.061 26.176 11.509 26.208 ;
     RECT  10.942 27.996 11.509 28.86 ;
     RECT  10.741 71.196 11.509 73.248 ;
     RECT  0 60.396 11.605 61.26 ;
     RECT  11.509 71.196 11.651 73.568 ;
     RECT  0 38.796 11.797 39.66 ;
     RECT  11.605 59.968 11.893 61.26 ;
     RECT  11.381 46.912 11.939 46.944 ;
     RECT  11.653 51.84 12.021 51.872 ;
     RECT  11.459 54.08 12.075 57.184 ;
     RECT  12.075 54.72 12.083 57.184 ;
     RECT  11.125 17.196 12.085 18.208 ;
     RECT  12.085 42.56 12.133 42.592 ;
     RECT  10.933 4.992 12.227 5.024 ;
     RECT  11.893 31.04 12.277 31.072 ;
     RECT  0 33.396 12.325 34.26 ;
     RECT  11.381 49.152 12.325 50.46 ;
     RECT  12.325 49.024 12.395 50.46 ;
     RECT  11.893 59.968 12.459 61.6 ;
     RECT  12.133 42.56 12.517 42.72 ;
     RECT  0 44.196 12.517 45.06 ;
     RECT  11.115 65.796 12.642 67.488 ;
     RECT  12.395 49.596 12.709 50.46 ;
     RECT  12.021 51.84 12.709 52 ;
     RECT  12.642 65.796 12.715 68.576 ;
     RECT  11.651 71.196 12.715 73.248 ;
     RECT  12.709 49.596 12.755 52 ;
     RECT  11.445 20.736 12.789 24.544 ;
     RECT  12.459 59.968 13.045 61.26 ;
     RECT  13.093 62.592 13.163 62.624 ;
     RECT  12.715 65.796 13.163 67.488 ;
     RECT  12.517 42.56 13.237 45.06 ;
     RECT  13.163 65.796 13.237 67.296 ;
     RECT  13.237 65.024 13.306 67.296 ;
     RECT  11.459 6.396 13.333 7.26 ;
     RECT  13.237 42.112 13.365 45.06 ;
     RECT  11.797 38.796 13.419 39.904 ;
     RECT  12.085 17.196 13.429 18.848 ;
     RECT  12.789 20.224 13.429 24.544 ;
     RECT  12.083 54.996 13.483 57.184 ;
     RECT  13.365 41.28 13.498 45.06 ;
     RECT  13.483 54.996 13.523 56.416 ;
     RECT  0 0.996 13.557 1.86 ;
     RECT  13.429 17.196 13.602 24.544 ;
     RECT  13.557 0.832 13.621 1.86 ;
     RECT  12.755 49.596 13.739 51.936 ;
     RECT  13.621 0.448 13.813 1.86 ;
     RECT  13.602 17.196 13.813 24.864 ;
     RECT  11.509 26.176 13.813 28.86 ;
     RECT  13.739 51.904 13.882 51.936 ;
     RECT  13.045 59.072 14.005 61.26 ;
     RECT  13.498 41.28 14.051 42.72 ;
     RECT  12.277 30.144 14.069 31.072 ;
     RECT  14.005 58.752 14.074 61.26 ;
     RECT  12.325 33.396 14.123 35.488 ;
     RECT  13.813 0.384 14.133 1.86 ;
     RECT  14.069 30.144 14.147 31.904 ;
     RECT  14.074 59.072 14.197 61.26 ;
     RECT  14.197 59.072 14.266 62.176 ;
     RECT  14.133 0.256 14.325 1.86 ;
     RECT  14.147 30.144 14.387 31.392 ;
     RECT  14.325 0.256 14.389 2.848 ;
     RECT  12.517 46.784 14.389 46.816 ;
     RECT  13.739 49.596 14.389 50.592 ;
     RECT  13.333 5.632 14.443 7.26 ;
     RECT  13.813 17.196 14.453 28.86 ;
     RECT  14.387 30.144 14.453 31.008 ;
     RECT  13.306 65.796 14.458 67.296 ;
     RECT  14.389 46.784 14.483 50.592 ;
     RECT  13.523 54.996 14.507 55.968 ;
     RECT  11.317 10.304 14.517 10.336 ;
     RECT  11.381 11.648 14.517 12.66 ;
     RECT  14.443 6.208 14.531 7.26 ;
     RECT  14.149 8.896 14.571 8.928 ;
     RECT  14.483 46.784 14.571 46.88 ;
     RECT  14.483 48.384 14.571 50.592 ;
     RECT  14.341 63.616 14.754 63.648 ;
     RECT  14.051 42.112 15.107 42.72 ;
     RECT  14.517 10.304 15.147 12.66 ;
     RECT  13.498 44.196 15.157 45.06 ;
     RECT  14.531 6.272 15.211 7.26 ;
     RECT  14.754 63.168 15.275 63.648 ;
     RECT  15.157 43.328 15.285 45.06 ;
     RECT  14.571 46.784 15.285 46.816 ;
     RECT  0 76.596 15.397 76.884 ;
     RECT  15.275 63.168 15.418 63.328 ;
     RECT  14.453 17.196 15.443 31.008 ;
     RECT  15.418 63.168 15.443 63.2 ;
     RECT  12.715 71.196 15.445 72.06 ;
     RECT  15.397 75.84 15.467 76.884 ;
     RECT  14.389 0.128 15.477 2.848 ;
     RECT  15.413 4.864 15.477 4.896 ;
     RECT  15.445 71.196 15.531 72.416 ;
     RECT  15.541 53.568 15.61 53.6 ;
     RECT  14.458 65.796 15.637 66.66 ;
     RECT  15.443 21.056 15.659 30.688 ;
     RECT  13.419 38.796 15.797 39.66 ;
     RECT  15.733 41.024 15.802 41.632 ;
     RECT  15.797 38.208 15.854 39.66 ;
     RECT  15.477 0.128 15.915 4.896 ;
     RECT  15.802 41.536 15.915 41.632 ;
     RECT  15.147 10.304 15.925 10.336 ;
     RECT  15.443 17.196 15.925 19.744 ;
     RECT  14.571 48.384 15.925 50.46 ;
     RECT  15.637 65.536 15.973 66.66 ;
     RECT  15.659 21.056 15.979 30.56 ;
     RECT  15.854 38.08 15.989 39.66 ;
     RECT  15.925 16 15.994 19.744 ;
     RECT  15.467 76.596 16.021 76.884 ;
     RECT  15.973 65.024 16.107 66.66 ;
     RECT  15.285 43.328 16.117 46.816 ;
     RECT  15.925 48.384 16.117 50.976 ;
     RECT  14.266 59.072 16.117 61.26 ;
     RECT  16.117 43.328 16.186 50.976 ;
     RECT  16.117 53.056 16.186 53.088 ;
     RECT  14.507 54.996 16.213 55.86 ;
     RECT  15.925 57.6 16.213 57.632 ;
     RECT  16.117 59.072 16.213 62.56 ;
     RECT  15.915 41.6 16.235 41.632 ;
     RECT  15.989 37.056 16.245 39.66 ;
     RECT  16.213 54.996 16.299 62.56 ;
     RECT  16.245 37.056 16.309 39.776 ;
     RECT  15.979 21.056 16.355 25.056 ;
     RECT  16.309 35.904 16.491 39.776 ;
     RECT  16.021 76.596 16.499 77.024 ;
     RECT  15.925 9.792 16.565 10.336 ;
     RECT  15.147 11.796 16.565 12.66 ;
     RECT  14.123 33.396 16.565 34.26 ;
     RECT  16.299 57.6 16.619 62.176 ;
     RECT  15.211 6.396 16.693 7.26 ;
     RECT  15.994 17.196 16.821 19.744 ;
     RECT  16.355 21.056 16.821 23.46 ;
     RECT  16.186 48.384 16.883 50.976 ;
     RECT  16.107 65.796 16.885 66.66 ;
     RECT  15.915 3.904 16.931 4.896 ;
     RECT  16.565 9.408 16.931 13.664 ;
     RECT  15.915 0.128 17.003 2.272 ;
     RECT  16.693 6.396 17.027 8.032 ;
     RECT  16.931 11.796 17.027 13.664 ;
     RECT  16.299 54.996 17.077 55.968 ;
     RECT  15.531 71.196 17.077 72.06 ;
     RECT  16.186 43.328 17.123 46.944 ;
     RECT  16.883 48.384 17.123 50.46 ;
     RECT  17.077 71.196 17.267 73.056 ;
     RECT  16.931 3.904 17.363 4 ;
     RECT  15.979 26.624 17.507 30.56 ;
     RECT  16.619 58.176 17.53 62.176 ;
     RECT  17.557 42.752 17.643 42.784 ;
     RECT  17.605 63.872 17.701 63.904 ;
     RECT  16.885 65.796 17.701 69.024 ;
     RECT  16.821 17.196 17.774 23.46 ;
     RECT  17.507 27.392 17.845 30.56 ;
     RECT  17.893 51.904 17.963 51.936 ;
     RECT  17.077 54.848 17.966 55.968 ;
     RECT  16.355 25.024 17.973 25.056 ;
     RECT  17.966 54.72 18.037 55.968 ;
     RECT  17.774 17.196 18.085 23.584 ;
     RECT  17.973 25.024 18.085 25.632 ;
     RECT  18.037 53.568 18.085 55.968 ;
     RECT  17.53 58.56 18.085 62.176 ;
     RECT  17.701 63.872 18.085 69.024 ;
     RECT  18.085 53.568 18.131 57.056 ;
     RECT  18.085 17.196 18.155 25.632 ;
     RECT  18.085 58.56 18.155 69.024 ;
     RECT  17.845 27.392 18.179 30.624 ;
     RECT  18.155 58.56 18.219 67.808 ;
     RECT  16.491 36.416 18.229 39.776 ;
     RECT  17.027 6.396 18.421 7.26 ;
     RECT  16.931 10.304 18.421 10.336 ;
     RECT  17.027 11.796 18.421 12.66 ;
     RECT  18.229 36.416 18.515 41.056 ;
     RECT  18.229 15.552 18.549 15.84 ;
     RECT  17.003 0.256 18.563 2.272 ;
     RECT  17.123 44.196 18.563 46.944 ;
     RECT  18.219 65.536 18.563 67.808 ;
     RECT  18.155 21.952 18.611 25.632 ;
     RECT  16.565 32.384 18.613 34.26 ;
     RECT  18.515 36.416 18.613 40.544 ;
     RECT  18.421 10.304 18.622 12.66 ;
     RECT  18.179 27.392 18.667 29.984 ;
     RECT  18.613 36.224 18.731 40.544 ;
     RECT  18.563 46.784 18.734 46.944 ;
     RECT  17.123 48.448 18.734 50.46 ;
     RECT  18.563 0.256 18.741 1.86 ;
     RECT  18.421 6.396 18.757 7.392 ;
     RECT  18.613 31.296 18.757 34.26 ;
     RECT  18.734 46.784 18.803 50.46 ;
     RECT  18.131 54.848 18.851 57.056 ;
     RECT  18.757 31.296 18.859 34.848 ;
     RECT  18.219 58.56 18.859 63.904 ;
     RECT  18.803 46.784 18.899 47.072 ;
     RECT  18.899 46.912 18.923 47.072 ;
     RECT  18.667 27.392 18.933 29.664 ;
     RECT  18.859 62.72 18.987 63.904 ;
     RECT  18.949 42.048 18.997 42.08 ;
     RECT  18.563 44.196 18.997 45.06 ;
     RECT  18.549 15.424 19.045 15.84 ;
     RECT  18.155 17.196 19.045 20.512 ;
     RECT  18.997 42.048 19.051 45.06 ;
     RECT  18.859 58.56 19.051 61.408 ;
     RECT  19.051 58.56 19.115 59.104 ;
     RECT  18.933 27.264 19.125 29.664 ;
     RECT  19.045 15.424 19.179 20.512 ;
     RECT  19.115 58.56 19.258 58.784 ;
     RECT  18.731 36.224 19.307 40.416 ;
     RECT  17.363 3.968 19.381 4 ;
     RECT  19.381 3.968 19.477 4.768 ;
     RECT  18.611 21.952 19.509 24.48 ;
     RECT  19.125 26.176 19.571 29.664 ;
     RECT  18.563 65.536 19.571 67.296 ;
     RECT  19.477 3.456 19.573 4.768 ;
     RECT  18.851 54.996 19.621 57.056 ;
     RECT  18.987 62.72 19.642 63.84 ;
     RECT  19.573 3.456 19.691 4.896 ;
     RECT  19.621 54.996 19.691 57.632 ;
     RECT  19.571 27.84 19.715 29.664 ;
     RECT  18.859 31.36 19.859 34.848 ;
     RECT  18.741 0.064 19.883 1.86 ;
     RECT  19.571 26.176 19.883 26.208 ;
     RECT  19.307 36.224 20.003 39.66 ;
     RECT  19.691 54.996 20.149 57.056 ;
     RECT  20.149 54.72 20.218 57.056 ;
     RECT  18.757 6.396 20.291 7.904 ;
     RECT  19.715 27.996 20.341 29.664 ;
     RECT  19.859 31.36 20.341 34.4 ;
     RECT  19.642 63.488 20.459 63.84 ;
     RECT  19.571 65.536 20.462 66.66 ;
     RECT  20.462 65.024 20.531 66.66 ;
     RECT  19.509 20.928 20.581 24.48 ;
     RECT  19.051 60.396 20.581 61.408 ;
     RECT  19.051 43.008 20.627 45.06 ;
     RECT  18.622 10.496 20.773 12.66 ;
     RECT  20.005 14.08 20.773 14.112 ;
     RECT  20.341 27.996 20.843 34.4 ;
     RECT  20.218 54.996 20.907 57.056 ;
     RECT  19.691 4.864 20.915 4.896 ;
     RECT  20.003 38.016 20.915 39.66 ;
     RECT  20.581 20.864 20.971 24.48 ;
     RECT  20.581 60.396 21.013 61.6 ;
     RECT  20.459 63.488 21.013 63.52 ;
     RECT  20.965 58.752 21.035 58.784 ;
     RECT  20.773 10.496 21.061 14.112 ;
     RECT  19.179 15.424 21.061 19.552 ;
     RECT  21.013 60.396 21.099 63.52 ;
     RECT  19.691 3.456 21.155 3.488 ;
     RECT  20.843 27.996 21.251 34.26 ;
     RECT  19.883 0.128 21.253 1.86 ;
     RECT  21.061 10.496 21.365 19.552 ;
     RECT  20.291 6.396 21.419 7.584 ;
     RECT  20.003 36.224 21.422 36.704 ;
     RECT  18.923 46.912 21.429 46.944 ;
     RECT  18.803 48.448 21.429 50.46 ;
     RECT  16.499 76.596 21.445 76.884 ;
     RECT  21.422 36.224 21.491 37.152 ;
     RECT  21.419 6.396 21.493 7.26 ;
     RECT  20.389 53.568 21.589 53.6 ;
     RECT  21.251 33.28 21.635 34.26 ;
     RECT  21.445 76.596 21.635 77.024 ;
     RECT  21.493 6.272 21.675 7.26 ;
     RECT  21.429 46.912 21.675 50.46 ;
     RECT  21.365 9.728 21.683 19.552 ;
     RECT  21.491 36.224 21.685 37.024 ;
     RECT  21.675 49.024 21.685 50.46 ;
     RECT  21.589 53.504 21.685 53.6 ;
     RECT  20.907 54.996 21.685 55.86 ;
     RECT  21.683 9.728 21.731 18.06 ;
     RECT  20.627 44.196 21.733 45.06 ;
     RECT  21.675 46.912 21.733 47.392 ;
     RECT  21.685 53.504 21.739 55.86 ;
     RECT  21.253 0.128 21.749 2.016 ;
     RECT  20.971 20.928 21.779 24.48 ;
     RECT  21.685 49.024 21.779 52.064 ;
     RECT  21.779 21.184 21.803 24.48 ;
     RECT  21.733 41.6 21.867 41.632 ;
     RECT  21.422 57.728 21.867 58.4 ;
     RECT  21.749 0.128 21.877 2.144 ;
     RECT  21.251 27.996 21.931 31.904 ;
     RECT  21.733 44.196 21.931 47.392 ;
     RECT  21.867 57.728 21.995 58.208 ;
     RECT  21.931 27.996 22.242 31.52 ;
     RECT  21.739 54.72 22.259 55.86 ;
     RECT  21.099 60.396 22.259 61.6 ;
     RECT  21.803 21.312 22.261 24.48 ;
     RECT  22.242 27.712 22.315 31.52 ;
     RECT  21.931 46.784 22.379 47.392 ;
     RECT  22.315 27.84 22.403 31.52 ;
     RECT  21.877 0.128 22.451 2.208 ;
     RECT  22.261 21.312 22.451 25.12 ;
     RECT  20.915 38.796 22.501 39.66 ;
     RECT  22.451 0.128 22.517 2.144 ;
     RECT  22.517 0.064 22.643 2.144 ;
     RECT  22.403 30.4 22.739 31.52 ;
     RECT  21.995 57.728 22.741 57.76 ;
     RECT  21.099 63.296 22.741 63.52 ;
     RECT  20.531 65.796 22.741 66.66 ;
     RECT  22.451 21.312 22.835 24.48 ;
     RECT  22.741 63.296 22.891 66.66 ;
     RECT  22.379 46.784 22.955 46.944 ;
     RECT  21.733 68.416 22.955 68.448 ;
     RECT  21.685 36.032 23.077 37.024 ;
     RECT  22.891 63.296 23.211 63.712 ;
     RECT  22.741 57.6 23.275 57.76 ;
     RECT  21.931 44.196 23.317 45.06 ;
     RECT  22.835 21.312 23.413 23.776 ;
     RECT  23.413 20.416 23.477 23.776 ;
     RECT  22.739 31.36 23.509 31.52 ;
     RECT  21.635 33.396 23.509 34.26 ;
     RECT  21.635 76.596 23.541 76.884 ;
     RECT  23.211 63.424 23.555 63.712 ;
     RECT  23.461 9.28 23.605 9.312 ;
     RECT  21.731 10.816 23.605 18.06 ;
     RECT  22.403 27.84 23.605 28.86 ;
     RECT  23.509 31.36 23.605 34.26 ;
     RECT  23.077 36.032 23.605 37.152 ;
     RECT  22.259 54.996 23.653 55.86 ;
     RECT  23.605 31.36 23.674 37.152 ;
     RECT  23.653 54.72 23.723 55.86 ;
     RECT  22.891 65.344 23.723 66.66 ;
     RECT  23.477 19.968 23.787 23.776 ;
     RECT  23.605 27.072 23.893 28.86 ;
     RECT  22.501 38.796 23.893 40.48 ;
     RECT  22.133 41.792 23.893 42.72 ;
     RECT  21.779 49.024 23.893 51.296 ;
     RECT  23.893 49.024 23.979 51.936 ;
     RECT  23.893 38.796 23.987 42.72 ;
     RECT  23.605 9.28 23.989 18.06 ;
     RECT  23.674 35.904 23.989 37.152 ;
     RECT  23.987 38.796 23.989 41.632 ;
     RECT  23.723 54.996 24.037 55.86 ;
     RECT  23.989 35.904 24.043 41.632 ;
     RECT  23.797 25.216 24.117 25.248 ;
     RECT  23.893 26.88 24.117 29.984 ;
     RECT  23.989 9.28 24.171 18.976 ;
     RECT  24.171 9.28 24.179 18.06 ;
     RECT  23.317 44.196 24.277 45.92 ;
     RECT  24.117 25.216 24.354 29.984 ;
     RECT  23.674 31.36 24.354 34.26 ;
     RECT  23.787 20.288 24.421 23.776 ;
     RECT  24.354 25.216 24.421 34.26 ;
     RECT  23.723 65.796 24.469 66.66 ;
     RECT  24.421 53.568 24.491 53.6 ;
     RECT  24.469 65.796 24.683 66.784 ;
     RECT  22.643 0.064 24.939 1.86 ;
     RECT  24.421 20.288 24.947 34.26 ;
     RECT  24.947 20.288 25.003 30.688 ;
     RECT  25.003 20.288 25.139 30.176 ;
     RECT  24.043 35.904 25.139 39.776 ;
     RECT  25.139 22.596 25.195 30.176 ;
     RECT  25.139 20.288 25.205 21.152 ;
     RECT  23.555 63.488 25.237 63.712 ;
     RECT  24.037 54.996 25.323 57.056 ;
     RECT  24.683 65.796 25.333 66.66 ;
     RECT  25.195 27.84 25.379 30.176 ;
     RECT  25.323 54.996 25.381 55.968 ;
     RECT  25.333 65.024 25.402 66.66 ;
     RECT  25.195 22.596 25.475 26.144 ;
     RECT  24.179 14.912 25.523 18.06 ;
     RECT  24.277 43.904 25.573 45.92 ;
     RECT  25.379 27.84 25.579 29.984 ;
     RECT  24.179 9.28 25.589 12.66 ;
     RECT  25.573 43.328 25.643 45.92 ;
     RECT  22.259 60.396 25.646 61.536 ;
     RECT  25.237 63.424 25.646 63.712 ;
     RECT  25.523 17.196 25.653 18.06 ;
     RECT  25.205 19.392 25.653 21.152 ;
     RECT  25.523 14.912 25.669 15.392 ;
     RECT  25.589 8.576 25.715 12.66 ;
     RECT  25.715 9.28 25.726 12.66 ;
     RECT  25.726 9.28 25.835 9.312 ;
     RECT  25.726 10.688 25.859 12.66 ;
     RECT  25.89 58.816 25.909 58.848 ;
     RECT  25.646 60.396 26.03 63.712 ;
     RECT  24.939 0.128 26.101 1.86 ;
     RECT  24.469 5.056 26.165 5.088 ;
     RECT  21.675 6.396 26.165 7.26 ;
     RECT  26.165 5.056 26.197 7.26 ;
     RECT  25.139 35.904 26.229 39.66 ;
     RECT  25.381 54.08 26.243 55.968 ;
     RECT  26.03 60.396 26.243 63.904 ;
     RECT  25.669 14.656 26.283 15.392 ;
     RECT  25.653 17.196 26.291 21.152 ;
     RECT  25.475 22.596 26.291 26.016 ;
     RECT  24.947 32.384 26.293 34.26 ;
     RECT  26.229 35.648 26.293 39.66 ;
     RECT  26.293 32.384 26.339 39.66 ;
     RECT  26.101 0.128 26.357 2.016 ;
     RECT  26.339 32.384 26.357 35.36 ;
     RECT  26.357 31.36 26.362 35.36 ;
     RECT  24.043 41.6 26.389 41.632 ;
     RECT  26.357 0.064 26.421 2.016 ;
     RECT  25.643 44.196 26.437 45.92 ;
     RECT  26.149 47.424 26.437 47.456 ;
     RECT  26.291 17.196 26.475 19.36 ;
     RECT  26.243 60.396 26.475 63.456 ;
     RECT  23.979 49.024 26.483 50.46 ;
     RECT  26.291 22.596 26.531 24.864 ;
     RECT  26.339 36.928 26.531 39.66 ;
     RECT  26.485 53.568 26.667 53.6 ;
     RECT  26.197 5.056 26.675 7.392 ;
     RECT  25.579 27.84 26.677 29.664 ;
     RECT  26.421 0.064 26.805 2.144 ;
     RECT  26.805 0.064 26.869 2.336 ;
     RECT  26.291 20.992 26.869 21.152 ;
     RECT  26.531 22.596 26.869 24.16 ;
     RECT  26.677 27.392 26.869 29.664 ;
     RECT  26.773 74.688 26.915 74.72 ;
     RECT  26.283 14.784 26.917 15.392 ;
     RECT  26.475 17.196 26.917 19.232 ;
     RECT  26.531 36.992 26.963 39.66 ;
     RECT  26.869 20.992 26.987 24.16 ;
     RECT  26.869 26.624 27.042 29.664 ;
     RECT  25.909 58.048 27.061 58.848 ;
     RECT  26.475 60.396 27.061 62.432 ;
     RECT  26.675 5.056 27.109 7.26 ;
     RECT  25.859 10.944 27.109 12.66 ;
     RECT  27.042 26.624 27.109 30.048 ;
     RECT  26.362 31.36 27.109 35.168 ;
     RECT  26.389 41.536 27.109 41.632 ;
     RECT  26.243 54.996 27.109 55.968 ;
     RECT  27.061 58.048 27.109 62.432 ;
     RECT  25.402 65.796 27.109 66.66 ;
     RECT  27.109 4.992 27.115 7.26 ;
     RECT  26.917 14.784 27.115 19.232 ;
     RECT  27.109 26.624 27.115 35.168 ;
     RECT  26.869 0.064 27.125 2.464 ;
     RECT  27.109 54.996 27.155 62.432 ;
     RECT  27.155 54.996 27.179 58.08 ;
     RECT  27.115 26.752 27.243 35.168 ;
     RECT  27.125 0.064 27.307 2.848 ;
     RECT  27.243 26.816 27.307 35.168 ;
     RECT  27.109 65.024 27.307 66.66 ;
     RECT  27.307 65.536 27.371 66.66 ;
     RECT  26.437 44.196 27.445 47.456 ;
     RECT  23.979 51.904 27.499 51.936 ;
     RECT  27.115 14.912 27.563 19.232 ;
     RECT  27.445 44.196 27.573 47.584 ;
     RECT  26.483 49.596 27.573 50.46 ;
     RECT  26.963 38.796 27.637 39.66 ;
     RECT  27.109 41.024 27.637 41.632 ;
     RECT  27.573 44.196 27.637 47.712 ;
     RECT  27.307 26.816 27.683 29.088 ;
     RECT  27.179 57.6 27.683 58.08 ;
     RECT  27.637 38.796 27.706 41.632 ;
     RECT  27.637 63.872 27.706 63.904 ;
     RECT  27.109 10.944 27.755 13.088 ;
     RECT  27.563 15.04 27.755 19.232 ;
     RECT  27.637 44.196 27.755 47.84 ;
     RECT  27.307 30.528 27.877 35.168 ;
     RECT  27.307 0.064 28.075 2.72 ;
     RECT  27.877 30.528 28.117 35.424 ;
     RECT  26.963 36.992 28.117 37.024 ;
     RECT  28.117 30.528 28.549 37.024 ;
     RECT  27.683 27.008 28.597 29.088 ;
     RECT  28.549 30.528 28.597 37.216 ;
     RECT  27.706 38.796 28.597 39.66 ;
     RECT  27.755 15.424 28.691 19.232 ;
     RECT  27.683 57.6 28.715 57.632 ;
     RECT  26.987 21.312 28.787 24.16 ;
     RECT  28.597 27.008 28.789 37.216 ;
     RECT  28.597 38.592 28.789 39.66 ;
     RECT  28.789 27.008 28.858 39.66 ;
     RECT  28.787 21.696 28.885 24.16 ;
     RECT  28.691 15.424 28.931 18.976 ;
     RECT  27.755 44.196 28.971 46.816 ;
     RECT  28.858 38.592 28.979 39.66 ;
     RECT  27.155 60.396 28.981 62.432 ;
     RECT  28.858 27.008 29.029 37.216 ;
     RECT  27.573 49.596 29.029 50.592 ;
     RECT  28.931 15.936 29.035 18.848 ;
     RECT  28.885 21.696 29.035 24.416 ;
     RECT  29.029 26.88 29.035 37.216 ;
     RECT  28.933 74.688 29.075 74.72 ;
     RECT  28.979 38.796 29.102 39.66 ;
     RECT  27.706 41.024 29.102 41.632 ;
     RECT  27.115 4.992 29.123 5.024 ;
     RECT  29.035 16.128 29.123 18.848 ;
     RECT  29.102 38.796 29.123 41.632 ;
     RECT  29.123 38.796 29.171 40.544 ;
     RECT  27.371 65.796 29.365 66.66 ;
     RECT  29.035 21.696 29.411 23.968 ;
     RECT  29.365 65.024 29.413 66.66 ;
     RECT  29.035 26.88 29.459 37.088 ;
     RECT  27.179 54.996 29.461 55.86 ;
     RECT  29.413 64.448 29.483 66.66 ;
     RECT  28.075 0.256 29.493 2.72 ;
     RECT  29.029 49.596 29.493 51.296 ;
     RECT  27.115 6.396 29.509 7.26 ;
     RECT  28.981 60.396 29.509 63.072 ;
     RECT  29.493 49.596 29.547 51.872 ;
     RECT  29.461 54.144 29.547 55.86 ;
     RECT  29.171 38.796 29.555 39.968 ;
     RECT  29.547 54.996 29.557 55.86 ;
     RECT  29.509 59.136 29.557 63.072 ;
     RECT  29.557 54.996 29.605 55.968 ;
     RECT  29.557 59.136 29.651 63.584 ;
     RECT  28.971 44.196 29.797 46.24 ;
     RECT  29.797 43.328 29.867 46.24 ;
     RECT  29.459 30.72 29.939 37.088 ;
     RECT  29.605 54.996 30.059 57.056 ;
     RECT  29.547 51.84 30.083 51.872 ;
     RECT  29.939 32.896 30.123 37.088 ;
     RECT  29.939 30.72 30.179 31.584 ;
     RECT  27.755 10.944 30.181 12.66 ;
     RECT  29.411 21.696 30.181 23.904 ;
     RECT  29.651 59.136 30.181 63.328 ;
     RECT  29.493 0.128 30.197 2.72 ;
     RECT  30.123 33.28 30.202 37.088 ;
     RECT  29.867 44.196 30.254 46.24 ;
     RECT  29.547 49.596 30.261 50.46 ;
     RECT  30.254 44.196 30.323 46.752 ;
     RECT  30.181 58.816 30.446 63.328 ;
     RECT  30.446 58.688 30.515 63.328 ;
     RECT  30.515 58.816 30.571 63.328 ;
     RECT  29.483 65.536 30.635 66.66 ;
     RECT  30.202 33.28 30.659 36.96 ;
     RECT  30.181 20.544 30.661 23.904 ;
     RECT  30.571 59.136 30.699 63.328 ;
     RECT  30.197 0.128 30.709 2.848 ;
     RECT  30.635 65.796 30.709 66.66 ;
     RECT  30.661 19.52 30.757 23.904 ;
     RECT  30.709 0.064 30.773 2.848 ;
     RECT  29.509 5.568 30.805 7.26 ;
     RECT  29.941 42.176 30.965 42.208 ;
     RECT  29.459 26.88 31.022 29.088 ;
     RECT  29.555 38.796 31.029 39.66 ;
     RECT  30.059 54.996 31.074 56.416 ;
     RECT  31.022 26.24 31.091 29.088 ;
     RECT  30.965 41.6 31.091 42.208 ;
     RECT  29.029 8.704 31.093 8.736 ;
     RECT  30.757 19.52 31.141 24.544 ;
     RECT  30.773 0.064 31.147 3.424 ;
     RECT  31.074 53.952 31.147 56.416 ;
     RECT  31.029 38.796 31.211 40.224 ;
     RECT  31.091 42.176 31.211 42.208 ;
     RECT  30.323 44.196 31.221 46.56 ;
     RECT  30.179 30.784 31.285 31.584 ;
     RECT  31.221 43.008 31.331 46.56 ;
     RECT  31.285 30.784 31.379 31.968 ;
     RECT  30.659 33.28 31.379 36.896 ;
     RECT  31.331 44.196 31.379 46.56 ;
     RECT  31.379 44.196 31.475 46.24 ;
     RECT  31.477 14.208 31.571 14.24 ;
     RECT  30.699 59.136 31.595 62.624 ;
     RECT  30.805 5.568 31.667 7.392 ;
     RECT  31.379 30.784 31.717 30.944 ;
     RECT  31.147 54.996 31.787 55.968 ;
     RECT  30.261 48.704 31.861 50.46 ;
     RECT  31.475 44.196 31.93 45.216 ;
     RECT  31.379 33.28 31.957 36.832 ;
     RECT  31.141 19.52 32.003 24.864 ;
     RECT  23.541 76.596 32.051 77.6 ;
     RECT  30.181 10.56 32.147 12.66 ;
     RECT  31.667 6.396 32.149 7.392 ;
     RECT  31.093 8.704 32.149 9.12 ;
     RECT  32.149 6.396 32.195 9.12 ;
     RECT  32.003 21.12 32.235 24.864 ;
     RECT  31.211 38.796 32.243 39.968 ;
     RECT  31.147 0.064 32.299 2.848 ;
     RECT  32.235 22.596 32.309 24.864 ;
     RECT  32.245 19.392 32.314 19.424 ;
     RECT  32.235 21.12 32.363 21.216 ;
     RECT  32.245 53.568 32.363 53.6 ;
     RECT  30.709 65.796 32.389 67.488 ;
     RECT  31.595 59.52 32.437 62.624 ;
     RECT  32.363 21.12 32.483 21.152 ;
     RECT  32.437 59.52 32.483 62.752 ;
     RECT  32.483 60.396 32.491 62.752 ;
     RECT  32.389 65.664 32.491 67.488 ;
     RECT  31.091 27.008 32.533 29.088 ;
     RECT  31.717 30.72 32.533 30.944 ;
     RECT  32.147 10.944 32.555 12.66 ;
     RECT  32.309 22.596 32.555 25.056 ;
     RECT  31.861 48.448 32.555 50.784 ;
     RECT  32.555 11.328 32.579 12.66 ;
     RECT  32.555 48.448 32.619 50.46 ;
     RECT  32.533 27.008 32.821 30.944 ;
     RECT  31.957 32.512 32.821 36.832 ;
     RECT  32.821 27.008 32.885 36.832 ;
     RECT  32.299 0.256 33.013 2.848 ;
     RECT  32.437 4.352 33.013 4.384 ;
     RECT  32.195 6.396 33.013 8.992 ;
     RECT  32.197 15.36 33.013 15.392 ;
     RECT  32.243 38.796 33.061 39.66 ;
     RECT  33.013 4.352 33.067 8.992 ;
     RECT  33.013 0.256 33.082 2.912 ;
     RECT  33.013 14.656 33.107 15.392 ;
     RECT  33.061 38.336 33.134 39.66 ;
     RECT  32.885 27.008 33.155 36.896 ;
     RECT  33.077 46.784 33.155 46.816 ;
     RECT  33.067 4.544 33.203 8.992 ;
     RECT  33.134 38.208 33.203 39.66 ;
     RECT  32.619 49.024 33.203 50.46 ;
     RECT  33.155 27.008 33.395 36.832 ;
     RECT  32.491 62.72 33.539 62.752 ;
     RECT  33.395 27.008 33.589 35.936 ;
     RECT  33.203 6.208 33.683 8.992 ;
     RECT  32.555 22.596 33.683 24.864 ;
     RECT  17.267 71.196 33.685 72.06 ;
     RECT  33.589 26.816 33.707 35.936 ;
     RECT  33.082 0.256 33.733 2.72 ;
     RECT  32.579 11.796 33.733 12.66 ;
     RECT  33.683 8.96 33.771 8.992 ;
     RECT  32.491 65.796 33.771 67.488 ;
     RECT  33.685 71.196 33.771 72.416 ;
     RECT  33.829 47.296 33.899 47.328 ;
     RECT  33.107 15.36 33.963 15.392 ;
     RECT  33.589 19.968 33.963 20 ;
     RECT  33.909 9.984 33.982 10.016 ;
     RECT  33.707 26.816 34.037 31.392 ;
     RECT  33.733 0.192 34.101 2.72 ;
     RECT  34.037 20.48 34.211 20.512 ;
     RECT  32.051 76.596 34.259 77.472 ;
     RECT  33.707 33.28 34.283 35.936 ;
     RECT  33.203 38.796 34.405 39.66 ;
     RECT  33.589 41.6 34.405 41.632 ;
     RECT  29.123 17.196 34.453 18.06 ;
     RECT  34.405 38.796 34.475 41.632 ;
     RECT  33.683 22.596 34.539 24.48 ;
     RECT  32.491 60.396 34.645 61.26 ;
     RECT  34.037 26.752 34.667 31.392 ;
     RECT  33.733 11.796 34.731 12.896 ;
     RECT  34.645 60.396 34.731 61.6 ;
     RECT  34.101 0.064 34.741 2.72 ;
     RECT  34.283 33.28 34.795 35.36 ;
     RECT  34.475 41.6 34.859 41.632 ;
     RECT  33.061 58.176 34.981 58.208 ;
     RECT  34.731 60.396 34.981 61.26 ;
     RECT  34.933 53.568 35.002 53.6 ;
     RECT  34.981 58.176 35.051 61.26 ;
     RECT  33.203 4.544 35.075 4.576 ;
     RECT  35.051 58.176 35.317 58.208 ;
     RECT  35.317 51.904 35.563 51.936 ;
     RECT  34.667 27.84 35.573 31.392 ;
     RECT  34.795 33.28 35.573 34.26 ;
     RECT  34.741 0.064 35.627 2.848 ;
     RECT  34.837 64.448 35.627 64.48 ;
     RECT  31.93 44.196 35.63 45.06 ;
     RECT  34.741 47.04 35.63 47.072 ;
     RECT  34.453 16 35.699 18.06 ;
     RECT  35.63 44.196 35.699 47.072 ;
     RECT  33.683 6.208 35.701 7.26 ;
     RECT  35.317 57.6 35.755 58.208 ;
     RECT  34.539 22.596 35.845 24.288 ;
     RECT  35.637 8.96 35.883 8.992 ;
     RECT  35.755 57.6 35.883 57.632 ;
     RECT  35.699 47.04 36.011 47.072 ;
     RECT  35.627 0.064 36.075 2.72 ;
     RECT  36.075 0.064 36.139 2.272 ;
     RECT  34.475 38.796 36.181 39.66 ;
     RECT  36.181 37.632 36.267 39.66 ;
     RECT  35.573 27.84 36.421 34.26 ;
     RECT  36.421 26.88 36.515 34.26 ;
     RECT  35.701 5.12 36.587 7.26 ;
     RECT  36.515 26.88 36.651 29.664 ;
     RECT  36.515 31.04 36.779 34.26 ;
     RECT  36.651 27.996 36.971 29.664 ;
     RECT  36.421 21.12 36.997 21.152 ;
     RECT  35.845 22.596 36.997 24.544 ;
     RECT  36.779 32.512 37.163 34.26 ;
     RECT  36.997 21.12 37.227 25.696 ;
     RECT  37.227 25.088 37.355 25.696 ;
     RECT  36.779 31.04 37.427 31.072 ;
     RECT  37.227 21.12 37.675 23.46 ;
     RECT  37.355 25.088 37.739 25.12 ;
     RECT  37.675 21.12 37.803 21.152 ;
     RECT  36.139 0.064 37.861 1.86 ;
     RECT  37.813 30.784 37.882 30.816 ;
     RECT  37.861 0.064 37.995 2.016 ;
     RECT  36.587 6.396 38.16 7.26 ;
     RECT  34.731 11.796 38.16 12.66 ;
     RECT  35.699 17.196 38.16 18.06 ;
     RECT  37.675 22.596 38.16 23.46 ;
     RECT  36.971 27.996 38.16 28.86 ;
     RECT  37.163 33.396 38.16 34.26 ;
     RECT  36.267 38.796 38.16 39.66 ;
     RECT  35.699 44.196 38.16 45.06 ;
     RECT  33.203 49.596 38.16 50.46 ;
     RECT  31.787 54.996 38.16 55.86 ;
     RECT  35.051 60.396 38.16 61.26 ;
     RECT  33.771 65.796 38.16 66.66 ;
     RECT  33.771 71.196 38.16 72.06 ;
     RECT  34.259 76.596 38.16 76.884 ;
     RECT  37.995 0.384 38.339 1.86 ;
     RECT  38.339 0.512 38.675 1.86 ;
     RECT  38.675 1.572 38.944 1.86 ;
     RECT  38.16 6.972 38.944 7.26 ;
     RECT  38.16 12.372 38.944 12.66 ;
     RECT  38.16 17.772 38.944 18.06 ;
     RECT  38.16 23.172 38.944 23.46 ;
     RECT  38.16 28.572 38.944 28.86 ;
     RECT  38.16 33.972 38.944 34.26 ;
     RECT  38.16 39.372 38.944 39.66 ;
     RECT  38.16 44.772 38.944 45.06 ;
     RECT  38.16 50.172 38.944 50.46 ;
     RECT  38.16 55.572 38.944 55.86 ;
     RECT  38.16 60.972 38.944 61.26 ;
     RECT  38.16 66.372 38.944 66.66 ;
     RECT  38.16 71.772 38.944 72.06 ;
    LAYER M7 ;
     RECT  18.752 0.053 19.872 0.117 ;
     RECT  22.528 0.053 22.56 0.117 ;
     RECT  24.896 0.053 24.928 0.117 ;
     RECT  26.368 0.053 26.4 0.117 ;
     RECT  28.032 0.053 28.064 0.117 ;
     RECT  30.72 0.053 30.752 0.117 ;
     RECT  35.904 0.053 36.384 0.117 ;
     RECT  37.952 0.053 37.984 0.117 ;
     RECT  34.112 0.053 34.144 0.181 ;
     RECT  35.904 0.117 37.984 0.181 ;
     RECT  14.4 0.117 16.992 0.245 ;
     RECT  18.752 0.117 28.064 0.245 ;
     RECT  29.504 0.117 30.752 0.245 ;
     RECT  32.256 0.053 32.288 0.245 ;
     RECT  34.112 0.181 37.984 0.245 ;
     RECT  14.144 0.245 37.984 0.373 ;
     RECT  13.824 0.373 38.112 0.437 ;
     RECT  13.632 0.437 38.112 0.531 ;
     RECT  13.632 0.531 38.944 0.821 ;
     RECT  11.656 0.531 11.944 4.981 ;
     RECT  13.568 0.821 38.944 5.621 ;
     RECT  11.392 4.981 11.944 7.925 ;
     RECT  11.328 7.925 11.944 10.347 ;
     RECT  11.656 10.347 11.944 11.637 ;
     RECT  11.392 11.637 11.944 18.165 ;
     RECT  11.136 18.165 11.944 18.805 ;
     RECT  13.504 5.621 38.944 18.805 ;
     RECT  11.136 18.805 12.128 20.213 ;
     RECT  13.44 18.805 38.944 20.213 ;
     RECT  11.136 20.213 38.944 20.725 ;
     RECT  11.008 20.725 38.944 28.981 ;
     RECT  10.88 28.981 38.944 30.827 ;
     RECT  10.88 30.827 37.152 31.403 ;
     RECT  11.008 31.403 37.152 32.555 ;
     RECT  11.008 32.555 36.256 37.675 ;
     RECT  11.008 37.675 36 47.083 ;
     RECT  11.008 47.083 35.872 55.979 ;
     RECT  11.072 55.979 35.872 57.643 ;
     RECT  11.072 57.643 35.808 61.611 ;
     RECT  11.072 61.611 33.544 62.709 ;
     RECT  10.88 62.709 33.544 62.891 ;
     RECT  11.072 62.891 33.544 63.339 ;
     RECT  22.456 63.339 33.544 63.915 ;
     RECT  34.88 61.611 35.808 64.491 ;
     RECT  11.072 63.339 20.512 65.067 ;
     RECT  22.456 63.915 25.376 65.067 ;
     RECT  27.264 63.915 33.544 65.067 ;
     RECT  11.072 65.067 15.712 65.579 ;
     RECT  19.456 65.067 19.808 65.579 ;
     RECT  27.328 65.067 28.144 65.579 ;
     RECT  29.696 65.067 33.544 65.579 ;
     RECT  19.52 65.579 19.808 65.707 ;
     RECT  22.456 65.067 24.8 66.165 ;
     RECT  21.824 66.165 24.8 66.219 ;
     RECT  31.808 65.579 33.544 66.219 ;
     RECT  33.256 66.219 33.544 66.229 ;
     RECT  21.824 66.219 24.672 66.795 ;
     RECT  11.072 65.579 15.52 67.307 ;
     RECT  19.52 65.707 19.552 67.307 ;
     RECT  11.072 67.307 13.152 67.499 ;
     RECT  17.056 65.067 18.144 67.765 ;
     RECT  11.072 67.499 12.704 68.011 ;
     RECT  21.824 66.795 23.584 68.459 ;
     RECT  16.896 67.765 18.144 69.035 ;
     RECT  35.776 64.491 35.808 71.659 ;
     RECT  15.424 67.307 15.52 72.427 ;
     RECT  33.256 66.229 33.76 72.427 ;
     RECT  11.52 68.011 12.704 73.259 ;
     RECT  11.52 73.259 11.944 73.579 ;
     RECT  15.424 72.427 15.456 75.883 ;
     RECT  0.856 0.531 1.144 76.959 ;
     RECT  6.256 0.531 6.544 76.959 ;
     RECT  11.656 73.579 11.944 76.959 ;
     RECT  17.056 69.035 17.344 76.959 ;
     RECT  22.456 68.459 23.584 76.959 ;
     RECT  27.856 65.579 28.144 76.959 ;
     RECT  33.256 72.427 33.544 76.959 ;
     RECT  38.656 30.827 38.944 76.959 ;
     RECT  31.04 77.045 31.072 77.173 ;
     RECT  31.04 77.173 31.264 77.237 ;
     RECT  30.912 77.237 31.264 77.419 ;
     RECT  31.04 77.419 31.264 77.483 ;
     RECT  23.552 76.959 23.584 77.611 ;
  END
END hfd_stn_r36
END LIBRARY
